VERSION 5.8 ;
BUSBITCHARS "[]" ;
DIVIDERCHAR "/" ;
UNITS
    DATABASE MICRONS 1000 ;
END UNITS

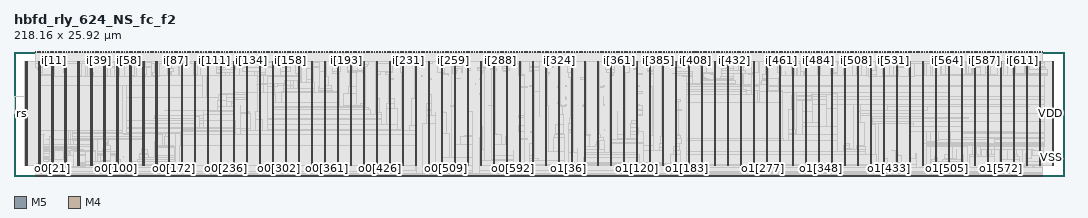
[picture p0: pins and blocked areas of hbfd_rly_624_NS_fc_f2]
MACRO hbfd_rly_624_NS_fc_f2
  FOREIGN hbfd_rly_624_NS_fc_f2 0 0 ;
  CLASS BLOCK ;
  SIZE 218.16 BY 25.92 ;
  PIN clk_in
    DIRECTION INPUT ;
    USE SIGNAL ;
    PORT
      LAYER M5 ;
        RECT  109.056 25.728 109.08 25.92 ;
    END
  END clk_in
  PIN clk_out0
    DIRECTION OUTPUT ;
    USE SIGNAL ;
    PORT
      LAYER M5 ;
        RECT  56.688 0 56.712 0.192 ;
    END
  END clk_out0
  PIN clk_out1
    DIRECTION OUTPUT ;
    USE SIGNAL ;
    PORT
      LAYER M5 ;
        RECT  161.424 0 161.448 0.192 ;
    END
  END clk_out1
  PIN i[0]
    DIRECTION INPUT ;
    USE SIGNAL ;
    PORT
      LAYER M5 ;
        RECT  4.512 25.728 4.536 25.92 ;
    END
  END i[0]
  PIN i[100]
    DIRECTION INPUT ;
    USE SIGNAL ;
    PORT
      LAYER M5 ;
        RECT  38.016 25.728 38.04 25.92 ;
    END
  END i[100]
  PIN i[101]
    DIRECTION INPUT ;
    USE SIGNAL ;
    PORT
      LAYER M5 ;
        RECT  38.352 25.728 38.376 25.92 ;
    END
  END i[101]
  PIN i[102]
    DIRECTION INPUT ;
    USE SIGNAL ;
    PORT
      LAYER M5 ;
        RECT  38.688 25.728 38.712 25.92 ;
    END
  END i[102]
  PIN i[103]
    DIRECTION INPUT ;
    USE SIGNAL ;
    PORT
      LAYER M5 ;
        RECT  39.024 25.728 39.048 25.92 ;
    END
  END i[103]
  PIN i[104]
    DIRECTION INPUT ;
    USE SIGNAL ;
    PORT
      LAYER M5 ;
        RECT  39.36 25.728 39.384 25.92 ;
    END
  END i[104]
  PIN i[105]
    DIRECTION INPUT ;
    USE SIGNAL ;
    PORT
      LAYER M5 ;
        RECT  39.696 25.728 39.72 25.92 ;
    END
  END i[105]
  PIN i[106]
    DIRECTION INPUT ;
    USE SIGNAL ;
    PORT
      LAYER M5 ;
        RECT  40.032 25.728 40.056 25.92 ;
    END
  END i[106]
  PIN i[107]
    DIRECTION INPUT ;
    USE SIGNAL ;
    PORT
      LAYER M5 ;
        RECT  40.368 25.728 40.392 25.92 ;
    END
  END i[107]
  PIN i[108]
    DIRECTION INPUT ;
    USE SIGNAL ;
    PORT
      LAYER M5 ;
        RECT  40.704 25.728 40.728 25.92 ;
    END
  END i[108]
  PIN i[109]
    DIRECTION INPUT ;
    USE SIGNAL ;
    PORT
      LAYER M5 ;
        RECT  41.04 25.728 41.064 25.92 ;
    END
  END i[109]
  PIN i[10]
    DIRECTION INPUT ;
    USE SIGNAL ;
    PORT
      LAYER M5 ;
        RECT  7.872 25.728 7.896 25.92 ;
    END
  END i[10]
  PIN i[110]
    DIRECTION INPUT ;
    USE SIGNAL ;
    PORT
      LAYER M5 ;
        RECT  41.376 25.728 41.4 25.92 ;
    END
  END i[110]
  PIN i[111]
    DIRECTION INPUT ;
    USE SIGNAL ;
    PORT
      LAYER M5 ;
        RECT  41.712 25.728 41.736 25.92 ;
    END
  END i[111]
  PIN i[112]
    DIRECTION INPUT ;
    USE SIGNAL ;
    PORT
      LAYER M5 ;
        RECT  42.048 25.728 42.072 25.92 ;
    END
  END i[112]
  PIN i[113]
    DIRECTION INPUT ;
    USE SIGNAL ;
    PORT
      LAYER M5 ;
        RECT  42.384 25.728 42.408 25.92 ;
    END
  END i[113]
  PIN i[114]
    DIRECTION INPUT ;
    USE SIGNAL ;
    PORT
      LAYER M5 ;
        RECT  42.72 25.728 42.744 25.92 ;
    END
  END i[114]
  PIN i[115]
    DIRECTION INPUT ;
    USE SIGNAL ;
    PORT
      LAYER M5 ;
        RECT  43.056 25.728 43.08 25.92 ;
    END
  END i[115]
  PIN i[116]
    DIRECTION INPUT ;
    USE SIGNAL ;
    PORT
      LAYER M5 ;
        RECT  43.392 25.728 43.416 25.92 ;
    END
  END i[116]
  PIN i[117]
    DIRECTION INPUT ;
    USE SIGNAL ;
    PORT
      LAYER M5 ;
        RECT  43.728 25.728 43.752 25.92 ;
    END
  END i[117]
  PIN i[118]
    DIRECTION INPUT ;
    USE SIGNAL ;
    PORT
      LAYER M5 ;
        RECT  44.064 25.728 44.088 25.92 ;
    END
  END i[118]
  PIN i[119]
    DIRECTION INPUT ;
    USE SIGNAL ;
    PORT
      LAYER M5 ;
        RECT  44.4 25.728 44.424 25.92 ;
    END
  END i[119]
  PIN i[11]
    DIRECTION INPUT ;
    USE SIGNAL ;
    PORT
      LAYER M5 ;
        RECT  8.208 25.728 8.232 25.92 ;
    END
  END i[11]
  PIN i[120]
    DIRECTION INPUT ;
    USE SIGNAL ;
    PORT
      LAYER M5 ;
        RECT  44.736 25.728 44.76 25.92 ;
    END
  END i[120]
  PIN i[121]
    DIRECTION INPUT ;
    USE SIGNAL ;
    PORT
      LAYER M5 ;
        RECT  45.072 25.728 45.096 25.92 ;
    END
  END i[121]
  PIN i[122]
    DIRECTION INPUT ;
    USE SIGNAL ;
    PORT
      LAYER M5 ;
        RECT  45.408 25.728 45.432 25.92 ;
    END
  END i[122]
  PIN i[123]
    DIRECTION INPUT ;
    USE SIGNAL ;
    PORT
      LAYER M5 ;
        RECT  45.744 25.728 45.768 25.92 ;
    END
  END i[123]
  PIN i[124]
    DIRECTION INPUT ;
    USE SIGNAL ;
    PORT
      LAYER M5 ;
        RECT  46.08 25.728 46.104 25.92 ;
    END
  END i[124]
  PIN i[125]
    DIRECTION INPUT ;
    USE SIGNAL ;
    PORT
      LAYER M5 ;
        RECT  46.416 25.728 46.44 25.92 ;
    END
  END i[125]
  PIN i[126]
    DIRECTION INPUT ;
    USE SIGNAL ;
    PORT
      LAYER M5 ;
        RECT  46.752 25.728 46.776 25.92 ;
    END
  END i[126]
  PIN i[127]
    DIRECTION INPUT ;
    USE SIGNAL ;
    PORT
      LAYER M5 ;
        RECT  47.088 25.728 47.112 25.92 ;
    END
  END i[127]
  PIN i[128]
    DIRECTION INPUT ;
    USE SIGNAL ;
    PORT
      LAYER M5 ;
        RECT  47.424 25.728 47.448 25.92 ;
    END
  END i[128]
  PIN i[129]
    DIRECTION INPUT ;
    USE SIGNAL ;
    PORT
      LAYER M5 ;
        RECT  47.76 25.728 47.784 25.92 ;
    END
  END i[129]
  PIN i[12]
    DIRECTION INPUT ;
    USE SIGNAL ;
    PORT
      LAYER M5 ;
        RECT  8.544 25.728 8.568 25.92 ;
    END
  END i[12]
  PIN i[130]
    DIRECTION INPUT ;
    USE SIGNAL ;
    PORT
      LAYER M5 ;
        RECT  48.096 25.728 48.12 25.92 ;
    END
  END i[130]
  PIN i[131]
    DIRECTION INPUT ;
    USE SIGNAL ;
    PORT
      LAYER M5 ;
        RECT  48.432 25.728 48.456 25.92 ;
    END
  END i[131]
  PIN i[132]
    DIRECTION INPUT ;
    USE SIGNAL ;
    PORT
      LAYER M5 ;
        RECT  48.768 25.728 48.792 25.92 ;
    END
  END i[132]
  PIN i[133]
    DIRECTION INPUT ;
    USE SIGNAL ;
    PORT
      LAYER M5 ;
        RECT  49.104 25.728 49.128 25.92 ;
    END
  END i[133]
  PIN i[134]
    DIRECTION INPUT ;
    USE SIGNAL ;
    PORT
      LAYER M5 ;
        RECT  49.392 25.728 49.416 25.92 ;
    END
  END i[134]
  PIN i[135]
    DIRECTION INPUT ;
    USE SIGNAL ;
    PORT
      LAYER M5 ;
        RECT  49.728 25.728 49.752 25.92 ;
    END
  END i[135]
  PIN i[136]
    DIRECTION INPUT ;
    USE SIGNAL ;
    PORT
      LAYER M5 ;
        RECT  50.064 25.728 50.088 25.92 ;
    END
  END i[136]
  PIN i[137]
    DIRECTION INPUT ;
    USE SIGNAL ;
    PORT
      LAYER M5 ;
        RECT  50.4 25.728 50.424 25.92 ;
    END
  END i[137]
  PIN i[138]
    DIRECTION INPUT ;
    USE SIGNAL ;
    PORT
      LAYER M5 ;
        RECT  50.736 25.728 50.76 25.92 ;
    END
  END i[138]
  PIN i[139]
    DIRECTION INPUT ;
    USE SIGNAL ;
    PORT
      LAYER M5 ;
        RECT  51.072 25.728 51.096 25.92 ;
    END
  END i[139]
  PIN i[13]
    DIRECTION INPUT ;
    USE SIGNAL ;
    PORT
      LAYER M5 ;
        RECT  8.88 25.728 8.904 25.92 ;
    END
  END i[13]
  PIN i[140]
    DIRECTION INPUT ;
    USE SIGNAL ;
    PORT
      LAYER M5 ;
        RECT  51.408 25.728 51.432 25.92 ;
    END
  END i[140]
  PIN i[141]
    DIRECTION INPUT ;
    USE SIGNAL ;
    PORT
      LAYER M5 ;
        RECT  51.744 25.728 51.768 25.92 ;
    END
  END i[141]
  PIN i[142]
    DIRECTION INPUT ;
    USE SIGNAL ;
    PORT
      LAYER M5 ;
        RECT  52.08 25.728 52.104 25.92 ;
    END
  END i[142]
  PIN i[143]
    DIRECTION INPUT ;
    USE SIGNAL ;
    PORT
      LAYER M5 ;
        RECT  52.416 25.728 52.44 25.92 ;
    END
  END i[143]
  PIN i[144]
    DIRECTION INPUT ;
    USE SIGNAL ;
    PORT
      LAYER M5 ;
        RECT  52.752 25.728 52.776 25.92 ;
    END
  END i[144]
  PIN i[145]
    DIRECTION INPUT ;
    USE SIGNAL ;
    PORT
      LAYER M5 ;
        RECT  53.088 25.728 53.112 25.92 ;
    END
  END i[145]
  PIN i[146]
    DIRECTION INPUT ;
    USE SIGNAL ;
    PORT
      LAYER M5 ;
        RECT  53.424 25.728 53.448 25.92 ;
    END
  END i[146]
  PIN i[147]
    DIRECTION INPUT ;
    USE SIGNAL ;
    PORT
      LAYER M5 ;
        RECT  53.76 25.728 53.784 25.92 ;
    END
  END i[147]
  PIN i[148]
    DIRECTION INPUT ;
    USE SIGNAL ;
    PORT
      LAYER M5 ;
        RECT  54.096 25.728 54.12 25.92 ;
    END
  END i[148]
  PIN i[149]
    DIRECTION INPUT ;
    USE SIGNAL ;
    PORT
      LAYER M5 ;
        RECT  54.432 25.728 54.456 25.92 ;
    END
  END i[149]
  PIN i[14]
    DIRECTION INPUT ;
    USE SIGNAL ;
    PORT
      LAYER M5 ;
        RECT  9.216 25.728 9.24 25.92 ;
    END
  END i[14]
  PIN i[150]
    DIRECTION INPUT ;
    USE SIGNAL ;
    PORT
      LAYER M5 ;
        RECT  54.768 25.728 54.792 25.92 ;
    END
  END i[150]
  PIN i[151]
    DIRECTION INPUT ;
    USE SIGNAL ;
    PORT
      LAYER M5 ;
        RECT  55.104 25.728 55.128 25.92 ;
    END
  END i[151]
  PIN i[152]
    DIRECTION INPUT ;
    USE SIGNAL ;
    PORT
      LAYER M5 ;
        RECT  55.44 25.728 55.464 25.92 ;
    END
  END i[152]
  PIN i[153]
    DIRECTION INPUT ;
    USE SIGNAL ;
    PORT
      LAYER M5 ;
        RECT  55.776 25.728 55.8 25.92 ;
    END
  END i[153]
  PIN i[154]
    DIRECTION INPUT ;
    USE SIGNAL ;
    PORT
      LAYER M5 ;
        RECT  56.112 25.728 56.136 25.92 ;
    END
  END i[154]
  PIN i[155]
    DIRECTION INPUT ;
    USE SIGNAL ;
    PORT
      LAYER M5 ;
        RECT  56.448 25.728 56.472 25.92 ;
    END
  END i[155]
  PIN i[156]
    DIRECTION INPUT ;
    USE SIGNAL ;
    PORT
      LAYER M5 ;
        RECT  56.784 25.728 56.808 25.92 ;
    END
  END i[156]
  PIN i[157]
    DIRECTION INPUT ;
    USE SIGNAL ;
    PORT
      LAYER M5 ;
        RECT  57.12 25.728 57.144 25.92 ;
    END
  END i[157]
  PIN i[158]
    DIRECTION INPUT ;
    USE SIGNAL ;
    PORT
      LAYER M5 ;
        RECT  57.456 25.728 57.48 25.92 ;
    END
  END i[158]
  PIN i[159]
    DIRECTION INPUT ;
    USE SIGNAL ;
    PORT
      LAYER M5 ;
        RECT  57.792 25.728 57.816 25.92 ;
    END
  END i[159]
  PIN i[15]
    DIRECTION INPUT ;
    USE SIGNAL ;
    PORT
      LAYER M5 ;
        RECT  9.552 25.728 9.576 25.92 ;
    END
  END i[15]
  PIN i[160]
    DIRECTION INPUT ;
    USE SIGNAL ;
    PORT
      LAYER M5 ;
        RECT  58.128 25.728 58.152 25.92 ;
    END
  END i[160]
  PIN i[161]
    DIRECTION INPUT ;
    USE SIGNAL ;
    PORT
      LAYER M5 ;
        RECT  58.464 25.728 58.488 25.92 ;
    END
  END i[161]
  PIN i[162]
    DIRECTION INPUT ;
    USE SIGNAL ;
    PORT
      LAYER M5 ;
        RECT  58.8 25.728 58.824 25.92 ;
    END
  END i[162]
  PIN i[163]
    DIRECTION INPUT ;
    USE SIGNAL ;
    PORT
      LAYER M5 ;
        RECT  59.136 25.728 59.16 25.92 ;
    END
  END i[163]
  PIN i[164]
    DIRECTION INPUT ;
    USE SIGNAL ;
    PORT
      LAYER M5 ;
        RECT  59.472 25.728 59.496 25.92 ;
    END
  END i[164]
  PIN i[165]
    DIRECTION INPUT ;
    USE SIGNAL ;
    PORT
      LAYER M5 ;
        RECT  59.808 25.728 59.832 25.92 ;
    END
  END i[165]
  PIN i[166]
    DIRECTION INPUT ;
    USE SIGNAL ;
    PORT
      LAYER M5 ;
        RECT  60.144 25.728 60.168 25.92 ;
    END
  END i[166]
  PIN i[167]
    DIRECTION INPUT ;
    USE SIGNAL ;
    PORT
      LAYER M5 ;
        RECT  60.48 25.728 60.504 25.92 ;
    END
  END i[167]
  PIN i[168]
    DIRECTION INPUT ;
    USE SIGNAL ;
    PORT
      LAYER M5 ;
        RECT  60.816 25.728 60.84 25.92 ;
    END
  END i[168]
  PIN i[169]
    DIRECTION INPUT ;
    USE SIGNAL ;
    PORT
      LAYER M5 ;
        RECT  61.152 25.728 61.176 25.92 ;
    END
  END i[169]
  PIN i[16]
    DIRECTION INPUT ;
    USE SIGNAL ;
    PORT
      LAYER M5 ;
        RECT  9.888 25.728 9.912 25.92 ;
    END
  END i[16]
  PIN i[170]
    DIRECTION INPUT ;
    USE SIGNAL ;
    PORT
      LAYER M5 ;
        RECT  61.488 25.728 61.512 25.92 ;
    END
  END i[170]
  PIN i[171]
    DIRECTION INPUT ;
    USE SIGNAL ;
    PORT
      LAYER M5 ;
        RECT  61.824 25.728 61.848 25.92 ;
    END
  END i[171]
  PIN i[172]
    DIRECTION INPUT ;
    USE SIGNAL ;
    PORT
      LAYER M5 ;
        RECT  62.16 25.728 62.184 25.92 ;
    END
  END i[172]
  PIN i[173]
    DIRECTION INPUT ;
    USE SIGNAL ;
    PORT
      LAYER M5 ;
        RECT  62.496 25.728 62.52 25.92 ;
    END
  END i[173]
  PIN i[174]
    DIRECTION INPUT ;
    USE SIGNAL ;
    PORT
      LAYER M5 ;
        RECT  62.832 25.728 62.856 25.92 ;
    END
  END i[174]
  PIN i[175]
    DIRECTION INPUT ;
    USE SIGNAL ;
    PORT
      LAYER M5 ;
        RECT  63.168 25.728 63.192 25.92 ;
    END
  END i[175]
  PIN i[176]
    DIRECTION INPUT ;
    USE SIGNAL ;
    PORT
      LAYER M5 ;
        RECT  63.504 25.728 63.528 25.92 ;
    END
  END i[176]
  PIN i[177]
    DIRECTION INPUT ;
    USE SIGNAL ;
    PORT
      LAYER M5 ;
        RECT  63.84 25.728 63.864 25.92 ;
    END
  END i[177]
  PIN i[178]
    DIRECTION INPUT ;
    USE SIGNAL ;
    PORT
      LAYER M5 ;
        RECT  64.176 25.728 64.2 25.92 ;
    END
  END i[178]
  PIN i[179]
    DIRECTION INPUT ;
    USE SIGNAL ;
    PORT
      LAYER M5 ;
        RECT  64.512 25.728 64.536 25.92 ;
    END
  END i[179]
  PIN i[17]
    DIRECTION INPUT ;
    USE SIGNAL ;
    PORT
      LAYER M5 ;
        RECT  10.224 25.728 10.248 25.92 ;
    END
  END i[17]
  PIN i[180]
    DIRECTION INPUT ;
    USE SIGNAL ;
    PORT
      LAYER M5 ;
        RECT  64.848 25.728 64.872 25.92 ;
    END
  END i[180]
  PIN i[181]
    DIRECTION INPUT ;
    USE SIGNAL ;
    PORT
      LAYER M5 ;
        RECT  65.184 25.728 65.208 25.92 ;
    END
  END i[181]
  PIN i[182]
    DIRECTION INPUT ;
    USE SIGNAL ;
    PORT
      LAYER M5 ;
        RECT  65.52 25.728 65.544 25.92 ;
    END
  END i[182]
  PIN i[183]
    DIRECTION INPUT ;
    USE SIGNAL ;
    PORT
      LAYER M5 ;
        RECT  65.856 25.728 65.88 25.92 ;
    END
  END i[183]
  PIN i[184]
    DIRECTION INPUT ;
    USE SIGNAL ;
    PORT
      LAYER M5 ;
        RECT  66.192 25.728 66.216 25.92 ;
    END
  END i[184]
  PIN i[185]
    DIRECTION INPUT ;
    USE SIGNAL ;
    PORT
      LAYER M5 ;
        RECT  66.528 25.728 66.552 25.92 ;
    END
  END i[185]
  PIN i[186]
    DIRECTION INPUT ;
    USE SIGNAL ;
    PORT
      LAYER M5 ;
        RECT  66.864 25.728 66.888 25.92 ;
    END
  END i[186]
  PIN i[187]
    DIRECTION INPUT ;
    USE SIGNAL ;
    PORT
      LAYER M5 ;
        RECT  67.2 25.728 67.224 25.92 ;
    END
  END i[187]
  PIN i[188]
    DIRECTION INPUT ;
    USE SIGNAL ;
    PORT
      LAYER M5 ;
        RECT  67.536 25.728 67.56 25.92 ;
    END
  END i[188]
  PIN i[189]
    DIRECTION INPUT ;
    USE SIGNAL ;
    PORT
      LAYER M5 ;
        RECT  67.824 25.728 67.848 25.92 ;
    END
  END i[189]
  PIN i[18]
    DIRECTION INPUT ;
    USE SIGNAL ;
    PORT
      LAYER M5 ;
        RECT  10.56 25.728 10.584 25.92 ;
    END
  END i[18]
  PIN i[190]
    DIRECTION INPUT ;
    USE SIGNAL ;
    PORT
      LAYER M5 ;
        RECT  68.16 25.728 68.184 25.92 ;
    END
  END i[190]
  PIN i[191]
    DIRECTION INPUT ;
    USE SIGNAL ;
    PORT
      LAYER M5 ;
        RECT  68.496 25.728 68.52 25.92 ;
    END
  END i[191]
  PIN i[192]
    DIRECTION INPUT ;
    USE SIGNAL ;
    PORT
      LAYER M5 ;
        RECT  68.832 25.728 68.856 25.92 ;
    END
  END i[192]
  PIN i[193]
    DIRECTION INPUT ;
    USE SIGNAL ;
    PORT
      LAYER M5 ;
        RECT  69.168 25.728 69.192 25.92 ;
    END
  END i[193]
  PIN i[194]
    DIRECTION INPUT ;
    USE SIGNAL ;
    PORT
      LAYER M5 ;
        RECT  69.504 25.728 69.528 25.92 ;
    END
  END i[194]
  PIN i[195]
    DIRECTION INPUT ;
    USE SIGNAL ;
    PORT
      LAYER M5 ;
        RECT  69.84 25.728 69.864 25.92 ;
    END
  END i[195]
  PIN i[196]
    DIRECTION INPUT ;
    USE SIGNAL ;
    PORT
      LAYER M5 ;
        RECT  70.176 25.728 70.2 25.92 ;
    END
  END i[196]
  PIN i[197]
    DIRECTION INPUT ;
    USE SIGNAL ;
    PORT
      LAYER M5 ;
        RECT  70.512 25.728 70.536 25.92 ;
    END
  END i[197]
  PIN i[198]
    DIRECTION INPUT ;
    USE SIGNAL ;
    PORT
      LAYER M5 ;
        RECT  70.848 25.728 70.872 25.92 ;
    END
  END i[198]
  PIN i[199]
    DIRECTION INPUT ;
    USE SIGNAL ;
    PORT
      LAYER M5 ;
        RECT  71.184 25.728 71.208 25.92 ;
    END
  END i[199]
  PIN i[19]
    DIRECTION INPUT ;
    USE SIGNAL ;
    PORT
      LAYER M5 ;
        RECT  10.896 25.728 10.92 25.92 ;
    END
  END i[19]
  PIN i[1]
    DIRECTION INPUT ;
    USE SIGNAL ;
    PORT
      LAYER M5 ;
        RECT  4.848 25.728 4.872 25.92 ;
    END
  END i[1]
  PIN i[200]
    DIRECTION INPUT ;
    USE SIGNAL ;
    PORT
      LAYER M5 ;
        RECT  71.52 25.728 71.544 25.92 ;
    END
  END i[200]
  PIN i[201]
    DIRECTION INPUT ;
    USE SIGNAL ;
    PORT
      LAYER M5 ;
        RECT  71.856 25.728 71.88 25.92 ;
    END
  END i[201]
  PIN i[202]
    DIRECTION INPUT ;
    USE SIGNAL ;
    PORT
      LAYER M5 ;
        RECT  72.192 25.728 72.216 25.92 ;
    END
  END i[202]
  PIN i[203]
    DIRECTION INPUT ;
    USE SIGNAL ;
    PORT
      LAYER M5 ;
        RECT  72.528 25.728 72.552 25.92 ;
    END
  END i[203]
  PIN i[204]
    DIRECTION INPUT ;
    USE SIGNAL ;
    PORT
      LAYER M5 ;
        RECT  72.864 25.728 72.888 25.92 ;
    END
  END i[204]
  PIN i[205]
    DIRECTION INPUT ;
    USE SIGNAL ;
    PORT
      LAYER M5 ;
        RECT  73.2 25.728 73.224 25.92 ;
    END
  END i[205]
  PIN i[206]
    DIRECTION INPUT ;
    USE SIGNAL ;
    PORT
      LAYER M5 ;
        RECT  73.536 25.728 73.56 25.92 ;
    END
  END i[206]
  PIN i[207]
    DIRECTION INPUT ;
    USE SIGNAL ;
    PORT
      LAYER M5 ;
        RECT  73.872 25.728 73.896 25.92 ;
    END
  END i[207]
  PIN i[208]
    DIRECTION INPUT ;
    USE SIGNAL ;
    PORT
      LAYER M5 ;
        RECT  74.208 25.728 74.232 25.92 ;
    END
  END i[208]
  PIN i[209]
    DIRECTION INPUT ;
    USE SIGNAL ;
    PORT
      LAYER M5 ;
        RECT  74.544 25.728 74.568 25.92 ;
    END
  END i[209]
  PIN i[20]
    DIRECTION INPUT ;
    USE SIGNAL ;
    PORT
      LAYER M5 ;
        RECT  11.232 25.728 11.256 25.92 ;
    END
  END i[20]
  PIN i[210]
    DIRECTION INPUT ;
    USE SIGNAL ;
    PORT
      LAYER M5 ;
        RECT  74.88 25.728 74.904 25.92 ;
    END
  END i[210]
  PIN i[211]
    DIRECTION INPUT ;
    USE SIGNAL ;
    PORT
      LAYER M5 ;
        RECT  75.216 25.728 75.24 25.92 ;
    END
  END i[211]
  PIN i[212]
    DIRECTION INPUT ;
    USE SIGNAL ;
    PORT
      LAYER M5 ;
        RECT  75.552 25.728 75.576 25.92 ;
    END
  END i[212]
  PIN i[213]
    DIRECTION INPUT ;
    USE SIGNAL ;
    PORT
      LAYER M5 ;
        RECT  75.888 25.728 75.912 25.92 ;
    END
  END i[213]
  PIN i[214]
    DIRECTION INPUT ;
    USE SIGNAL ;
    PORT
      LAYER M5 ;
        RECT  76.224 25.728 76.248 25.92 ;
    END
  END i[214]
  PIN i[215]
    DIRECTION INPUT ;
    USE SIGNAL ;
    PORT
      LAYER M5 ;
        RECT  76.56 25.728 76.584 25.92 ;
    END
  END i[215]
  PIN i[216]
    DIRECTION INPUT ;
    USE SIGNAL ;
    PORT
      LAYER M5 ;
        RECT  76.896 25.728 76.92 25.92 ;
    END
  END i[216]
  PIN i[217]
    DIRECTION INPUT ;
    USE SIGNAL ;
    PORT
      LAYER M5 ;
        RECT  77.232 25.728 77.256 25.92 ;
    END
  END i[217]
  PIN i[218]
    DIRECTION INPUT ;
    USE SIGNAL ;
    PORT
      LAYER M5 ;
        RECT  77.568 25.728 77.592 25.92 ;
    END
  END i[218]
  PIN i[219]
    DIRECTION INPUT ;
    USE SIGNAL ;
    PORT
      LAYER M5 ;
        RECT  77.904 25.728 77.928 25.92 ;
    END
  END i[219]
  PIN i[21]
    DIRECTION INPUT ;
    USE SIGNAL ;
    PORT
      LAYER M5 ;
        RECT  11.568 25.728 11.592 25.92 ;
    END
  END i[21]
  PIN i[220]
    DIRECTION INPUT ;
    USE SIGNAL ;
    PORT
      LAYER M5 ;
        RECT  78.24 25.728 78.264 25.92 ;
    END
  END i[220]
  PIN i[221]
    DIRECTION INPUT ;
    USE SIGNAL ;
    PORT
      LAYER M5 ;
        RECT  78.576 25.728 78.6 25.92 ;
    END
  END i[221]
  PIN i[222]
    DIRECTION INPUT ;
    USE SIGNAL ;
    PORT
      LAYER M5 ;
        RECT  78.912 25.728 78.936 25.92 ;
    END
  END i[222]
  PIN i[223]
    DIRECTION INPUT ;
    USE SIGNAL ;
    PORT
      LAYER M5 ;
        RECT  79.248 25.728 79.272 25.92 ;
    END
  END i[223]
  PIN i[224]
    DIRECTION INPUT ;
    USE SIGNAL ;
    PORT
      LAYER M5 ;
        RECT  79.584 25.728 79.608 25.92 ;
    END
  END i[224]
  PIN i[225]
    DIRECTION INPUT ;
    USE SIGNAL ;
    PORT
      LAYER M5 ;
        RECT  79.92 25.728 79.944 25.92 ;
    END
  END i[225]
  PIN i[226]
    DIRECTION INPUT ;
    USE SIGNAL ;
    PORT
      LAYER M5 ;
        RECT  80.256 25.728 80.28 25.92 ;
    END
  END i[226]
  PIN i[227]
    DIRECTION INPUT ;
    USE SIGNAL ;
    PORT
      LAYER M5 ;
        RECT  80.592 25.728 80.616 25.92 ;
    END
  END i[227]
  PIN i[228]
    DIRECTION INPUT ;
    USE SIGNAL ;
    PORT
      LAYER M5 ;
        RECT  80.928 25.728 80.952 25.92 ;
    END
  END i[228]
  PIN i[229]
    DIRECTION INPUT ;
    USE SIGNAL ;
    PORT
      LAYER M5 ;
        RECT  81.264 25.728 81.288 25.92 ;
    END
  END i[229]
  PIN i[22]
    DIRECTION INPUT ;
    USE SIGNAL ;
    PORT
      LAYER M5 ;
        RECT  11.904 25.728 11.928 25.92 ;
    END
  END i[22]
  PIN i[230]
    DIRECTION INPUT ;
    USE SIGNAL ;
    PORT
      LAYER M5 ;
        RECT  81.6 25.728 81.624 25.92 ;
    END
  END i[230]
  PIN i[231]
    DIRECTION INPUT ;
    USE SIGNAL ;
    PORT
      LAYER M5 ;
        RECT  81.936 25.728 81.96 25.92 ;
    END
  END i[231]
  PIN i[232]
    DIRECTION INPUT ;
    USE SIGNAL ;
    PORT
      LAYER M5 ;
        RECT  82.272 25.728 82.296 25.92 ;
    END
  END i[232]
  PIN i[233]
    DIRECTION INPUT ;
    USE SIGNAL ;
    PORT
      LAYER M5 ;
        RECT  82.608 25.728 82.632 25.92 ;
    END
  END i[233]
  PIN i[234]
    DIRECTION INPUT ;
    USE SIGNAL ;
    PORT
      LAYER M5 ;
        RECT  82.944 25.728 82.968 25.92 ;
    END
  END i[234]
  PIN i[235]
    DIRECTION INPUT ;
    USE SIGNAL ;
    PORT
      LAYER M5 ;
        RECT  83.28 25.728 83.304 25.92 ;
    END
  END i[235]
  PIN i[236]
    DIRECTION INPUT ;
    USE SIGNAL ;
    PORT
      LAYER M5 ;
        RECT  83.616 25.728 83.64 25.92 ;
    END
  END i[236]
  PIN i[237]
    DIRECTION INPUT ;
    USE SIGNAL ;
    PORT
      LAYER M5 ;
        RECT  83.952 25.728 83.976 25.92 ;
    END
  END i[237]
  PIN i[238]
    DIRECTION INPUT ;
    USE SIGNAL ;
    PORT
      LAYER M5 ;
        RECT  84.288 25.728 84.312 25.92 ;
    END
  END i[238]
  PIN i[239]
    DIRECTION INPUT ;
    USE SIGNAL ;
    PORT
      LAYER M5 ;
        RECT  84.624 25.728 84.648 25.92 ;
    END
  END i[239]
  PIN i[23]
    DIRECTION INPUT ;
    USE SIGNAL ;
    PORT
      LAYER M5 ;
        RECT  12.192 25.728 12.216 25.92 ;
    END
  END i[23]
  PIN i[240]
    DIRECTION INPUT ;
    USE SIGNAL ;
    PORT
      LAYER M5 ;
        RECT  84.96 25.728 84.984 25.92 ;
    END
  END i[240]
  PIN i[241]
    DIRECTION INPUT ;
    USE SIGNAL ;
    PORT
      LAYER M5 ;
        RECT  85.296 25.728 85.32 25.92 ;
    END
  END i[241]
  PIN i[242]
    DIRECTION INPUT ;
    USE SIGNAL ;
    PORT
      LAYER M5 ;
        RECT  85.632 25.728 85.656 25.92 ;
    END
  END i[242]
  PIN i[243]
    DIRECTION INPUT ;
    USE SIGNAL ;
    PORT
      LAYER M5 ;
        RECT  85.968 25.728 85.992 25.92 ;
    END
  END i[243]
  PIN i[244]
    DIRECTION INPUT ;
    USE SIGNAL ;
    PORT
      LAYER M5 ;
        RECT  86.256 25.728 86.28 25.92 ;
    END
  END i[244]
  PIN i[245]
    DIRECTION INPUT ;
    USE SIGNAL ;
    PORT
      LAYER M5 ;
        RECT  86.592 25.728 86.616 25.92 ;
    END
  END i[245]
  PIN i[246]
    DIRECTION INPUT ;
    USE SIGNAL ;
    PORT
      LAYER M5 ;
        RECT  86.928 25.728 86.952 25.92 ;
    END
  END i[246]
  PIN i[247]
    DIRECTION INPUT ;
    USE SIGNAL ;
    PORT
      LAYER M5 ;
        RECT  87.264 25.728 87.288 25.92 ;
    END
  END i[247]
  PIN i[248]
    DIRECTION INPUT ;
    USE SIGNAL ;
    PORT
      LAYER M5 ;
        RECT  87.6 25.728 87.624 25.92 ;
    END
  END i[248]
  PIN i[249]
    DIRECTION INPUT ;
    USE SIGNAL ;
    PORT
      LAYER M5 ;
        RECT  87.936 25.728 87.96 25.92 ;
    END
  END i[249]
  PIN i[24]
    DIRECTION INPUT ;
    USE SIGNAL ;
    PORT
      LAYER M5 ;
        RECT  12.528 25.728 12.552 25.92 ;
    END
  END i[24]
  PIN i[250]
    DIRECTION INPUT ;
    USE SIGNAL ;
    PORT
      LAYER M5 ;
        RECT  88.272 25.728 88.296 25.92 ;
    END
  END i[250]
  PIN i[251]
    DIRECTION INPUT ;
    USE SIGNAL ;
    PORT
      LAYER M5 ;
        RECT  88.608 25.728 88.632 25.92 ;
    END
  END i[251]
  PIN i[252]
    DIRECTION INPUT ;
    USE SIGNAL ;
    PORT
      LAYER M5 ;
        RECT  88.944 25.728 88.968 25.92 ;
    END
  END i[252]
  PIN i[253]
    DIRECTION INPUT ;
    USE SIGNAL ;
    PORT
      LAYER M5 ;
        RECT  89.28 25.728 89.304 25.92 ;
    END
  END i[253]
  PIN i[254]
    DIRECTION INPUT ;
    USE SIGNAL ;
    PORT
      LAYER M5 ;
        RECT  89.616 25.728 89.64 25.92 ;
    END
  END i[254]
  PIN i[255]
    DIRECTION INPUT ;
    USE SIGNAL ;
    PORT
      LAYER M5 ;
        RECT  89.952 25.728 89.976 25.92 ;
    END
  END i[255]
  PIN i[256]
    DIRECTION INPUT ;
    USE SIGNAL ;
    PORT
      LAYER M5 ;
        RECT  90.288 25.728 90.312 25.92 ;
    END
  END i[256]
  PIN i[257]
    DIRECTION INPUT ;
    USE SIGNAL ;
    PORT
      LAYER M5 ;
        RECT  90.624 25.728 90.648 25.92 ;
    END
  END i[257]
  PIN i[258]
    DIRECTION INPUT ;
    USE SIGNAL ;
    PORT
      LAYER M5 ;
        RECT  90.96 25.728 90.984 25.92 ;
    END
  END i[258]
  PIN i[259]
    DIRECTION INPUT ;
    USE SIGNAL ;
    PORT
      LAYER M5 ;
        RECT  91.296 25.728 91.32 25.92 ;
    END
  END i[259]
  PIN i[25]
    DIRECTION INPUT ;
    USE SIGNAL ;
    PORT
      LAYER M5 ;
        RECT  12.864 25.728 12.888 25.92 ;
    END
  END i[25]
  PIN i[260]
    DIRECTION INPUT ;
    USE SIGNAL ;
    PORT
      LAYER M5 ;
        RECT  91.632 25.728 91.656 25.92 ;
    END
  END i[260]
  PIN i[261]
    DIRECTION INPUT ;
    USE SIGNAL ;
    PORT
      LAYER M5 ;
        RECT  91.968 25.728 91.992 25.92 ;
    END
  END i[261]
  PIN i[262]
    DIRECTION INPUT ;
    USE SIGNAL ;
    PORT
      LAYER M5 ;
        RECT  92.304 25.728 92.328 25.92 ;
    END
  END i[262]
  PIN i[263]
    DIRECTION INPUT ;
    USE SIGNAL ;
    PORT
      LAYER M5 ;
        RECT  92.64 25.728 92.664 25.92 ;
    END
  END i[263]
  PIN i[264]
    DIRECTION INPUT ;
    USE SIGNAL ;
    PORT
      LAYER M5 ;
        RECT  92.976 25.728 93 25.92 ;
    END
  END i[264]
  PIN i[265]
    DIRECTION INPUT ;
    USE SIGNAL ;
    PORT
      LAYER M5 ;
        RECT  93.312 25.728 93.336 25.92 ;
    END
  END i[265]
  PIN i[266]
    DIRECTION INPUT ;
    USE SIGNAL ;
    PORT
      LAYER M5 ;
        RECT  93.648 25.728 93.672 25.92 ;
    END
  END i[266]
  PIN i[267]
    DIRECTION INPUT ;
    USE SIGNAL ;
    PORT
      LAYER M5 ;
        RECT  93.984 25.728 94.008 25.92 ;
    END
  END i[267]
  PIN i[268]
    DIRECTION INPUT ;
    USE SIGNAL ;
    PORT
      LAYER M5 ;
        RECT  94.32 25.728 94.344 25.92 ;
    END
  END i[268]
  PIN i[269]
    DIRECTION INPUT ;
    USE SIGNAL ;
    PORT
      LAYER M5 ;
        RECT  94.656 25.728 94.68 25.92 ;
    END
  END i[269]
  PIN i[26]
    DIRECTION INPUT ;
    USE SIGNAL ;
    PORT
      LAYER M5 ;
        RECT  13.2 25.728 13.224 25.92 ;
    END
  END i[26]
  PIN i[270]
    DIRECTION INPUT ;
    USE SIGNAL ;
    PORT
      LAYER M5 ;
        RECT  94.992 25.728 95.016 25.92 ;
    END
  END i[270]
  PIN i[271]
    DIRECTION INPUT ;
    USE SIGNAL ;
    PORT
      LAYER M5 ;
        RECT  95.328 25.728 95.352 25.92 ;
    END
  END i[271]
  PIN i[272]
    DIRECTION INPUT ;
    USE SIGNAL ;
    PORT
      LAYER M5 ;
        RECT  95.664 25.728 95.688 25.92 ;
    END
  END i[272]
  PIN i[273]
    DIRECTION INPUT ;
    USE SIGNAL ;
    PORT
      LAYER M5 ;
        RECT  96 25.728 96.024 25.92 ;
    END
  END i[273]
  PIN i[274]
    DIRECTION INPUT ;
    USE SIGNAL ;
    PORT
      LAYER M5 ;
        RECT  96.336 25.728 96.36 25.92 ;
    END
  END i[274]
  PIN i[275]
    DIRECTION INPUT ;
    USE SIGNAL ;
    PORT
      LAYER M5 ;
        RECT  96.672 25.728 96.696 25.92 ;
    END
  END i[275]
  PIN i[276]
    DIRECTION INPUT ;
    USE SIGNAL ;
    PORT
      LAYER M5 ;
        RECT  97.008 25.728 97.032 25.92 ;
    END
  END i[276]
  PIN i[277]
    DIRECTION INPUT ;
    USE SIGNAL ;
    PORT
      LAYER M5 ;
        RECT  97.344 25.728 97.368 25.92 ;
    END
  END i[277]
  PIN i[278]
    DIRECTION INPUT ;
    USE SIGNAL ;
    PORT
      LAYER M5 ;
        RECT  97.68 25.728 97.704 25.92 ;
    END
  END i[278]
  PIN i[279]
    DIRECTION INPUT ;
    USE SIGNAL ;
    PORT
      LAYER M5 ;
        RECT  98.016 25.728 98.04 25.92 ;
    END
  END i[279]
  PIN i[27]
    DIRECTION INPUT ;
    USE SIGNAL ;
    PORT
      LAYER M5 ;
        RECT  13.536 25.728 13.56 25.92 ;
    END
  END i[27]
  PIN i[280]
    DIRECTION INPUT ;
    USE SIGNAL ;
    PORT
      LAYER M5 ;
        RECT  98.352 25.728 98.376 25.92 ;
    END
  END i[280]
  PIN i[281]
    DIRECTION INPUT ;
    USE SIGNAL ;
    PORT
      LAYER M5 ;
        RECT  98.688 25.728 98.712 25.92 ;
    END
  END i[281]
  PIN i[282]
    DIRECTION INPUT ;
    USE SIGNAL ;
    PORT
      LAYER M5 ;
        RECT  99.024 25.728 99.048 25.92 ;
    END
  END i[282]
  PIN i[283]
    DIRECTION INPUT ;
    USE SIGNAL ;
    PORT
      LAYER M5 ;
        RECT  99.36 25.728 99.384 25.92 ;
    END
  END i[283]
  PIN i[284]
    DIRECTION INPUT ;
    USE SIGNAL ;
    PORT
      LAYER M5 ;
        RECT  99.696 25.728 99.72 25.92 ;
    END
  END i[284]
  PIN i[285]
    DIRECTION INPUT ;
    USE SIGNAL ;
    PORT
      LAYER M5 ;
        RECT  100.032 25.728 100.056 25.92 ;
    END
  END i[285]
  PIN i[286]
    DIRECTION INPUT ;
    USE SIGNAL ;
    PORT
      LAYER M5 ;
        RECT  100.368 25.728 100.392 25.92 ;
    END
  END i[286]
  PIN i[287]
    DIRECTION INPUT ;
    USE SIGNAL ;
    PORT
      LAYER M5 ;
        RECT  100.704 25.728 100.728 25.92 ;
    END
  END i[287]
  PIN i[288]
    DIRECTION INPUT ;
    USE SIGNAL ;
    PORT
      LAYER M5 ;
        RECT  101.04 25.728 101.064 25.92 ;
    END
  END i[288]
  PIN i[289]
    DIRECTION INPUT ;
    USE SIGNAL ;
    PORT
      LAYER M5 ;
        RECT  101.376 25.728 101.4 25.92 ;
    END
  END i[289]
  PIN i[28]
    DIRECTION INPUT ;
    USE SIGNAL ;
    PORT
      LAYER M5 ;
        RECT  13.872 25.728 13.896 25.92 ;
    END
  END i[28]
  PIN i[290]
    DIRECTION INPUT ;
    USE SIGNAL ;
    PORT
      LAYER M5 ;
        RECT  101.712 25.728 101.736 25.92 ;
    END
  END i[290]
  PIN i[291]
    DIRECTION INPUT ;
    USE SIGNAL ;
    PORT
      LAYER M5 ;
        RECT  102.048 25.728 102.072 25.92 ;
    END
  END i[291]
  PIN i[292]
    DIRECTION INPUT ;
    USE SIGNAL ;
    PORT
      LAYER M5 ;
        RECT  102.384 25.728 102.408 25.92 ;
    END
  END i[292]
  PIN i[293]
    DIRECTION INPUT ;
    USE SIGNAL ;
    PORT
      LAYER M5 ;
        RECT  102.72 25.728 102.744 25.92 ;
    END
  END i[293]
  PIN i[294]
    DIRECTION INPUT ;
    USE SIGNAL ;
    PORT
      LAYER M5 ;
        RECT  103.056 25.728 103.08 25.92 ;
    END
  END i[294]
  PIN i[295]
    DIRECTION INPUT ;
    USE SIGNAL ;
    PORT
      LAYER M5 ;
        RECT  103.392 25.728 103.416 25.92 ;
    END
  END i[295]
  PIN i[296]
    DIRECTION INPUT ;
    USE SIGNAL ;
    PORT
      LAYER M5 ;
        RECT  103.728 25.728 103.752 25.92 ;
    END
  END i[296]
  PIN i[297]
    DIRECTION INPUT ;
    USE SIGNAL ;
    PORT
      LAYER M5 ;
        RECT  104.064 25.728 104.088 25.92 ;
    END
  END i[297]
  PIN i[298]
    DIRECTION INPUT ;
    USE SIGNAL ;
    PORT
      LAYER M5 ;
        RECT  104.4 25.728 104.424 25.92 ;
    END
  END i[298]
  PIN i[299]
    DIRECTION INPUT ;
    USE SIGNAL ;
    PORT
      LAYER M5 ;
        RECT  104.688 25.728 104.712 25.92 ;
    END
  END i[299]
  PIN i[29]
    DIRECTION INPUT ;
    USE SIGNAL ;
    PORT
      LAYER M5 ;
        RECT  14.208 25.728 14.232 25.92 ;
    END
  END i[29]
  PIN i[2]
    DIRECTION INPUT ;
    USE SIGNAL ;
    PORT
      LAYER M5 ;
        RECT  5.184 25.728 5.208 25.92 ;
    END
  END i[2]
  PIN i[300]
    DIRECTION INPUT ;
    USE SIGNAL ;
    PORT
      LAYER M5 ;
        RECT  105.024 25.728 105.048 25.92 ;
    END
  END i[300]
  PIN i[301]
    DIRECTION INPUT ;
    USE SIGNAL ;
    PORT
      LAYER M5 ;
        RECT  105.36 25.728 105.384 25.92 ;
    END
  END i[301]
  PIN i[302]
    DIRECTION INPUT ;
    USE SIGNAL ;
    PORT
      LAYER M5 ;
        RECT  105.696 25.728 105.72 25.92 ;
    END
  END i[302]
  PIN i[303]
    DIRECTION INPUT ;
    USE SIGNAL ;
    PORT
      LAYER M5 ;
        RECT  106.032 25.728 106.056 25.92 ;
    END
  END i[303]
  PIN i[304]
    DIRECTION INPUT ;
    USE SIGNAL ;
    PORT
      LAYER M5 ;
        RECT  106.368 25.728 106.392 25.92 ;
    END
  END i[304]
  PIN i[305]
    DIRECTION INPUT ;
    USE SIGNAL ;
    PORT
      LAYER M5 ;
        RECT  106.704 25.728 106.728 25.92 ;
    END
  END i[305]
  PIN i[306]
    DIRECTION INPUT ;
    USE SIGNAL ;
    PORT
      LAYER M5 ;
        RECT  107.04 25.728 107.064 25.92 ;
    END
  END i[306]
  PIN i[307]
    DIRECTION INPUT ;
    USE SIGNAL ;
    PORT
      LAYER M5 ;
        RECT  107.376 25.728 107.4 25.92 ;
    END
  END i[307]
  PIN i[308]
    DIRECTION INPUT ;
    USE SIGNAL ;
    PORT
      LAYER M5 ;
        RECT  107.712 25.728 107.736 25.92 ;
    END
  END i[308]
  PIN i[309]
    DIRECTION INPUT ;
    USE SIGNAL ;
    PORT
      LAYER M5 ;
        RECT  108.048 25.728 108.072 25.92 ;
    END
  END i[309]
  PIN i[30]
    DIRECTION INPUT ;
    USE SIGNAL ;
    PORT
      LAYER M5 ;
        RECT  14.544 25.728 14.568 25.92 ;
    END
  END i[30]
  PIN i[310]
    DIRECTION INPUT ;
    USE SIGNAL ;
    PORT
      LAYER M5 ;
        RECT  108.384 25.728 108.408 25.92 ;
    END
  END i[310]
  PIN i[311]
    DIRECTION INPUT ;
    USE SIGNAL ;
    PORT
      LAYER M5 ;
        RECT  108.72 25.728 108.744 25.92 ;
    END
  END i[311]
  PIN i[312]
    DIRECTION INPUT ;
    USE SIGNAL ;
    PORT
      LAYER M5 ;
        RECT  109.392 25.728 109.416 25.92 ;
    END
  END i[312]
  PIN i[313]
    DIRECTION INPUT ;
    USE SIGNAL ;
    PORT
      LAYER M5 ;
        RECT  109.728 25.728 109.752 25.92 ;
    END
  END i[313]
  PIN i[314]
    DIRECTION INPUT ;
    USE SIGNAL ;
    PORT
      LAYER M5 ;
        RECT  110.064 25.728 110.088 25.92 ;
    END
  END i[314]
  PIN i[315]
    DIRECTION INPUT ;
    USE SIGNAL ;
    PORT
      LAYER M5 ;
        RECT  110.4 25.728 110.424 25.92 ;
    END
  END i[315]
  PIN i[316]
    DIRECTION INPUT ;
    USE SIGNAL ;
    PORT
      LAYER M5 ;
        RECT  110.736 25.728 110.76 25.92 ;
    END
  END i[316]
  PIN i[317]
    DIRECTION INPUT ;
    USE SIGNAL ;
    PORT
      LAYER M5 ;
        RECT  111.072 25.728 111.096 25.92 ;
    END
  END i[317]
  PIN i[318]
    DIRECTION INPUT ;
    USE SIGNAL ;
    PORT
      LAYER M5 ;
        RECT  111.408 25.728 111.432 25.92 ;
    END
  END i[318]
  PIN i[319]
    DIRECTION INPUT ;
    USE SIGNAL ;
    PORT
      LAYER M5 ;
        RECT  111.744 25.728 111.768 25.92 ;
    END
  END i[319]
  PIN i[31]
    DIRECTION INPUT ;
    USE SIGNAL ;
    PORT
      LAYER M5 ;
        RECT  14.88 25.728 14.904 25.92 ;
    END
  END i[31]
  PIN i[320]
    DIRECTION INPUT ;
    USE SIGNAL ;
    PORT
      LAYER M5 ;
        RECT  112.08 25.728 112.104 25.92 ;
    END
  END i[320]
  PIN i[321]
    DIRECTION INPUT ;
    USE SIGNAL ;
    PORT
      LAYER M5 ;
        RECT  112.416 25.728 112.44 25.92 ;
    END
  END i[321]
  PIN i[322]
    DIRECTION INPUT ;
    USE SIGNAL ;
    PORT
      LAYER M5 ;
        RECT  112.752 25.728 112.776 25.92 ;
    END
  END i[322]
  PIN i[323]
    DIRECTION INPUT ;
    USE SIGNAL ;
    PORT
      LAYER M5 ;
        RECT  113.088 25.728 113.112 25.92 ;
    END
  END i[323]
  PIN i[324]
    DIRECTION INPUT ;
    USE SIGNAL ;
    PORT
      LAYER M5 ;
        RECT  113.424 25.728 113.448 25.92 ;
    END
  END i[324]
  PIN i[325]
    DIRECTION INPUT ;
    USE SIGNAL ;
    PORT
      LAYER M5 ;
        RECT  113.76 25.728 113.784 25.92 ;
    END
  END i[325]
  PIN i[326]
    DIRECTION INPUT ;
    USE SIGNAL ;
    PORT
      LAYER M5 ;
        RECT  114.096 25.728 114.12 25.92 ;
    END
  END i[326]
  PIN i[327]
    DIRECTION INPUT ;
    USE SIGNAL ;
    PORT
      LAYER M5 ;
        RECT  114.432 25.728 114.456 25.92 ;
    END
  END i[327]
  PIN i[328]
    DIRECTION INPUT ;
    USE SIGNAL ;
    PORT
      LAYER M5 ;
        RECT  114.768 25.728 114.792 25.92 ;
    END
  END i[328]
  PIN i[329]
    DIRECTION INPUT ;
    USE SIGNAL ;
    PORT
      LAYER M5 ;
        RECT  115.104 25.728 115.128 25.92 ;
    END
  END i[329]
  PIN i[32]
    DIRECTION INPUT ;
    USE SIGNAL ;
    PORT
      LAYER M5 ;
        RECT  15.216 25.728 15.24 25.92 ;
    END
  END i[32]
  PIN i[330]
    DIRECTION INPUT ;
    USE SIGNAL ;
    PORT
      LAYER M5 ;
        RECT  115.44 25.728 115.464 25.92 ;
    END
  END i[330]
  PIN i[331]
    DIRECTION INPUT ;
    USE SIGNAL ;
    PORT
      LAYER M5 ;
        RECT  115.776 25.728 115.8 25.92 ;
    END
  END i[331]
  PIN i[332]
    DIRECTION INPUT ;
    USE SIGNAL ;
    PORT
      LAYER M5 ;
        RECT  116.112 25.728 116.136 25.92 ;
    END
  END i[332]
  PIN i[333]
    DIRECTION INPUT ;
    USE SIGNAL ;
    PORT
      LAYER M5 ;
        RECT  116.448 25.728 116.472 25.92 ;
    END
  END i[333]
  PIN i[334]
    DIRECTION INPUT ;
    USE SIGNAL ;
    PORT
      LAYER M5 ;
        RECT  116.784 25.728 116.808 25.92 ;
    END
  END i[334]
  PIN i[335]
    DIRECTION INPUT ;
    USE SIGNAL ;
    PORT
      LAYER M5 ;
        RECT  117.12 25.728 117.144 25.92 ;
    END
  END i[335]
  PIN i[336]
    DIRECTION INPUT ;
    USE SIGNAL ;
    PORT
      LAYER M5 ;
        RECT  117.456 25.728 117.48 25.92 ;
    END
  END i[336]
  PIN i[337]
    DIRECTION INPUT ;
    USE SIGNAL ;
    PORT
      LAYER M5 ;
        RECT  117.792 25.728 117.816 25.92 ;
    END
  END i[337]
  PIN i[338]
    DIRECTION INPUT ;
    USE SIGNAL ;
    PORT
      LAYER M5 ;
        RECT  118.128 25.728 118.152 25.92 ;
    END
  END i[338]
  PIN i[339]
    DIRECTION INPUT ;
    USE SIGNAL ;
    PORT
      LAYER M5 ;
        RECT  118.464 25.728 118.488 25.92 ;
    END
  END i[339]
  PIN i[33]
    DIRECTION INPUT ;
    USE SIGNAL ;
    PORT
      LAYER M5 ;
        RECT  15.552 25.728 15.576 25.92 ;
    END
  END i[33]
  PIN i[340]
    DIRECTION INPUT ;
    USE SIGNAL ;
    PORT
      LAYER M5 ;
        RECT  118.8 25.728 118.824 25.92 ;
    END
  END i[340]
  PIN i[341]
    DIRECTION INPUT ;
    USE SIGNAL ;
    PORT
      LAYER M5 ;
        RECT  119.136 25.728 119.16 25.92 ;
    END
  END i[341]
  PIN i[342]
    DIRECTION INPUT ;
    USE SIGNAL ;
    PORT
      LAYER M5 ;
        RECT  119.472 25.728 119.496 25.92 ;
    END
  END i[342]
  PIN i[343]
    DIRECTION INPUT ;
    USE SIGNAL ;
    PORT
      LAYER M5 ;
        RECT  119.808 25.728 119.832 25.92 ;
    END
  END i[343]
  PIN i[344]
    DIRECTION INPUT ;
    USE SIGNAL ;
    PORT
      LAYER M5 ;
        RECT  120.144 25.728 120.168 25.92 ;
    END
  END i[344]
  PIN i[345]
    DIRECTION INPUT ;
    USE SIGNAL ;
    PORT
      LAYER M5 ;
        RECT  120.48 25.728 120.504 25.92 ;
    END
  END i[345]
  PIN i[346]
    DIRECTION INPUT ;
    USE SIGNAL ;
    PORT
      LAYER M5 ;
        RECT  120.816 25.728 120.84 25.92 ;
    END
  END i[346]
  PIN i[347]
    DIRECTION INPUT ;
    USE SIGNAL ;
    PORT
      LAYER M5 ;
        RECT  121.152 25.728 121.176 25.92 ;
    END
  END i[347]
  PIN i[348]
    DIRECTION INPUT ;
    USE SIGNAL ;
    PORT
      LAYER M5 ;
        RECT  121.488 25.728 121.512 25.92 ;
    END
  END i[348]
  PIN i[349]
    DIRECTION INPUT ;
    USE SIGNAL ;
    PORT
      LAYER M5 ;
        RECT  121.824 25.728 121.848 25.92 ;
    END
  END i[349]
  PIN i[34]
    DIRECTION INPUT ;
    USE SIGNAL ;
    PORT
      LAYER M5 ;
        RECT  15.888 25.728 15.912 25.92 ;
    END
  END i[34]
  PIN i[350]
    DIRECTION INPUT ;
    USE SIGNAL ;
    PORT
      LAYER M5 ;
        RECT  122.16 25.728 122.184 25.92 ;
    END
  END i[350]
  PIN i[351]
    DIRECTION INPUT ;
    USE SIGNAL ;
    PORT
      LAYER M5 ;
        RECT  122.496 25.728 122.52 25.92 ;
    END
  END i[351]
  PIN i[352]
    DIRECTION INPUT ;
    USE SIGNAL ;
    PORT
      LAYER M5 ;
        RECT  122.832 25.728 122.856 25.92 ;
    END
  END i[352]
  PIN i[353]
    DIRECTION INPUT ;
    USE SIGNAL ;
    PORT
      LAYER M5 ;
        RECT  123.12 25.728 123.144 25.92 ;
    END
  END i[353]
  PIN i[354]
    DIRECTION INPUT ;
    USE SIGNAL ;
    PORT
      LAYER M5 ;
        RECT  123.456 25.728 123.48 25.92 ;
    END
  END i[354]
  PIN i[355]
    DIRECTION INPUT ;
    USE SIGNAL ;
    PORT
      LAYER M5 ;
        RECT  123.792 25.728 123.816 25.92 ;
    END
  END i[355]
  PIN i[356]
    DIRECTION INPUT ;
    USE SIGNAL ;
    PORT
      LAYER M5 ;
        RECT  124.128 25.728 124.152 25.92 ;
    END
  END i[356]
  PIN i[357]
    DIRECTION INPUT ;
    USE SIGNAL ;
    PORT
      LAYER M5 ;
        RECT  124.464 25.728 124.488 25.92 ;
    END
  END i[357]
  PIN i[358]
    DIRECTION INPUT ;
    USE SIGNAL ;
    PORT
      LAYER M5 ;
        RECT  124.8 25.728 124.824 25.92 ;
    END
  END i[358]
  PIN i[359]
    DIRECTION INPUT ;
    USE SIGNAL ;
    PORT
      LAYER M5 ;
        RECT  125.136 25.728 125.16 25.92 ;
    END
  END i[359]
  PIN i[35]
    DIRECTION INPUT ;
    USE SIGNAL ;
    PORT
      LAYER M5 ;
        RECT  16.224 25.728 16.248 25.92 ;
    END
  END i[35]
  PIN i[360]
    DIRECTION INPUT ;
    USE SIGNAL ;
    PORT
      LAYER M5 ;
        RECT  125.472 25.728 125.496 25.92 ;
    END
  END i[360]
  PIN i[361]
    DIRECTION INPUT ;
    USE SIGNAL ;
    PORT
      LAYER M5 ;
        RECT  125.808 25.728 125.832 25.92 ;
    END
  END i[361]
  PIN i[362]
    DIRECTION INPUT ;
    USE SIGNAL ;
    PORT
      LAYER M5 ;
        RECT  126.144 25.728 126.168 25.92 ;
    END
  END i[362]
  PIN i[363]
    DIRECTION INPUT ;
    USE SIGNAL ;
    PORT
      LAYER M5 ;
        RECT  126.48 25.728 126.504 25.92 ;
    END
  END i[363]
  PIN i[364]
    DIRECTION INPUT ;
    USE SIGNAL ;
    PORT
      LAYER M5 ;
        RECT  126.816 25.728 126.84 25.92 ;
    END
  END i[364]
  PIN i[365]
    DIRECTION INPUT ;
    USE SIGNAL ;
    PORT
      LAYER M5 ;
        RECT  127.152 25.728 127.176 25.92 ;
    END
  END i[365]
  PIN i[366]
    DIRECTION INPUT ;
    USE SIGNAL ;
    PORT
      LAYER M5 ;
        RECT  127.488 25.728 127.512 25.92 ;
    END
  END i[366]
  PIN i[367]
    DIRECTION INPUT ;
    USE SIGNAL ;
    PORT
      LAYER M5 ;
        RECT  127.824 25.728 127.848 25.92 ;
    END
  END i[367]
  PIN i[368]
    DIRECTION INPUT ;
    USE SIGNAL ;
    PORT
      LAYER M5 ;
        RECT  128.16 25.728 128.184 25.92 ;
    END
  END i[368]
  PIN i[369]
    DIRECTION INPUT ;
    USE SIGNAL ;
    PORT
      LAYER M5 ;
        RECT  128.496 25.728 128.52 25.92 ;
    END
  END i[369]
  PIN i[36]
    DIRECTION INPUT ;
    USE SIGNAL ;
    PORT
      LAYER M5 ;
        RECT  16.56 25.728 16.584 25.92 ;
    END
  END i[36]
  PIN i[370]
    DIRECTION INPUT ;
    USE SIGNAL ;
    PORT
      LAYER M5 ;
        RECT  128.832 25.728 128.856 25.92 ;
    END
  END i[370]
  PIN i[371]
    DIRECTION INPUT ;
    USE SIGNAL ;
    PORT
      LAYER M5 ;
        RECT  129.168 25.728 129.192 25.92 ;
    END
  END i[371]
  PIN i[372]
    DIRECTION INPUT ;
    USE SIGNAL ;
    PORT
      LAYER M5 ;
        RECT  129.504 25.728 129.528 25.92 ;
    END
  END i[372]
  PIN i[373]
    DIRECTION INPUT ;
    USE SIGNAL ;
    PORT
      LAYER M5 ;
        RECT  129.84 25.728 129.864 25.92 ;
    END
  END i[373]
  PIN i[374]
    DIRECTION INPUT ;
    USE SIGNAL ;
    PORT
      LAYER M5 ;
        RECT  130.176 25.728 130.2 25.92 ;
    END
  END i[374]
  PIN i[375]
    DIRECTION INPUT ;
    USE SIGNAL ;
    PORT
      LAYER M5 ;
        RECT  130.512 25.728 130.536 25.92 ;
    END
  END i[375]
  PIN i[376]
    DIRECTION INPUT ;
    USE SIGNAL ;
    PORT
      LAYER M5 ;
        RECT  130.848 25.728 130.872 25.92 ;
    END
  END i[376]
  PIN i[377]
    DIRECTION INPUT ;
    USE SIGNAL ;
    PORT
      LAYER M5 ;
        RECT  131.184 25.728 131.208 25.92 ;
    END
  END i[377]
  PIN i[378]
    DIRECTION INPUT ;
    USE SIGNAL ;
    PORT
      LAYER M5 ;
        RECT  131.52 25.728 131.544 25.92 ;
    END
  END i[378]
  PIN i[379]
    DIRECTION INPUT ;
    USE SIGNAL ;
    PORT
      LAYER M5 ;
        RECT  131.856 25.728 131.88 25.92 ;
    END
  END i[379]
  PIN i[37]
    DIRECTION INPUT ;
    USE SIGNAL ;
    PORT
      LAYER M5 ;
        RECT  16.896 25.728 16.92 25.92 ;
    END
  END i[37]
  PIN i[380]
    DIRECTION INPUT ;
    USE SIGNAL ;
    PORT
      LAYER M5 ;
        RECT  132.192 25.728 132.216 25.92 ;
    END
  END i[380]
  PIN i[381]
    DIRECTION INPUT ;
    USE SIGNAL ;
    PORT
      LAYER M5 ;
        RECT  132.528 25.728 132.552 25.92 ;
    END
  END i[381]
  PIN i[382]
    DIRECTION INPUT ;
    USE SIGNAL ;
    PORT
      LAYER M5 ;
        RECT  132.864 25.728 132.888 25.92 ;
    END
  END i[382]
  PIN i[383]
    DIRECTION INPUT ;
    USE SIGNAL ;
    PORT
      LAYER M5 ;
        RECT  133.2 25.728 133.224 25.92 ;
    END
  END i[383]
  PIN i[384]
    DIRECTION INPUT ;
    USE SIGNAL ;
    PORT
      LAYER M5 ;
        RECT  133.536 25.728 133.56 25.92 ;
    END
  END i[384]
  PIN i[385]
    DIRECTION INPUT ;
    USE SIGNAL ;
    PORT
      LAYER M5 ;
        RECT  133.872 25.728 133.896 25.92 ;
    END
  END i[385]
  PIN i[386]
    DIRECTION INPUT ;
    USE SIGNAL ;
    PORT
      LAYER M5 ;
        RECT  134.208 25.728 134.232 25.92 ;
    END
  END i[386]
  PIN i[387]
    DIRECTION INPUT ;
    USE SIGNAL ;
    PORT
      LAYER M5 ;
        RECT  134.544 25.728 134.568 25.92 ;
    END
  END i[387]
  PIN i[388]
    DIRECTION INPUT ;
    USE SIGNAL ;
    PORT
      LAYER M5 ;
        RECT  134.88 25.728 134.904 25.92 ;
    END
  END i[388]
  PIN i[389]
    DIRECTION INPUT ;
    USE SIGNAL ;
    PORT
      LAYER M5 ;
        RECT  135.216 25.728 135.24 25.92 ;
    END
  END i[389]
  PIN i[38]
    DIRECTION INPUT ;
    USE SIGNAL ;
    PORT
      LAYER M5 ;
        RECT  17.232 25.728 17.256 25.92 ;
    END
  END i[38]
  PIN i[390]
    DIRECTION INPUT ;
    USE SIGNAL ;
    PORT
      LAYER M5 ;
        RECT  135.552 25.728 135.576 25.92 ;
    END
  END i[390]
  PIN i[391]
    DIRECTION INPUT ;
    USE SIGNAL ;
    PORT
      LAYER M5 ;
        RECT  135.888 25.728 135.912 25.92 ;
    END
  END i[391]
  PIN i[392]
    DIRECTION INPUT ;
    USE SIGNAL ;
    PORT
      LAYER M5 ;
        RECT  136.224 25.728 136.248 25.92 ;
    END
  END i[392]
  PIN i[393]
    DIRECTION INPUT ;
    USE SIGNAL ;
    PORT
      LAYER M5 ;
        RECT  136.56 25.728 136.584 25.92 ;
    END
  END i[393]
  PIN i[394]
    DIRECTION INPUT ;
    USE SIGNAL ;
    PORT
      LAYER M5 ;
        RECT  136.896 25.728 136.92 25.92 ;
    END
  END i[394]
  PIN i[395]
    DIRECTION INPUT ;
    USE SIGNAL ;
    PORT
      LAYER M5 ;
        RECT  137.232 25.728 137.256 25.92 ;
    END
  END i[395]
  PIN i[396]
    DIRECTION INPUT ;
    USE SIGNAL ;
    PORT
      LAYER M5 ;
        RECT  137.568 25.728 137.592 25.92 ;
    END
  END i[396]
  PIN i[397]
    DIRECTION INPUT ;
    USE SIGNAL ;
    PORT
      LAYER M5 ;
        RECT  137.904 25.728 137.928 25.92 ;
    END
  END i[397]
  PIN i[398]
    DIRECTION INPUT ;
    USE SIGNAL ;
    PORT
      LAYER M5 ;
        RECT  138.24 25.728 138.264 25.92 ;
    END
  END i[398]
  PIN i[399]
    DIRECTION INPUT ;
    USE SIGNAL ;
    PORT
      LAYER M5 ;
        RECT  138.576 25.728 138.6 25.92 ;
    END
  END i[399]
  PIN i[39]
    DIRECTION INPUT ;
    USE SIGNAL ;
    PORT
      LAYER M5 ;
        RECT  17.568 25.728 17.592 25.92 ;
    END
  END i[39]
  PIN i[3]
    DIRECTION INPUT ;
    USE SIGNAL ;
    PORT
      LAYER M5 ;
        RECT  5.52 25.728 5.544 25.92 ;
    END
  END i[3]
  PIN i[400]
    DIRECTION INPUT ;
    USE SIGNAL ;
    PORT
      LAYER M5 ;
        RECT  138.912 25.728 138.936 25.92 ;
    END
  END i[400]
  PIN i[401]
    DIRECTION INPUT ;
    USE SIGNAL ;
    PORT
      LAYER M5 ;
        RECT  139.248 25.728 139.272 25.92 ;
    END
  END i[401]
  PIN i[402]
    DIRECTION INPUT ;
    USE SIGNAL ;
    PORT
      LAYER M5 ;
        RECT  139.584 25.728 139.608 25.92 ;
    END
  END i[402]
  PIN i[403]
    DIRECTION INPUT ;
    USE SIGNAL ;
    PORT
      LAYER M5 ;
        RECT  139.92 25.728 139.944 25.92 ;
    END
  END i[403]
  PIN i[404]
    DIRECTION INPUT ;
    USE SIGNAL ;
    PORT
      LAYER M5 ;
        RECT  140.256 25.728 140.28 25.92 ;
    END
  END i[404]
  PIN i[405]
    DIRECTION INPUT ;
    USE SIGNAL ;
    PORT
      LAYER M5 ;
        RECT  140.592 25.728 140.616 25.92 ;
    END
  END i[405]
  PIN i[406]
    DIRECTION INPUT ;
    USE SIGNAL ;
    PORT
      LAYER M5 ;
        RECT  140.928 25.728 140.952 25.92 ;
    END
  END i[406]
  PIN i[407]
    DIRECTION INPUT ;
    USE SIGNAL ;
    PORT
      LAYER M5 ;
        RECT  141.264 25.728 141.288 25.92 ;
    END
  END i[407]
  PIN i[408]
    DIRECTION INPUT ;
    USE SIGNAL ;
    PORT
      LAYER M5 ;
        RECT  141.552 25.728 141.576 25.92 ;
    END
  END i[408]
  PIN i[409]
    DIRECTION INPUT ;
    USE SIGNAL ;
    PORT
      LAYER M5 ;
        RECT  141.888 25.728 141.912 25.92 ;
    END
  END i[409]
  PIN i[40]
    DIRECTION INPUT ;
    USE SIGNAL ;
    PORT
      LAYER M5 ;
        RECT  17.904 25.728 17.928 25.92 ;
    END
  END i[40]
  PIN i[410]
    DIRECTION INPUT ;
    USE SIGNAL ;
    PORT
      LAYER M5 ;
        RECT  142.224 25.728 142.248 25.92 ;
    END
  END i[410]
  PIN i[411]
    DIRECTION INPUT ;
    USE SIGNAL ;
    PORT
      LAYER M5 ;
        RECT  142.56 25.728 142.584 25.92 ;
    END
  END i[411]
  PIN i[412]
    DIRECTION INPUT ;
    USE SIGNAL ;
    PORT
      LAYER M5 ;
        RECT  142.896 25.728 142.92 25.92 ;
    END
  END i[412]
  PIN i[413]
    DIRECTION INPUT ;
    USE SIGNAL ;
    PORT
      LAYER M5 ;
        RECT  143.232 25.728 143.256 25.92 ;
    END
  END i[413]
  PIN i[414]
    DIRECTION INPUT ;
    USE SIGNAL ;
    PORT
      LAYER M5 ;
        RECT  143.568 25.728 143.592 25.92 ;
    END
  END i[414]
  PIN i[415]
    DIRECTION INPUT ;
    USE SIGNAL ;
    PORT
      LAYER M5 ;
        RECT  143.904 25.728 143.928 25.92 ;
    END
  END i[415]
  PIN i[416]
    DIRECTION INPUT ;
    USE SIGNAL ;
    PORT
      LAYER M5 ;
        RECT  144.24 25.728 144.264 25.92 ;
    END
  END i[416]
  PIN i[417]
    DIRECTION INPUT ;
    USE SIGNAL ;
    PORT
      LAYER M5 ;
        RECT  144.576 25.728 144.6 25.92 ;
    END
  END i[417]
  PIN i[418]
    DIRECTION INPUT ;
    USE SIGNAL ;
    PORT
      LAYER M5 ;
        RECT  144.912 25.728 144.936 25.92 ;
    END
  END i[418]
  PIN i[419]
    DIRECTION INPUT ;
    USE SIGNAL ;
    PORT
      LAYER M5 ;
        RECT  145.248 25.728 145.272 25.92 ;
    END
  END i[419]
  PIN i[41]
    DIRECTION INPUT ;
    USE SIGNAL ;
    PORT
      LAYER M5 ;
        RECT  18.24 25.728 18.264 25.92 ;
    END
  END i[41]
  PIN i[420]
    DIRECTION INPUT ;
    USE SIGNAL ;
    PORT
      LAYER M5 ;
        RECT  145.584 25.728 145.608 25.92 ;
    END
  END i[420]
  PIN i[421]
    DIRECTION INPUT ;
    USE SIGNAL ;
    PORT
      LAYER M5 ;
        RECT  145.92 25.728 145.944 25.92 ;
    END
  END i[421]
  PIN i[422]
    DIRECTION INPUT ;
    USE SIGNAL ;
    PORT
      LAYER M5 ;
        RECT  146.256 25.728 146.28 25.92 ;
    END
  END i[422]
  PIN i[423]
    DIRECTION INPUT ;
    USE SIGNAL ;
    PORT
      LAYER M5 ;
        RECT  146.592 25.728 146.616 25.92 ;
    END
  END i[423]
  PIN i[424]
    DIRECTION INPUT ;
    USE SIGNAL ;
    PORT
      LAYER M5 ;
        RECT  146.928 25.728 146.952 25.92 ;
    END
  END i[424]
  PIN i[425]
    DIRECTION INPUT ;
    USE SIGNAL ;
    PORT
      LAYER M5 ;
        RECT  147.264 25.728 147.288 25.92 ;
    END
  END i[425]
  PIN i[426]
    DIRECTION INPUT ;
    USE SIGNAL ;
    PORT
      LAYER M5 ;
        RECT  147.6 25.728 147.624 25.92 ;
    END
  END i[426]
  PIN i[427]
    DIRECTION INPUT ;
    USE SIGNAL ;
    PORT
      LAYER M5 ;
        RECT  147.936 25.728 147.96 25.92 ;
    END
  END i[427]
  PIN i[428]
    DIRECTION INPUT ;
    USE SIGNAL ;
    PORT
      LAYER M5 ;
        RECT  148.272 25.728 148.296 25.92 ;
    END
  END i[428]
  PIN i[429]
    DIRECTION INPUT ;
    USE SIGNAL ;
    PORT
      LAYER M5 ;
        RECT  148.608 25.728 148.632 25.92 ;
    END
  END i[429]
  PIN i[42]
    DIRECTION INPUT ;
    USE SIGNAL ;
    PORT
      LAYER M5 ;
        RECT  18.576 25.728 18.6 25.92 ;
    END
  END i[42]
  PIN i[430]
    DIRECTION INPUT ;
    USE SIGNAL ;
    PORT
      LAYER M5 ;
        RECT  148.944 25.728 148.968 25.92 ;
    END
  END i[430]
  PIN i[431]
    DIRECTION INPUT ;
    USE SIGNAL ;
    PORT
      LAYER M5 ;
        RECT  149.28 25.728 149.304 25.92 ;
    END
  END i[431]
  PIN i[432]
    DIRECTION INPUT ;
    USE SIGNAL ;
    PORT
      LAYER M5 ;
        RECT  149.616 25.728 149.64 25.92 ;
    END
  END i[432]
  PIN i[433]
    DIRECTION INPUT ;
    USE SIGNAL ;
    PORT
      LAYER M5 ;
        RECT  149.952 25.728 149.976 25.92 ;
    END
  END i[433]
  PIN i[434]
    DIRECTION INPUT ;
    USE SIGNAL ;
    PORT
      LAYER M5 ;
        RECT  150.288 25.728 150.312 25.92 ;
    END
  END i[434]
  PIN i[435]
    DIRECTION INPUT ;
    USE SIGNAL ;
    PORT
      LAYER M5 ;
        RECT  150.624 25.728 150.648 25.92 ;
    END
  END i[435]
  PIN i[436]
    DIRECTION INPUT ;
    USE SIGNAL ;
    PORT
      LAYER M5 ;
        RECT  150.96 25.728 150.984 25.92 ;
    END
  END i[436]
  PIN i[437]
    DIRECTION INPUT ;
    USE SIGNAL ;
    PORT
      LAYER M5 ;
        RECT  151.296 25.728 151.32 25.92 ;
    END
  END i[437]
  PIN i[438]
    DIRECTION INPUT ;
    USE SIGNAL ;
    PORT
      LAYER M5 ;
        RECT  151.632 25.728 151.656 25.92 ;
    END
  END i[438]
  PIN i[439]
    DIRECTION INPUT ;
    USE SIGNAL ;
    PORT
      LAYER M5 ;
        RECT  151.968 25.728 151.992 25.92 ;
    END
  END i[439]
  PIN i[43]
    DIRECTION INPUT ;
    USE SIGNAL ;
    PORT
      LAYER M5 ;
        RECT  18.912 25.728 18.936 25.92 ;
    END
  END i[43]
  PIN i[440]
    DIRECTION INPUT ;
    USE SIGNAL ;
    PORT
      LAYER M5 ;
        RECT  152.304 25.728 152.328 25.92 ;
    END
  END i[440]
  PIN i[441]
    DIRECTION INPUT ;
    USE SIGNAL ;
    PORT
      LAYER M5 ;
        RECT  152.64 25.728 152.664 25.92 ;
    END
  END i[441]
  PIN i[442]
    DIRECTION INPUT ;
    USE SIGNAL ;
    PORT
      LAYER M5 ;
        RECT  152.976 25.728 153 25.92 ;
    END
  END i[442]
  PIN i[443]
    DIRECTION INPUT ;
    USE SIGNAL ;
    PORT
      LAYER M5 ;
        RECT  153.312 25.728 153.336 25.92 ;
    END
  END i[443]
  PIN i[444]
    DIRECTION INPUT ;
    USE SIGNAL ;
    PORT
      LAYER M5 ;
        RECT  153.648 25.728 153.672 25.92 ;
    END
  END i[444]
  PIN i[445]
    DIRECTION INPUT ;
    USE SIGNAL ;
    PORT
      LAYER M5 ;
        RECT  153.984 25.728 154.008 25.92 ;
    END
  END i[445]
  PIN i[446]
    DIRECTION INPUT ;
    USE SIGNAL ;
    PORT
      LAYER M5 ;
        RECT  154.32 25.728 154.344 25.92 ;
    END
  END i[446]
  PIN i[447]
    DIRECTION INPUT ;
    USE SIGNAL ;
    PORT
      LAYER M5 ;
        RECT  154.656 25.728 154.68 25.92 ;
    END
  END i[447]
  PIN i[448]
    DIRECTION INPUT ;
    USE SIGNAL ;
    PORT
      LAYER M5 ;
        RECT  154.992 25.728 155.016 25.92 ;
    END
  END i[448]
  PIN i[449]
    DIRECTION INPUT ;
    USE SIGNAL ;
    PORT
      LAYER M5 ;
        RECT  155.328 25.728 155.352 25.92 ;
    END
  END i[449]
  PIN i[44]
    DIRECTION INPUT ;
    USE SIGNAL ;
    PORT
      LAYER M5 ;
        RECT  19.248 25.728 19.272 25.92 ;
    END
  END i[44]
  PIN i[450]
    DIRECTION INPUT ;
    USE SIGNAL ;
    PORT
      LAYER M5 ;
        RECT  155.664 25.728 155.688 25.92 ;
    END
  END i[450]
  PIN i[451]
    DIRECTION INPUT ;
    USE SIGNAL ;
    PORT
      LAYER M5 ;
        RECT  156 25.728 156.024 25.92 ;
    END
  END i[451]
  PIN i[452]
    DIRECTION INPUT ;
    USE SIGNAL ;
    PORT
      LAYER M5 ;
        RECT  156.336 25.728 156.36 25.92 ;
    END
  END i[452]
  PIN i[453]
    DIRECTION INPUT ;
    USE SIGNAL ;
    PORT
      LAYER M5 ;
        RECT  156.672 25.728 156.696 25.92 ;
    END
  END i[453]
  PIN i[454]
    DIRECTION INPUT ;
    USE SIGNAL ;
    PORT
      LAYER M5 ;
        RECT  157.008 25.728 157.032 25.92 ;
    END
  END i[454]
  PIN i[455]
    DIRECTION INPUT ;
    USE SIGNAL ;
    PORT
      LAYER M5 ;
        RECT  157.344 25.728 157.368 25.92 ;
    END
  END i[455]
  PIN i[456]
    DIRECTION INPUT ;
    USE SIGNAL ;
    PORT
      LAYER M5 ;
        RECT  157.68 25.728 157.704 25.92 ;
    END
  END i[456]
  PIN i[457]
    DIRECTION INPUT ;
    USE SIGNAL ;
    PORT
      LAYER M5 ;
        RECT  158.016 25.728 158.04 25.92 ;
    END
  END i[457]
  PIN i[458]
    DIRECTION INPUT ;
    USE SIGNAL ;
    PORT
      LAYER M5 ;
        RECT  158.352 25.728 158.376 25.92 ;
    END
  END i[458]
  PIN i[459]
    DIRECTION INPUT ;
    USE SIGNAL ;
    PORT
      LAYER M5 ;
        RECT  158.688 25.728 158.712 25.92 ;
    END
  END i[459]
  PIN i[45]
    DIRECTION INPUT ;
    USE SIGNAL ;
    PORT
      LAYER M5 ;
        RECT  19.584 25.728 19.608 25.92 ;
    END
  END i[45]
  PIN i[460]
    DIRECTION INPUT ;
    USE SIGNAL ;
    PORT
      LAYER M5 ;
        RECT  159.024 25.728 159.048 25.92 ;
    END
  END i[460]
  PIN i[461]
    DIRECTION INPUT ;
    USE SIGNAL ;
    PORT
      LAYER M5 ;
        RECT  159.36 25.728 159.384 25.92 ;
    END
  END i[461]
  PIN i[462]
    DIRECTION INPUT ;
    USE SIGNAL ;
    PORT
      LAYER M5 ;
        RECT  159.696 25.728 159.72 25.92 ;
    END
  END i[462]
  PIN i[463]
    DIRECTION INPUT ;
    USE SIGNAL ;
    PORT
      LAYER M5 ;
        RECT  159.984 25.728 160.008 25.92 ;
    END
  END i[463]
  PIN i[464]
    DIRECTION INPUT ;
    USE SIGNAL ;
    PORT
      LAYER M5 ;
        RECT  160.32 25.728 160.344 25.92 ;
    END
  END i[464]
  PIN i[465]
    DIRECTION INPUT ;
    USE SIGNAL ;
    PORT
      LAYER M5 ;
        RECT  160.656 25.728 160.68 25.92 ;
    END
  END i[465]
  PIN i[466]
    DIRECTION INPUT ;
    USE SIGNAL ;
    PORT
      LAYER M5 ;
        RECT  160.992 25.728 161.016 25.92 ;
    END
  END i[466]
  PIN i[467]
    DIRECTION INPUT ;
    USE SIGNAL ;
    PORT
      LAYER M5 ;
        RECT  161.328 25.728 161.352 25.92 ;
    END
  END i[467]
  PIN i[468]
    DIRECTION INPUT ;
    USE SIGNAL ;
    PORT
      LAYER M5 ;
        RECT  161.664 25.728 161.688 25.92 ;
    END
  END i[468]
  PIN i[469]
    DIRECTION INPUT ;
    USE SIGNAL ;
    PORT
      LAYER M5 ;
        RECT  162 25.728 162.024 25.92 ;
    END
  END i[469]
  PIN i[46]
    DIRECTION INPUT ;
    USE SIGNAL ;
    PORT
      LAYER M5 ;
        RECT  19.92 25.728 19.944 25.92 ;
    END
  END i[46]
  PIN i[470]
    DIRECTION INPUT ;
    USE SIGNAL ;
    PORT
      LAYER M5 ;
        RECT  162.336 25.728 162.36 25.92 ;
    END
  END i[470]
  PIN i[471]
    DIRECTION INPUT ;
    USE SIGNAL ;
    PORT
      LAYER M5 ;
        RECT  162.672 25.728 162.696 25.92 ;
    END
  END i[471]
  PIN i[472]
    DIRECTION INPUT ;
    USE SIGNAL ;
    PORT
      LAYER M5 ;
        RECT  163.008 25.728 163.032 25.92 ;
    END
  END i[472]
  PIN i[473]
    DIRECTION INPUT ;
    USE SIGNAL ;
    PORT
      LAYER M5 ;
        RECT  163.344 25.728 163.368 25.92 ;
    END
  END i[473]
  PIN i[474]
    DIRECTION INPUT ;
    USE SIGNAL ;
    PORT
      LAYER M5 ;
        RECT  163.68 25.728 163.704 25.92 ;
    END
  END i[474]
  PIN i[475]
    DIRECTION INPUT ;
    USE SIGNAL ;
    PORT
      LAYER M5 ;
        RECT  164.016 25.728 164.04 25.92 ;
    END
  END i[475]
  PIN i[476]
    DIRECTION INPUT ;
    USE SIGNAL ;
    PORT
      LAYER M5 ;
        RECT  164.352 25.728 164.376 25.92 ;
    END
  END i[476]
  PIN i[477]
    DIRECTION INPUT ;
    USE SIGNAL ;
    PORT
      LAYER M5 ;
        RECT  164.688 25.728 164.712 25.92 ;
    END
  END i[477]
  PIN i[478]
    DIRECTION INPUT ;
    USE SIGNAL ;
    PORT
      LAYER M5 ;
        RECT  165.024 25.728 165.048 25.92 ;
    END
  END i[478]
  PIN i[479]
    DIRECTION INPUT ;
    USE SIGNAL ;
    PORT
      LAYER M5 ;
        RECT  165.36 25.728 165.384 25.92 ;
    END
  END i[479]
  PIN i[47]
    DIRECTION INPUT ;
    USE SIGNAL ;
    PORT
      LAYER M5 ;
        RECT  20.256 25.728 20.28 25.92 ;
    END
  END i[47]
  PIN i[480]
    DIRECTION INPUT ;
    USE SIGNAL ;
    PORT
      LAYER M5 ;
        RECT  165.696 25.728 165.72 25.92 ;
    END
  END i[480]
  PIN i[481]
    DIRECTION INPUT ;
    USE SIGNAL ;
    PORT
      LAYER M5 ;
        RECT  166.032 25.728 166.056 25.92 ;
    END
  END i[481]
  PIN i[482]
    DIRECTION INPUT ;
    USE SIGNAL ;
    PORT
      LAYER M5 ;
        RECT  166.368 25.728 166.392 25.92 ;
    END
  END i[482]
  PIN i[483]
    DIRECTION INPUT ;
    USE SIGNAL ;
    PORT
      LAYER M5 ;
        RECT  166.704 25.728 166.728 25.92 ;
    END
  END i[483]
  PIN i[484]
    DIRECTION INPUT ;
    USE SIGNAL ;
    PORT
      LAYER M5 ;
        RECT  167.04 25.728 167.064 25.92 ;
    END
  END i[484]
  PIN i[485]
    DIRECTION INPUT ;
    USE SIGNAL ;
    PORT
      LAYER M5 ;
        RECT  167.376 25.728 167.4 25.92 ;
    END
  END i[485]
  PIN i[486]
    DIRECTION INPUT ;
    USE SIGNAL ;
    PORT
      LAYER M5 ;
        RECT  167.712 25.728 167.736 25.92 ;
    END
  END i[486]
  PIN i[487]
    DIRECTION INPUT ;
    USE SIGNAL ;
    PORT
      LAYER M5 ;
        RECT  168.048 25.728 168.072 25.92 ;
    END
  END i[487]
  PIN i[488]
    DIRECTION INPUT ;
    USE SIGNAL ;
    PORT
      LAYER M5 ;
        RECT  168.384 25.728 168.408 25.92 ;
    END
  END i[488]
  PIN i[489]
    DIRECTION INPUT ;
    USE SIGNAL ;
    PORT
      LAYER M5 ;
        RECT  168.72 25.728 168.744 25.92 ;
    END
  END i[489]
  PIN i[48]
    DIRECTION INPUT ;
    USE SIGNAL ;
    PORT
      LAYER M5 ;
        RECT  20.592 25.728 20.616 25.92 ;
    END
  END i[48]
  PIN i[490]
    DIRECTION INPUT ;
    USE SIGNAL ;
    PORT
      LAYER M5 ;
        RECT  169.056 25.728 169.08 25.92 ;
    END
  END i[490]
  PIN i[491]
    DIRECTION INPUT ;
    USE SIGNAL ;
    PORT
      LAYER M5 ;
        RECT  169.392 25.728 169.416 25.92 ;
    END
  END i[491]
  PIN i[492]
    DIRECTION INPUT ;
    USE SIGNAL ;
    PORT
      LAYER M5 ;
        RECT  169.728 25.728 169.752 25.92 ;
    END
  END i[492]
  PIN i[493]
    DIRECTION INPUT ;
    USE SIGNAL ;
    PORT
      LAYER M5 ;
        RECT  170.064 25.728 170.088 25.92 ;
    END
  END i[493]
  PIN i[494]
    DIRECTION INPUT ;
    USE SIGNAL ;
    PORT
      LAYER M5 ;
        RECT  170.4 25.728 170.424 25.92 ;
    END
  END i[494]
  PIN i[495]
    DIRECTION INPUT ;
    USE SIGNAL ;
    PORT
      LAYER M5 ;
        RECT  170.736 25.728 170.76 25.92 ;
    END
  END i[495]
  PIN i[496]
    DIRECTION INPUT ;
    USE SIGNAL ;
    PORT
      LAYER M5 ;
        RECT  171.072 25.728 171.096 25.92 ;
    END
  END i[496]
  PIN i[497]
    DIRECTION INPUT ;
    USE SIGNAL ;
    PORT
      LAYER M5 ;
        RECT  171.408 25.728 171.432 25.92 ;
    END
  END i[497]
  PIN i[498]
    DIRECTION INPUT ;
    USE SIGNAL ;
    PORT
      LAYER M5 ;
        RECT  171.744 25.728 171.768 25.92 ;
    END
  END i[498]
  PIN i[499]
    DIRECTION INPUT ;
    USE SIGNAL ;
    PORT
      LAYER M5 ;
        RECT  172.08 25.728 172.104 25.92 ;
    END
  END i[499]
  PIN i[49]
    DIRECTION INPUT ;
    USE SIGNAL ;
    PORT
      LAYER M5 ;
        RECT  20.928 25.728 20.952 25.92 ;
    END
  END i[49]
  PIN i[4]
    DIRECTION INPUT ;
    USE SIGNAL ;
    PORT
      LAYER M5 ;
        RECT  5.856 25.728 5.88 25.92 ;
    END
  END i[4]
  PIN i[500]
    DIRECTION INPUT ;
    USE SIGNAL ;
    PORT
      LAYER M5 ;
        RECT  172.416 25.728 172.44 25.92 ;
    END
  END i[500]
  PIN i[501]
    DIRECTION INPUT ;
    USE SIGNAL ;
    PORT
      LAYER M5 ;
        RECT  172.752 25.728 172.776 25.92 ;
    END
  END i[501]
  PIN i[502]
    DIRECTION INPUT ;
    USE SIGNAL ;
    PORT
      LAYER M5 ;
        RECT  173.088 25.728 173.112 25.92 ;
    END
  END i[502]
  PIN i[503]
    DIRECTION INPUT ;
    USE SIGNAL ;
    PORT
      LAYER M5 ;
        RECT  173.424 25.728 173.448 25.92 ;
    END
  END i[503]
  PIN i[504]
    DIRECTION INPUT ;
    USE SIGNAL ;
    PORT
      LAYER M5 ;
        RECT  173.76 25.728 173.784 25.92 ;
    END
  END i[504]
  PIN i[505]
    DIRECTION INPUT ;
    USE SIGNAL ;
    PORT
      LAYER M5 ;
        RECT  174.096 25.728 174.12 25.92 ;
    END
  END i[505]
  PIN i[506]
    DIRECTION INPUT ;
    USE SIGNAL ;
    PORT
      LAYER M5 ;
        RECT  174.432 25.728 174.456 25.92 ;
    END
  END i[506]
  PIN i[507]
    DIRECTION INPUT ;
    USE SIGNAL ;
    PORT
      LAYER M5 ;
        RECT  174.768 25.728 174.792 25.92 ;
    END
  END i[507]
  PIN i[508]
    DIRECTION INPUT ;
    USE SIGNAL ;
    PORT
      LAYER M5 ;
        RECT  175.104 25.728 175.128 25.92 ;
    END
  END i[508]
  PIN i[509]
    DIRECTION INPUT ;
    USE SIGNAL ;
    PORT
      LAYER M5 ;
        RECT  175.44 25.728 175.464 25.92 ;
    END
  END i[509]
  PIN i[50]
    DIRECTION INPUT ;
    USE SIGNAL ;
    PORT
      LAYER M5 ;
        RECT  21.264 25.728 21.288 25.92 ;
    END
  END i[50]
  PIN i[510]
    DIRECTION INPUT ;
    USE SIGNAL ;
    PORT
      LAYER M5 ;
        RECT  175.776 25.728 175.8 25.92 ;
    END
  END i[510]
  PIN i[511]
    DIRECTION INPUT ;
    USE SIGNAL ;
    PORT
      LAYER M5 ;
        RECT  176.112 25.728 176.136 25.92 ;
    END
  END i[511]
  PIN i[512]
    DIRECTION INPUT ;
    USE SIGNAL ;
    PORT
      LAYER M5 ;
        RECT  176.448 25.728 176.472 25.92 ;
    END
  END i[512]
  PIN i[513]
    DIRECTION INPUT ;
    USE SIGNAL ;
    PORT
      LAYER M5 ;
        RECT  176.784 25.728 176.808 25.92 ;
    END
  END i[513]
  PIN i[514]
    DIRECTION INPUT ;
    USE SIGNAL ;
    PORT
      LAYER M5 ;
        RECT  177.12 25.728 177.144 25.92 ;
    END
  END i[514]
  PIN i[515]
    DIRECTION INPUT ;
    USE SIGNAL ;
    PORT
      LAYER M5 ;
        RECT  177.456 25.728 177.48 25.92 ;
    END
  END i[515]
  PIN i[516]
    DIRECTION INPUT ;
    USE SIGNAL ;
    PORT
      LAYER M5 ;
        RECT  177.792 25.728 177.816 25.92 ;
    END
  END i[516]
  PIN i[517]
    DIRECTION INPUT ;
    USE SIGNAL ;
    PORT
      LAYER M5 ;
        RECT  178.128 25.728 178.152 25.92 ;
    END
  END i[517]
  PIN i[518]
    DIRECTION INPUT ;
    USE SIGNAL ;
    PORT
      LAYER M5 ;
        RECT  178.416 25.728 178.44 25.92 ;
    END
  END i[518]
  PIN i[519]
    DIRECTION INPUT ;
    USE SIGNAL ;
    PORT
      LAYER M5 ;
        RECT  178.752 25.728 178.776 25.92 ;
    END
  END i[519]
  PIN i[51]
    DIRECTION INPUT ;
    USE SIGNAL ;
    PORT
      LAYER M5 ;
        RECT  21.6 25.728 21.624 25.92 ;
    END
  END i[51]
  PIN i[520]
    DIRECTION INPUT ;
    USE SIGNAL ;
    PORT
      LAYER M5 ;
        RECT  179.088 25.728 179.112 25.92 ;
    END
  END i[520]
  PIN i[521]
    DIRECTION INPUT ;
    USE SIGNAL ;
    PORT
      LAYER M5 ;
        RECT  179.424 25.728 179.448 25.92 ;
    END
  END i[521]
  PIN i[522]
    DIRECTION INPUT ;
    USE SIGNAL ;
    PORT
      LAYER M5 ;
        RECT  179.76 25.728 179.784 25.92 ;
    END
  END i[522]
  PIN i[523]
    DIRECTION INPUT ;
    USE SIGNAL ;
    PORT
      LAYER M5 ;
        RECT  180.096 25.728 180.12 25.92 ;
    END
  END i[523]
  PIN i[524]
    DIRECTION INPUT ;
    USE SIGNAL ;
    PORT
      LAYER M5 ;
        RECT  180.432 25.728 180.456 25.92 ;
    END
  END i[524]
  PIN i[525]
    DIRECTION INPUT ;
    USE SIGNAL ;
    PORT
      LAYER M5 ;
        RECT  180.768 25.728 180.792 25.92 ;
    END
  END i[525]
  PIN i[526]
    DIRECTION INPUT ;
    USE SIGNAL ;
    PORT
      LAYER M5 ;
        RECT  181.104 25.728 181.128 25.92 ;
    END
  END i[526]
  PIN i[527]
    DIRECTION INPUT ;
    USE SIGNAL ;
    PORT
      LAYER M5 ;
        RECT  181.44 25.728 181.464 25.92 ;
    END
  END i[527]
  PIN i[528]
    DIRECTION INPUT ;
    USE SIGNAL ;
    PORT
      LAYER M5 ;
        RECT  181.776 25.728 181.8 25.92 ;
    END
  END i[528]
  PIN i[529]
    DIRECTION INPUT ;
    USE SIGNAL ;
    PORT
      LAYER M5 ;
        RECT  182.112 25.728 182.136 25.92 ;
    END
  END i[529]
  PIN i[52]
    DIRECTION INPUT ;
    USE SIGNAL ;
    PORT
      LAYER M5 ;
        RECT  21.936 25.728 21.96 25.92 ;
    END
  END i[52]
  PIN i[530]
    DIRECTION INPUT ;
    USE SIGNAL ;
    PORT
      LAYER M5 ;
        RECT  182.448 25.728 182.472 25.92 ;
    END
  END i[530]
  PIN i[531]
    DIRECTION INPUT ;
    USE SIGNAL ;
    PORT
      LAYER M5 ;
        RECT  182.784 25.728 182.808 25.92 ;
    END
  END i[531]
  PIN i[532]
    DIRECTION INPUT ;
    USE SIGNAL ;
    PORT
      LAYER M5 ;
        RECT  183.12 25.728 183.144 25.92 ;
    END
  END i[532]
  PIN i[533]
    DIRECTION INPUT ;
    USE SIGNAL ;
    PORT
      LAYER M5 ;
        RECT  183.456 25.728 183.48 25.92 ;
    END
  END i[533]
  PIN i[534]
    DIRECTION INPUT ;
    USE SIGNAL ;
    PORT
      LAYER M5 ;
        RECT  183.792 25.728 183.816 25.92 ;
    END
  END i[534]
  PIN i[535]
    DIRECTION INPUT ;
    USE SIGNAL ;
    PORT
      LAYER M5 ;
        RECT  184.128 25.728 184.152 25.92 ;
    END
  END i[535]
  PIN i[536]
    DIRECTION INPUT ;
    USE SIGNAL ;
    PORT
      LAYER M5 ;
        RECT  184.464 25.728 184.488 25.92 ;
    END
  END i[536]
  PIN i[537]
    DIRECTION INPUT ;
    USE SIGNAL ;
    PORT
      LAYER M5 ;
        RECT  184.8 25.728 184.824 25.92 ;
    END
  END i[537]
  PIN i[538]
    DIRECTION INPUT ;
    USE SIGNAL ;
    PORT
      LAYER M5 ;
        RECT  185.136 25.728 185.16 25.92 ;
    END
  END i[538]
  PIN i[539]
    DIRECTION INPUT ;
    USE SIGNAL ;
    PORT
      LAYER M5 ;
        RECT  185.472 25.728 185.496 25.92 ;
    END
  END i[539]
  PIN i[53]
    DIRECTION INPUT ;
    USE SIGNAL ;
    PORT
      LAYER M5 ;
        RECT  22.272 25.728 22.296 25.92 ;
    END
  END i[53]
  PIN i[540]
    DIRECTION INPUT ;
    USE SIGNAL ;
    PORT
      LAYER M5 ;
        RECT  185.808 25.728 185.832 25.92 ;
    END
  END i[540]
  PIN i[541]
    DIRECTION INPUT ;
    USE SIGNAL ;
    PORT
      LAYER M5 ;
        RECT  186.144 25.728 186.168 25.92 ;
    END
  END i[541]
  PIN i[542]
    DIRECTION INPUT ;
    USE SIGNAL ;
    PORT
      LAYER M5 ;
        RECT  186.48 25.728 186.504 25.92 ;
    END
  END i[542]
  PIN i[543]
    DIRECTION INPUT ;
    USE SIGNAL ;
    PORT
      LAYER M5 ;
        RECT  186.816 25.728 186.84 25.92 ;
    END
  END i[543]
  PIN i[544]
    DIRECTION INPUT ;
    USE SIGNAL ;
    PORT
      LAYER M5 ;
        RECT  187.152 25.728 187.176 25.92 ;
    END
  END i[544]
  PIN i[545]
    DIRECTION INPUT ;
    USE SIGNAL ;
    PORT
      LAYER M5 ;
        RECT  187.488 25.728 187.512 25.92 ;
    END
  END i[545]
  PIN i[546]
    DIRECTION INPUT ;
    USE SIGNAL ;
    PORT
      LAYER M5 ;
        RECT  187.824 25.728 187.848 25.92 ;
    END
  END i[546]
  PIN i[547]
    DIRECTION INPUT ;
    USE SIGNAL ;
    PORT
      LAYER M5 ;
        RECT  188.16 25.728 188.184 25.92 ;
    END
  END i[547]
  PIN i[548]
    DIRECTION INPUT ;
    USE SIGNAL ;
    PORT
      LAYER M5 ;
        RECT  188.496 25.728 188.52 25.92 ;
    END
  END i[548]
  PIN i[549]
    DIRECTION INPUT ;
    USE SIGNAL ;
    PORT
      LAYER M5 ;
        RECT  188.832 25.728 188.856 25.92 ;
    END
  END i[549]
  PIN i[54]
    DIRECTION INPUT ;
    USE SIGNAL ;
    PORT
      LAYER M5 ;
        RECT  22.608 25.728 22.632 25.92 ;
    END
  END i[54]
  PIN i[550]
    DIRECTION INPUT ;
    USE SIGNAL ;
    PORT
      LAYER M5 ;
        RECT  189.168 25.728 189.192 25.92 ;
    END
  END i[550]
  PIN i[551]
    DIRECTION INPUT ;
    USE SIGNAL ;
    PORT
      LAYER M5 ;
        RECT  189.504 25.728 189.528 25.92 ;
    END
  END i[551]
  PIN i[552]
    DIRECTION INPUT ;
    USE SIGNAL ;
    PORT
      LAYER M5 ;
        RECT  189.84 25.728 189.864 25.92 ;
    END
  END i[552]
  PIN i[553]
    DIRECTION INPUT ;
    USE SIGNAL ;
    PORT
      LAYER M5 ;
        RECT  190.176 25.728 190.2 25.92 ;
    END
  END i[553]
  PIN i[554]
    DIRECTION INPUT ;
    USE SIGNAL ;
    PORT
      LAYER M5 ;
        RECT  190.512 25.728 190.536 25.92 ;
    END
  END i[554]
  PIN i[555]
    DIRECTION INPUT ;
    USE SIGNAL ;
    PORT
      LAYER M5 ;
        RECT  190.848 25.728 190.872 25.92 ;
    END
  END i[555]
  PIN i[556]
    DIRECTION INPUT ;
    USE SIGNAL ;
    PORT
      LAYER M5 ;
        RECT  191.184 25.728 191.208 25.92 ;
    END
  END i[556]
  PIN i[557]
    DIRECTION INPUT ;
    USE SIGNAL ;
    PORT
      LAYER M5 ;
        RECT  191.52 25.728 191.544 25.92 ;
    END
  END i[557]
  PIN i[558]
    DIRECTION INPUT ;
    USE SIGNAL ;
    PORT
      LAYER M5 ;
        RECT  191.856 25.728 191.88 25.92 ;
    END
  END i[558]
  PIN i[559]
    DIRECTION INPUT ;
    USE SIGNAL ;
    PORT
      LAYER M5 ;
        RECT  192.192 25.728 192.216 25.92 ;
    END
  END i[559]
  PIN i[55]
    DIRECTION INPUT ;
    USE SIGNAL ;
    PORT
      LAYER M5 ;
        RECT  22.944 25.728 22.968 25.92 ;
    END
  END i[55]
  PIN i[560]
    DIRECTION INPUT ;
    USE SIGNAL ;
    PORT
      LAYER M5 ;
        RECT  192.528 25.728 192.552 25.92 ;
    END
  END i[560]
  PIN i[561]
    DIRECTION INPUT ;
    USE SIGNAL ;
    PORT
      LAYER M5 ;
        RECT  192.864 25.728 192.888 25.92 ;
    END
  END i[561]
  PIN i[562]
    DIRECTION INPUT ;
    USE SIGNAL ;
    PORT
      LAYER M5 ;
        RECT  193.2 25.728 193.224 25.92 ;
    END
  END i[562]
  PIN i[563]
    DIRECTION INPUT ;
    USE SIGNAL ;
    PORT
      LAYER M5 ;
        RECT  193.536 25.728 193.56 25.92 ;
    END
  END i[563]
  PIN i[564]
    DIRECTION INPUT ;
    USE SIGNAL ;
    PORT
      LAYER M5 ;
        RECT  193.872 25.728 193.896 25.92 ;
    END
  END i[564]
  PIN i[565]
    DIRECTION INPUT ;
    USE SIGNAL ;
    PORT
      LAYER M5 ;
        RECT  194.208 25.728 194.232 25.92 ;
    END
  END i[565]
  PIN i[566]
    DIRECTION INPUT ;
    USE SIGNAL ;
    PORT
      LAYER M5 ;
        RECT  194.544 25.728 194.568 25.92 ;
    END
  END i[566]
  PIN i[567]
    DIRECTION INPUT ;
    USE SIGNAL ;
    PORT
      LAYER M5 ;
        RECT  194.88 25.728 194.904 25.92 ;
    END
  END i[567]
  PIN i[568]
    DIRECTION INPUT ;
    USE SIGNAL ;
    PORT
      LAYER M5 ;
        RECT  195.216 25.728 195.24 25.92 ;
    END
  END i[568]
  PIN i[569]
    DIRECTION INPUT ;
    USE SIGNAL ;
    PORT
      LAYER M5 ;
        RECT  195.552 25.728 195.576 25.92 ;
    END
  END i[569]
  PIN i[56]
    DIRECTION INPUT ;
    USE SIGNAL ;
    PORT
      LAYER M5 ;
        RECT  23.28 25.728 23.304 25.92 ;
    END
  END i[56]
  PIN i[570]
    DIRECTION INPUT ;
    USE SIGNAL ;
    PORT
      LAYER M5 ;
        RECT  195.888 25.728 195.912 25.92 ;
    END
  END i[570]
  PIN i[571]
    DIRECTION INPUT ;
    USE SIGNAL ;
    PORT
      LAYER M5 ;
        RECT  196.224 25.728 196.248 25.92 ;
    END
  END i[571]
  PIN i[572]
    DIRECTION INPUT ;
    USE SIGNAL ;
    PORT
      LAYER M5 ;
        RECT  196.56 25.728 196.584 25.92 ;
    END
  END i[572]
  PIN i[573]
    DIRECTION INPUT ;
    USE SIGNAL ;
    PORT
      LAYER M5 ;
        RECT  196.848 25.728 196.872 25.92 ;
    END
  END i[573]
  PIN i[574]
    DIRECTION INPUT ;
    USE SIGNAL ;
    PORT
      LAYER M5 ;
        RECT  197.184 25.728 197.208 25.92 ;
    END
  END i[574]
  PIN i[575]
    DIRECTION INPUT ;
    USE SIGNAL ;
    PORT
      LAYER M5 ;
        RECT  197.52 25.728 197.544 25.92 ;
    END
  END i[575]
  PIN i[576]
    DIRECTION INPUT ;
    USE SIGNAL ;
    PORT
      LAYER M5 ;
        RECT  197.856 25.728 197.88 25.92 ;
    END
  END i[576]
  PIN i[577]
    DIRECTION INPUT ;
    USE SIGNAL ;
    PORT
      LAYER M5 ;
        RECT  198.192 25.728 198.216 25.92 ;
    END
  END i[577]
  PIN i[578]
    DIRECTION INPUT ;
    USE SIGNAL ;
    PORT
      LAYER M5 ;
        RECT  198.528 25.728 198.552 25.92 ;
    END
  END i[578]
  PIN i[579]
    DIRECTION INPUT ;
    USE SIGNAL ;
    PORT
      LAYER M5 ;
        RECT  198.864 25.728 198.888 25.92 ;
    END
  END i[579]
  PIN i[57]
    DIRECTION INPUT ;
    USE SIGNAL ;
    PORT
      LAYER M5 ;
        RECT  23.616 25.728 23.64 25.92 ;
    END
  END i[57]
  PIN i[580]
    DIRECTION INPUT ;
    USE SIGNAL ;
    PORT
      LAYER M5 ;
        RECT  199.2 25.728 199.224 25.92 ;
    END
  END i[580]
  PIN i[581]
    DIRECTION INPUT ;
    USE SIGNAL ;
    PORT
      LAYER M5 ;
        RECT  199.536 25.728 199.56 25.92 ;
    END
  END i[581]
  PIN i[582]
    DIRECTION INPUT ;
    USE SIGNAL ;
    PORT
      LAYER M5 ;
        RECT  199.872 25.728 199.896 25.92 ;
    END
  END i[582]
  PIN i[583]
    DIRECTION INPUT ;
    USE SIGNAL ;
    PORT
      LAYER M5 ;
        RECT  200.208 25.728 200.232 25.92 ;
    END
  END i[583]
  PIN i[584]
    DIRECTION INPUT ;
    USE SIGNAL ;
    PORT
      LAYER M5 ;
        RECT  200.544 25.728 200.568 25.92 ;
    END
  END i[584]
  PIN i[585]
    DIRECTION INPUT ;
    USE SIGNAL ;
    PORT
      LAYER M5 ;
        RECT  200.88 25.728 200.904 25.92 ;
    END
  END i[585]
  PIN i[586]
    DIRECTION INPUT ;
    USE SIGNAL ;
    PORT
      LAYER M5 ;
        RECT  201.216 25.728 201.24 25.92 ;
    END
  END i[586]
  PIN i[587]
    DIRECTION INPUT ;
    USE SIGNAL ;
    PORT
      LAYER M5 ;
        RECT  201.552 25.728 201.576 25.92 ;
    END
  END i[587]
  PIN i[588]
    DIRECTION INPUT ;
    USE SIGNAL ;
    PORT
      LAYER M5 ;
        RECT  201.888 25.728 201.912 25.92 ;
    END
  END i[588]
  PIN i[589]
    DIRECTION INPUT ;
    USE SIGNAL ;
    PORT
      LAYER M5 ;
        RECT  202.224 25.728 202.248 25.92 ;
    END
  END i[589]
  PIN i[58]
    DIRECTION INPUT ;
    USE SIGNAL ;
    PORT
      LAYER M5 ;
        RECT  23.952 25.728 23.976 25.92 ;
    END
  END i[58]
  PIN i[590]
    DIRECTION INPUT ;
    USE SIGNAL ;
    PORT
      LAYER M5 ;
        RECT  202.56 25.728 202.584 25.92 ;
    END
  END i[590]
  PIN i[591]
    DIRECTION INPUT ;
    USE SIGNAL ;
    PORT
      LAYER M5 ;
        RECT  202.896 25.728 202.92 25.92 ;
    END
  END i[591]
  PIN i[592]
    DIRECTION INPUT ;
    USE SIGNAL ;
    PORT
      LAYER M5 ;
        RECT  203.232 25.728 203.256 25.92 ;
    END
  END i[592]
  PIN i[593]
    DIRECTION INPUT ;
    USE SIGNAL ;
    PORT
      LAYER M5 ;
        RECT  203.568 25.728 203.592 25.92 ;
    END
  END i[593]
  PIN i[594]
    DIRECTION INPUT ;
    USE SIGNAL ;
    PORT
      LAYER M5 ;
        RECT  203.904 25.728 203.928 25.92 ;
    END
  END i[594]
  PIN i[595]
    DIRECTION INPUT ;
    USE SIGNAL ;
    PORT
      LAYER M5 ;
        RECT  204.24 25.728 204.264 25.92 ;
    END
  END i[595]
  PIN i[596]
    DIRECTION INPUT ;
    USE SIGNAL ;
    PORT
      LAYER M5 ;
        RECT  204.576 25.728 204.6 25.92 ;
    END
  END i[596]
  PIN i[597]
    DIRECTION INPUT ;
    USE SIGNAL ;
    PORT
      LAYER M5 ;
        RECT  204.912 25.728 204.936 25.92 ;
    END
  END i[597]
  PIN i[598]
    DIRECTION INPUT ;
    USE SIGNAL ;
    PORT
      LAYER M5 ;
        RECT  205.248 25.728 205.272 25.92 ;
    END
  END i[598]
  PIN i[599]
    DIRECTION INPUT ;
    USE SIGNAL ;
    PORT
      LAYER M5 ;
        RECT  205.584 25.728 205.608 25.92 ;
    END
  END i[599]
  PIN i[59]
    DIRECTION INPUT ;
    USE SIGNAL ;
    PORT
      LAYER M5 ;
        RECT  24.288 25.728 24.312 25.92 ;
    END
  END i[59]
  PIN i[5]
    DIRECTION INPUT ;
    USE SIGNAL ;
    PORT
      LAYER M5 ;
        RECT  6.192 25.728 6.216 25.92 ;
    END
  END i[5]
  PIN i[600]
    DIRECTION INPUT ;
    USE SIGNAL ;
    PORT
      LAYER M5 ;
        RECT  205.92 25.728 205.944 25.92 ;
    END
  END i[600]
  PIN i[601]
    DIRECTION INPUT ;
    USE SIGNAL ;
    PORT
      LAYER M5 ;
        RECT  206.256 25.728 206.28 25.92 ;
    END
  END i[601]
  PIN i[602]
    DIRECTION INPUT ;
    USE SIGNAL ;
    PORT
      LAYER M5 ;
        RECT  206.592 25.728 206.616 25.92 ;
    END
  END i[602]
  PIN i[603]
    DIRECTION INPUT ;
    USE SIGNAL ;
    PORT
      LAYER M5 ;
        RECT  206.928 25.728 206.952 25.92 ;
    END
  END i[603]
  PIN i[604]
    DIRECTION INPUT ;
    USE SIGNAL ;
    PORT
      LAYER M5 ;
        RECT  207.264 25.728 207.288 25.92 ;
    END
  END i[604]
  PIN i[605]
    DIRECTION INPUT ;
    USE SIGNAL ;
    PORT
      LAYER M5 ;
        RECT  207.6 25.728 207.624 25.92 ;
    END
  END i[605]
  PIN i[606]
    DIRECTION INPUT ;
    USE SIGNAL ;
    PORT
      LAYER M5 ;
        RECT  207.936 25.728 207.96 25.92 ;
    END
  END i[606]
  PIN i[607]
    DIRECTION INPUT ;
    USE SIGNAL ;
    PORT
      LAYER M5 ;
        RECT  208.272 25.728 208.296 25.92 ;
    END
  END i[607]
  PIN i[608]
    DIRECTION INPUT ;
    USE SIGNAL ;
    PORT
      LAYER M5 ;
        RECT  208.608 25.728 208.632 25.92 ;
    END
  END i[608]
  PIN i[609]
    DIRECTION INPUT ;
    USE SIGNAL ;
    PORT
      LAYER M5 ;
        RECT  208.944 25.728 208.968 25.92 ;
    END
  END i[609]
  PIN i[60]
    DIRECTION INPUT ;
    USE SIGNAL ;
    PORT
      LAYER M5 ;
        RECT  24.624 25.728 24.648 25.92 ;
    END
  END i[60]
  PIN i[610]
    DIRECTION INPUT ;
    USE SIGNAL ;
    PORT
      LAYER M5 ;
        RECT  209.28 25.728 209.304 25.92 ;
    END
  END i[610]
  PIN i[611]
    DIRECTION INPUT ;
    USE SIGNAL ;
    PORT
      LAYER M5 ;
        RECT  209.616 25.728 209.64 25.92 ;
    END
  END i[611]
  PIN i[612]
    DIRECTION INPUT ;
    USE SIGNAL ;
    PORT
      LAYER M5 ;
        RECT  209.952 25.728 209.976 25.92 ;
    END
  END i[612]
  PIN i[613]
    DIRECTION INPUT ;
    USE SIGNAL ;
    PORT
      LAYER M5 ;
        RECT  210.288 25.728 210.312 25.92 ;
    END
  END i[613]
  PIN i[614]
    DIRECTION INPUT ;
    USE SIGNAL ;
    PORT
      LAYER M5 ;
        RECT  210.624 25.728 210.648 25.92 ;
    END
  END i[614]
  PIN i[615]
    DIRECTION INPUT ;
    USE SIGNAL ;
    PORT
      LAYER M5 ;
        RECT  210.96 25.728 210.984 25.92 ;
    END
  END i[615]
  PIN i[616]
    DIRECTION INPUT ;
    USE SIGNAL ;
    PORT
      LAYER M5 ;
        RECT  211.296 25.728 211.32 25.92 ;
    END
  END i[616]
  PIN i[617]
    DIRECTION INPUT ;
    USE SIGNAL ;
    PORT
      LAYER M5 ;
        RECT  211.632 25.728 211.656 25.92 ;
    END
  END i[617]
  PIN i[618]
    DIRECTION INPUT ;
    USE SIGNAL ;
    PORT
      LAYER M5 ;
        RECT  211.968 25.728 211.992 25.92 ;
    END
  END i[618]
  PIN i[619]
    DIRECTION INPUT ;
    USE SIGNAL ;
    PORT
      LAYER M5 ;
        RECT  212.304 25.728 212.328 25.92 ;
    END
  END i[619]
  PIN i[61]
    DIRECTION INPUT ;
    USE SIGNAL ;
    PORT
      LAYER M5 ;
        RECT  24.96 25.728 24.984 25.92 ;
    END
  END i[61]
  PIN i[620]
    DIRECTION INPUT ;
    USE SIGNAL ;
    PORT
      LAYER M5 ;
        RECT  212.64 25.728 212.664 25.92 ;
    END
  END i[620]
  PIN i[621]
    DIRECTION INPUT ;
    USE SIGNAL ;
    PORT
      LAYER M5 ;
        RECT  212.976 25.728 213 25.92 ;
    END
  END i[621]
  PIN i[622]
    DIRECTION INPUT ;
    USE SIGNAL ;
    PORT
      LAYER M5 ;
        RECT  213.312 25.728 213.336 25.92 ;
    END
  END i[622]
  PIN i[623]
    DIRECTION INPUT ;
    USE SIGNAL ;
    PORT
      LAYER M5 ;
        RECT  213.648 25.728 213.672 25.92 ;
    END
  END i[623]
  PIN i[62]
    DIRECTION INPUT ;
    USE SIGNAL ;
    PORT
      LAYER M5 ;
        RECT  25.296 25.728 25.32 25.92 ;
    END
  END i[62]
  PIN i[63]
    DIRECTION INPUT ;
    USE SIGNAL ;
    PORT
      LAYER M5 ;
        RECT  25.632 25.728 25.656 25.92 ;
    END
  END i[63]
  PIN i[64]
    DIRECTION INPUT ;
    USE SIGNAL ;
    PORT
      LAYER M5 ;
        RECT  25.968 25.728 25.992 25.92 ;
    END
  END i[64]
  PIN i[65]
    DIRECTION INPUT ;
    USE SIGNAL ;
    PORT
      LAYER M5 ;
        RECT  26.304 25.728 26.328 25.92 ;
    END
  END i[65]
  PIN i[66]
    DIRECTION INPUT ;
    USE SIGNAL ;
    PORT
      LAYER M5 ;
        RECT  26.64 25.728 26.664 25.92 ;
    END
  END i[66]
  PIN i[67]
    DIRECTION INPUT ;
    USE SIGNAL ;
    PORT
      LAYER M5 ;
        RECT  26.976 25.728 27 25.92 ;
    END
  END i[67]
  PIN i[68]
    DIRECTION INPUT ;
    USE SIGNAL ;
    PORT
      LAYER M5 ;
        RECT  27.312 25.728 27.336 25.92 ;
    END
  END i[68]
  PIN i[69]
    DIRECTION INPUT ;
    USE SIGNAL ;
    PORT
      LAYER M5 ;
        RECT  27.648 25.728 27.672 25.92 ;
    END
  END i[69]
  PIN i[6]
    DIRECTION INPUT ;
    USE SIGNAL ;
    PORT
      LAYER M5 ;
        RECT  6.528 25.728 6.552 25.92 ;
    END
  END i[6]
  PIN i[70]
    DIRECTION INPUT ;
    USE SIGNAL ;
    PORT
      LAYER M5 ;
        RECT  27.984 25.728 28.008 25.92 ;
    END
  END i[70]
  PIN i[71]
    DIRECTION INPUT ;
    USE SIGNAL ;
    PORT
      LAYER M5 ;
        RECT  28.32 25.728 28.344 25.92 ;
    END
  END i[71]
  PIN i[72]
    DIRECTION INPUT ;
    USE SIGNAL ;
    PORT
      LAYER M5 ;
        RECT  28.656 25.728 28.68 25.92 ;
    END
  END i[72]
  PIN i[73]
    DIRECTION INPUT ;
    USE SIGNAL ;
    PORT
      LAYER M5 ;
        RECT  28.992 25.728 29.016 25.92 ;
    END
  END i[73]
  PIN i[74]
    DIRECTION INPUT ;
    USE SIGNAL ;
    PORT
      LAYER M5 ;
        RECT  29.328 25.728 29.352 25.92 ;
    END
  END i[74]
  PIN i[75]
    DIRECTION INPUT ;
    USE SIGNAL ;
    PORT
      LAYER M5 ;
        RECT  29.664 25.728 29.688 25.92 ;
    END
  END i[75]
  PIN i[76]
    DIRECTION INPUT ;
    USE SIGNAL ;
    PORT
      LAYER M5 ;
        RECT  30 25.728 30.024 25.92 ;
    END
  END i[76]
  PIN i[77]
    DIRECTION INPUT ;
    USE SIGNAL ;
    PORT
      LAYER M5 ;
        RECT  30.336 25.728 30.36 25.92 ;
    END
  END i[77]
  PIN i[78]
    DIRECTION INPUT ;
    USE SIGNAL ;
    PORT
      LAYER M5 ;
        RECT  30.624 25.728 30.648 25.92 ;
    END
  END i[78]
  PIN i[79]
    DIRECTION INPUT ;
    USE SIGNAL ;
    PORT
      LAYER M5 ;
        RECT  30.96 25.728 30.984 25.92 ;
    END
  END i[79]
  PIN i[7]
    DIRECTION INPUT ;
    USE SIGNAL ;
    PORT
      LAYER M5 ;
        RECT  6.864 25.728 6.888 25.92 ;
    END
  END i[7]
  PIN i[80]
    DIRECTION INPUT ;
    USE SIGNAL ;
    PORT
      LAYER M5 ;
        RECT  31.296 25.728 31.32 25.92 ;
    END
  END i[80]
  PIN i[81]
    DIRECTION INPUT ;
    USE SIGNAL ;
    PORT
      LAYER M5 ;
        RECT  31.632 25.728 31.656 25.92 ;
    END
  END i[81]
  PIN i[82]
    DIRECTION INPUT ;
    USE SIGNAL ;
    PORT
      LAYER M5 ;
        RECT  31.968 25.728 31.992 25.92 ;
    END
  END i[82]
  PIN i[83]
    DIRECTION INPUT ;
    USE SIGNAL ;
    PORT
      LAYER M5 ;
        RECT  32.304 25.728 32.328 25.92 ;
    END
  END i[83]
  PIN i[84]
    DIRECTION INPUT ;
    USE SIGNAL ;
    PORT
      LAYER M5 ;
        RECT  32.64 25.728 32.664 25.92 ;
    END
  END i[84]
  PIN i[85]
    DIRECTION INPUT ;
    USE SIGNAL ;
    PORT
      LAYER M5 ;
        RECT  32.976 25.728 33 25.92 ;
    END
  END i[85]
  PIN i[86]
    DIRECTION INPUT ;
    USE SIGNAL ;
    PORT
      LAYER M5 ;
        RECT  33.312 25.728 33.336 25.92 ;
    END
  END i[86]
  PIN i[87]
    DIRECTION INPUT ;
    USE SIGNAL ;
    PORT
      LAYER M5 ;
        RECT  33.648 25.728 33.672 25.92 ;
    END
  END i[87]
  PIN i[88]
    DIRECTION INPUT ;
    USE SIGNAL ;
    PORT
      LAYER M5 ;
        RECT  33.984 25.728 34.008 25.92 ;
    END
  END i[88]
  PIN i[89]
    DIRECTION INPUT ;
    USE SIGNAL ;
    PORT
      LAYER M5 ;
        RECT  34.32 25.728 34.344 25.92 ;
    END
  END i[89]
  PIN i[8]
    DIRECTION INPUT ;
    USE SIGNAL ;
    PORT
      LAYER M5 ;
        RECT  7.2 25.728 7.224 25.92 ;
    END
  END i[8]
  PIN i[90]
    DIRECTION INPUT ;
    USE SIGNAL ;
    PORT
      LAYER M5 ;
        RECT  34.656 25.728 34.68 25.92 ;
    END
  END i[90]
  PIN i[91]
    DIRECTION INPUT ;
    USE SIGNAL ;
    PORT
      LAYER M5 ;
        RECT  34.992 25.728 35.016 25.92 ;
    END
  END i[91]
  PIN i[92]
    DIRECTION INPUT ;
    USE SIGNAL ;
    PORT
      LAYER M5 ;
        RECT  35.328 25.728 35.352 25.92 ;
    END
  END i[92]
  PIN i[93]
    DIRECTION INPUT ;
    USE SIGNAL ;
    PORT
      LAYER M5 ;
        RECT  35.664 25.728 35.688 25.92 ;
    END
  END i[93]
  PIN i[94]
    DIRECTION INPUT ;
    USE SIGNAL ;
    PORT
      LAYER M5 ;
        RECT  36 25.728 36.024 25.92 ;
    END
  END i[94]
  PIN i[95]
    DIRECTION INPUT ;
    USE SIGNAL ;
    PORT
      LAYER M5 ;
        RECT  36.336 25.728 36.36 25.92 ;
    END
  END i[95]
  PIN i[96]
    DIRECTION INPUT ;
    USE SIGNAL ;
    PORT
      LAYER M5 ;
        RECT  36.672 25.728 36.696 25.92 ;
    END
  END i[96]
  PIN i[97]
    DIRECTION INPUT ;
    USE SIGNAL ;
    PORT
      LAYER M5 ;
        RECT  37.008 25.728 37.032 25.92 ;
    END
  END i[97]
  PIN i[98]
    DIRECTION INPUT ;
    USE SIGNAL ;
    PORT
      LAYER M5 ;
        RECT  37.344 25.728 37.368 25.92 ;
    END
  END i[98]
  PIN i[99]
    DIRECTION INPUT ;
    USE SIGNAL ;
    PORT
      LAYER M5 ;
        RECT  37.68 25.728 37.704 25.92 ;
    END
  END i[99]
  PIN i[9]
    DIRECTION INPUT ;
    USE SIGNAL ;
    PORT
      LAYER M5 ;
        RECT  7.536 25.728 7.56 25.92 ;
    END
  END i[9]
  PIN o0[0]
    DIRECTION OUTPUT ;
    USE SIGNAL ;
    PORT
      LAYER M5 ;
        RECT  4.512 0 4.536 0.192 ;
    END
  END o0[0]
  PIN o0[100]
    DIRECTION OUTPUT ;
    USE SIGNAL ;
    PORT
      LAYER M5 ;
        RECT  21.216 0 21.24 0.192 ;
    END
  END o0[100]
  PIN o0[101]
    DIRECTION OUTPUT ;
    USE SIGNAL ;
    PORT
      LAYER M5 ;
        RECT  21.408 0 21.432 0.192 ;
    END
  END o0[101]
  PIN o0[102]
    DIRECTION OUTPUT ;
    USE SIGNAL ;
    PORT
      LAYER M5 ;
        RECT  21.552 0 21.576 0.192 ;
    END
  END o0[102]
  PIN o0[103]
    DIRECTION OUTPUT ;
    USE SIGNAL ;
    PORT
      LAYER M5 ;
        RECT  21.744 0 21.768 0.192 ;
    END
  END o0[103]
  PIN o0[104]
    DIRECTION OUTPUT ;
    USE SIGNAL ;
    PORT
      LAYER M5 ;
        RECT  21.888 0 21.912 0.192 ;
    END
  END o0[104]
  PIN o0[105]
    DIRECTION OUTPUT ;
    USE SIGNAL ;
    PORT
      LAYER M5 ;
        RECT  22.08 0 22.104 0.192 ;
    END
  END o0[105]
  PIN o0[106]
    DIRECTION OUTPUT ;
    USE SIGNAL ;
    PORT
      LAYER M5 ;
        RECT  22.224 0 22.248 0.192 ;
    END
  END o0[106]
  PIN o0[107]
    DIRECTION OUTPUT ;
    USE SIGNAL ;
    PORT
      LAYER M5 ;
        RECT  22.416 0 22.44 0.192 ;
    END
  END o0[107]
  PIN o0[108]
    DIRECTION OUTPUT ;
    USE SIGNAL ;
    PORT
      LAYER M5 ;
        RECT  22.56 0 22.584 0.192 ;
    END
  END o0[108]
  PIN o0[109]
    DIRECTION OUTPUT ;
    USE SIGNAL ;
    PORT
      LAYER M5 ;
        RECT  22.752 0 22.776 0.192 ;
    END
  END o0[109]
  PIN o0[10]
    DIRECTION OUTPUT ;
    USE SIGNAL ;
    PORT
      LAYER M5 ;
        RECT  6.192 0 6.216 0.192 ;
    END
  END o0[10]
  PIN o0[110]
    DIRECTION OUTPUT ;
    USE SIGNAL ;
    PORT
      LAYER M5 ;
        RECT  22.896 0 22.92 0.192 ;
    END
  END o0[110]
  PIN o0[111]
    DIRECTION OUTPUT ;
    USE SIGNAL ;
    PORT
      LAYER M5 ;
        RECT  23.088 0 23.112 0.192 ;
    END
  END o0[111]
  PIN o0[112]
    DIRECTION OUTPUT ;
    USE SIGNAL ;
    PORT
      LAYER M5 ;
        RECT  23.232 0 23.256 0.192 ;
    END
  END o0[112]
  PIN o0[113]
    DIRECTION OUTPUT ;
    USE SIGNAL ;
    PORT
      LAYER M5 ;
        RECT  23.424 0 23.448 0.192 ;
    END
  END o0[113]
  PIN o0[114]
    DIRECTION OUTPUT ;
    USE SIGNAL ;
    PORT
      LAYER M5 ;
        RECT  23.568 0 23.592 0.192 ;
    END
  END o0[114]
  PIN o0[115]
    DIRECTION OUTPUT ;
    USE SIGNAL ;
    PORT
      LAYER M5 ;
        RECT  23.76 0 23.784 0.192 ;
    END
  END o0[115]
  PIN o0[116]
    DIRECTION OUTPUT ;
    USE SIGNAL ;
    PORT
      LAYER M5 ;
        RECT  23.904 0 23.928 0.192 ;
    END
  END o0[116]
  PIN o0[117]
    DIRECTION OUTPUT ;
    USE SIGNAL ;
    PORT
      LAYER M5 ;
        RECT  24.096 0 24.12 0.192 ;
    END
  END o0[117]
  PIN o0[118]
    DIRECTION OUTPUT ;
    USE SIGNAL ;
    PORT
      LAYER M5 ;
        RECT  24.24 0 24.264 0.192 ;
    END
  END o0[118]
  PIN o0[119]
    DIRECTION OUTPUT ;
    USE SIGNAL ;
    PORT
      LAYER M5 ;
        RECT  24.432 0 24.456 0.192 ;
    END
  END o0[119]
  PIN o0[11]
    DIRECTION OUTPUT ;
    USE SIGNAL ;
    PORT
      LAYER M5 ;
        RECT  6.336 0 6.36 0.192 ;
    END
  END o0[11]
  PIN o0[120]
    DIRECTION OUTPUT ;
    USE SIGNAL ;
    PORT
      LAYER M5 ;
        RECT  24.576 0 24.6 0.192 ;
    END
  END o0[120]
  PIN o0[121]
    DIRECTION OUTPUT ;
    USE SIGNAL ;
    PORT
      LAYER M5 ;
        RECT  24.768 0 24.792 0.192 ;
    END
  END o0[121]
  PIN o0[122]
    DIRECTION OUTPUT ;
    USE SIGNAL ;
    PORT
      LAYER M5 ;
        RECT  24.912 0 24.936 0.192 ;
    END
  END o0[122]
  PIN o0[123]
    DIRECTION OUTPUT ;
    USE SIGNAL ;
    PORT
      LAYER M5 ;
        RECT  25.056 0 25.08 0.192 ;
    END
  END o0[123]
  PIN o0[124]
    DIRECTION OUTPUT ;
    USE SIGNAL ;
    PORT
      LAYER M5 ;
        RECT  25.248 0 25.272 0.192 ;
    END
  END o0[124]
  PIN o0[125]
    DIRECTION OUTPUT ;
    USE SIGNAL ;
    PORT
      LAYER M5 ;
        RECT  25.392 0 25.416 0.192 ;
    END
  END o0[125]
  PIN o0[126]
    DIRECTION OUTPUT ;
    USE SIGNAL ;
    PORT
      LAYER M5 ;
        RECT  25.584 0 25.608 0.192 ;
    END
  END o0[126]
  PIN o0[127]
    DIRECTION OUTPUT ;
    USE SIGNAL ;
    PORT
      LAYER M5 ;
        RECT  25.728 0 25.752 0.192 ;
    END
  END o0[127]
  PIN o0[128]
    DIRECTION OUTPUT ;
    USE SIGNAL ;
    PORT
      LAYER M5 ;
        RECT  25.92 0 25.944 0.192 ;
    END
  END o0[128]
  PIN o0[129]
    DIRECTION OUTPUT ;
    USE SIGNAL ;
    PORT
      LAYER M5 ;
        RECT  26.064 0 26.088 0.192 ;
    END
  END o0[129]
  PIN o0[12]
    DIRECTION OUTPUT ;
    USE SIGNAL ;
    PORT
      LAYER M5 ;
        RECT  6.528 0 6.552 0.192 ;
    END
  END o0[12]
  PIN o0[130]
    DIRECTION OUTPUT ;
    USE SIGNAL ;
    PORT
      LAYER M5 ;
        RECT  26.256 0 26.28 0.192 ;
    END
  END o0[130]
  PIN o0[131]
    DIRECTION OUTPUT ;
    USE SIGNAL ;
    PORT
      LAYER M5 ;
        RECT  26.4 0 26.424 0.192 ;
    END
  END o0[131]
  PIN o0[132]
    DIRECTION OUTPUT ;
    USE SIGNAL ;
    PORT
      LAYER M5 ;
        RECT  26.592 0 26.616 0.192 ;
    END
  END o0[132]
  PIN o0[133]
    DIRECTION OUTPUT ;
    USE SIGNAL ;
    PORT
      LAYER M5 ;
        RECT  26.736 0 26.76 0.192 ;
    END
  END o0[133]
  PIN o0[134]
    DIRECTION OUTPUT ;
    USE SIGNAL ;
    PORT
      LAYER M5 ;
        RECT  26.928 0 26.952 0.192 ;
    END
  END o0[134]
  PIN o0[135]
    DIRECTION OUTPUT ;
    USE SIGNAL ;
    PORT
      LAYER M5 ;
        RECT  27.072 0 27.096 0.192 ;
    END
  END o0[135]
  PIN o0[136]
    DIRECTION OUTPUT ;
    USE SIGNAL ;
    PORT
      LAYER M5 ;
        RECT  27.264 0 27.288 0.192 ;
    END
  END o0[136]
  PIN o0[137]
    DIRECTION OUTPUT ;
    USE SIGNAL ;
    PORT
      LAYER M5 ;
        RECT  27.408 0 27.432 0.192 ;
    END
  END o0[137]
  PIN o0[138]
    DIRECTION OUTPUT ;
    USE SIGNAL ;
    PORT
      LAYER M5 ;
        RECT  27.6 0 27.624 0.192 ;
    END
  END o0[138]
  PIN o0[139]
    DIRECTION OUTPUT ;
    USE SIGNAL ;
    PORT
      LAYER M5 ;
        RECT  27.744 0 27.768 0.192 ;
    END
  END o0[139]
  PIN o0[13]
    DIRECTION OUTPUT ;
    USE SIGNAL ;
    PORT
      LAYER M5 ;
        RECT  6.672 0 6.696 0.192 ;
    END
  END o0[13]
  PIN o0[140]
    DIRECTION OUTPUT ;
    USE SIGNAL ;
    PORT
      LAYER M5 ;
        RECT  27.936 0 27.96 0.192 ;
    END
  END o0[140]
  PIN o0[141]
    DIRECTION OUTPUT ;
    USE SIGNAL ;
    PORT
      LAYER M5 ;
        RECT  28.08 0 28.104 0.192 ;
    END
  END o0[141]
  PIN o0[142]
    DIRECTION OUTPUT ;
    USE SIGNAL ;
    PORT
      LAYER M5 ;
        RECT  28.272 0 28.296 0.192 ;
    END
  END o0[142]
  PIN o0[143]
    DIRECTION OUTPUT ;
    USE SIGNAL ;
    PORT
      LAYER M5 ;
        RECT  28.416 0 28.44 0.192 ;
    END
  END o0[143]
  PIN o0[144]
    DIRECTION OUTPUT ;
    USE SIGNAL ;
    PORT
      LAYER M5 ;
        RECT  28.608 0 28.632 0.192 ;
    END
  END o0[144]
  PIN o0[145]
    DIRECTION OUTPUT ;
    USE SIGNAL ;
    PORT
      LAYER M5 ;
        RECT  28.752 0 28.776 0.192 ;
    END
  END o0[145]
  PIN o0[146]
    DIRECTION OUTPUT ;
    USE SIGNAL ;
    PORT
      LAYER M5 ;
        RECT  28.944 0 28.968 0.192 ;
    END
  END o0[146]
  PIN o0[147]
    DIRECTION OUTPUT ;
    USE SIGNAL ;
    PORT
      LAYER M5 ;
        RECT  29.088 0 29.112 0.192 ;
    END
  END o0[147]
  PIN o0[148]
    DIRECTION OUTPUT ;
    USE SIGNAL ;
    PORT
      LAYER M5 ;
        RECT  29.28 0 29.304 0.192 ;
    END
  END o0[148]
  PIN o0[149]
    DIRECTION OUTPUT ;
    USE SIGNAL ;
    PORT
      LAYER M5 ;
        RECT  29.424 0 29.448 0.192 ;
    END
  END o0[149]
  PIN o0[14]
    DIRECTION OUTPUT ;
    USE SIGNAL ;
    PORT
      LAYER M5 ;
        RECT  6.864 0 6.888 0.192 ;
    END
  END o0[14]
  PIN o0[150]
    DIRECTION OUTPUT ;
    USE SIGNAL ;
    PORT
      LAYER M5 ;
        RECT  29.616 0 29.64 0.192 ;
    END
  END o0[150]
  PIN o0[151]
    DIRECTION OUTPUT ;
    USE SIGNAL ;
    PORT
      LAYER M5 ;
        RECT  29.76 0 29.784 0.192 ;
    END
  END o0[151]
  PIN o0[152]
    DIRECTION OUTPUT ;
    USE SIGNAL ;
    PORT
      LAYER M5 ;
        RECT  29.952 0 29.976 0.192 ;
    END
  END o0[152]
  PIN o0[153]
    DIRECTION OUTPUT ;
    USE SIGNAL ;
    PORT
      LAYER M5 ;
        RECT  30.096 0 30.12 0.192 ;
    END
  END o0[153]
  PIN o0[154]
    DIRECTION OUTPUT ;
    USE SIGNAL ;
    PORT
      LAYER M5 ;
        RECT  30.24 0 30.264 0.192 ;
    END
  END o0[154]
  PIN o0[155]
    DIRECTION OUTPUT ;
    USE SIGNAL ;
    PORT
      LAYER M5 ;
        RECT  30.432 0 30.456 0.192 ;
    END
  END o0[155]
  PIN o0[156]
    DIRECTION OUTPUT ;
    USE SIGNAL ;
    PORT
      LAYER M5 ;
        RECT  30.576 0 30.6 0.192 ;
    END
  END o0[156]
  PIN o0[157]
    DIRECTION OUTPUT ;
    USE SIGNAL ;
    PORT
      LAYER M5 ;
        RECT  30.768 0 30.792 0.192 ;
    END
  END o0[157]
  PIN o0[158]
    DIRECTION OUTPUT ;
    USE SIGNAL ;
    PORT
      LAYER M5 ;
        RECT  30.912 0 30.936 0.192 ;
    END
  END o0[158]
  PIN o0[159]
    DIRECTION OUTPUT ;
    USE SIGNAL ;
    PORT
      LAYER M5 ;
        RECT  31.104 0 31.128 0.192 ;
    END
  END o0[159]
  PIN o0[15]
    DIRECTION OUTPUT ;
    USE SIGNAL ;
    PORT
      LAYER M5 ;
        RECT  7.008 0 7.032 0.192 ;
    END
  END o0[15]
  PIN o0[160]
    DIRECTION OUTPUT ;
    USE SIGNAL ;
    PORT
      LAYER M5 ;
        RECT  31.248 0 31.272 0.192 ;
    END
  END o0[160]
  PIN o0[161]
    DIRECTION OUTPUT ;
    USE SIGNAL ;
    PORT
      LAYER M5 ;
        RECT  31.44 0 31.464 0.192 ;
    END
  END o0[161]
  PIN o0[162]
    DIRECTION OUTPUT ;
    USE SIGNAL ;
    PORT
      LAYER M5 ;
        RECT  31.584 0 31.608 0.192 ;
    END
  END o0[162]
  PIN o0[163]
    DIRECTION OUTPUT ;
    USE SIGNAL ;
    PORT
      LAYER M5 ;
        RECT  31.776 0 31.8 0.192 ;
    END
  END o0[163]
  PIN o0[164]
    DIRECTION OUTPUT ;
    USE SIGNAL ;
    PORT
      LAYER M5 ;
        RECT  31.92 0 31.944 0.192 ;
    END
  END o0[164]
  PIN o0[165]
    DIRECTION OUTPUT ;
    USE SIGNAL ;
    PORT
      LAYER M5 ;
        RECT  32.112 0 32.136 0.192 ;
    END
  END o0[165]
  PIN o0[166]
    DIRECTION OUTPUT ;
    USE SIGNAL ;
    PORT
      LAYER M5 ;
        RECT  32.256 0 32.28 0.192 ;
    END
  END o0[166]
  PIN o0[167]
    DIRECTION OUTPUT ;
    USE SIGNAL ;
    PORT
      LAYER M5 ;
        RECT  32.448 0 32.472 0.192 ;
    END
  END o0[167]
  PIN o0[168]
    DIRECTION OUTPUT ;
    USE SIGNAL ;
    PORT
      LAYER M5 ;
        RECT  32.592 0 32.616 0.192 ;
    END
  END o0[168]
  PIN o0[169]
    DIRECTION OUTPUT ;
    USE SIGNAL ;
    PORT
      LAYER M5 ;
        RECT  32.784 0 32.808 0.192 ;
    END
  END o0[169]
  PIN o0[16]
    DIRECTION OUTPUT ;
    USE SIGNAL ;
    PORT
      LAYER M5 ;
        RECT  7.2 0 7.224 0.192 ;
    END
  END o0[16]
  PIN o0[170]
    DIRECTION OUTPUT ;
    USE SIGNAL ;
    PORT
      LAYER M5 ;
        RECT  32.928 0 32.952 0.192 ;
    END
  END o0[170]
  PIN o0[171]
    DIRECTION OUTPUT ;
    USE SIGNAL ;
    PORT
      LAYER M5 ;
        RECT  33.12 0 33.144 0.192 ;
    END
  END o0[171]
  PIN o0[172]
    DIRECTION OUTPUT ;
    USE SIGNAL ;
    PORT
      LAYER M5 ;
        RECT  33.264 0 33.288 0.192 ;
    END
  END o0[172]
  PIN o0[173]
    DIRECTION OUTPUT ;
    USE SIGNAL ;
    PORT
      LAYER M5 ;
        RECT  33.456 0 33.48 0.192 ;
    END
  END o0[173]
  PIN o0[174]
    DIRECTION OUTPUT ;
    USE SIGNAL ;
    PORT
      LAYER M5 ;
        RECT  33.6 0 33.624 0.192 ;
    END
  END o0[174]
  PIN o0[175]
    DIRECTION OUTPUT ;
    USE SIGNAL ;
    PORT
      LAYER M5 ;
        RECT  33.792 0 33.816 0.192 ;
    END
  END o0[175]
  PIN o0[176]
    DIRECTION OUTPUT ;
    USE SIGNAL ;
    PORT
      LAYER M5 ;
        RECT  33.936 0 33.96 0.192 ;
    END
  END o0[176]
  PIN o0[177]
    DIRECTION OUTPUT ;
    USE SIGNAL ;
    PORT
      LAYER M5 ;
        RECT  34.128 0 34.152 0.192 ;
    END
  END o0[177]
  PIN o0[178]
    DIRECTION OUTPUT ;
    USE SIGNAL ;
    PORT
      LAYER M5 ;
        RECT  34.272 0 34.296 0.192 ;
    END
  END o0[178]
  PIN o0[179]
    DIRECTION OUTPUT ;
    USE SIGNAL ;
    PORT
      LAYER M5 ;
        RECT  34.464 0 34.488 0.192 ;
    END
  END o0[179]
  PIN o0[17]
    DIRECTION OUTPUT ;
    USE SIGNAL ;
    PORT
      LAYER M5 ;
        RECT  7.344 0 7.368 0.192 ;
    END
  END o0[17]
  PIN o0[180]
    DIRECTION OUTPUT ;
    USE SIGNAL ;
    PORT
      LAYER M5 ;
        RECT  34.608 0 34.632 0.192 ;
    END
  END o0[180]
  PIN o0[181]
    DIRECTION OUTPUT ;
    USE SIGNAL ;
    PORT
      LAYER M5 ;
        RECT  34.8 0 34.824 0.192 ;
    END
  END o0[181]
  PIN o0[182]
    DIRECTION OUTPUT ;
    USE SIGNAL ;
    PORT
      LAYER M5 ;
        RECT  34.944 0 34.968 0.192 ;
    END
  END o0[182]
  PIN o0[183]
    DIRECTION OUTPUT ;
    USE SIGNAL ;
    PORT
      LAYER M5 ;
        RECT  35.136 0 35.16 0.192 ;
    END
  END o0[183]
  PIN o0[184]
    DIRECTION OUTPUT ;
    USE SIGNAL ;
    PORT
      LAYER M5 ;
        RECT  35.28 0 35.304 0.192 ;
    END
  END o0[184]
  PIN o0[185]
    DIRECTION OUTPUT ;
    USE SIGNAL ;
    PORT
      LAYER M5 ;
        RECT  35.472 0 35.496 0.192 ;
    END
  END o0[185]
  PIN o0[186]
    DIRECTION OUTPUT ;
    USE SIGNAL ;
    PORT
      LAYER M5 ;
        RECT  35.616 0 35.64 0.192 ;
    END
  END o0[186]
  PIN o0[187]
    DIRECTION OUTPUT ;
    USE SIGNAL ;
    PORT
      LAYER M5 ;
        RECT  35.76 0 35.784 0.192 ;
    END
  END o0[187]
  PIN o0[188]
    DIRECTION OUTPUT ;
    USE SIGNAL ;
    PORT
      LAYER M5 ;
        RECT  35.952 0 35.976 0.192 ;
    END
  END o0[188]
  PIN o0[189]
    DIRECTION OUTPUT ;
    USE SIGNAL ;
    PORT
      LAYER M5 ;
        RECT  36.096 0 36.12 0.192 ;
    END
  END o0[189]
  PIN o0[18]
    DIRECTION OUTPUT ;
    USE SIGNAL ;
    PORT
      LAYER M5 ;
        RECT  7.536 0 7.56 0.192 ;
    END
  END o0[18]
  PIN o0[190]
    DIRECTION OUTPUT ;
    USE SIGNAL ;
    PORT
      LAYER M5 ;
        RECT  36.288 0 36.312 0.192 ;
    END
  END o0[190]
  PIN o0[191]
    DIRECTION OUTPUT ;
    USE SIGNAL ;
    PORT
      LAYER M5 ;
        RECT  36.432 0 36.456 0.192 ;
    END
  END o0[191]
  PIN o0[192]
    DIRECTION OUTPUT ;
    USE SIGNAL ;
    PORT
      LAYER M5 ;
        RECT  36.624 0 36.648 0.192 ;
    END
  END o0[192]
  PIN o0[193]
    DIRECTION OUTPUT ;
    USE SIGNAL ;
    PORT
      LAYER M5 ;
        RECT  36.768 0 36.792 0.192 ;
    END
  END o0[193]
  PIN o0[194]
    DIRECTION OUTPUT ;
    USE SIGNAL ;
    PORT
      LAYER M5 ;
        RECT  36.96 0 36.984 0.192 ;
    END
  END o0[194]
  PIN o0[195]
    DIRECTION OUTPUT ;
    USE SIGNAL ;
    PORT
      LAYER M5 ;
        RECT  37.104 0 37.128 0.192 ;
    END
  END o0[195]
  PIN o0[196]
    DIRECTION OUTPUT ;
    USE SIGNAL ;
    PORT
      LAYER M5 ;
        RECT  37.296 0 37.32 0.192 ;
    END
  END o0[196]
  PIN o0[197]
    DIRECTION OUTPUT ;
    USE SIGNAL ;
    PORT
      LAYER M5 ;
        RECT  37.44 0 37.464 0.192 ;
    END
  END o0[197]
  PIN o0[198]
    DIRECTION OUTPUT ;
    USE SIGNAL ;
    PORT
      LAYER M5 ;
        RECT  37.632 0 37.656 0.192 ;
    END
  END o0[198]
  PIN o0[199]
    DIRECTION OUTPUT ;
    USE SIGNAL ;
    PORT
      LAYER M5 ;
        RECT  37.776 0 37.8 0.192 ;
    END
  END o0[199]
  PIN o0[19]
    DIRECTION OUTPUT ;
    USE SIGNAL ;
    PORT
      LAYER M5 ;
        RECT  7.68 0 7.704 0.192 ;
    END
  END o0[19]
  PIN o0[1]
    DIRECTION OUTPUT ;
    USE SIGNAL ;
    PORT
      LAYER M5 ;
        RECT  4.656 0 4.68 0.192 ;
    END
  END o0[1]
  PIN o0[200]
    DIRECTION OUTPUT ;
    USE SIGNAL ;
    PORT
      LAYER M5 ;
        RECT  37.968 0 37.992 0.192 ;
    END
  END o0[200]
  PIN o0[201]
    DIRECTION OUTPUT ;
    USE SIGNAL ;
    PORT
      LAYER M5 ;
        RECT  38.112 0 38.136 0.192 ;
    END
  END o0[201]
  PIN o0[202]
    DIRECTION OUTPUT ;
    USE SIGNAL ;
    PORT
      LAYER M5 ;
        RECT  38.304 0 38.328 0.192 ;
    END
  END o0[202]
  PIN o0[203]
    DIRECTION OUTPUT ;
    USE SIGNAL ;
    PORT
      LAYER M5 ;
        RECT  38.448 0 38.472 0.192 ;
    END
  END o0[203]
  PIN o0[204]
    DIRECTION OUTPUT ;
    USE SIGNAL ;
    PORT
      LAYER M5 ;
        RECT  38.64 0 38.664 0.192 ;
    END
  END o0[204]
  PIN o0[205]
    DIRECTION OUTPUT ;
    USE SIGNAL ;
    PORT
      LAYER M5 ;
        RECT  38.784 0 38.808 0.192 ;
    END
  END o0[205]
  PIN o0[206]
    DIRECTION OUTPUT ;
    USE SIGNAL ;
    PORT
      LAYER M5 ;
        RECT  38.976 0 39 0.192 ;
    END
  END o0[206]
  PIN o0[207]
    DIRECTION OUTPUT ;
    USE SIGNAL ;
    PORT
      LAYER M5 ;
        RECT  39.12 0 39.144 0.192 ;
    END
  END o0[207]
  PIN o0[208]
    DIRECTION OUTPUT ;
    USE SIGNAL ;
    PORT
      LAYER M5 ;
        RECT  39.312 0 39.336 0.192 ;
    END
  END o0[208]
  PIN o0[209]
    DIRECTION OUTPUT ;
    USE SIGNAL ;
    PORT
      LAYER M5 ;
        RECT  39.456 0 39.48 0.192 ;
    END
  END o0[209]
  PIN o0[20]
    DIRECTION OUTPUT ;
    USE SIGNAL ;
    PORT
      LAYER M5 ;
        RECT  7.872 0 7.896 0.192 ;
    END
  END o0[20]
  PIN o0[210]
    DIRECTION OUTPUT ;
    USE SIGNAL ;
    PORT
      LAYER M5 ;
        RECT  39.648 0 39.672 0.192 ;
    END
  END o0[210]
  PIN o0[211]
    DIRECTION OUTPUT ;
    USE SIGNAL ;
    PORT
      LAYER M5 ;
        RECT  39.792 0 39.816 0.192 ;
    END
  END o0[211]
  PIN o0[212]
    DIRECTION OUTPUT ;
    USE SIGNAL ;
    PORT
      LAYER M5 ;
        RECT  39.984 0 40.008 0.192 ;
    END
  END o0[212]
  PIN o0[213]
    DIRECTION OUTPUT ;
    USE SIGNAL ;
    PORT
      LAYER M5 ;
        RECT  40.128 0 40.152 0.192 ;
    END
  END o0[213]
  PIN o0[214]
    DIRECTION OUTPUT ;
    USE SIGNAL ;
    PORT
      LAYER M5 ;
        RECT  40.32 0 40.344 0.192 ;
    END
  END o0[214]
  PIN o0[215]
    DIRECTION OUTPUT ;
    USE SIGNAL ;
    PORT
      LAYER M5 ;
        RECT  40.464 0 40.488 0.192 ;
    END
  END o0[215]
  PIN o0[216]
    DIRECTION OUTPUT ;
    USE SIGNAL ;
    PORT
      LAYER M5 ;
        RECT  40.656 0 40.68 0.192 ;
    END
  END o0[216]
  PIN o0[217]
    DIRECTION OUTPUT ;
    USE SIGNAL ;
    PORT
      LAYER M5 ;
        RECT  40.8 0 40.824 0.192 ;
    END
  END o0[217]
  PIN o0[218]
    DIRECTION OUTPUT ;
    USE SIGNAL ;
    PORT
      LAYER M5 ;
        RECT  40.944 0 40.968 0.192 ;
    END
  END o0[218]
  PIN o0[219]
    DIRECTION OUTPUT ;
    USE SIGNAL ;
    PORT
      LAYER M5 ;
        RECT  41.136 0 41.16 0.192 ;
    END
  END o0[219]
  PIN o0[21]
    DIRECTION OUTPUT ;
    USE SIGNAL ;
    PORT
      LAYER M5 ;
        RECT  8.016 0 8.04 0.192 ;
    END
  END o0[21]
  PIN o0[220]
    DIRECTION OUTPUT ;
    USE SIGNAL ;
    PORT
      LAYER M5 ;
        RECT  41.28 0 41.304 0.192 ;
    END
  END o0[220]
  PIN o0[221]
    DIRECTION OUTPUT ;
    USE SIGNAL ;
    PORT
      LAYER M5 ;
        RECT  41.472 0 41.496 0.192 ;
    END
  END o0[221]
  PIN o0[222]
    DIRECTION OUTPUT ;
    USE SIGNAL ;
    PORT
      LAYER M5 ;
        RECT  41.616 0 41.64 0.192 ;
    END
  END o0[222]
  PIN o0[223]
    DIRECTION OUTPUT ;
    USE SIGNAL ;
    PORT
      LAYER M5 ;
        RECT  41.808 0 41.832 0.192 ;
    END
  END o0[223]
  PIN o0[224]
    DIRECTION OUTPUT ;
    USE SIGNAL ;
    PORT
      LAYER M5 ;
        RECT  41.952 0 41.976 0.192 ;
    END
  END o0[224]
  PIN o0[225]
    DIRECTION OUTPUT ;
    USE SIGNAL ;
    PORT
      LAYER M5 ;
        RECT  42.144 0 42.168 0.192 ;
    END
  END o0[225]
  PIN o0[226]
    DIRECTION OUTPUT ;
    USE SIGNAL ;
    PORT
      LAYER M5 ;
        RECT  42.288 0 42.312 0.192 ;
    END
  END o0[226]
  PIN o0[227]
    DIRECTION OUTPUT ;
    USE SIGNAL ;
    PORT
      LAYER M5 ;
        RECT  42.48 0 42.504 0.192 ;
    END
  END o0[227]
  PIN o0[228]
    DIRECTION OUTPUT ;
    USE SIGNAL ;
    PORT
      LAYER M5 ;
        RECT  42.624 0 42.648 0.192 ;
    END
  END o0[228]
  PIN o0[229]
    DIRECTION OUTPUT ;
    USE SIGNAL ;
    PORT
      LAYER M5 ;
        RECT  42.816 0 42.84 0.192 ;
    END
  END o0[229]
  PIN o0[22]
    DIRECTION OUTPUT ;
    USE SIGNAL ;
    PORT
      LAYER M5 ;
        RECT  8.208 0 8.232 0.192 ;
    END
  END o0[22]
  PIN o0[230]
    DIRECTION OUTPUT ;
    USE SIGNAL ;
    PORT
      LAYER M5 ;
        RECT  42.96 0 42.984 0.192 ;
    END
  END o0[230]
  PIN o0[231]
    DIRECTION OUTPUT ;
    USE SIGNAL ;
    PORT
      LAYER M5 ;
        RECT  43.152 0 43.176 0.192 ;
    END
  END o0[231]
  PIN o0[232]
    DIRECTION OUTPUT ;
    USE SIGNAL ;
    PORT
      LAYER M5 ;
        RECT  43.296 0 43.32 0.192 ;
    END
  END o0[232]
  PIN o0[233]
    DIRECTION OUTPUT ;
    USE SIGNAL ;
    PORT
      LAYER M5 ;
        RECT  43.488 0 43.512 0.192 ;
    END
  END o0[233]
  PIN o0[234]
    DIRECTION OUTPUT ;
    USE SIGNAL ;
    PORT
      LAYER M5 ;
        RECT  43.632 0 43.656 0.192 ;
    END
  END o0[234]
  PIN o0[235]
    DIRECTION OUTPUT ;
    USE SIGNAL ;
    PORT
      LAYER M5 ;
        RECT  43.824 0 43.848 0.192 ;
    END
  END o0[235]
  PIN o0[236]
    DIRECTION OUTPUT ;
    USE SIGNAL ;
    PORT
      LAYER M5 ;
        RECT  43.968 0 43.992 0.192 ;
    END
  END o0[236]
  PIN o0[237]
    DIRECTION OUTPUT ;
    USE SIGNAL ;
    PORT
      LAYER M5 ;
        RECT  44.16 0 44.184 0.192 ;
    END
  END o0[237]
  PIN o0[238]
    DIRECTION OUTPUT ;
    USE SIGNAL ;
    PORT
      LAYER M5 ;
        RECT  44.304 0 44.328 0.192 ;
    END
  END o0[238]
  PIN o0[239]
    DIRECTION OUTPUT ;
    USE SIGNAL ;
    PORT
      LAYER M5 ;
        RECT  44.496 0 44.52 0.192 ;
    END
  END o0[239]
  PIN o0[23]
    DIRECTION OUTPUT ;
    USE SIGNAL ;
    PORT
      LAYER M5 ;
        RECT  8.352 0 8.376 0.192 ;
    END
  END o0[23]
  PIN o0[240]
    DIRECTION OUTPUT ;
    USE SIGNAL ;
    PORT
      LAYER M5 ;
        RECT  44.64 0 44.664 0.192 ;
    END
  END o0[240]
  PIN o0[241]
    DIRECTION OUTPUT ;
    USE SIGNAL ;
    PORT
      LAYER M5 ;
        RECT  44.832 0 44.856 0.192 ;
    END
  END o0[241]
  PIN o0[242]
    DIRECTION OUTPUT ;
    USE SIGNAL ;
    PORT
      LAYER M5 ;
        RECT  44.976 0 45 0.192 ;
    END
  END o0[242]
  PIN o0[243]
    DIRECTION OUTPUT ;
    USE SIGNAL ;
    PORT
      LAYER M5 ;
        RECT  45.168 0 45.192 0.192 ;
    END
  END o0[243]
  PIN o0[244]
    DIRECTION OUTPUT ;
    USE SIGNAL ;
    PORT
      LAYER M5 ;
        RECT  45.312 0 45.336 0.192 ;
    END
  END o0[244]
  PIN o0[245]
    DIRECTION OUTPUT ;
    USE SIGNAL ;
    PORT
      LAYER M5 ;
        RECT  45.504 0 45.528 0.192 ;
    END
  END o0[245]
  PIN o0[246]
    DIRECTION OUTPUT ;
    USE SIGNAL ;
    PORT
      LAYER M5 ;
        RECT  45.648 0 45.672 0.192 ;
    END
  END o0[246]
  PIN o0[247]
    DIRECTION OUTPUT ;
    USE SIGNAL ;
    PORT
      LAYER M5 ;
        RECT  45.84 0 45.864 0.192 ;
    END
  END o0[247]
  PIN o0[248]
    DIRECTION OUTPUT ;
    USE SIGNAL ;
    PORT
      LAYER M5 ;
        RECT  45.984 0 46.008 0.192 ;
    END
  END o0[248]
  PIN o0[249]
    DIRECTION OUTPUT ;
    USE SIGNAL ;
    PORT
      LAYER M5 ;
        RECT  46.128 0 46.152 0.192 ;
    END
  END o0[249]
  PIN o0[24]
    DIRECTION OUTPUT ;
    USE SIGNAL ;
    PORT
      LAYER M5 ;
        RECT  8.544 0 8.568 0.192 ;
    END
  END o0[24]
  PIN o0[250]
    DIRECTION OUTPUT ;
    USE SIGNAL ;
    PORT
      LAYER M5 ;
        RECT  46.32 0 46.344 0.192 ;
    END
  END o0[250]
  PIN o0[251]
    DIRECTION OUTPUT ;
    USE SIGNAL ;
    PORT
      LAYER M5 ;
        RECT  46.464 0 46.488 0.192 ;
    END
  END o0[251]
  PIN o0[252]
    DIRECTION OUTPUT ;
    USE SIGNAL ;
    PORT
      LAYER M5 ;
        RECT  46.656 0 46.68 0.192 ;
    END
  END o0[252]
  PIN o0[253]
    DIRECTION OUTPUT ;
    USE SIGNAL ;
    PORT
      LAYER M5 ;
        RECT  46.8 0 46.824 0.192 ;
    END
  END o0[253]
  PIN o0[254]
    DIRECTION OUTPUT ;
    USE SIGNAL ;
    PORT
      LAYER M5 ;
        RECT  46.992 0 47.016 0.192 ;
    END
  END o0[254]
  PIN o0[255]
    DIRECTION OUTPUT ;
    USE SIGNAL ;
    PORT
      LAYER M5 ;
        RECT  47.136 0 47.16 0.192 ;
    END
  END o0[255]
  PIN o0[256]
    DIRECTION OUTPUT ;
    USE SIGNAL ;
    PORT
      LAYER M5 ;
        RECT  47.328 0 47.352 0.192 ;
    END
  END o0[256]
  PIN o0[257]
    DIRECTION OUTPUT ;
    USE SIGNAL ;
    PORT
      LAYER M5 ;
        RECT  47.472 0 47.496 0.192 ;
    END
  END o0[257]
  PIN o0[258]
    DIRECTION OUTPUT ;
    USE SIGNAL ;
    PORT
      LAYER M5 ;
        RECT  47.664 0 47.688 0.192 ;
    END
  END o0[258]
  PIN o0[259]
    DIRECTION OUTPUT ;
    USE SIGNAL ;
    PORT
      LAYER M5 ;
        RECT  47.808 0 47.832 0.192 ;
    END
  END o0[259]
  PIN o0[25]
    DIRECTION OUTPUT ;
    USE SIGNAL ;
    PORT
      LAYER M5 ;
        RECT  8.688 0 8.712 0.192 ;
    END
  END o0[25]
  PIN o0[260]
    DIRECTION OUTPUT ;
    USE SIGNAL ;
    PORT
      LAYER M5 ;
        RECT  48 0 48.024 0.192 ;
    END
  END o0[260]
  PIN o0[261]
    DIRECTION OUTPUT ;
    USE SIGNAL ;
    PORT
      LAYER M5 ;
        RECT  48.144 0 48.168 0.192 ;
    END
  END o0[261]
  PIN o0[262]
    DIRECTION OUTPUT ;
    USE SIGNAL ;
    PORT
      LAYER M5 ;
        RECT  48.336 0 48.36 0.192 ;
    END
  END o0[262]
  PIN o0[263]
    DIRECTION OUTPUT ;
    USE SIGNAL ;
    PORT
      LAYER M5 ;
        RECT  48.48 0 48.504 0.192 ;
    END
  END o0[263]
  PIN o0[264]
    DIRECTION OUTPUT ;
    USE SIGNAL ;
    PORT
      LAYER M5 ;
        RECT  48.672 0 48.696 0.192 ;
    END
  END o0[264]
  PIN o0[265]
    DIRECTION OUTPUT ;
    USE SIGNAL ;
    PORT
      LAYER M5 ;
        RECT  48.816 0 48.84 0.192 ;
    END
  END o0[265]
  PIN o0[266]
    DIRECTION OUTPUT ;
    USE SIGNAL ;
    PORT
      LAYER M5 ;
        RECT  49.008 0 49.032 0.192 ;
    END
  END o0[266]
  PIN o0[267]
    DIRECTION OUTPUT ;
    USE SIGNAL ;
    PORT
      LAYER M5 ;
        RECT  49.152 0 49.176 0.192 ;
    END
  END o0[267]
  PIN o0[268]
    DIRECTION OUTPUT ;
    USE SIGNAL ;
    PORT
      LAYER M5 ;
        RECT  49.344 0 49.368 0.192 ;
    END
  END o0[268]
  PIN o0[269]
    DIRECTION OUTPUT ;
    USE SIGNAL ;
    PORT
      LAYER M5 ;
        RECT  49.488 0 49.512 0.192 ;
    END
  END o0[269]
  PIN o0[26]
    DIRECTION OUTPUT ;
    USE SIGNAL ;
    PORT
      LAYER M5 ;
        RECT  8.88 0 8.904 0.192 ;
    END
  END o0[26]
  PIN o0[270]
    DIRECTION OUTPUT ;
    USE SIGNAL ;
    PORT
      LAYER M5 ;
        RECT  49.68 0 49.704 0.192 ;
    END
  END o0[270]
  PIN o0[271]
    DIRECTION OUTPUT ;
    USE SIGNAL ;
    PORT
      LAYER M5 ;
        RECT  49.824 0 49.848 0.192 ;
    END
  END o0[271]
  PIN o0[272]
    DIRECTION OUTPUT ;
    USE SIGNAL ;
    PORT
      LAYER M5 ;
        RECT  50.016 0 50.04 0.192 ;
    END
  END o0[272]
  PIN o0[273]
    DIRECTION OUTPUT ;
    USE SIGNAL ;
    PORT
      LAYER M5 ;
        RECT  50.16 0 50.184 0.192 ;
    END
  END o0[273]
  PIN o0[274]
    DIRECTION OUTPUT ;
    USE SIGNAL ;
    PORT
      LAYER M5 ;
        RECT  50.352 0 50.376 0.192 ;
    END
  END o0[274]
  PIN o0[275]
    DIRECTION OUTPUT ;
    USE SIGNAL ;
    PORT
      LAYER M5 ;
        RECT  50.496 0 50.52 0.192 ;
    END
  END o0[275]
  PIN o0[276]
    DIRECTION OUTPUT ;
    USE SIGNAL ;
    PORT
      LAYER M5 ;
        RECT  50.688 0 50.712 0.192 ;
    END
  END o0[276]
  PIN o0[277]
    DIRECTION OUTPUT ;
    USE SIGNAL ;
    PORT
      LAYER M5 ;
        RECT  50.832 0 50.856 0.192 ;
    END
  END o0[277]
  PIN o0[278]
    DIRECTION OUTPUT ;
    USE SIGNAL ;
    PORT
      LAYER M5 ;
        RECT  51.024 0 51.048 0.192 ;
    END
  END o0[278]
  PIN o0[279]
    DIRECTION OUTPUT ;
    USE SIGNAL ;
    PORT
      LAYER M5 ;
        RECT  51.168 0 51.192 0.192 ;
    END
  END o0[279]
  PIN o0[27]
    DIRECTION OUTPUT ;
    USE SIGNAL ;
    PORT
      LAYER M5 ;
        RECT  9.024 0 9.048 0.192 ;
    END
  END o0[27]
  PIN o0[280]
    DIRECTION OUTPUT ;
    USE SIGNAL ;
    PORT
      LAYER M5 ;
        RECT  51.36 0 51.384 0.192 ;
    END
  END o0[280]
  PIN o0[281]
    DIRECTION OUTPUT ;
    USE SIGNAL ;
    PORT
      LAYER M5 ;
        RECT  51.504 0 51.528 0.192 ;
    END
  END o0[281]
  PIN o0[282]
    DIRECTION OUTPUT ;
    USE SIGNAL ;
    PORT
      LAYER M5 ;
        RECT  51.648 0 51.672 0.192 ;
    END
  END o0[282]
  PIN o0[283]
    DIRECTION OUTPUT ;
    USE SIGNAL ;
    PORT
      LAYER M5 ;
        RECT  51.84 0 51.864 0.192 ;
    END
  END o0[283]
  PIN o0[284]
    DIRECTION OUTPUT ;
    USE SIGNAL ;
    PORT
      LAYER M5 ;
        RECT  51.984 0 52.008 0.192 ;
    END
  END o0[284]
  PIN o0[285]
    DIRECTION OUTPUT ;
    USE SIGNAL ;
    PORT
      LAYER M5 ;
        RECT  52.176 0 52.2 0.192 ;
    END
  END o0[285]
  PIN o0[286]
    DIRECTION OUTPUT ;
    USE SIGNAL ;
    PORT
      LAYER M5 ;
        RECT  52.32 0 52.344 0.192 ;
    END
  END o0[286]
  PIN o0[287]
    DIRECTION OUTPUT ;
    USE SIGNAL ;
    PORT
      LAYER M5 ;
        RECT  52.512 0 52.536 0.192 ;
    END
  END o0[287]
  PIN o0[288]
    DIRECTION OUTPUT ;
    USE SIGNAL ;
    PORT
      LAYER M5 ;
        RECT  52.656 0 52.68 0.192 ;
    END
  END o0[288]
  PIN o0[289]
    DIRECTION OUTPUT ;
    USE SIGNAL ;
    PORT
      LAYER M5 ;
        RECT  52.848 0 52.872 0.192 ;
    END
  END o0[289]
  PIN o0[28]
    DIRECTION OUTPUT ;
    USE SIGNAL ;
    PORT
      LAYER M5 ;
        RECT  9.168 0 9.192 0.192 ;
    END
  END o0[28]
  PIN o0[290]
    DIRECTION OUTPUT ;
    USE SIGNAL ;
    PORT
      LAYER M5 ;
        RECT  52.992 0 53.016 0.192 ;
    END
  END o0[290]
  PIN o0[291]
    DIRECTION OUTPUT ;
    USE SIGNAL ;
    PORT
      LAYER M5 ;
        RECT  53.184 0 53.208 0.192 ;
    END
  END o0[291]
  PIN o0[292]
    DIRECTION OUTPUT ;
    USE SIGNAL ;
    PORT
      LAYER M5 ;
        RECT  53.328 0 53.352 0.192 ;
    END
  END o0[292]
  PIN o0[293]
    DIRECTION OUTPUT ;
    USE SIGNAL ;
    PORT
      LAYER M5 ;
        RECT  53.52 0 53.544 0.192 ;
    END
  END o0[293]
  PIN o0[294]
    DIRECTION OUTPUT ;
    USE SIGNAL ;
    PORT
      LAYER M5 ;
        RECT  53.664 0 53.688 0.192 ;
    END
  END o0[294]
  PIN o0[295]
    DIRECTION OUTPUT ;
    USE SIGNAL ;
    PORT
      LAYER M5 ;
        RECT  53.856 0 53.88 0.192 ;
    END
  END o0[295]
  PIN o0[296]
    DIRECTION OUTPUT ;
    USE SIGNAL ;
    PORT
      LAYER M5 ;
        RECT  54 0 54.024 0.192 ;
    END
  END o0[296]
  PIN o0[297]
    DIRECTION OUTPUT ;
    USE SIGNAL ;
    PORT
      LAYER M5 ;
        RECT  54.192 0 54.216 0.192 ;
    END
  END o0[297]
  PIN o0[298]
    DIRECTION OUTPUT ;
    USE SIGNAL ;
    PORT
      LAYER M5 ;
        RECT  54.336 0 54.36 0.192 ;
    END
  END o0[298]
  PIN o0[299]
    DIRECTION OUTPUT ;
    USE SIGNAL ;
    PORT
      LAYER M5 ;
        RECT  54.528 0 54.552 0.192 ;
    END
  END o0[299]
  PIN o0[29]
    DIRECTION OUTPUT ;
    USE SIGNAL ;
    PORT
      LAYER M5 ;
        RECT  9.36 0 9.384 0.192 ;
    END
  END o0[29]
  PIN o0[2]
    DIRECTION OUTPUT ;
    USE SIGNAL ;
    PORT
      LAYER M5 ;
        RECT  4.848 0 4.872 0.192 ;
    END
  END o0[2]
  PIN o0[300]
    DIRECTION OUTPUT ;
    USE SIGNAL ;
    PORT
      LAYER M5 ;
        RECT  54.672 0 54.696 0.192 ;
    END
  END o0[300]
  PIN o0[301]
    DIRECTION OUTPUT ;
    USE SIGNAL ;
    PORT
      LAYER M5 ;
        RECT  54.864 0 54.888 0.192 ;
    END
  END o0[301]
  PIN o0[302]
    DIRECTION OUTPUT ;
    USE SIGNAL ;
    PORT
      LAYER M5 ;
        RECT  55.008 0 55.032 0.192 ;
    END
  END o0[302]
  PIN o0[303]
    DIRECTION OUTPUT ;
    USE SIGNAL ;
    PORT
      LAYER M5 ;
        RECT  55.2 0 55.224 0.192 ;
    END
  END o0[303]
  PIN o0[304]
    DIRECTION OUTPUT ;
    USE SIGNAL ;
    PORT
      LAYER M5 ;
        RECT  55.344 0 55.368 0.192 ;
    END
  END o0[304]
  PIN o0[305]
    DIRECTION OUTPUT ;
    USE SIGNAL ;
    PORT
      LAYER M5 ;
        RECT  55.536 0 55.56 0.192 ;
    END
  END o0[305]
  PIN o0[306]
    DIRECTION OUTPUT ;
    USE SIGNAL ;
    PORT
      LAYER M5 ;
        RECT  55.68 0 55.704 0.192 ;
    END
  END o0[306]
  PIN o0[307]
    DIRECTION OUTPUT ;
    USE SIGNAL ;
    PORT
      LAYER M5 ;
        RECT  55.872 0 55.896 0.192 ;
    END
  END o0[307]
  PIN o0[308]
    DIRECTION OUTPUT ;
    USE SIGNAL ;
    PORT
      LAYER M5 ;
        RECT  56.016 0 56.04 0.192 ;
    END
  END o0[308]
  PIN o0[309]
    DIRECTION OUTPUT ;
    USE SIGNAL ;
    PORT
      LAYER M5 ;
        RECT  56.208 0 56.232 0.192 ;
    END
  END o0[309]
  PIN o0[30]
    DIRECTION OUTPUT ;
    USE SIGNAL ;
    PORT
      LAYER M5 ;
        RECT  9.504 0 9.528 0.192 ;
    END
  END o0[30]
  PIN o0[310]
    DIRECTION OUTPUT ;
    USE SIGNAL ;
    PORT
      LAYER M5 ;
        RECT  56.352 0 56.376 0.192 ;
    END
  END o0[310]
  PIN o0[311]
    DIRECTION OUTPUT ;
    USE SIGNAL ;
    PORT
      LAYER M5 ;
        RECT  56.544 0 56.568 0.192 ;
    END
  END o0[311]
  PIN o0[312]
    DIRECTION OUTPUT ;
    USE SIGNAL ;
    PORT
      LAYER M5 ;
        RECT  56.832 0 56.856 0.192 ;
    END
  END o0[312]
  PIN o0[313]
    DIRECTION OUTPUT ;
    USE SIGNAL ;
    PORT
      LAYER M5 ;
        RECT  57.024 0 57.048 0.192 ;
    END
  END o0[313]
  PIN o0[314]
    DIRECTION OUTPUT ;
    USE SIGNAL ;
    PORT
      LAYER M5 ;
        RECT  57.168 0 57.192 0.192 ;
    END
  END o0[314]
  PIN o0[315]
    DIRECTION OUTPUT ;
    USE SIGNAL ;
    PORT
      LAYER M5 ;
        RECT  57.36 0 57.384 0.192 ;
    END
  END o0[315]
  PIN o0[316]
    DIRECTION OUTPUT ;
    USE SIGNAL ;
    PORT
      LAYER M5 ;
        RECT  57.504 0 57.528 0.192 ;
    END
  END o0[316]
  PIN o0[317]
    DIRECTION OUTPUT ;
    USE SIGNAL ;
    PORT
      LAYER M5 ;
        RECT  57.696 0 57.72 0.192 ;
    END
  END o0[317]
  PIN o0[318]
    DIRECTION OUTPUT ;
    USE SIGNAL ;
    PORT
      LAYER M5 ;
        RECT  57.84 0 57.864 0.192 ;
    END
  END o0[318]
  PIN o0[319]
    DIRECTION OUTPUT ;
    USE SIGNAL ;
    PORT
      LAYER M5 ;
        RECT  58.032 0 58.056 0.192 ;
    END
  END o0[319]
  PIN o0[31]
    DIRECTION OUTPUT ;
    USE SIGNAL ;
    PORT
      LAYER M5 ;
        RECT  9.696 0 9.72 0.192 ;
    END
  END o0[31]
  PIN o0[320]
    DIRECTION OUTPUT ;
    USE SIGNAL ;
    PORT
      LAYER M5 ;
        RECT  58.176 0 58.2 0.192 ;
    END
  END o0[320]
  PIN o0[321]
    DIRECTION OUTPUT ;
    USE SIGNAL ;
    PORT
      LAYER M5 ;
        RECT  58.368 0 58.392 0.192 ;
    END
  END o0[321]
  PIN o0[322]
    DIRECTION OUTPUT ;
    USE SIGNAL ;
    PORT
      LAYER M5 ;
        RECT  58.512 0 58.536 0.192 ;
    END
  END o0[322]
  PIN o0[323]
    DIRECTION OUTPUT ;
    USE SIGNAL ;
    PORT
      LAYER M5 ;
        RECT  58.704 0 58.728 0.192 ;
    END
  END o0[323]
  PIN o0[324]
    DIRECTION OUTPUT ;
    USE SIGNAL ;
    PORT
      LAYER M5 ;
        RECT  58.848 0 58.872 0.192 ;
    END
  END o0[324]
  PIN o0[325]
    DIRECTION OUTPUT ;
    USE SIGNAL ;
    PORT
      LAYER M5 ;
        RECT  59.04 0 59.064 0.192 ;
    END
  END o0[325]
  PIN o0[326]
    DIRECTION OUTPUT ;
    USE SIGNAL ;
    PORT
      LAYER M5 ;
        RECT  59.184 0 59.208 0.192 ;
    END
  END o0[326]
  PIN o0[327]
    DIRECTION OUTPUT ;
    USE SIGNAL ;
    PORT
      LAYER M5 ;
        RECT  59.376 0 59.4 0.192 ;
    END
  END o0[327]
  PIN o0[328]
    DIRECTION OUTPUT ;
    USE SIGNAL ;
    PORT
      LAYER M5 ;
        RECT  59.52 0 59.544 0.192 ;
    END
  END o0[328]
  PIN o0[329]
    DIRECTION OUTPUT ;
    USE SIGNAL ;
    PORT
      LAYER M5 ;
        RECT  59.712 0 59.736 0.192 ;
    END
  END o0[329]
  PIN o0[32]
    DIRECTION OUTPUT ;
    USE SIGNAL ;
    PORT
      LAYER M5 ;
        RECT  9.84 0 9.864 0.192 ;
    END
  END o0[32]
  PIN o0[330]
    DIRECTION OUTPUT ;
    USE SIGNAL ;
    PORT
      LAYER M5 ;
        RECT  59.856 0 59.88 0.192 ;
    END
  END o0[330]
  PIN o0[331]
    DIRECTION OUTPUT ;
    USE SIGNAL ;
    PORT
      LAYER M5 ;
        RECT  60.048 0 60.072 0.192 ;
    END
  END o0[331]
  PIN o0[332]
    DIRECTION OUTPUT ;
    USE SIGNAL ;
    PORT
      LAYER M5 ;
        RECT  60.192 0 60.216 0.192 ;
    END
  END o0[332]
  PIN o0[333]
    DIRECTION OUTPUT ;
    USE SIGNAL ;
    PORT
      LAYER M5 ;
        RECT  60.384 0 60.408 0.192 ;
    END
  END o0[333]
  PIN o0[334]
    DIRECTION OUTPUT ;
    USE SIGNAL ;
    PORT
      LAYER M5 ;
        RECT  60.528 0 60.552 0.192 ;
    END
  END o0[334]
  PIN o0[335]
    DIRECTION OUTPUT ;
    USE SIGNAL ;
    PORT
      LAYER M5 ;
        RECT  60.72 0 60.744 0.192 ;
    END
  END o0[335]
  PIN o0[336]
    DIRECTION OUTPUT ;
    USE SIGNAL ;
    PORT
      LAYER M5 ;
        RECT  60.864 0 60.888 0.192 ;
    END
  END o0[336]
  PIN o0[337]
    DIRECTION OUTPUT ;
    USE SIGNAL ;
    PORT
      LAYER M5 ;
        RECT  61.056 0 61.08 0.192 ;
    END
  END o0[337]
  PIN o0[338]
    DIRECTION OUTPUT ;
    USE SIGNAL ;
    PORT
      LAYER M5 ;
        RECT  61.2 0 61.224 0.192 ;
    END
  END o0[338]
  PIN o0[339]
    DIRECTION OUTPUT ;
    USE SIGNAL ;
    PORT
      LAYER M5 ;
        RECT  61.392 0 61.416 0.192 ;
    END
  END o0[339]
  PIN o0[33]
    DIRECTION OUTPUT ;
    USE SIGNAL ;
    PORT
      LAYER M5 ;
        RECT  10.032 0 10.056 0.192 ;
    END
  END o0[33]
  PIN o0[340]
    DIRECTION OUTPUT ;
    USE SIGNAL ;
    PORT
      LAYER M5 ;
        RECT  61.536 0 61.56 0.192 ;
    END
  END o0[340]
  PIN o0[341]
    DIRECTION OUTPUT ;
    USE SIGNAL ;
    PORT
      LAYER M5 ;
        RECT  61.728 0 61.752 0.192 ;
    END
  END o0[341]
  PIN o0[342]
    DIRECTION OUTPUT ;
    USE SIGNAL ;
    PORT
      LAYER M5 ;
        RECT  61.872 0 61.896 0.192 ;
    END
  END o0[342]
  PIN o0[343]
    DIRECTION OUTPUT ;
    USE SIGNAL ;
    PORT
      LAYER M5 ;
        RECT  62.016 0 62.04 0.192 ;
    END
  END o0[343]
  PIN o0[344]
    DIRECTION OUTPUT ;
    USE SIGNAL ;
    PORT
      LAYER M5 ;
        RECT  62.208 0 62.232 0.192 ;
    END
  END o0[344]
  PIN o0[345]
    DIRECTION OUTPUT ;
    USE SIGNAL ;
    PORT
      LAYER M5 ;
        RECT  62.352 0 62.376 0.192 ;
    END
  END o0[345]
  PIN o0[346]
    DIRECTION OUTPUT ;
    USE SIGNAL ;
    PORT
      LAYER M5 ;
        RECT  62.544 0 62.568 0.192 ;
    END
  END o0[346]
  PIN o0[347]
    DIRECTION OUTPUT ;
    USE SIGNAL ;
    PORT
      LAYER M5 ;
        RECT  62.688 0 62.712 0.192 ;
    END
  END o0[347]
  PIN o0[348]
    DIRECTION OUTPUT ;
    USE SIGNAL ;
    PORT
      LAYER M5 ;
        RECT  62.88 0 62.904 0.192 ;
    END
  END o0[348]
  PIN o0[349]
    DIRECTION OUTPUT ;
    USE SIGNAL ;
    PORT
      LAYER M5 ;
        RECT  63.024 0 63.048 0.192 ;
    END
  END o0[349]
  PIN o0[34]
    DIRECTION OUTPUT ;
    USE SIGNAL ;
    PORT
      LAYER M5 ;
        RECT  10.176 0 10.2 0.192 ;
    END
  END o0[34]
  PIN o0[350]
    DIRECTION OUTPUT ;
    USE SIGNAL ;
    PORT
      LAYER M5 ;
        RECT  63.216 0 63.24 0.192 ;
    END
  END o0[350]
  PIN o0[351]
    DIRECTION OUTPUT ;
    USE SIGNAL ;
    PORT
      LAYER M5 ;
        RECT  63.36 0 63.384 0.192 ;
    END
  END o0[351]
  PIN o0[352]
    DIRECTION OUTPUT ;
    USE SIGNAL ;
    PORT
      LAYER M5 ;
        RECT  63.552 0 63.576 0.192 ;
    END
  END o0[352]
  PIN o0[353]
    DIRECTION OUTPUT ;
    USE SIGNAL ;
    PORT
      LAYER M5 ;
        RECT  63.696 0 63.72 0.192 ;
    END
  END o0[353]
  PIN o0[354]
    DIRECTION OUTPUT ;
    USE SIGNAL ;
    PORT
      LAYER M5 ;
        RECT  63.888 0 63.912 0.192 ;
    END
  END o0[354]
  PIN o0[355]
    DIRECTION OUTPUT ;
    USE SIGNAL ;
    PORT
      LAYER M5 ;
        RECT  64.032 0 64.056 0.192 ;
    END
  END o0[355]
  PIN o0[356]
    DIRECTION OUTPUT ;
    USE SIGNAL ;
    PORT
      LAYER M5 ;
        RECT  64.224 0 64.248 0.192 ;
    END
  END o0[356]
  PIN o0[357]
    DIRECTION OUTPUT ;
    USE SIGNAL ;
    PORT
      LAYER M5 ;
        RECT  64.368 0 64.392 0.192 ;
    END
  END o0[357]
  PIN o0[358]
    DIRECTION OUTPUT ;
    USE SIGNAL ;
    PORT
      LAYER M5 ;
        RECT  64.56 0 64.584 0.192 ;
    END
  END o0[358]
  PIN o0[359]
    DIRECTION OUTPUT ;
    USE SIGNAL ;
    PORT
      LAYER M5 ;
        RECT  64.704 0 64.728 0.192 ;
    END
  END o0[359]
  PIN o0[35]
    DIRECTION OUTPUT ;
    USE SIGNAL ;
    PORT
      LAYER M5 ;
        RECT  10.368 0 10.392 0.192 ;
    END
  END o0[35]
  PIN o0[360]
    DIRECTION OUTPUT ;
    USE SIGNAL ;
    PORT
      LAYER M5 ;
        RECT  64.896 0 64.92 0.192 ;
    END
  END o0[360]
  PIN o0[361]
    DIRECTION OUTPUT ;
    USE SIGNAL ;
    PORT
      LAYER M5 ;
        RECT  65.04 0 65.064 0.192 ;
    END
  END o0[361]
  PIN o0[362]
    DIRECTION OUTPUT ;
    USE SIGNAL ;
    PORT
      LAYER M5 ;
        RECT  65.232 0 65.256 0.192 ;
    END
  END o0[362]
  PIN o0[363]
    DIRECTION OUTPUT ;
    USE SIGNAL ;
    PORT
      LAYER M5 ;
        RECT  65.376 0 65.4 0.192 ;
    END
  END o0[363]
  PIN o0[364]
    DIRECTION OUTPUT ;
    USE SIGNAL ;
    PORT
      LAYER M5 ;
        RECT  65.568 0 65.592 0.192 ;
    END
  END o0[364]
  PIN o0[365]
    DIRECTION OUTPUT ;
    USE SIGNAL ;
    PORT
      LAYER M5 ;
        RECT  65.712 0 65.736 0.192 ;
    END
  END o0[365]
  PIN o0[366]
    DIRECTION OUTPUT ;
    USE SIGNAL ;
    PORT
      LAYER M5 ;
        RECT  65.904 0 65.928 0.192 ;
    END
  END o0[366]
  PIN o0[367]
    DIRECTION OUTPUT ;
    USE SIGNAL ;
    PORT
      LAYER M5 ;
        RECT  66.048 0 66.072 0.192 ;
    END
  END o0[367]
  PIN o0[368]
    DIRECTION OUTPUT ;
    USE SIGNAL ;
    PORT
      LAYER M5 ;
        RECT  66.24 0 66.264 0.192 ;
    END
  END o0[368]
  PIN o0[369]
    DIRECTION OUTPUT ;
    USE SIGNAL ;
    PORT
      LAYER M5 ;
        RECT  66.384 0 66.408 0.192 ;
    END
  END o0[369]
  PIN o0[36]
    DIRECTION OUTPUT ;
    USE SIGNAL ;
    PORT
      LAYER M5 ;
        RECT  10.512 0 10.536 0.192 ;
    END
  END o0[36]
  PIN o0[370]
    DIRECTION OUTPUT ;
    USE SIGNAL ;
    PORT
      LAYER M5 ;
        RECT  66.576 0 66.6 0.192 ;
    END
  END o0[370]
  PIN o0[371]
    DIRECTION OUTPUT ;
    USE SIGNAL ;
    PORT
      LAYER M5 ;
        RECT  66.72 0 66.744 0.192 ;
    END
  END o0[371]
  PIN o0[372]
    DIRECTION OUTPUT ;
    USE SIGNAL ;
    PORT
      LAYER M5 ;
        RECT  66.912 0 66.936 0.192 ;
    END
  END o0[372]
  PIN o0[373]
    DIRECTION OUTPUT ;
    USE SIGNAL ;
    PORT
      LAYER M5 ;
        RECT  67.056 0 67.08 0.192 ;
    END
  END o0[373]
  PIN o0[374]
    DIRECTION OUTPUT ;
    USE SIGNAL ;
    PORT
      LAYER M5 ;
        RECT  67.248 0 67.272 0.192 ;
    END
  END o0[374]
  PIN o0[375]
    DIRECTION OUTPUT ;
    USE SIGNAL ;
    PORT
      LAYER M5 ;
        RECT  67.392 0 67.416 0.192 ;
    END
  END o0[375]
  PIN o0[376]
    DIRECTION OUTPUT ;
    USE SIGNAL ;
    PORT
      LAYER M5 ;
        RECT  67.536 0 67.56 0.192 ;
    END
  END o0[376]
  PIN o0[377]
    DIRECTION OUTPUT ;
    USE SIGNAL ;
    PORT
      LAYER M5 ;
        RECT  67.728 0 67.752 0.192 ;
    END
  END o0[377]
  PIN o0[378]
    DIRECTION OUTPUT ;
    USE SIGNAL ;
    PORT
      LAYER M5 ;
        RECT  67.872 0 67.896 0.192 ;
    END
  END o0[378]
  PIN o0[379]
    DIRECTION OUTPUT ;
    USE SIGNAL ;
    PORT
      LAYER M5 ;
        RECT  68.064 0 68.088 0.192 ;
    END
  END o0[379]
  PIN o0[37]
    DIRECTION OUTPUT ;
    USE SIGNAL ;
    PORT
      LAYER M5 ;
        RECT  10.704 0 10.728 0.192 ;
    END
  END o0[37]
  PIN o0[380]
    DIRECTION OUTPUT ;
    USE SIGNAL ;
    PORT
      LAYER M5 ;
        RECT  68.208 0 68.232 0.192 ;
    END
  END o0[380]
  PIN o0[381]
    DIRECTION OUTPUT ;
    USE SIGNAL ;
    PORT
      LAYER M5 ;
        RECT  68.4 0 68.424 0.192 ;
    END
  END o0[381]
  PIN o0[382]
    DIRECTION OUTPUT ;
    USE SIGNAL ;
    PORT
      LAYER M5 ;
        RECT  68.544 0 68.568 0.192 ;
    END
  END o0[382]
  PIN o0[383]
    DIRECTION OUTPUT ;
    USE SIGNAL ;
    PORT
      LAYER M5 ;
        RECT  68.736 0 68.76 0.192 ;
    END
  END o0[383]
  PIN o0[384]
    DIRECTION OUTPUT ;
    USE SIGNAL ;
    PORT
      LAYER M5 ;
        RECT  68.88 0 68.904 0.192 ;
    END
  END o0[384]
  PIN o0[385]
    DIRECTION OUTPUT ;
    USE SIGNAL ;
    PORT
      LAYER M5 ;
        RECT  69.072 0 69.096 0.192 ;
    END
  END o0[385]
  PIN o0[386]
    DIRECTION OUTPUT ;
    USE SIGNAL ;
    PORT
      LAYER M5 ;
        RECT  69.216 0 69.24 0.192 ;
    END
  END o0[386]
  PIN o0[387]
    DIRECTION OUTPUT ;
    USE SIGNAL ;
    PORT
      LAYER M5 ;
        RECT  69.408 0 69.432 0.192 ;
    END
  END o0[387]
  PIN o0[388]
    DIRECTION OUTPUT ;
    USE SIGNAL ;
    PORT
      LAYER M5 ;
        RECT  69.552 0 69.576 0.192 ;
    END
  END o0[388]
  PIN o0[389]
    DIRECTION OUTPUT ;
    USE SIGNAL ;
    PORT
      LAYER M5 ;
        RECT  69.744 0 69.768 0.192 ;
    END
  END o0[389]
  PIN o0[38]
    DIRECTION OUTPUT ;
    USE SIGNAL ;
    PORT
      LAYER M5 ;
        RECT  10.848 0 10.872 0.192 ;
    END
  END o0[38]
  PIN o0[390]
    DIRECTION OUTPUT ;
    USE SIGNAL ;
    PORT
      LAYER M5 ;
        RECT  69.888 0 69.912 0.192 ;
    END
  END o0[390]
  PIN o0[391]
    DIRECTION OUTPUT ;
    USE SIGNAL ;
    PORT
      LAYER M5 ;
        RECT  70.08 0 70.104 0.192 ;
    END
  END o0[391]
  PIN o0[392]
    DIRECTION OUTPUT ;
    USE SIGNAL ;
    PORT
      LAYER M5 ;
        RECT  70.224 0 70.248 0.192 ;
    END
  END o0[392]
  PIN o0[393]
    DIRECTION OUTPUT ;
    USE SIGNAL ;
    PORT
      LAYER M5 ;
        RECT  70.416 0 70.44 0.192 ;
    END
  END o0[393]
  PIN o0[394]
    DIRECTION OUTPUT ;
    USE SIGNAL ;
    PORT
      LAYER M5 ;
        RECT  70.56 0 70.584 0.192 ;
    END
  END o0[394]
  PIN o0[395]
    DIRECTION OUTPUT ;
    USE SIGNAL ;
    PORT
      LAYER M5 ;
        RECT  70.752 0 70.776 0.192 ;
    END
  END o0[395]
  PIN o0[396]
    DIRECTION OUTPUT ;
    USE SIGNAL ;
    PORT
      LAYER M5 ;
        RECT  70.896 0 70.92 0.192 ;
    END
  END o0[396]
  PIN o0[397]
    DIRECTION OUTPUT ;
    USE SIGNAL ;
    PORT
      LAYER M5 ;
        RECT  71.088 0 71.112 0.192 ;
    END
  END o0[397]
  PIN o0[398]
    DIRECTION OUTPUT ;
    USE SIGNAL ;
    PORT
      LAYER M5 ;
        RECT  71.232 0 71.256 0.192 ;
    END
  END o0[398]
  PIN o0[399]
    DIRECTION OUTPUT ;
    USE SIGNAL ;
    PORT
      LAYER M5 ;
        RECT  71.424 0 71.448 0.192 ;
    END
  END o0[399]
  PIN o0[39]
    DIRECTION OUTPUT ;
    USE SIGNAL ;
    PORT
      LAYER M5 ;
        RECT  11.04 0 11.064 0.192 ;
    END
  END o0[39]
  PIN o0[3]
    DIRECTION OUTPUT ;
    USE SIGNAL ;
    PORT
      LAYER M5 ;
        RECT  4.992 0 5.016 0.192 ;
    END
  END o0[3]
  PIN o0[400]
    DIRECTION OUTPUT ;
    USE SIGNAL ;
    PORT
      LAYER M5 ;
        RECT  71.568 0 71.592 0.192 ;
    END
  END o0[400]
  PIN o0[401]
    DIRECTION OUTPUT ;
    USE SIGNAL ;
    PORT
      LAYER M5 ;
        RECT  71.76 0 71.784 0.192 ;
    END
  END o0[401]
  PIN o0[402]
    DIRECTION OUTPUT ;
    USE SIGNAL ;
    PORT
      LAYER M5 ;
        RECT  71.904 0 71.928 0.192 ;
    END
  END o0[402]
  PIN o0[403]
    DIRECTION OUTPUT ;
    USE SIGNAL ;
    PORT
      LAYER M5 ;
        RECT  72.096 0 72.12 0.192 ;
    END
  END o0[403]
  PIN o0[404]
    DIRECTION OUTPUT ;
    USE SIGNAL ;
    PORT
      LAYER M5 ;
        RECT  72.24 0 72.264 0.192 ;
    END
  END o0[404]
  PIN o0[405]
    DIRECTION OUTPUT ;
    USE SIGNAL ;
    PORT
      LAYER M5 ;
        RECT  72.432 0 72.456 0.192 ;
    END
  END o0[405]
  PIN o0[406]
    DIRECTION OUTPUT ;
    USE SIGNAL ;
    PORT
      LAYER M5 ;
        RECT  72.576 0 72.6 0.192 ;
    END
  END o0[406]
  PIN o0[407]
    DIRECTION OUTPUT ;
    USE SIGNAL ;
    PORT
      LAYER M5 ;
        RECT  72.72 0 72.744 0.192 ;
    END
  END o0[407]
  PIN o0[408]
    DIRECTION OUTPUT ;
    USE SIGNAL ;
    PORT
      LAYER M5 ;
        RECT  72.912 0 72.936 0.192 ;
    END
  END o0[408]
  PIN o0[409]
    DIRECTION OUTPUT ;
    USE SIGNAL ;
    PORT
      LAYER M5 ;
        RECT  73.056 0 73.08 0.192 ;
    END
  END o0[409]
  PIN o0[40]
    DIRECTION OUTPUT ;
    USE SIGNAL ;
    PORT
      LAYER M5 ;
        RECT  11.184 0 11.208 0.192 ;
    END
  END o0[40]
  PIN o0[410]
    DIRECTION OUTPUT ;
    USE SIGNAL ;
    PORT
      LAYER M5 ;
        RECT  73.248 0 73.272 0.192 ;
    END
  END o0[410]
  PIN o0[411]
    DIRECTION OUTPUT ;
    USE SIGNAL ;
    PORT
      LAYER M5 ;
        RECT  73.392 0 73.416 0.192 ;
    END
  END o0[411]
  PIN o0[412]
    DIRECTION OUTPUT ;
    USE SIGNAL ;
    PORT
      LAYER M5 ;
        RECT  73.584 0 73.608 0.192 ;
    END
  END o0[412]
  PIN o0[413]
    DIRECTION OUTPUT ;
    USE SIGNAL ;
    PORT
      LAYER M5 ;
        RECT  73.728 0 73.752 0.192 ;
    END
  END o0[413]
  PIN o0[414]
    DIRECTION OUTPUT ;
    USE SIGNAL ;
    PORT
      LAYER M5 ;
        RECT  73.92 0 73.944 0.192 ;
    END
  END o0[414]
  PIN o0[415]
    DIRECTION OUTPUT ;
    USE SIGNAL ;
    PORT
      LAYER M5 ;
        RECT  74.064 0 74.088 0.192 ;
    END
  END o0[415]
  PIN o0[416]
    DIRECTION OUTPUT ;
    USE SIGNAL ;
    PORT
      LAYER M5 ;
        RECT  74.256 0 74.28 0.192 ;
    END
  END o0[416]
  PIN o0[417]
    DIRECTION OUTPUT ;
    USE SIGNAL ;
    PORT
      LAYER M5 ;
        RECT  74.4 0 74.424 0.192 ;
    END
  END o0[417]
  PIN o0[418]
    DIRECTION OUTPUT ;
    USE SIGNAL ;
    PORT
      LAYER M5 ;
        RECT  74.592 0 74.616 0.192 ;
    END
  END o0[418]
  PIN o0[419]
    DIRECTION OUTPUT ;
    USE SIGNAL ;
    PORT
      LAYER M5 ;
        RECT  74.736 0 74.76 0.192 ;
    END
  END o0[419]
  PIN o0[41]
    DIRECTION OUTPUT ;
    USE SIGNAL ;
    PORT
      LAYER M5 ;
        RECT  11.376 0 11.4 0.192 ;
    END
  END o0[41]
  PIN o0[420]
    DIRECTION OUTPUT ;
    USE SIGNAL ;
    PORT
      LAYER M5 ;
        RECT  74.928 0 74.952 0.192 ;
    END
  END o0[420]
  PIN o0[421]
    DIRECTION OUTPUT ;
    USE SIGNAL ;
    PORT
      LAYER M5 ;
        RECT  75.072 0 75.096 0.192 ;
    END
  END o0[421]
  PIN o0[422]
    DIRECTION OUTPUT ;
    USE SIGNAL ;
    PORT
      LAYER M5 ;
        RECT  75.264 0 75.288 0.192 ;
    END
  END o0[422]
  PIN o0[423]
    DIRECTION OUTPUT ;
    USE SIGNAL ;
    PORT
      LAYER M5 ;
        RECT  75.408 0 75.432 0.192 ;
    END
  END o0[423]
  PIN o0[424]
    DIRECTION OUTPUT ;
    USE SIGNAL ;
    PORT
      LAYER M5 ;
        RECT  75.6 0 75.624 0.192 ;
    END
  END o0[424]
  PIN o0[425]
    DIRECTION OUTPUT ;
    USE SIGNAL ;
    PORT
      LAYER M5 ;
        RECT  75.744 0 75.768 0.192 ;
    END
  END o0[425]
  PIN o0[426]
    DIRECTION OUTPUT ;
    USE SIGNAL ;
    PORT
      LAYER M5 ;
        RECT  75.936 0 75.96 0.192 ;
    END
  END o0[426]
  PIN o0[427]
    DIRECTION OUTPUT ;
    USE SIGNAL ;
    PORT
      LAYER M5 ;
        RECT  76.08 0 76.104 0.192 ;
    END
  END o0[427]
  PIN o0[428]
    DIRECTION OUTPUT ;
    USE SIGNAL ;
    PORT
      LAYER M5 ;
        RECT  76.272 0 76.296 0.192 ;
    END
  END o0[428]
  PIN o0[429]
    DIRECTION OUTPUT ;
    USE SIGNAL ;
    PORT
      LAYER M5 ;
        RECT  76.416 0 76.44 0.192 ;
    END
  END o0[429]
  PIN o0[42]
    DIRECTION OUTPUT ;
    USE SIGNAL ;
    PORT
      LAYER M5 ;
        RECT  11.52 0 11.544 0.192 ;
    END
  END o0[42]
  PIN o0[430]
    DIRECTION OUTPUT ;
    USE SIGNAL ;
    PORT
      LAYER M5 ;
        RECT  76.608 0 76.632 0.192 ;
    END
  END o0[430]
  PIN o0[431]
    DIRECTION OUTPUT ;
    USE SIGNAL ;
    PORT
      LAYER M5 ;
        RECT  76.752 0 76.776 0.192 ;
    END
  END o0[431]
  PIN o0[432]
    DIRECTION OUTPUT ;
    USE SIGNAL ;
    PORT
      LAYER M5 ;
        RECT  76.944 0 76.968 0.192 ;
    END
  END o0[432]
  PIN o0[433]
    DIRECTION OUTPUT ;
    USE SIGNAL ;
    PORT
      LAYER M5 ;
        RECT  77.088 0 77.112 0.192 ;
    END
  END o0[433]
  PIN o0[434]
    DIRECTION OUTPUT ;
    USE SIGNAL ;
    PORT
      LAYER M5 ;
        RECT  77.28 0 77.304 0.192 ;
    END
  END o0[434]
  PIN o0[435]
    DIRECTION OUTPUT ;
    USE SIGNAL ;
    PORT
      LAYER M5 ;
        RECT  77.424 0 77.448 0.192 ;
    END
  END o0[435]
  PIN o0[436]
    DIRECTION OUTPUT ;
    USE SIGNAL ;
    PORT
      LAYER M5 ;
        RECT  77.616 0 77.64 0.192 ;
    END
  END o0[436]
  PIN o0[437]
    DIRECTION OUTPUT ;
    USE SIGNAL ;
    PORT
      LAYER M5 ;
        RECT  77.76 0 77.784 0.192 ;
    END
  END o0[437]
  PIN o0[438]
    DIRECTION OUTPUT ;
    USE SIGNAL ;
    PORT
      LAYER M5 ;
        RECT  77.904 0 77.928 0.192 ;
    END
  END o0[438]
  PIN o0[439]
    DIRECTION OUTPUT ;
    USE SIGNAL ;
    PORT
      LAYER M5 ;
        RECT  78.096 0 78.12 0.192 ;
    END
  END o0[439]
  PIN o0[43]
    DIRECTION OUTPUT ;
    USE SIGNAL ;
    PORT
      LAYER M5 ;
        RECT  11.712 0 11.736 0.192 ;
    END
  END o0[43]
  PIN o0[440]
    DIRECTION OUTPUT ;
    USE SIGNAL ;
    PORT
      LAYER M5 ;
        RECT  78.24 0 78.264 0.192 ;
    END
  END o0[440]
  PIN o0[441]
    DIRECTION OUTPUT ;
    USE SIGNAL ;
    PORT
      LAYER M5 ;
        RECT  78.432 0 78.456 0.192 ;
    END
  END o0[441]
  PIN o0[442]
    DIRECTION OUTPUT ;
    USE SIGNAL ;
    PORT
      LAYER M5 ;
        RECT  78.576 0 78.6 0.192 ;
    END
  END o0[442]
  PIN o0[443]
    DIRECTION OUTPUT ;
    USE SIGNAL ;
    PORT
      LAYER M5 ;
        RECT  78.768 0 78.792 0.192 ;
    END
  END o0[443]
  PIN o0[444]
    DIRECTION OUTPUT ;
    USE SIGNAL ;
    PORT
      LAYER M5 ;
        RECT  78.912 0 78.936 0.192 ;
    END
  END o0[444]
  PIN o0[445]
    DIRECTION OUTPUT ;
    USE SIGNAL ;
    PORT
      LAYER M5 ;
        RECT  79.104 0 79.128 0.192 ;
    END
  END o0[445]
  PIN o0[446]
    DIRECTION OUTPUT ;
    USE SIGNAL ;
    PORT
      LAYER M5 ;
        RECT  79.248 0 79.272 0.192 ;
    END
  END o0[446]
  PIN o0[447]
    DIRECTION OUTPUT ;
    USE SIGNAL ;
    PORT
      LAYER M5 ;
        RECT  79.44 0 79.464 0.192 ;
    END
  END o0[447]
  PIN o0[448]
    DIRECTION OUTPUT ;
    USE SIGNAL ;
    PORT
      LAYER M5 ;
        RECT  79.584 0 79.608 0.192 ;
    END
  END o0[448]
  PIN o0[449]
    DIRECTION OUTPUT ;
    USE SIGNAL ;
    PORT
      LAYER M5 ;
        RECT  79.776 0 79.8 0.192 ;
    END
  END o0[449]
  PIN o0[44]
    DIRECTION OUTPUT ;
    USE SIGNAL ;
    PORT
      LAYER M5 ;
        RECT  11.856 0 11.88 0.192 ;
    END
  END o0[44]
  PIN o0[450]
    DIRECTION OUTPUT ;
    USE SIGNAL ;
    PORT
      LAYER M5 ;
        RECT  79.92 0 79.944 0.192 ;
    END
  END o0[450]
  PIN o0[451]
    DIRECTION OUTPUT ;
    USE SIGNAL ;
    PORT
      LAYER M5 ;
        RECT  80.112 0 80.136 0.192 ;
    END
  END o0[451]
  PIN o0[452]
    DIRECTION OUTPUT ;
    USE SIGNAL ;
    PORT
      LAYER M5 ;
        RECT  80.256 0 80.28 0.192 ;
    END
  END o0[452]
  PIN o0[453]
    DIRECTION OUTPUT ;
    USE SIGNAL ;
    PORT
      LAYER M5 ;
        RECT  80.448 0 80.472 0.192 ;
    END
  END o0[453]
  PIN o0[454]
    DIRECTION OUTPUT ;
    USE SIGNAL ;
    PORT
      LAYER M5 ;
        RECT  80.592 0 80.616 0.192 ;
    END
  END o0[454]
  PIN o0[455]
    DIRECTION OUTPUT ;
    USE SIGNAL ;
    PORT
      LAYER M5 ;
        RECT  80.784 0 80.808 0.192 ;
    END
  END o0[455]
  PIN o0[456]
    DIRECTION OUTPUT ;
    USE SIGNAL ;
    PORT
      LAYER M5 ;
        RECT  80.928 0 80.952 0.192 ;
    END
  END o0[456]
  PIN o0[457]
    DIRECTION OUTPUT ;
    USE SIGNAL ;
    PORT
      LAYER M5 ;
        RECT  81.12 0 81.144 0.192 ;
    END
  END o0[457]
  PIN o0[458]
    DIRECTION OUTPUT ;
    USE SIGNAL ;
    PORT
      LAYER M5 ;
        RECT  81.264 0 81.288 0.192 ;
    END
  END o0[458]
  PIN o0[459]
    DIRECTION OUTPUT ;
    USE SIGNAL ;
    PORT
      LAYER M5 ;
        RECT  81.456 0 81.48 0.192 ;
    END
  END o0[459]
  PIN o0[45]
    DIRECTION OUTPUT ;
    USE SIGNAL ;
    PORT
      LAYER M5 ;
        RECT  12.048 0 12.072 0.192 ;
    END
  END o0[45]
  PIN o0[460]
    DIRECTION OUTPUT ;
    USE SIGNAL ;
    PORT
      LAYER M5 ;
        RECT  81.6 0 81.624 0.192 ;
    END
  END o0[460]
  PIN o0[461]
    DIRECTION OUTPUT ;
    USE SIGNAL ;
    PORT
      LAYER M5 ;
        RECT  81.792 0 81.816 0.192 ;
    END
  END o0[461]
  PIN o0[462]
    DIRECTION OUTPUT ;
    USE SIGNAL ;
    PORT
      LAYER M5 ;
        RECT  81.936 0 81.96 0.192 ;
    END
  END o0[462]
  PIN o0[463]
    DIRECTION OUTPUT ;
    USE SIGNAL ;
    PORT
      LAYER M5 ;
        RECT  82.128 0 82.152 0.192 ;
    END
  END o0[463]
  PIN o0[464]
    DIRECTION OUTPUT ;
    USE SIGNAL ;
    PORT
      LAYER M5 ;
        RECT  82.272 0 82.296 0.192 ;
    END
  END o0[464]
  PIN o0[465]
    DIRECTION OUTPUT ;
    USE SIGNAL ;
    PORT
      LAYER M5 ;
        RECT  82.464 0 82.488 0.192 ;
    END
  END o0[465]
  PIN o0[466]
    DIRECTION OUTPUT ;
    USE SIGNAL ;
    PORT
      LAYER M5 ;
        RECT  82.608 0 82.632 0.192 ;
    END
  END o0[466]
  PIN o0[467]
    DIRECTION OUTPUT ;
    USE SIGNAL ;
    PORT
      LAYER M5 ;
        RECT  82.8 0 82.824 0.192 ;
    END
  END o0[467]
  PIN o0[468]
    DIRECTION OUTPUT ;
    USE SIGNAL ;
    PORT
      LAYER M5 ;
        RECT  82.944 0 82.968 0.192 ;
    END
  END o0[468]
  PIN o0[469]
    DIRECTION OUTPUT ;
    USE SIGNAL ;
    PORT
      LAYER M5 ;
        RECT  83.136 0 83.16 0.192 ;
    END
  END o0[469]
  PIN o0[46]
    DIRECTION OUTPUT ;
    USE SIGNAL ;
    PORT
      LAYER M5 ;
        RECT  12.192 0 12.216 0.192 ;
    END
  END o0[46]
  PIN o0[470]
    DIRECTION OUTPUT ;
    USE SIGNAL ;
    PORT
      LAYER M5 ;
        RECT  83.28 0 83.304 0.192 ;
    END
  END o0[470]
  PIN o0[471]
    DIRECTION OUTPUT ;
    USE SIGNAL ;
    PORT
      LAYER M5 ;
        RECT  83.424 0 83.448 0.192 ;
    END
  END o0[471]
  PIN o0[472]
    DIRECTION OUTPUT ;
    USE SIGNAL ;
    PORT
      LAYER M5 ;
        RECT  83.616 0 83.64 0.192 ;
    END
  END o0[472]
  PIN o0[473]
    DIRECTION OUTPUT ;
    USE SIGNAL ;
    PORT
      LAYER M5 ;
        RECT  83.76 0 83.784 0.192 ;
    END
  END o0[473]
  PIN o0[474]
    DIRECTION OUTPUT ;
    USE SIGNAL ;
    PORT
      LAYER M5 ;
        RECT  83.952 0 83.976 0.192 ;
    END
  END o0[474]
  PIN o0[475]
    DIRECTION OUTPUT ;
    USE SIGNAL ;
    PORT
      LAYER M5 ;
        RECT  84.096 0 84.12 0.192 ;
    END
  END o0[475]
  PIN o0[476]
    DIRECTION OUTPUT ;
    USE SIGNAL ;
    PORT
      LAYER M5 ;
        RECT  84.288 0 84.312 0.192 ;
    END
  END o0[476]
  PIN o0[477]
    DIRECTION OUTPUT ;
    USE SIGNAL ;
    PORT
      LAYER M5 ;
        RECT  84.432 0 84.456 0.192 ;
    END
  END o0[477]
  PIN o0[478]
    DIRECTION OUTPUT ;
    USE SIGNAL ;
    PORT
      LAYER M5 ;
        RECT  84.624 0 84.648 0.192 ;
    END
  END o0[478]
  PIN o0[479]
    DIRECTION OUTPUT ;
    USE SIGNAL ;
    PORT
      LAYER M5 ;
        RECT  84.768 0 84.792 0.192 ;
    END
  END o0[479]
  PIN o0[47]
    DIRECTION OUTPUT ;
    USE SIGNAL ;
    PORT
      LAYER M5 ;
        RECT  12.384 0 12.408 0.192 ;
    END
  END o0[47]
  PIN o0[480]
    DIRECTION OUTPUT ;
    USE SIGNAL ;
    PORT
      LAYER M5 ;
        RECT  84.96 0 84.984 0.192 ;
    END
  END o0[480]
  PIN o0[481]
    DIRECTION OUTPUT ;
    USE SIGNAL ;
    PORT
      LAYER M5 ;
        RECT  85.104 0 85.128 0.192 ;
    END
  END o0[481]
  PIN o0[482]
    DIRECTION OUTPUT ;
    USE SIGNAL ;
    PORT
      LAYER M5 ;
        RECT  85.296 0 85.32 0.192 ;
    END
  END o0[482]
  PIN o0[483]
    DIRECTION OUTPUT ;
    USE SIGNAL ;
    PORT
      LAYER M5 ;
        RECT  85.44 0 85.464 0.192 ;
    END
  END o0[483]
  PIN o0[484]
    DIRECTION OUTPUT ;
    USE SIGNAL ;
    PORT
      LAYER M5 ;
        RECT  85.632 0 85.656 0.192 ;
    END
  END o0[484]
  PIN o0[485]
    DIRECTION OUTPUT ;
    USE SIGNAL ;
    PORT
      LAYER M5 ;
        RECT  85.776 0 85.8 0.192 ;
    END
  END o0[485]
  PIN o0[486]
    DIRECTION OUTPUT ;
    USE SIGNAL ;
    PORT
      LAYER M5 ;
        RECT  85.968 0 85.992 0.192 ;
    END
  END o0[486]
  PIN o0[487]
    DIRECTION OUTPUT ;
    USE SIGNAL ;
    PORT
      LAYER M5 ;
        RECT  86.112 0 86.136 0.192 ;
    END
  END o0[487]
  PIN o0[488]
    DIRECTION OUTPUT ;
    USE SIGNAL ;
    PORT
      LAYER M5 ;
        RECT  86.304 0 86.328 0.192 ;
    END
  END o0[488]
  PIN o0[489]
    DIRECTION OUTPUT ;
    USE SIGNAL ;
    PORT
      LAYER M5 ;
        RECT  86.448 0 86.472 0.192 ;
    END
  END o0[489]
  PIN o0[48]
    DIRECTION OUTPUT ;
    USE SIGNAL ;
    PORT
      LAYER M5 ;
        RECT  12.528 0 12.552 0.192 ;
    END
  END o0[48]
  PIN o0[490]
    DIRECTION OUTPUT ;
    USE SIGNAL ;
    PORT
      LAYER M5 ;
        RECT  86.64 0 86.664 0.192 ;
    END
  END o0[490]
  PIN o0[491]
    DIRECTION OUTPUT ;
    USE SIGNAL ;
    PORT
      LAYER M5 ;
        RECT  86.784 0 86.808 0.192 ;
    END
  END o0[491]
  PIN o0[492]
    DIRECTION OUTPUT ;
    USE SIGNAL ;
    PORT
      LAYER M5 ;
        RECT  86.976 0 87 0.192 ;
    END
  END o0[492]
  PIN o0[493]
    DIRECTION OUTPUT ;
    USE SIGNAL ;
    PORT
      LAYER M5 ;
        RECT  87.12 0 87.144 0.192 ;
    END
  END o0[493]
  PIN o0[494]
    DIRECTION OUTPUT ;
    USE SIGNAL ;
    PORT
      LAYER M5 ;
        RECT  87.312 0 87.336 0.192 ;
    END
  END o0[494]
  PIN o0[495]
    DIRECTION OUTPUT ;
    USE SIGNAL ;
    PORT
      LAYER M5 ;
        RECT  87.456 0 87.48 0.192 ;
    END
  END o0[495]
  PIN o0[496]
    DIRECTION OUTPUT ;
    USE SIGNAL ;
    PORT
      LAYER M5 ;
        RECT  87.648 0 87.672 0.192 ;
    END
  END o0[496]
  PIN o0[497]
    DIRECTION OUTPUT ;
    USE SIGNAL ;
    PORT
      LAYER M5 ;
        RECT  87.792 0 87.816 0.192 ;
    END
  END o0[497]
  PIN o0[498]
    DIRECTION OUTPUT ;
    USE SIGNAL ;
    PORT
      LAYER M5 ;
        RECT  87.984 0 88.008 0.192 ;
    END
  END o0[498]
  PIN o0[499]
    DIRECTION OUTPUT ;
    USE SIGNAL ;
    PORT
      LAYER M5 ;
        RECT  88.128 0 88.152 0.192 ;
    END
  END o0[499]
  PIN o0[49]
    DIRECTION OUTPUT ;
    USE SIGNAL ;
    PORT
      LAYER M5 ;
        RECT  12.72 0 12.744 0.192 ;
    END
  END o0[49]
  PIN o0[4]
    DIRECTION OUTPUT ;
    USE SIGNAL ;
    PORT
      LAYER M5 ;
        RECT  5.184 0 5.208 0.192 ;
    END
  END o0[4]
  PIN o0[500]
    DIRECTION OUTPUT ;
    USE SIGNAL ;
    PORT
      LAYER M5 ;
        RECT  88.32 0 88.344 0.192 ;
    END
  END o0[500]
  PIN o0[501]
    DIRECTION OUTPUT ;
    USE SIGNAL ;
    PORT
      LAYER M5 ;
        RECT  88.464 0 88.488 0.192 ;
    END
  END o0[501]
  PIN o0[502]
    DIRECTION OUTPUT ;
    USE SIGNAL ;
    PORT
      LAYER M5 ;
        RECT  88.608 0 88.632 0.192 ;
    END
  END o0[502]
  PIN o0[503]
    DIRECTION OUTPUT ;
    USE SIGNAL ;
    PORT
      LAYER M5 ;
        RECT  88.8 0 88.824 0.192 ;
    END
  END o0[503]
  PIN o0[504]
    DIRECTION OUTPUT ;
    USE SIGNAL ;
    PORT
      LAYER M5 ;
        RECT  88.944 0 88.968 0.192 ;
    END
  END o0[504]
  PIN o0[505]
    DIRECTION OUTPUT ;
    USE SIGNAL ;
    PORT
      LAYER M5 ;
        RECT  89.136 0 89.16 0.192 ;
    END
  END o0[505]
  PIN o0[506]
    DIRECTION OUTPUT ;
    USE SIGNAL ;
    PORT
      LAYER M5 ;
        RECT  89.28 0 89.304 0.192 ;
    END
  END o0[506]
  PIN o0[507]
    DIRECTION OUTPUT ;
    USE SIGNAL ;
    PORT
      LAYER M5 ;
        RECT  89.472 0 89.496 0.192 ;
    END
  END o0[507]
  PIN o0[508]
    DIRECTION OUTPUT ;
    USE SIGNAL ;
    PORT
      LAYER M5 ;
        RECT  89.616 0 89.64 0.192 ;
    END
  END o0[508]
  PIN o0[509]
    DIRECTION OUTPUT ;
    USE SIGNAL ;
    PORT
      LAYER M5 ;
        RECT  89.808 0 89.832 0.192 ;
    END
  END o0[509]
  PIN o0[50]
    DIRECTION OUTPUT ;
    USE SIGNAL ;
    PORT
      LAYER M5 ;
        RECT  12.864 0 12.888 0.192 ;
    END
  END o0[50]
  PIN o0[510]
    DIRECTION OUTPUT ;
    USE SIGNAL ;
    PORT
      LAYER M5 ;
        RECT  89.952 0 89.976 0.192 ;
    END
  END o0[510]
  PIN o0[511]
    DIRECTION OUTPUT ;
    USE SIGNAL ;
    PORT
      LAYER M5 ;
        RECT  90.144 0 90.168 0.192 ;
    END
  END o0[511]
  PIN o0[512]
    DIRECTION OUTPUT ;
    USE SIGNAL ;
    PORT
      LAYER M5 ;
        RECT  90.288 0 90.312 0.192 ;
    END
  END o0[512]
  PIN o0[513]
    DIRECTION OUTPUT ;
    USE SIGNAL ;
    PORT
      LAYER M5 ;
        RECT  90.48 0 90.504 0.192 ;
    END
  END o0[513]
  PIN o0[514]
    DIRECTION OUTPUT ;
    USE SIGNAL ;
    PORT
      LAYER M5 ;
        RECT  90.624 0 90.648 0.192 ;
    END
  END o0[514]
  PIN o0[515]
    DIRECTION OUTPUT ;
    USE SIGNAL ;
    PORT
      LAYER M5 ;
        RECT  90.816 0 90.84 0.192 ;
    END
  END o0[515]
  PIN o0[516]
    DIRECTION OUTPUT ;
    USE SIGNAL ;
    PORT
      LAYER M5 ;
        RECT  90.96 0 90.984 0.192 ;
    END
  END o0[516]
  PIN o0[517]
    DIRECTION OUTPUT ;
    USE SIGNAL ;
    PORT
      LAYER M5 ;
        RECT  91.152 0 91.176 0.192 ;
    END
  END o0[517]
  PIN o0[518]
    DIRECTION OUTPUT ;
    USE SIGNAL ;
    PORT
      LAYER M5 ;
        RECT  91.296 0 91.32 0.192 ;
    END
  END o0[518]
  PIN o0[519]
    DIRECTION OUTPUT ;
    USE SIGNAL ;
    PORT
      LAYER M5 ;
        RECT  91.488 0 91.512 0.192 ;
    END
  END o0[519]
  PIN o0[51]
    DIRECTION OUTPUT ;
    USE SIGNAL ;
    PORT
      LAYER M5 ;
        RECT  13.056 0 13.08 0.192 ;
    END
  END o0[51]
  PIN o0[520]
    DIRECTION OUTPUT ;
    USE SIGNAL ;
    PORT
      LAYER M5 ;
        RECT  91.632 0 91.656 0.192 ;
    END
  END o0[520]
  PIN o0[521]
    DIRECTION OUTPUT ;
    USE SIGNAL ;
    PORT
      LAYER M5 ;
        RECT  91.824 0 91.848 0.192 ;
    END
  END o0[521]
  PIN o0[522]
    DIRECTION OUTPUT ;
    USE SIGNAL ;
    PORT
      LAYER M5 ;
        RECT  91.968 0 91.992 0.192 ;
    END
  END o0[522]
  PIN o0[523]
    DIRECTION OUTPUT ;
    USE SIGNAL ;
    PORT
      LAYER M5 ;
        RECT  92.16 0 92.184 0.192 ;
    END
  END o0[523]
  PIN o0[524]
    DIRECTION OUTPUT ;
    USE SIGNAL ;
    PORT
      LAYER M5 ;
        RECT  92.304 0 92.328 0.192 ;
    END
  END o0[524]
  PIN o0[525]
    DIRECTION OUTPUT ;
    USE SIGNAL ;
    PORT
      LAYER M5 ;
        RECT  92.496 0 92.52 0.192 ;
    END
  END o0[525]
  PIN o0[526]
    DIRECTION OUTPUT ;
    USE SIGNAL ;
    PORT
      LAYER M5 ;
        RECT  92.64 0 92.664 0.192 ;
    END
  END o0[526]
  PIN o0[527]
    DIRECTION OUTPUT ;
    USE SIGNAL ;
    PORT
      LAYER M5 ;
        RECT  92.832 0 92.856 0.192 ;
    END
  END o0[527]
  PIN o0[528]
    DIRECTION OUTPUT ;
    USE SIGNAL ;
    PORT
      LAYER M5 ;
        RECT  92.976 0 93 0.192 ;
    END
  END o0[528]
  PIN o0[529]
    DIRECTION OUTPUT ;
    USE SIGNAL ;
    PORT
      LAYER M5 ;
        RECT  93.168 0 93.192 0.192 ;
    END
  END o0[529]
  PIN o0[52]
    DIRECTION OUTPUT ;
    USE SIGNAL ;
    PORT
      LAYER M5 ;
        RECT  13.2 0 13.224 0.192 ;
    END
  END o0[52]
  PIN o0[530]
    DIRECTION OUTPUT ;
    USE SIGNAL ;
    PORT
      LAYER M5 ;
        RECT  93.312 0 93.336 0.192 ;
    END
  END o0[530]
  PIN o0[531]
    DIRECTION OUTPUT ;
    USE SIGNAL ;
    PORT
      LAYER M5 ;
        RECT  93.504 0 93.528 0.192 ;
    END
  END o0[531]
  PIN o0[532]
    DIRECTION OUTPUT ;
    USE SIGNAL ;
    PORT
      LAYER M5 ;
        RECT  93.648 0 93.672 0.192 ;
    END
  END o0[532]
  PIN o0[533]
    DIRECTION OUTPUT ;
    USE SIGNAL ;
    PORT
      LAYER M5 ;
        RECT  93.84 0 93.864 0.192 ;
    END
  END o0[533]
  PIN o0[534]
    DIRECTION OUTPUT ;
    USE SIGNAL ;
    PORT
      LAYER M5 ;
        RECT  93.984 0 94.008 0.192 ;
    END
  END o0[534]
  PIN o0[535]
    DIRECTION OUTPUT ;
    USE SIGNAL ;
    PORT
      LAYER M5 ;
        RECT  94.128 0 94.152 0.192 ;
    END
  END o0[535]
  PIN o0[536]
    DIRECTION OUTPUT ;
    USE SIGNAL ;
    PORT
      LAYER M5 ;
        RECT  94.32 0 94.344 0.192 ;
    END
  END o0[536]
  PIN o0[537]
    DIRECTION OUTPUT ;
    USE SIGNAL ;
    PORT
      LAYER M5 ;
        RECT  94.464 0 94.488 0.192 ;
    END
  END o0[537]
  PIN o0[538]
    DIRECTION OUTPUT ;
    USE SIGNAL ;
    PORT
      LAYER M5 ;
        RECT  94.656 0 94.68 0.192 ;
    END
  END o0[538]
  PIN o0[539]
    DIRECTION OUTPUT ;
    USE SIGNAL ;
    PORT
      LAYER M5 ;
        RECT  94.8 0 94.824 0.192 ;
    END
  END o0[539]
  PIN o0[53]
    DIRECTION OUTPUT ;
    USE SIGNAL ;
    PORT
      LAYER M5 ;
        RECT  13.392 0 13.416 0.192 ;
    END
  END o0[53]
  PIN o0[540]
    DIRECTION OUTPUT ;
    USE SIGNAL ;
    PORT
      LAYER M5 ;
        RECT  94.992 0 95.016 0.192 ;
    END
  END o0[540]
  PIN o0[541]
    DIRECTION OUTPUT ;
    USE SIGNAL ;
    PORT
      LAYER M5 ;
        RECT  95.136 0 95.16 0.192 ;
    END
  END o0[541]
  PIN o0[542]
    DIRECTION OUTPUT ;
    USE SIGNAL ;
    PORT
      LAYER M5 ;
        RECT  95.328 0 95.352 0.192 ;
    END
  END o0[542]
  PIN o0[543]
    DIRECTION OUTPUT ;
    USE SIGNAL ;
    PORT
      LAYER M5 ;
        RECT  95.472 0 95.496 0.192 ;
    END
  END o0[543]
  PIN o0[544]
    DIRECTION OUTPUT ;
    USE SIGNAL ;
    PORT
      LAYER M5 ;
        RECT  95.664 0 95.688 0.192 ;
    END
  END o0[544]
  PIN o0[545]
    DIRECTION OUTPUT ;
    USE SIGNAL ;
    PORT
      LAYER M5 ;
        RECT  95.808 0 95.832 0.192 ;
    END
  END o0[545]
  PIN o0[546]
    DIRECTION OUTPUT ;
    USE SIGNAL ;
    PORT
      LAYER M5 ;
        RECT  96 0 96.024 0.192 ;
    END
  END o0[546]
  PIN o0[547]
    DIRECTION OUTPUT ;
    USE SIGNAL ;
    PORT
      LAYER M5 ;
        RECT  96.144 0 96.168 0.192 ;
    END
  END o0[547]
  PIN o0[548]
    DIRECTION OUTPUT ;
    USE SIGNAL ;
    PORT
      LAYER M5 ;
        RECT  96.336 0 96.36 0.192 ;
    END
  END o0[548]
  PIN o0[549]
    DIRECTION OUTPUT ;
    USE SIGNAL ;
    PORT
      LAYER M5 ;
        RECT  96.48 0 96.504 0.192 ;
    END
  END o0[549]
  PIN o0[54]
    DIRECTION OUTPUT ;
    USE SIGNAL ;
    PORT
      LAYER M5 ;
        RECT  13.536 0 13.56 0.192 ;
    END
  END o0[54]
  PIN o0[550]
    DIRECTION OUTPUT ;
    USE SIGNAL ;
    PORT
      LAYER M5 ;
        RECT  96.672 0 96.696 0.192 ;
    END
  END o0[550]
  PIN o0[551]
    DIRECTION OUTPUT ;
    USE SIGNAL ;
    PORT
      LAYER M5 ;
        RECT  96.816 0 96.84 0.192 ;
    END
  END o0[551]
  PIN o0[552]
    DIRECTION OUTPUT ;
    USE SIGNAL ;
    PORT
      LAYER M5 ;
        RECT  97.008 0 97.032 0.192 ;
    END
  END o0[552]
  PIN o0[553]
    DIRECTION OUTPUT ;
    USE SIGNAL ;
    PORT
      LAYER M5 ;
        RECT  97.152 0 97.176 0.192 ;
    END
  END o0[553]
  PIN o0[554]
    DIRECTION OUTPUT ;
    USE SIGNAL ;
    PORT
      LAYER M5 ;
        RECT  97.344 0 97.368 0.192 ;
    END
  END o0[554]
  PIN o0[555]
    DIRECTION OUTPUT ;
    USE SIGNAL ;
    PORT
      LAYER M5 ;
        RECT  97.488 0 97.512 0.192 ;
    END
  END o0[555]
  PIN o0[556]
    DIRECTION OUTPUT ;
    USE SIGNAL ;
    PORT
      LAYER M5 ;
        RECT  97.68 0 97.704 0.192 ;
    END
  END o0[556]
  PIN o0[557]
    DIRECTION OUTPUT ;
    USE SIGNAL ;
    PORT
      LAYER M5 ;
        RECT  97.824 0 97.848 0.192 ;
    END
  END o0[557]
  PIN o0[558]
    DIRECTION OUTPUT ;
    USE SIGNAL ;
    PORT
      LAYER M5 ;
        RECT  98.016 0 98.04 0.192 ;
    END
  END o0[558]
  PIN o0[559]
    DIRECTION OUTPUT ;
    USE SIGNAL ;
    PORT
      LAYER M5 ;
        RECT  98.16 0 98.184 0.192 ;
    END
  END o0[559]
  PIN o0[55]
    DIRECTION OUTPUT ;
    USE SIGNAL ;
    PORT
      LAYER M5 ;
        RECT  13.728 0 13.752 0.192 ;
    END
  END o0[55]
  PIN o0[560]
    DIRECTION OUTPUT ;
    USE SIGNAL ;
    PORT
      LAYER M5 ;
        RECT  98.352 0 98.376 0.192 ;
    END
  END o0[560]
  PIN o0[561]
    DIRECTION OUTPUT ;
    USE SIGNAL ;
    PORT
      LAYER M5 ;
        RECT  98.496 0 98.52 0.192 ;
    END
  END o0[561]
  PIN o0[562]
    DIRECTION OUTPUT ;
    USE SIGNAL ;
    PORT
      LAYER M5 ;
        RECT  98.688 0 98.712 0.192 ;
    END
  END o0[562]
  PIN o0[563]
    DIRECTION OUTPUT ;
    USE SIGNAL ;
    PORT
      LAYER M5 ;
        RECT  98.832 0 98.856 0.192 ;
    END
  END o0[563]
  PIN o0[564]
    DIRECTION OUTPUT ;
    USE SIGNAL ;
    PORT
      LAYER M5 ;
        RECT  99.024 0 99.048 0.192 ;
    END
  END o0[564]
  PIN o0[565]
    DIRECTION OUTPUT ;
    USE SIGNAL ;
    PORT
      LAYER M5 ;
        RECT  99.168 0 99.192 0.192 ;
    END
  END o0[565]
  PIN o0[566]
    DIRECTION OUTPUT ;
    USE SIGNAL ;
    PORT
      LAYER M5 ;
        RECT  99.312 0 99.336 0.192 ;
    END
  END o0[566]
  PIN o0[567]
    DIRECTION OUTPUT ;
    USE SIGNAL ;
    PORT
      LAYER M5 ;
        RECT  99.504 0 99.528 0.192 ;
    END
  END o0[567]
  PIN o0[568]
    DIRECTION OUTPUT ;
    USE SIGNAL ;
    PORT
      LAYER M5 ;
        RECT  99.648 0 99.672 0.192 ;
    END
  END o0[568]
  PIN o0[569]
    DIRECTION OUTPUT ;
    USE SIGNAL ;
    PORT
      LAYER M5 ;
        RECT  99.84 0 99.864 0.192 ;
    END
  END o0[569]
  PIN o0[56]
    DIRECTION OUTPUT ;
    USE SIGNAL ;
    PORT
      LAYER M5 ;
        RECT  13.872 0 13.896 0.192 ;
    END
  END o0[56]
  PIN o0[570]
    DIRECTION OUTPUT ;
    USE SIGNAL ;
    PORT
      LAYER M5 ;
        RECT  99.984 0 100.008 0.192 ;
    END
  END o0[570]
  PIN o0[571]
    DIRECTION OUTPUT ;
    USE SIGNAL ;
    PORT
      LAYER M5 ;
        RECT  100.176 0 100.2 0.192 ;
    END
  END o0[571]
  PIN o0[572]
    DIRECTION OUTPUT ;
    USE SIGNAL ;
    PORT
      LAYER M5 ;
        RECT  100.32 0 100.344 0.192 ;
    END
  END o0[572]
  PIN o0[573]
    DIRECTION OUTPUT ;
    USE SIGNAL ;
    PORT
      LAYER M5 ;
        RECT  100.512 0 100.536 0.192 ;
    END
  END o0[573]
  PIN o0[574]
    DIRECTION OUTPUT ;
    USE SIGNAL ;
    PORT
      LAYER M5 ;
        RECT  100.656 0 100.68 0.192 ;
    END
  END o0[574]
  PIN o0[575]
    DIRECTION OUTPUT ;
    USE SIGNAL ;
    PORT
      LAYER M5 ;
        RECT  100.848 0 100.872 0.192 ;
    END
  END o0[575]
  PIN o0[576]
    DIRECTION OUTPUT ;
    USE SIGNAL ;
    PORT
      LAYER M5 ;
        RECT  100.992 0 101.016 0.192 ;
    END
  END o0[576]
  PIN o0[577]
    DIRECTION OUTPUT ;
    USE SIGNAL ;
    PORT
      LAYER M5 ;
        RECT  101.184 0 101.208 0.192 ;
    END
  END o0[577]
  PIN o0[578]
    DIRECTION OUTPUT ;
    USE SIGNAL ;
    PORT
      LAYER M5 ;
        RECT  101.328 0 101.352 0.192 ;
    END
  END o0[578]
  PIN o0[579]
    DIRECTION OUTPUT ;
    USE SIGNAL ;
    PORT
      LAYER M5 ;
        RECT  101.52 0 101.544 0.192 ;
    END
  END o0[579]
  PIN o0[57]
    DIRECTION OUTPUT ;
    USE SIGNAL ;
    PORT
      LAYER M5 ;
        RECT  14.064 0 14.088 0.192 ;
    END
  END o0[57]
  PIN o0[580]
    DIRECTION OUTPUT ;
    USE SIGNAL ;
    PORT
      LAYER M5 ;
        RECT  101.664 0 101.688 0.192 ;
    END
  END o0[580]
  PIN o0[581]
    DIRECTION OUTPUT ;
    USE SIGNAL ;
    PORT
      LAYER M5 ;
        RECT  101.856 0 101.88 0.192 ;
    END
  END o0[581]
  PIN o0[582]
    DIRECTION OUTPUT ;
    USE SIGNAL ;
    PORT
      LAYER M5 ;
        RECT  102 0 102.024 0.192 ;
    END
  END o0[582]
  PIN o0[583]
    DIRECTION OUTPUT ;
    USE SIGNAL ;
    PORT
      LAYER M5 ;
        RECT  102.192 0 102.216 0.192 ;
    END
  END o0[583]
  PIN o0[584]
    DIRECTION OUTPUT ;
    USE SIGNAL ;
    PORT
      LAYER M5 ;
        RECT  102.336 0 102.36 0.192 ;
    END
  END o0[584]
  PIN o0[585]
    DIRECTION OUTPUT ;
    USE SIGNAL ;
    PORT
      LAYER M5 ;
        RECT  102.528 0 102.552 0.192 ;
    END
  END o0[585]
  PIN o0[586]
    DIRECTION OUTPUT ;
    USE SIGNAL ;
    PORT
      LAYER M5 ;
        RECT  102.672 0 102.696 0.192 ;
    END
  END o0[586]
  PIN o0[587]
    DIRECTION OUTPUT ;
    USE SIGNAL ;
    PORT
      LAYER M5 ;
        RECT  102.864 0 102.888 0.192 ;
    END
  END o0[587]
  PIN o0[588]
    DIRECTION OUTPUT ;
    USE SIGNAL ;
    PORT
      LAYER M5 ;
        RECT  103.008 0 103.032 0.192 ;
    END
  END o0[588]
  PIN o0[589]
    DIRECTION OUTPUT ;
    USE SIGNAL ;
    PORT
      LAYER M5 ;
        RECT  103.2 0 103.224 0.192 ;
    END
  END o0[589]
  PIN o0[58]
    DIRECTION OUTPUT ;
    USE SIGNAL ;
    PORT
      LAYER M5 ;
        RECT  14.208 0 14.232 0.192 ;
    END
  END o0[58]
  PIN o0[590]
    DIRECTION OUTPUT ;
    USE SIGNAL ;
    PORT
      LAYER M5 ;
        RECT  103.344 0 103.368 0.192 ;
    END
  END o0[590]
  PIN o0[591]
    DIRECTION OUTPUT ;
    USE SIGNAL ;
    PORT
      LAYER M5 ;
        RECT  103.536 0 103.56 0.192 ;
    END
  END o0[591]
  PIN o0[592]
    DIRECTION OUTPUT ;
    USE SIGNAL ;
    PORT
      LAYER M5 ;
        RECT  103.68 0 103.704 0.192 ;
    END
  END o0[592]
  PIN o0[593]
    DIRECTION OUTPUT ;
    USE SIGNAL ;
    PORT
      LAYER M5 ;
        RECT  103.872 0 103.896 0.192 ;
    END
  END o0[593]
  PIN o0[594]
    DIRECTION OUTPUT ;
    USE SIGNAL ;
    PORT
      LAYER M5 ;
        RECT  104.016 0 104.04 0.192 ;
    END
  END o0[594]
  PIN o0[595]
    DIRECTION OUTPUT ;
    USE SIGNAL ;
    PORT
      LAYER M5 ;
        RECT  104.208 0 104.232 0.192 ;
    END
  END o0[595]
  PIN o0[596]
    DIRECTION OUTPUT ;
    USE SIGNAL ;
    PORT
      LAYER M5 ;
        RECT  104.352 0 104.376 0.192 ;
    END
  END o0[596]
  PIN o0[597]
    DIRECTION OUTPUT ;
    USE SIGNAL ;
    PORT
      LAYER M5 ;
        RECT  104.496 0 104.52 0.192 ;
    END
  END o0[597]
  PIN o0[598]
    DIRECTION OUTPUT ;
    USE SIGNAL ;
    PORT
      LAYER M5 ;
        RECT  104.688 0 104.712 0.192 ;
    END
  END o0[598]
  PIN o0[599]
    DIRECTION OUTPUT ;
    USE SIGNAL ;
    PORT
      LAYER M5 ;
        RECT  104.832 0 104.856 0.192 ;
    END
  END o0[599]
  PIN o0[59]
    DIRECTION OUTPUT ;
    USE SIGNAL ;
    PORT
      LAYER M5 ;
        RECT  14.352 0 14.376 0.192 ;
    END
  END o0[59]
  PIN o0[5]
    DIRECTION OUTPUT ;
    USE SIGNAL ;
    PORT
      LAYER M5 ;
        RECT  5.328 0 5.352 0.192 ;
    END
  END o0[5]
  PIN o0[600]
    DIRECTION OUTPUT ;
    USE SIGNAL ;
    PORT
      LAYER M5 ;
        RECT  105.024 0 105.048 0.192 ;
    END
  END o0[600]
  PIN o0[601]
    DIRECTION OUTPUT ;
    USE SIGNAL ;
    PORT
      LAYER M5 ;
        RECT  105.168 0 105.192 0.192 ;
    END
  END o0[601]
  PIN o0[602]
    DIRECTION OUTPUT ;
    USE SIGNAL ;
    PORT
      LAYER M5 ;
        RECT  105.36 0 105.384 0.192 ;
    END
  END o0[602]
  PIN o0[603]
    DIRECTION OUTPUT ;
    USE SIGNAL ;
    PORT
      LAYER M5 ;
        RECT  105.504 0 105.528 0.192 ;
    END
  END o0[603]
  PIN o0[604]
    DIRECTION OUTPUT ;
    USE SIGNAL ;
    PORT
      LAYER M5 ;
        RECT  105.696 0 105.72 0.192 ;
    END
  END o0[604]
  PIN o0[605]
    DIRECTION OUTPUT ;
    USE SIGNAL ;
    PORT
      LAYER M5 ;
        RECT  105.84 0 105.864 0.192 ;
    END
  END o0[605]
  PIN o0[606]
    DIRECTION OUTPUT ;
    USE SIGNAL ;
    PORT
      LAYER M5 ;
        RECT  106.032 0 106.056 0.192 ;
    END
  END o0[606]
  PIN o0[607]
    DIRECTION OUTPUT ;
    USE SIGNAL ;
    PORT
      LAYER M5 ;
        RECT  106.176 0 106.2 0.192 ;
    END
  END o0[607]
  PIN o0[608]
    DIRECTION OUTPUT ;
    USE SIGNAL ;
    PORT
      LAYER M5 ;
        RECT  106.368 0 106.392 0.192 ;
    END
  END o0[608]
  PIN o0[609]
    DIRECTION OUTPUT ;
    USE SIGNAL ;
    PORT
      LAYER M5 ;
        RECT  106.512 0 106.536 0.192 ;
    END
  END o0[609]
  PIN o0[60]
    DIRECTION OUTPUT ;
    USE SIGNAL ;
    PORT
      LAYER M5 ;
        RECT  14.544 0 14.568 0.192 ;
    END
  END o0[60]
  PIN o0[610]
    DIRECTION OUTPUT ;
    USE SIGNAL ;
    PORT
      LAYER M5 ;
        RECT  106.704 0 106.728 0.192 ;
    END
  END o0[610]
  PIN o0[611]
    DIRECTION OUTPUT ;
    USE SIGNAL ;
    PORT
      LAYER M5 ;
        RECT  106.848 0 106.872 0.192 ;
    END
  END o0[611]
  PIN o0[612]
    DIRECTION OUTPUT ;
    USE SIGNAL ;
    PORT
      LAYER M5 ;
        RECT  107.04 0 107.064 0.192 ;
    END
  END o0[612]
  PIN o0[613]
    DIRECTION OUTPUT ;
    USE SIGNAL ;
    PORT
      LAYER M5 ;
        RECT  107.184 0 107.208 0.192 ;
    END
  END o0[613]
  PIN o0[614]
    DIRECTION OUTPUT ;
    USE SIGNAL ;
    PORT
      LAYER M5 ;
        RECT  107.376 0 107.4 0.192 ;
    END
  END o0[614]
  PIN o0[615]
    DIRECTION OUTPUT ;
    USE SIGNAL ;
    PORT
      LAYER M5 ;
        RECT  107.52 0 107.544 0.192 ;
    END
  END o0[615]
  PIN o0[616]
    DIRECTION OUTPUT ;
    USE SIGNAL ;
    PORT
      LAYER M5 ;
        RECT  107.712 0 107.736 0.192 ;
    END
  END o0[616]
  PIN o0[617]
    DIRECTION OUTPUT ;
    USE SIGNAL ;
    PORT
      LAYER M5 ;
        RECT  107.856 0 107.88 0.192 ;
    END
  END o0[617]
  PIN o0[618]
    DIRECTION OUTPUT ;
    USE SIGNAL ;
    PORT
      LAYER M5 ;
        RECT  108.048 0 108.072 0.192 ;
    END
  END o0[618]
  PIN o0[619]
    DIRECTION OUTPUT ;
    USE SIGNAL ;
    PORT
      LAYER M5 ;
        RECT  108.192 0 108.216 0.192 ;
    END
  END o0[619]
  PIN o0[61]
    DIRECTION OUTPUT ;
    USE SIGNAL ;
    PORT
      LAYER M5 ;
        RECT  14.688 0 14.712 0.192 ;
    END
  END o0[61]
  PIN o0[620]
    DIRECTION OUTPUT ;
    USE SIGNAL ;
    PORT
      LAYER M5 ;
        RECT  108.384 0 108.408 0.192 ;
    END
  END o0[620]
  PIN o0[621]
    DIRECTION OUTPUT ;
    USE SIGNAL ;
    PORT
      LAYER M5 ;
        RECT  108.528 0 108.552 0.192 ;
    END
  END o0[621]
  PIN o0[622]
    DIRECTION OUTPUT ;
    USE SIGNAL ;
    PORT
      LAYER M5 ;
        RECT  108.72 0 108.744 0.192 ;
    END
  END o0[622]
  PIN o0[623]
    DIRECTION OUTPUT ;
    USE SIGNAL ;
    PORT
      LAYER M5 ;
        RECT  108.864 0 108.888 0.192 ;
    END
  END o0[623]
  PIN o0[62]
    DIRECTION OUTPUT ;
    USE SIGNAL ;
    PORT
      LAYER M5 ;
        RECT  14.88 0 14.904 0.192 ;
    END
  END o0[62]
  PIN o0[63]
    DIRECTION OUTPUT ;
    USE SIGNAL ;
    PORT
      LAYER M5 ;
        RECT  15.024 0 15.048 0.192 ;
    END
  END o0[63]
  PIN o0[64]
    DIRECTION OUTPUT ;
    USE SIGNAL ;
    PORT
      LAYER M5 ;
        RECT  15.216 0 15.24 0.192 ;
    END
  END o0[64]
  PIN o0[65]
    DIRECTION OUTPUT ;
    USE SIGNAL ;
    PORT
      LAYER M5 ;
        RECT  15.36 0 15.384 0.192 ;
    END
  END o0[65]
  PIN o0[66]
    DIRECTION OUTPUT ;
    USE SIGNAL ;
    PORT
      LAYER M5 ;
        RECT  15.552 0 15.576 0.192 ;
    END
  END o0[66]
  PIN o0[67]
    DIRECTION OUTPUT ;
    USE SIGNAL ;
    PORT
      LAYER M5 ;
        RECT  15.696 0 15.72 0.192 ;
    END
  END o0[67]
  PIN o0[68]
    DIRECTION OUTPUT ;
    USE SIGNAL ;
    PORT
      LAYER M5 ;
        RECT  15.888 0 15.912 0.192 ;
    END
  END o0[68]
  PIN o0[69]
    DIRECTION OUTPUT ;
    USE SIGNAL ;
    PORT
      LAYER M5 ;
        RECT  16.032 0 16.056 0.192 ;
    END
  END o0[69]
  PIN o0[6]
    DIRECTION OUTPUT ;
    USE SIGNAL ;
    PORT
      LAYER M5 ;
        RECT  5.52 0 5.544 0.192 ;
    END
  END o0[6]
  PIN o0[70]
    DIRECTION OUTPUT ;
    USE SIGNAL ;
    PORT
      LAYER M5 ;
        RECT  16.224 0 16.248 0.192 ;
    END
  END o0[70]
  PIN o0[71]
    DIRECTION OUTPUT ;
    USE SIGNAL ;
    PORT
      LAYER M5 ;
        RECT  16.368 0 16.392 0.192 ;
    END
  END o0[71]
  PIN o0[72]
    DIRECTION OUTPUT ;
    USE SIGNAL ;
    PORT
      LAYER M5 ;
        RECT  16.56 0 16.584 0.192 ;
    END
  END o0[72]
  PIN o0[73]
    DIRECTION OUTPUT ;
    USE SIGNAL ;
    PORT
      LAYER M5 ;
        RECT  16.704 0 16.728 0.192 ;
    END
  END o0[73]
  PIN o0[74]
    DIRECTION OUTPUT ;
    USE SIGNAL ;
    PORT
      LAYER M5 ;
        RECT  16.896 0 16.92 0.192 ;
    END
  END o0[74]
  PIN o0[75]
    DIRECTION OUTPUT ;
    USE SIGNAL ;
    PORT
      LAYER M5 ;
        RECT  17.04 0 17.064 0.192 ;
    END
  END o0[75]
  PIN o0[76]
    DIRECTION OUTPUT ;
    USE SIGNAL ;
    PORT
      LAYER M5 ;
        RECT  17.232 0 17.256 0.192 ;
    END
  END o0[76]
  PIN o0[77]
    DIRECTION OUTPUT ;
    USE SIGNAL ;
    PORT
      LAYER M5 ;
        RECT  17.376 0 17.4 0.192 ;
    END
  END o0[77]
  PIN o0[78]
    DIRECTION OUTPUT ;
    USE SIGNAL ;
    PORT
      LAYER M5 ;
        RECT  17.568 0 17.592 0.192 ;
    END
  END o0[78]
  PIN o0[79]
    DIRECTION OUTPUT ;
    USE SIGNAL ;
    PORT
      LAYER M5 ;
        RECT  17.712 0 17.736 0.192 ;
    END
  END o0[79]
  PIN o0[7]
    DIRECTION OUTPUT ;
    USE SIGNAL ;
    PORT
      LAYER M5 ;
        RECT  5.664 0 5.688 0.192 ;
    END
  END o0[7]
  PIN o0[80]
    DIRECTION OUTPUT ;
    USE SIGNAL ;
    PORT
      LAYER M5 ;
        RECT  17.904 0 17.928 0.192 ;
    END
  END o0[80]
  PIN o0[81]
    DIRECTION OUTPUT ;
    USE SIGNAL ;
    PORT
      LAYER M5 ;
        RECT  18.048 0 18.072 0.192 ;
    END
  END o0[81]
  PIN o0[82]
    DIRECTION OUTPUT ;
    USE SIGNAL ;
    PORT
      LAYER M5 ;
        RECT  18.24 0 18.264 0.192 ;
    END
  END o0[82]
  PIN o0[83]
    DIRECTION OUTPUT ;
    USE SIGNAL ;
    PORT
      LAYER M5 ;
        RECT  18.384 0 18.408 0.192 ;
    END
  END o0[83]
  PIN o0[84]
    DIRECTION OUTPUT ;
    USE SIGNAL ;
    PORT
      LAYER M5 ;
        RECT  18.576 0 18.6 0.192 ;
    END
  END o0[84]
  PIN o0[85]
    DIRECTION OUTPUT ;
    USE SIGNAL ;
    PORT
      LAYER M5 ;
        RECT  18.72 0 18.744 0.192 ;
    END
  END o0[85]
  PIN o0[86]
    DIRECTION OUTPUT ;
    USE SIGNAL ;
    PORT
      LAYER M5 ;
        RECT  18.912 0 18.936 0.192 ;
    END
  END o0[86]
  PIN o0[87]
    DIRECTION OUTPUT ;
    USE SIGNAL ;
    PORT
      LAYER M5 ;
        RECT  19.056 0 19.08 0.192 ;
    END
  END o0[87]
  PIN o0[88]
    DIRECTION OUTPUT ;
    USE SIGNAL ;
    PORT
      LAYER M5 ;
        RECT  19.248 0 19.272 0.192 ;
    END
  END o0[88]
  PIN o0[89]
    DIRECTION OUTPUT ;
    USE SIGNAL ;
    PORT
      LAYER M5 ;
        RECT  19.392 0 19.416 0.192 ;
    END
  END o0[89]
  PIN o0[8]
    DIRECTION OUTPUT ;
    USE SIGNAL ;
    PORT
      LAYER M5 ;
        RECT  5.856 0 5.88 0.192 ;
    END
  END o0[8]
  PIN o0[90]
    DIRECTION OUTPUT ;
    USE SIGNAL ;
    PORT
      LAYER M5 ;
        RECT  19.536 0 19.56 0.192 ;
    END
  END o0[90]
  PIN o0[91]
    DIRECTION OUTPUT ;
    USE SIGNAL ;
    PORT
      LAYER M5 ;
        RECT  19.728 0 19.752 0.192 ;
    END
  END o0[91]
  PIN o0[92]
    DIRECTION OUTPUT ;
    USE SIGNAL ;
    PORT
      LAYER M5 ;
        RECT  19.872 0 19.896 0.192 ;
    END
  END o0[92]
  PIN o0[93]
    DIRECTION OUTPUT ;
    USE SIGNAL ;
    PORT
      LAYER M5 ;
        RECT  20.064 0 20.088 0.192 ;
    END
  END o0[93]
  PIN o0[94]
    DIRECTION OUTPUT ;
    USE SIGNAL ;
    PORT
      LAYER M5 ;
        RECT  20.208 0 20.232 0.192 ;
    END
  END o0[94]
  PIN o0[95]
    DIRECTION OUTPUT ;
    USE SIGNAL ;
    PORT
      LAYER M5 ;
        RECT  20.4 0 20.424 0.192 ;
    END
  END o0[95]
  PIN o0[96]
    DIRECTION OUTPUT ;
    USE SIGNAL ;
    PORT
      LAYER M5 ;
        RECT  20.544 0 20.568 0.192 ;
    END
  END o0[96]
  PIN o0[97]
    DIRECTION OUTPUT ;
    USE SIGNAL ;
    PORT
      LAYER M5 ;
        RECT  20.736 0 20.76 0.192 ;
    END
  END o0[97]
  PIN o0[98]
    DIRECTION OUTPUT ;
    USE SIGNAL ;
    PORT
      LAYER M5 ;
        RECT  20.88 0 20.904 0.192 ;
    END
  END o0[98]
  PIN o0[99]
    DIRECTION OUTPUT ;
    USE SIGNAL ;
    PORT
      LAYER M5 ;
        RECT  21.072 0 21.096 0.192 ;
    END
  END o0[99]
  PIN o0[9]
    DIRECTION OUTPUT ;
    USE SIGNAL ;
    PORT
      LAYER M5 ;
        RECT  6 0 6.024 0.192 ;
    END
  END o0[9]
  PIN o1[0]
    DIRECTION OUTPUT ;
    USE SIGNAL ;
    PORT
      LAYER M5 ;
        RECT  109.248 0 109.272 0.192 ;
    END
  END o1[0]
  PIN o1[100]
    DIRECTION OUTPUT ;
    USE SIGNAL ;
    PORT
      LAYER M5 ;
        RECT  126 0 126.024 0.192 ;
    END
  END o1[100]
  PIN o1[101]
    DIRECTION OUTPUT ;
    USE SIGNAL ;
    PORT
      LAYER M5 ;
        RECT  126.144 0 126.168 0.192 ;
    END
  END o1[101]
  PIN o1[102]
    DIRECTION OUTPUT ;
    USE SIGNAL ;
    PORT
      LAYER M5 ;
        RECT  126.336 0 126.36 0.192 ;
    END
  END o1[102]
  PIN o1[103]
    DIRECTION OUTPUT ;
    USE SIGNAL ;
    PORT
      LAYER M5 ;
        RECT  126.48 0 126.504 0.192 ;
    END
  END o1[103]
  PIN o1[104]
    DIRECTION OUTPUT ;
    USE SIGNAL ;
    PORT
      LAYER M5 ;
        RECT  126.672 0 126.696 0.192 ;
    END
  END o1[104]
  PIN o1[105]
    DIRECTION OUTPUT ;
    USE SIGNAL ;
    PORT
      LAYER M5 ;
        RECT  126.816 0 126.84 0.192 ;
    END
  END o1[105]
  PIN o1[106]
    DIRECTION OUTPUT ;
    USE SIGNAL ;
    PORT
      LAYER M5 ;
        RECT  127.008 0 127.032 0.192 ;
    END
  END o1[106]
  PIN o1[107]
    DIRECTION OUTPUT ;
    USE SIGNAL ;
    PORT
      LAYER M5 ;
        RECT  127.152 0 127.176 0.192 ;
    END
  END o1[107]
  PIN o1[108]
    DIRECTION OUTPUT ;
    USE SIGNAL ;
    PORT
      LAYER M5 ;
        RECT  127.344 0 127.368 0.192 ;
    END
  END o1[108]
  PIN o1[109]
    DIRECTION OUTPUT ;
    USE SIGNAL ;
    PORT
      LAYER M5 ;
        RECT  127.488 0 127.512 0.192 ;
    END
  END o1[109]
  PIN o1[10]
    DIRECTION OUTPUT ;
    USE SIGNAL ;
    PORT
      LAYER M5 ;
        RECT  110.928 0 110.952 0.192 ;
    END
  END o1[10]
  PIN o1[110]
    DIRECTION OUTPUT ;
    USE SIGNAL ;
    PORT
      LAYER M5 ;
        RECT  127.68 0 127.704 0.192 ;
    END
  END o1[110]
  PIN o1[111]
    DIRECTION OUTPUT ;
    USE SIGNAL ;
    PORT
      LAYER M5 ;
        RECT  127.824 0 127.848 0.192 ;
    END
  END o1[111]
  PIN o1[112]
    DIRECTION OUTPUT ;
    USE SIGNAL ;
    PORT
      LAYER M5 ;
        RECT  128.016 0 128.04 0.192 ;
    END
  END o1[112]
  PIN o1[113]
    DIRECTION OUTPUT ;
    USE SIGNAL ;
    PORT
      LAYER M5 ;
        RECT  128.16 0 128.184 0.192 ;
    END
  END o1[113]
  PIN o1[114]
    DIRECTION OUTPUT ;
    USE SIGNAL ;
    PORT
      LAYER M5 ;
        RECT  128.352 0 128.376 0.192 ;
    END
  END o1[114]
  PIN o1[115]
    DIRECTION OUTPUT ;
    USE SIGNAL ;
    PORT
      LAYER M5 ;
        RECT  128.496 0 128.52 0.192 ;
    END
  END o1[115]
  PIN o1[116]
    DIRECTION OUTPUT ;
    USE SIGNAL ;
    PORT
      LAYER M5 ;
        RECT  128.688 0 128.712 0.192 ;
    END
  END o1[116]
  PIN o1[117]
    DIRECTION OUTPUT ;
    USE SIGNAL ;
    PORT
      LAYER M5 ;
        RECT  128.832 0 128.856 0.192 ;
    END
  END o1[117]
  PIN o1[118]
    DIRECTION OUTPUT ;
    USE SIGNAL ;
    PORT
      LAYER M5 ;
        RECT  129.024 0 129.048 0.192 ;
    END
  END o1[118]
  PIN o1[119]
    DIRECTION OUTPUT ;
    USE SIGNAL ;
    PORT
      LAYER M5 ;
        RECT  129.168 0 129.192 0.192 ;
    END
  END o1[119]
  PIN o1[11]
    DIRECTION OUTPUT ;
    USE SIGNAL ;
    PORT
      LAYER M5 ;
        RECT  111.12 0 111.144 0.192 ;
    END
  END o1[11]
  PIN o1[120]
    DIRECTION OUTPUT ;
    USE SIGNAL ;
    PORT
      LAYER M5 ;
        RECT  129.36 0 129.384 0.192 ;
    END
  END o1[120]
  PIN o1[121]
    DIRECTION OUTPUT ;
    USE SIGNAL ;
    PORT
      LAYER M5 ;
        RECT  129.504 0 129.528 0.192 ;
    END
  END o1[121]
  PIN o1[122]
    DIRECTION OUTPUT ;
    USE SIGNAL ;
    PORT
      LAYER M5 ;
        RECT  129.648 0 129.672 0.192 ;
    END
  END o1[122]
  PIN o1[123]
    DIRECTION OUTPUT ;
    USE SIGNAL ;
    PORT
      LAYER M5 ;
        RECT  129.84 0 129.864 0.192 ;
    END
  END o1[123]
  PIN o1[124]
    DIRECTION OUTPUT ;
    USE SIGNAL ;
    PORT
      LAYER M5 ;
        RECT  129.984 0 130.008 0.192 ;
    END
  END o1[124]
  PIN o1[125]
    DIRECTION OUTPUT ;
    USE SIGNAL ;
    PORT
      LAYER M5 ;
        RECT  130.176 0 130.2 0.192 ;
    END
  END o1[125]
  PIN o1[126]
    DIRECTION OUTPUT ;
    USE SIGNAL ;
    PORT
      LAYER M5 ;
        RECT  130.32 0 130.344 0.192 ;
    END
  END o1[126]
  PIN o1[127]
    DIRECTION OUTPUT ;
    USE SIGNAL ;
    PORT
      LAYER M5 ;
        RECT  130.512 0 130.536 0.192 ;
    END
  END o1[127]
  PIN o1[128]
    DIRECTION OUTPUT ;
    USE SIGNAL ;
    PORT
      LAYER M5 ;
        RECT  130.656 0 130.68 0.192 ;
    END
  END o1[128]
  PIN o1[129]
    DIRECTION OUTPUT ;
    USE SIGNAL ;
    PORT
      LAYER M5 ;
        RECT  130.848 0 130.872 0.192 ;
    END
  END o1[129]
  PIN o1[12]
    DIRECTION OUTPUT ;
    USE SIGNAL ;
    PORT
      LAYER M5 ;
        RECT  111.264 0 111.288 0.192 ;
    END
  END o1[12]
  PIN o1[130]
    DIRECTION OUTPUT ;
    USE SIGNAL ;
    PORT
      LAYER M5 ;
        RECT  130.992 0 131.016 0.192 ;
    END
  END o1[130]
  PIN o1[131]
    DIRECTION OUTPUT ;
    USE SIGNAL ;
    PORT
      LAYER M5 ;
        RECT  131.184 0 131.208 0.192 ;
    END
  END o1[131]
  PIN o1[132]
    DIRECTION OUTPUT ;
    USE SIGNAL ;
    PORT
      LAYER M5 ;
        RECT  131.328 0 131.352 0.192 ;
    END
  END o1[132]
  PIN o1[133]
    DIRECTION OUTPUT ;
    USE SIGNAL ;
    PORT
      LAYER M5 ;
        RECT  131.52 0 131.544 0.192 ;
    END
  END o1[133]
  PIN o1[134]
    DIRECTION OUTPUT ;
    USE SIGNAL ;
    PORT
      LAYER M5 ;
        RECT  131.664 0 131.688 0.192 ;
    END
  END o1[134]
  PIN o1[135]
    DIRECTION OUTPUT ;
    USE SIGNAL ;
    PORT
      LAYER M5 ;
        RECT  131.856 0 131.88 0.192 ;
    END
  END o1[135]
  PIN o1[136]
    DIRECTION OUTPUT ;
    USE SIGNAL ;
    PORT
      LAYER M5 ;
        RECT  132 0 132.024 0.192 ;
    END
  END o1[136]
  PIN o1[137]
    DIRECTION OUTPUT ;
    USE SIGNAL ;
    PORT
      LAYER M5 ;
        RECT  132.192 0 132.216 0.192 ;
    END
  END o1[137]
  PIN o1[138]
    DIRECTION OUTPUT ;
    USE SIGNAL ;
    PORT
      LAYER M5 ;
        RECT  132.336 0 132.36 0.192 ;
    END
  END o1[138]
  PIN o1[139]
    DIRECTION OUTPUT ;
    USE SIGNAL ;
    PORT
      LAYER M5 ;
        RECT  132.528 0 132.552 0.192 ;
    END
  END o1[139]
  PIN o1[13]
    DIRECTION OUTPUT ;
    USE SIGNAL ;
    PORT
      LAYER M5 ;
        RECT  111.456 0 111.48 0.192 ;
    END
  END o1[13]
  PIN o1[140]
    DIRECTION OUTPUT ;
    USE SIGNAL ;
    PORT
      LAYER M5 ;
        RECT  132.672 0 132.696 0.192 ;
    END
  END o1[140]
  PIN o1[141]
    DIRECTION OUTPUT ;
    USE SIGNAL ;
    PORT
      LAYER M5 ;
        RECT  132.864 0 132.888 0.192 ;
    END
  END o1[141]
  PIN o1[142]
    DIRECTION OUTPUT ;
    USE SIGNAL ;
    PORT
      LAYER M5 ;
        RECT  133.008 0 133.032 0.192 ;
    END
  END o1[142]
  PIN o1[143]
    DIRECTION OUTPUT ;
    USE SIGNAL ;
    PORT
      LAYER M5 ;
        RECT  133.2 0 133.224 0.192 ;
    END
  END o1[143]
  PIN o1[144]
    DIRECTION OUTPUT ;
    USE SIGNAL ;
    PORT
      LAYER M5 ;
        RECT  133.344 0 133.368 0.192 ;
    END
  END o1[144]
  PIN o1[145]
    DIRECTION OUTPUT ;
    USE SIGNAL ;
    PORT
      LAYER M5 ;
        RECT  133.536 0 133.56 0.192 ;
    END
  END o1[145]
  PIN o1[146]
    DIRECTION OUTPUT ;
    USE SIGNAL ;
    PORT
      LAYER M5 ;
        RECT  133.68 0 133.704 0.192 ;
    END
  END o1[146]
  PIN o1[147]
    DIRECTION OUTPUT ;
    USE SIGNAL ;
    PORT
      LAYER M5 ;
        RECT  133.872 0 133.896 0.192 ;
    END
  END o1[147]
  PIN o1[148]
    DIRECTION OUTPUT ;
    USE SIGNAL ;
    PORT
      LAYER M5 ;
        RECT  134.016 0 134.04 0.192 ;
    END
  END o1[148]
  PIN o1[149]
    DIRECTION OUTPUT ;
    USE SIGNAL ;
    PORT
      LAYER M5 ;
        RECT  134.208 0 134.232 0.192 ;
    END
  END o1[149]
  PIN o1[14]
    DIRECTION OUTPUT ;
    USE SIGNAL ;
    PORT
      LAYER M5 ;
        RECT  111.6 0 111.624 0.192 ;
    END
  END o1[14]
  PIN o1[150]
    DIRECTION OUTPUT ;
    USE SIGNAL ;
    PORT
      LAYER M5 ;
        RECT  134.352 0 134.376 0.192 ;
    END
  END o1[150]
  PIN o1[151]
    DIRECTION OUTPUT ;
    USE SIGNAL ;
    PORT
      LAYER M5 ;
        RECT  134.544 0 134.568 0.192 ;
    END
  END o1[151]
  PIN o1[152]
    DIRECTION OUTPUT ;
    USE SIGNAL ;
    PORT
      LAYER M5 ;
        RECT  134.688 0 134.712 0.192 ;
    END
  END o1[152]
  PIN o1[153]
    DIRECTION OUTPUT ;
    USE SIGNAL ;
    PORT
      LAYER M5 ;
        RECT  134.88 0 134.904 0.192 ;
    END
  END o1[153]
  PIN o1[154]
    DIRECTION OUTPUT ;
    USE SIGNAL ;
    PORT
      LAYER M5 ;
        RECT  135.024 0 135.048 0.192 ;
    END
  END o1[154]
  PIN o1[155]
    DIRECTION OUTPUT ;
    USE SIGNAL ;
    PORT
      LAYER M5 ;
        RECT  135.168 0 135.192 0.192 ;
    END
  END o1[155]
  PIN o1[156]
    DIRECTION OUTPUT ;
    USE SIGNAL ;
    PORT
      LAYER M5 ;
        RECT  135.36 0 135.384 0.192 ;
    END
  END o1[156]
  PIN o1[157]
    DIRECTION OUTPUT ;
    USE SIGNAL ;
    PORT
      LAYER M5 ;
        RECT  135.504 0 135.528 0.192 ;
    END
  END o1[157]
  PIN o1[158]
    DIRECTION OUTPUT ;
    USE SIGNAL ;
    PORT
      LAYER M5 ;
        RECT  135.696 0 135.72 0.192 ;
    END
  END o1[158]
  PIN o1[159]
    DIRECTION OUTPUT ;
    USE SIGNAL ;
    PORT
      LAYER M5 ;
        RECT  135.84 0 135.864 0.192 ;
    END
  END o1[159]
  PIN o1[15]
    DIRECTION OUTPUT ;
    USE SIGNAL ;
    PORT
      LAYER M5 ;
        RECT  111.792 0 111.816 0.192 ;
    END
  END o1[15]
  PIN o1[160]
    DIRECTION OUTPUT ;
    USE SIGNAL ;
    PORT
      LAYER M5 ;
        RECT  136.032 0 136.056 0.192 ;
    END
  END o1[160]
  PIN o1[161]
    DIRECTION OUTPUT ;
    USE SIGNAL ;
    PORT
      LAYER M5 ;
        RECT  136.176 0 136.2 0.192 ;
    END
  END o1[161]
  PIN o1[162]
    DIRECTION OUTPUT ;
    USE SIGNAL ;
    PORT
      LAYER M5 ;
        RECT  136.368 0 136.392 0.192 ;
    END
  END o1[162]
  PIN o1[163]
    DIRECTION OUTPUT ;
    USE SIGNAL ;
    PORT
      LAYER M5 ;
        RECT  136.512 0 136.536 0.192 ;
    END
  END o1[163]
  PIN o1[164]
    DIRECTION OUTPUT ;
    USE SIGNAL ;
    PORT
      LAYER M5 ;
        RECT  136.704 0 136.728 0.192 ;
    END
  END o1[164]
  PIN o1[165]
    DIRECTION OUTPUT ;
    USE SIGNAL ;
    PORT
      LAYER M5 ;
        RECT  136.848 0 136.872 0.192 ;
    END
  END o1[165]
  PIN o1[166]
    DIRECTION OUTPUT ;
    USE SIGNAL ;
    PORT
      LAYER M5 ;
        RECT  137.04 0 137.064 0.192 ;
    END
  END o1[166]
  PIN o1[167]
    DIRECTION OUTPUT ;
    USE SIGNAL ;
    PORT
      LAYER M5 ;
        RECT  137.184 0 137.208 0.192 ;
    END
  END o1[167]
  PIN o1[168]
    DIRECTION OUTPUT ;
    USE SIGNAL ;
    PORT
      LAYER M5 ;
        RECT  137.376 0 137.4 0.192 ;
    END
  END o1[168]
  PIN o1[169]
    DIRECTION OUTPUT ;
    USE SIGNAL ;
    PORT
      LAYER M5 ;
        RECT  137.52 0 137.544 0.192 ;
    END
  END o1[169]
  PIN o1[16]
    DIRECTION OUTPUT ;
    USE SIGNAL ;
    PORT
      LAYER M5 ;
        RECT  111.936 0 111.96 0.192 ;
    END
  END o1[16]
  PIN o1[170]
    DIRECTION OUTPUT ;
    USE SIGNAL ;
    PORT
      LAYER M5 ;
        RECT  137.712 0 137.736 0.192 ;
    END
  END o1[170]
  PIN o1[171]
    DIRECTION OUTPUT ;
    USE SIGNAL ;
    PORT
      LAYER M5 ;
        RECT  137.856 0 137.88 0.192 ;
    END
  END o1[171]
  PIN o1[172]
    DIRECTION OUTPUT ;
    USE SIGNAL ;
    PORT
      LAYER M5 ;
        RECT  138.048 0 138.072 0.192 ;
    END
  END o1[172]
  PIN o1[173]
    DIRECTION OUTPUT ;
    USE SIGNAL ;
    PORT
      LAYER M5 ;
        RECT  138.192 0 138.216 0.192 ;
    END
  END o1[173]
  PIN o1[174]
    DIRECTION OUTPUT ;
    USE SIGNAL ;
    PORT
      LAYER M5 ;
        RECT  138.384 0 138.408 0.192 ;
    END
  END o1[174]
  PIN o1[175]
    DIRECTION OUTPUT ;
    USE SIGNAL ;
    PORT
      LAYER M5 ;
        RECT  138.528 0 138.552 0.192 ;
    END
  END o1[175]
  PIN o1[176]
    DIRECTION OUTPUT ;
    USE SIGNAL ;
    PORT
      LAYER M5 ;
        RECT  138.72 0 138.744 0.192 ;
    END
  END o1[176]
  PIN o1[177]
    DIRECTION OUTPUT ;
    USE SIGNAL ;
    PORT
      LAYER M5 ;
        RECT  138.864 0 138.888 0.192 ;
    END
  END o1[177]
  PIN o1[178]
    DIRECTION OUTPUT ;
    USE SIGNAL ;
    PORT
      LAYER M5 ;
        RECT  139.056 0 139.08 0.192 ;
    END
  END o1[178]
  PIN o1[179]
    DIRECTION OUTPUT ;
    USE SIGNAL ;
    PORT
      LAYER M5 ;
        RECT  139.2 0 139.224 0.192 ;
    END
  END o1[179]
  PIN o1[17]
    DIRECTION OUTPUT ;
    USE SIGNAL ;
    PORT
      LAYER M5 ;
        RECT  112.128 0 112.152 0.192 ;
    END
  END o1[17]
  PIN o1[180]
    DIRECTION OUTPUT ;
    USE SIGNAL ;
    PORT
      LAYER M5 ;
        RECT  139.392 0 139.416 0.192 ;
    END
  END o1[180]
  PIN o1[181]
    DIRECTION OUTPUT ;
    USE SIGNAL ;
    PORT
      LAYER M5 ;
        RECT  139.536 0 139.56 0.192 ;
    END
  END o1[181]
  PIN o1[182]
    DIRECTION OUTPUT ;
    USE SIGNAL ;
    PORT
      LAYER M5 ;
        RECT  139.728 0 139.752 0.192 ;
    END
  END o1[182]
  PIN o1[183]
    DIRECTION OUTPUT ;
    USE SIGNAL ;
    PORT
      LAYER M5 ;
        RECT  139.872 0 139.896 0.192 ;
    END
  END o1[183]
  PIN o1[184]
    DIRECTION OUTPUT ;
    USE SIGNAL ;
    PORT
      LAYER M5 ;
        RECT  140.064 0 140.088 0.192 ;
    END
  END o1[184]
  PIN o1[185]
    DIRECTION OUTPUT ;
    USE SIGNAL ;
    PORT
      LAYER M5 ;
        RECT  140.208 0 140.232 0.192 ;
    END
  END o1[185]
  PIN o1[186]
    DIRECTION OUTPUT ;
    USE SIGNAL ;
    PORT
      LAYER M5 ;
        RECT  140.352 0 140.376 0.192 ;
    END
  END o1[186]
  PIN o1[187]
    DIRECTION OUTPUT ;
    USE SIGNAL ;
    PORT
      LAYER M5 ;
        RECT  140.544 0 140.568 0.192 ;
    END
  END o1[187]
  PIN o1[188]
    DIRECTION OUTPUT ;
    USE SIGNAL ;
    PORT
      LAYER M5 ;
        RECT  140.688 0 140.712 0.192 ;
    END
  END o1[188]
  PIN o1[189]
    DIRECTION OUTPUT ;
    USE SIGNAL ;
    PORT
      LAYER M5 ;
        RECT  140.88 0 140.904 0.192 ;
    END
  END o1[189]
  PIN o1[18]
    DIRECTION OUTPUT ;
    USE SIGNAL ;
    PORT
      LAYER M5 ;
        RECT  112.272 0 112.296 0.192 ;
    END
  END o1[18]
  PIN o1[190]
    DIRECTION OUTPUT ;
    USE SIGNAL ;
    PORT
      LAYER M5 ;
        RECT  141.024 0 141.048 0.192 ;
    END
  END o1[190]
  PIN o1[191]
    DIRECTION OUTPUT ;
    USE SIGNAL ;
    PORT
      LAYER M5 ;
        RECT  141.216 0 141.24 0.192 ;
    END
  END o1[191]
  PIN o1[192]
    DIRECTION OUTPUT ;
    USE SIGNAL ;
    PORT
      LAYER M5 ;
        RECT  141.36 0 141.384 0.192 ;
    END
  END o1[192]
  PIN o1[193]
    DIRECTION OUTPUT ;
    USE SIGNAL ;
    PORT
      LAYER M5 ;
        RECT  141.552 0 141.576 0.192 ;
    END
  END o1[193]
  PIN o1[194]
    DIRECTION OUTPUT ;
    USE SIGNAL ;
    PORT
      LAYER M5 ;
        RECT  141.696 0 141.72 0.192 ;
    END
  END o1[194]
  PIN o1[195]
    DIRECTION OUTPUT ;
    USE SIGNAL ;
    PORT
      LAYER M5 ;
        RECT  141.888 0 141.912 0.192 ;
    END
  END o1[195]
  PIN o1[196]
    DIRECTION OUTPUT ;
    USE SIGNAL ;
    PORT
      LAYER M5 ;
        RECT  142.032 0 142.056 0.192 ;
    END
  END o1[196]
  PIN o1[197]
    DIRECTION OUTPUT ;
    USE SIGNAL ;
    PORT
      LAYER M5 ;
        RECT  142.224 0 142.248 0.192 ;
    END
  END o1[197]
  PIN o1[198]
    DIRECTION OUTPUT ;
    USE SIGNAL ;
    PORT
      LAYER M5 ;
        RECT  142.368 0 142.392 0.192 ;
    END
  END o1[198]
  PIN o1[199]
    DIRECTION OUTPUT ;
    USE SIGNAL ;
    PORT
      LAYER M5 ;
        RECT  142.56 0 142.584 0.192 ;
    END
  END o1[199]
  PIN o1[19]
    DIRECTION OUTPUT ;
    USE SIGNAL ;
    PORT
      LAYER M5 ;
        RECT  112.464 0 112.488 0.192 ;
    END
  END o1[19]
  PIN o1[1]
    DIRECTION OUTPUT ;
    USE SIGNAL ;
    PORT
      LAYER M5 ;
        RECT  109.44 0 109.464 0.192 ;
    END
  END o1[1]
  PIN o1[200]
    DIRECTION OUTPUT ;
    USE SIGNAL ;
    PORT
      LAYER M5 ;
        RECT  142.704 0 142.728 0.192 ;
    END
  END o1[200]
  PIN o1[201]
    DIRECTION OUTPUT ;
    USE SIGNAL ;
    PORT
      LAYER M5 ;
        RECT  142.896 0 142.92 0.192 ;
    END
  END o1[201]
  PIN o1[202]
    DIRECTION OUTPUT ;
    USE SIGNAL ;
    PORT
      LAYER M5 ;
        RECT  143.04 0 143.064 0.192 ;
    END
  END o1[202]
  PIN o1[203]
    DIRECTION OUTPUT ;
    USE SIGNAL ;
    PORT
      LAYER M5 ;
        RECT  143.232 0 143.256 0.192 ;
    END
  END o1[203]
  PIN o1[204]
    DIRECTION OUTPUT ;
    USE SIGNAL ;
    PORT
      LAYER M5 ;
        RECT  143.376 0 143.4 0.192 ;
    END
  END o1[204]
  PIN o1[205]
    DIRECTION OUTPUT ;
    USE SIGNAL ;
    PORT
      LAYER M5 ;
        RECT  143.568 0 143.592 0.192 ;
    END
  END o1[205]
  PIN o1[206]
    DIRECTION OUTPUT ;
    USE SIGNAL ;
    PORT
      LAYER M5 ;
        RECT  143.712 0 143.736 0.192 ;
    END
  END o1[206]
  PIN o1[207]
    DIRECTION OUTPUT ;
    USE SIGNAL ;
    PORT
      LAYER M5 ;
        RECT  143.904 0 143.928 0.192 ;
    END
  END o1[207]
  PIN o1[208]
    DIRECTION OUTPUT ;
    USE SIGNAL ;
    PORT
      LAYER M5 ;
        RECT  144.048 0 144.072 0.192 ;
    END
  END o1[208]
  PIN o1[209]
    DIRECTION OUTPUT ;
    USE SIGNAL ;
    PORT
      LAYER M5 ;
        RECT  144.24 0 144.264 0.192 ;
    END
  END o1[209]
  PIN o1[20]
    DIRECTION OUTPUT ;
    USE SIGNAL ;
    PORT
      LAYER M5 ;
        RECT  112.608 0 112.632 0.192 ;
    END
  END o1[20]
  PIN o1[210]
    DIRECTION OUTPUT ;
    USE SIGNAL ;
    PORT
      LAYER M5 ;
        RECT  144.384 0 144.408 0.192 ;
    END
  END o1[210]
  PIN o1[211]
    DIRECTION OUTPUT ;
    USE SIGNAL ;
    PORT
      LAYER M5 ;
        RECT  144.576 0 144.6 0.192 ;
    END
  END o1[211]
  PIN o1[212]
    DIRECTION OUTPUT ;
    USE SIGNAL ;
    PORT
      LAYER M5 ;
        RECT  144.72 0 144.744 0.192 ;
    END
  END o1[212]
  PIN o1[213]
    DIRECTION OUTPUT ;
    USE SIGNAL ;
    PORT
      LAYER M5 ;
        RECT  144.912 0 144.936 0.192 ;
    END
  END o1[213]
  PIN o1[214]
    DIRECTION OUTPUT ;
    USE SIGNAL ;
    PORT
      LAYER M5 ;
        RECT  145.056 0 145.08 0.192 ;
    END
  END o1[214]
  PIN o1[215]
    DIRECTION OUTPUT ;
    USE SIGNAL ;
    PORT
      LAYER M5 ;
        RECT  145.248 0 145.272 0.192 ;
    END
  END o1[215]
  PIN o1[216]
    DIRECTION OUTPUT ;
    USE SIGNAL ;
    PORT
      LAYER M5 ;
        RECT  145.392 0 145.416 0.192 ;
    END
  END o1[216]
  PIN o1[217]
    DIRECTION OUTPUT ;
    USE SIGNAL ;
    PORT
      LAYER M5 ;
        RECT  145.536 0 145.56 0.192 ;
    END
  END o1[217]
  PIN o1[218]
    DIRECTION OUTPUT ;
    USE SIGNAL ;
    PORT
      LAYER M5 ;
        RECT  145.728 0 145.752 0.192 ;
    END
  END o1[218]
  PIN o1[219]
    DIRECTION OUTPUT ;
    USE SIGNAL ;
    PORT
      LAYER M5 ;
        RECT  145.872 0 145.896 0.192 ;
    END
  END o1[219]
  PIN o1[21]
    DIRECTION OUTPUT ;
    USE SIGNAL ;
    PORT
      LAYER M5 ;
        RECT  112.8 0 112.824 0.192 ;
    END
  END o1[21]
  PIN o1[220]
    DIRECTION OUTPUT ;
    USE SIGNAL ;
    PORT
      LAYER M5 ;
        RECT  146.064 0 146.088 0.192 ;
    END
  END o1[220]
  PIN o1[221]
    DIRECTION OUTPUT ;
    USE SIGNAL ;
    PORT
      LAYER M5 ;
        RECT  146.208 0 146.232 0.192 ;
    END
  END o1[221]
  PIN o1[222]
    DIRECTION OUTPUT ;
    USE SIGNAL ;
    PORT
      LAYER M5 ;
        RECT  146.4 0 146.424 0.192 ;
    END
  END o1[222]
  PIN o1[223]
    DIRECTION OUTPUT ;
    USE SIGNAL ;
    PORT
      LAYER M5 ;
        RECT  146.544 0 146.568 0.192 ;
    END
  END o1[223]
  PIN o1[224]
    DIRECTION OUTPUT ;
    USE SIGNAL ;
    PORT
      LAYER M5 ;
        RECT  146.736 0 146.76 0.192 ;
    END
  END o1[224]
  PIN o1[225]
    DIRECTION OUTPUT ;
    USE SIGNAL ;
    PORT
      LAYER M5 ;
        RECT  146.88 0 146.904 0.192 ;
    END
  END o1[225]
  PIN o1[226]
    DIRECTION OUTPUT ;
    USE SIGNAL ;
    PORT
      LAYER M5 ;
        RECT  147.072 0 147.096 0.192 ;
    END
  END o1[226]
  PIN o1[227]
    DIRECTION OUTPUT ;
    USE SIGNAL ;
    PORT
      LAYER M5 ;
        RECT  147.216 0 147.24 0.192 ;
    END
  END o1[227]
  PIN o1[228]
    DIRECTION OUTPUT ;
    USE SIGNAL ;
    PORT
      LAYER M5 ;
        RECT  147.408 0 147.432 0.192 ;
    END
  END o1[228]
  PIN o1[229]
    DIRECTION OUTPUT ;
    USE SIGNAL ;
    PORT
      LAYER M5 ;
        RECT  147.552 0 147.576 0.192 ;
    END
  END o1[229]
  PIN o1[22]
    DIRECTION OUTPUT ;
    USE SIGNAL ;
    PORT
      LAYER M5 ;
        RECT  112.944 0 112.968 0.192 ;
    END
  END o1[22]
  PIN o1[230]
    DIRECTION OUTPUT ;
    USE SIGNAL ;
    PORT
      LAYER M5 ;
        RECT  147.744 0 147.768 0.192 ;
    END
  END o1[230]
  PIN o1[231]
    DIRECTION OUTPUT ;
    USE SIGNAL ;
    PORT
      LAYER M5 ;
        RECT  147.888 0 147.912 0.192 ;
    END
  END o1[231]
  PIN o1[232]
    DIRECTION OUTPUT ;
    USE SIGNAL ;
    PORT
      LAYER M5 ;
        RECT  148.08 0 148.104 0.192 ;
    END
  END o1[232]
  PIN o1[233]
    DIRECTION OUTPUT ;
    USE SIGNAL ;
    PORT
      LAYER M5 ;
        RECT  148.224 0 148.248 0.192 ;
    END
  END o1[233]
  PIN o1[234]
    DIRECTION OUTPUT ;
    USE SIGNAL ;
    PORT
      LAYER M5 ;
        RECT  148.416 0 148.44 0.192 ;
    END
  END o1[234]
  PIN o1[235]
    DIRECTION OUTPUT ;
    USE SIGNAL ;
    PORT
      LAYER M5 ;
        RECT  148.56 0 148.584 0.192 ;
    END
  END o1[235]
  PIN o1[236]
    DIRECTION OUTPUT ;
    USE SIGNAL ;
    PORT
      LAYER M5 ;
        RECT  148.752 0 148.776 0.192 ;
    END
  END o1[236]
  PIN o1[237]
    DIRECTION OUTPUT ;
    USE SIGNAL ;
    PORT
      LAYER M5 ;
        RECT  148.896 0 148.92 0.192 ;
    END
  END o1[237]
  PIN o1[238]
    DIRECTION OUTPUT ;
    USE SIGNAL ;
    PORT
      LAYER M5 ;
        RECT  149.088 0 149.112 0.192 ;
    END
  END o1[238]
  PIN o1[239]
    DIRECTION OUTPUT ;
    USE SIGNAL ;
    PORT
      LAYER M5 ;
        RECT  149.232 0 149.256 0.192 ;
    END
  END o1[239]
  PIN o1[23]
    DIRECTION OUTPUT ;
    USE SIGNAL ;
    PORT
      LAYER M5 ;
        RECT  113.136 0 113.16 0.192 ;
    END
  END o1[23]
  PIN o1[240]
    DIRECTION OUTPUT ;
    USE SIGNAL ;
    PORT
      LAYER M5 ;
        RECT  149.424 0 149.448 0.192 ;
    END
  END o1[240]
  PIN o1[241]
    DIRECTION OUTPUT ;
    USE SIGNAL ;
    PORT
      LAYER M5 ;
        RECT  149.568 0 149.592 0.192 ;
    END
  END o1[241]
  PIN o1[242]
    DIRECTION OUTPUT ;
    USE SIGNAL ;
    PORT
      LAYER M5 ;
        RECT  149.76 0 149.784 0.192 ;
    END
  END o1[242]
  PIN o1[243]
    DIRECTION OUTPUT ;
    USE SIGNAL ;
    PORT
      LAYER M5 ;
        RECT  149.904 0 149.928 0.192 ;
    END
  END o1[243]
  PIN o1[244]
    DIRECTION OUTPUT ;
    USE SIGNAL ;
    PORT
      LAYER M5 ;
        RECT  150.096 0 150.12 0.192 ;
    END
  END o1[244]
  PIN o1[245]
    DIRECTION OUTPUT ;
    USE SIGNAL ;
    PORT
      LAYER M5 ;
        RECT  150.24 0 150.264 0.192 ;
    END
  END o1[245]
  PIN o1[246]
    DIRECTION OUTPUT ;
    USE SIGNAL ;
    PORT
      LAYER M5 ;
        RECT  150.432 0 150.456 0.192 ;
    END
  END o1[246]
  PIN o1[247]
    DIRECTION OUTPUT ;
    USE SIGNAL ;
    PORT
      LAYER M5 ;
        RECT  150.576 0 150.6 0.192 ;
    END
  END o1[247]
  PIN o1[248]
    DIRECTION OUTPUT ;
    USE SIGNAL ;
    PORT
      LAYER M5 ;
        RECT  150.768 0 150.792 0.192 ;
    END
  END o1[248]
  PIN o1[249]
    DIRECTION OUTPUT ;
    USE SIGNAL ;
    PORT
      LAYER M5 ;
        RECT  150.912 0 150.936 0.192 ;
    END
  END o1[249]
  PIN o1[24]
    DIRECTION OUTPUT ;
    USE SIGNAL ;
    PORT
      LAYER M5 ;
        RECT  113.28 0 113.304 0.192 ;
    END
  END o1[24]
  PIN o1[250]
    DIRECTION OUTPUT ;
    USE SIGNAL ;
    PORT
      LAYER M5 ;
        RECT  151.056 0 151.08 0.192 ;
    END
  END o1[250]
  PIN o1[251]
    DIRECTION OUTPUT ;
    USE SIGNAL ;
    PORT
      LAYER M5 ;
        RECT  151.248 0 151.272 0.192 ;
    END
  END o1[251]
  PIN o1[252]
    DIRECTION OUTPUT ;
    USE SIGNAL ;
    PORT
      LAYER M5 ;
        RECT  151.392 0 151.416 0.192 ;
    END
  END o1[252]
  PIN o1[253]
    DIRECTION OUTPUT ;
    USE SIGNAL ;
    PORT
      LAYER M5 ;
        RECT  151.584 0 151.608 0.192 ;
    END
  END o1[253]
  PIN o1[254]
    DIRECTION OUTPUT ;
    USE SIGNAL ;
    PORT
      LAYER M5 ;
        RECT  151.728 0 151.752 0.192 ;
    END
  END o1[254]
  PIN o1[255]
    DIRECTION OUTPUT ;
    USE SIGNAL ;
    PORT
      LAYER M5 ;
        RECT  151.92 0 151.944 0.192 ;
    END
  END o1[255]
  PIN o1[256]
    DIRECTION OUTPUT ;
    USE SIGNAL ;
    PORT
      LAYER M5 ;
        RECT  152.064 0 152.088 0.192 ;
    END
  END o1[256]
  PIN o1[257]
    DIRECTION OUTPUT ;
    USE SIGNAL ;
    PORT
      LAYER M5 ;
        RECT  152.256 0 152.28 0.192 ;
    END
  END o1[257]
  PIN o1[258]
    DIRECTION OUTPUT ;
    USE SIGNAL ;
    PORT
      LAYER M5 ;
        RECT  152.4 0 152.424 0.192 ;
    END
  END o1[258]
  PIN o1[259]
    DIRECTION OUTPUT ;
    USE SIGNAL ;
    PORT
      LAYER M5 ;
        RECT  152.592 0 152.616 0.192 ;
    END
  END o1[259]
  PIN o1[25]
    DIRECTION OUTPUT ;
    USE SIGNAL ;
    PORT
      LAYER M5 ;
        RECT  113.472 0 113.496 0.192 ;
    END
  END o1[25]
  PIN o1[260]
    DIRECTION OUTPUT ;
    USE SIGNAL ;
    PORT
      LAYER M5 ;
        RECT  152.736 0 152.76 0.192 ;
    END
  END o1[260]
  PIN o1[261]
    DIRECTION OUTPUT ;
    USE SIGNAL ;
    PORT
      LAYER M5 ;
        RECT  152.928 0 152.952 0.192 ;
    END
  END o1[261]
  PIN o1[262]
    DIRECTION OUTPUT ;
    USE SIGNAL ;
    PORT
      LAYER M5 ;
        RECT  153.072 0 153.096 0.192 ;
    END
  END o1[262]
  PIN o1[263]
    DIRECTION OUTPUT ;
    USE SIGNAL ;
    PORT
      LAYER M5 ;
        RECT  153.264 0 153.288 0.192 ;
    END
  END o1[263]
  PIN o1[264]
    DIRECTION OUTPUT ;
    USE SIGNAL ;
    PORT
      LAYER M5 ;
        RECT  153.408 0 153.432 0.192 ;
    END
  END o1[264]
  PIN o1[265]
    DIRECTION OUTPUT ;
    USE SIGNAL ;
    PORT
      LAYER M5 ;
        RECT  153.6 0 153.624 0.192 ;
    END
  END o1[265]
  PIN o1[266]
    DIRECTION OUTPUT ;
    USE SIGNAL ;
    PORT
      LAYER M5 ;
        RECT  153.744 0 153.768 0.192 ;
    END
  END o1[266]
  PIN o1[267]
    DIRECTION OUTPUT ;
    USE SIGNAL ;
    PORT
      LAYER M5 ;
        RECT  153.936 0 153.96 0.192 ;
    END
  END o1[267]
  PIN o1[268]
    DIRECTION OUTPUT ;
    USE SIGNAL ;
    PORT
      LAYER M5 ;
        RECT  154.08 0 154.104 0.192 ;
    END
  END o1[268]
  PIN o1[269]
    DIRECTION OUTPUT ;
    USE SIGNAL ;
    PORT
      LAYER M5 ;
        RECT  154.272 0 154.296 0.192 ;
    END
  END o1[269]
  PIN o1[26]
    DIRECTION OUTPUT ;
    USE SIGNAL ;
    PORT
      LAYER M5 ;
        RECT  113.616 0 113.64 0.192 ;
    END
  END o1[26]
  PIN o1[270]
    DIRECTION OUTPUT ;
    USE SIGNAL ;
    PORT
      LAYER M5 ;
        RECT  154.416 0 154.44 0.192 ;
    END
  END o1[270]
  PIN o1[271]
    DIRECTION OUTPUT ;
    USE SIGNAL ;
    PORT
      LAYER M5 ;
        RECT  154.608 0 154.632 0.192 ;
    END
  END o1[271]
  PIN o1[272]
    DIRECTION OUTPUT ;
    USE SIGNAL ;
    PORT
      LAYER M5 ;
        RECT  154.752 0 154.776 0.192 ;
    END
  END o1[272]
  PIN o1[273]
    DIRECTION OUTPUT ;
    USE SIGNAL ;
    PORT
      LAYER M5 ;
        RECT  154.944 0 154.968 0.192 ;
    END
  END o1[273]
  PIN o1[274]
    DIRECTION OUTPUT ;
    USE SIGNAL ;
    PORT
      LAYER M5 ;
        RECT  155.088 0 155.112 0.192 ;
    END
  END o1[274]
  PIN o1[275]
    DIRECTION OUTPUT ;
    USE SIGNAL ;
    PORT
      LAYER M5 ;
        RECT  155.28 0 155.304 0.192 ;
    END
  END o1[275]
  PIN o1[276]
    DIRECTION OUTPUT ;
    USE SIGNAL ;
    PORT
      LAYER M5 ;
        RECT  155.424 0 155.448 0.192 ;
    END
  END o1[276]
  PIN o1[277]
    DIRECTION OUTPUT ;
    USE SIGNAL ;
    PORT
      LAYER M5 ;
        RECT  155.616 0 155.64 0.192 ;
    END
  END o1[277]
  PIN o1[278]
    DIRECTION OUTPUT ;
    USE SIGNAL ;
    PORT
      LAYER M5 ;
        RECT  155.76 0 155.784 0.192 ;
    END
  END o1[278]
  PIN o1[279]
    DIRECTION OUTPUT ;
    USE SIGNAL ;
    PORT
      LAYER M5 ;
        RECT  155.952 0 155.976 0.192 ;
    END
  END o1[279]
  PIN o1[27]
    DIRECTION OUTPUT ;
    USE SIGNAL ;
    PORT
      LAYER M5 ;
        RECT  113.76 0 113.784 0.192 ;
    END
  END o1[27]
  PIN o1[280]
    DIRECTION OUTPUT ;
    USE SIGNAL ;
    PORT
      LAYER M5 ;
        RECT  156.096 0 156.12 0.192 ;
    END
  END o1[280]
  PIN o1[281]
    DIRECTION OUTPUT ;
    USE SIGNAL ;
    PORT
      LAYER M5 ;
        RECT  156.24 0 156.264 0.192 ;
    END
  END o1[281]
  PIN o1[282]
    DIRECTION OUTPUT ;
    USE SIGNAL ;
    PORT
      LAYER M5 ;
        RECT  156.432 0 156.456 0.192 ;
    END
  END o1[282]
  PIN o1[283]
    DIRECTION OUTPUT ;
    USE SIGNAL ;
    PORT
      LAYER M5 ;
        RECT  156.576 0 156.6 0.192 ;
    END
  END o1[283]
  PIN o1[284]
    DIRECTION OUTPUT ;
    USE SIGNAL ;
    PORT
      LAYER M5 ;
        RECT  156.768 0 156.792 0.192 ;
    END
  END o1[284]
  PIN o1[285]
    DIRECTION OUTPUT ;
    USE SIGNAL ;
    PORT
      LAYER M5 ;
        RECT  156.912 0 156.936 0.192 ;
    END
  END o1[285]
  PIN o1[286]
    DIRECTION OUTPUT ;
    USE SIGNAL ;
    PORT
      LAYER M5 ;
        RECT  157.104 0 157.128 0.192 ;
    END
  END o1[286]
  PIN o1[287]
    DIRECTION OUTPUT ;
    USE SIGNAL ;
    PORT
      LAYER M5 ;
        RECT  157.248 0 157.272 0.192 ;
    END
  END o1[287]
  PIN o1[288]
    DIRECTION OUTPUT ;
    USE SIGNAL ;
    PORT
      LAYER M5 ;
        RECT  157.44 0 157.464 0.192 ;
    END
  END o1[288]
  PIN o1[289]
    DIRECTION OUTPUT ;
    USE SIGNAL ;
    PORT
      LAYER M5 ;
        RECT  157.584 0 157.608 0.192 ;
    END
  END o1[289]
  PIN o1[28]
    DIRECTION OUTPUT ;
    USE SIGNAL ;
    PORT
      LAYER M5 ;
        RECT  113.952 0 113.976 0.192 ;
    END
  END o1[28]
  PIN o1[290]
    DIRECTION OUTPUT ;
    USE SIGNAL ;
    PORT
      LAYER M5 ;
        RECT  157.776 0 157.8 0.192 ;
    END
  END o1[290]
  PIN o1[291]
    DIRECTION OUTPUT ;
    USE SIGNAL ;
    PORT
      LAYER M5 ;
        RECT  157.92 0 157.944 0.192 ;
    END
  END o1[291]
  PIN o1[292]
    DIRECTION OUTPUT ;
    USE SIGNAL ;
    PORT
      LAYER M5 ;
        RECT  158.112 0 158.136 0.192 ;
    END
  END o1[292]
  PIN o1[293]
    DIRECTION OUTPUT ;
    USE SIGNAL ;
    PORT
      LAYER M5 ;
        RECT  158.256 0 158.28 0.192 ;
    END
  END o1[293]
  PIN o1[294]
    DIRECTION OUTPUT ;
    USE SIGNAL ;
    PORT
      LAYER M5 ;
        RECT  158.448 0 158.472 0.192 ;
    END
  END o1[294]
  PIN o1[295]
    DIRECTION OUTPUT ;
    USE SIGNAL ;
    PORT
      LAYER M5 ;
        RECT  158.592 0 158.616 0.192 ;
    END
  END o1[295]
  PIN o1[296]
    DIRECTION OUTPUT ;
    USE SIGNAL ;
    PORT
      LAYER M5 ;
        RECT  158.784 0 158.808 0.192 ;
    END
  END o1[296]
  PIN o1[297]
    DIRECTION OUTPUT ;
    USE SIGNAL ;
    PORT
      LAYER M5 ;
        RECT  158.928 0 158.952 0.192 ;
    END
  END o1[297]
  PIN o1[298]
    DIRECTION OUTPUT ;
    USE SIGNAL ;
    PORT
      LAYER M5 ;
        RECT  159.12 0 159.144 0.192 ;
    END
  END o1[298]
  PIN o1[299]
    DIRECTION OUTPUT ;
    USE SIGNAL ;
    PORT
      LAYER M5 ;
        RECT  159.264 0 159.288 0.192 ;
    END
  END o1[299]
  PIN o1[29]
    DIRECTION OUTPUT ;
    USE SIGNAL ;
    PORT
      LAYER M5 ;
        RECT  114.096 0 114.12 0.192 ;
    END
  END o1[29]
  PIN o1[2]
    DIRECTION OUTPUT ;
    USE SIGNAL ;
    PORT
      LAYER M5 ;
        RECT  109.584 0 109.608 0.192 ;
    END
  END o1[2]
  PIN o1[300]
    DIRECTION OUTPUT ;
    USE SIGNAL ;
    PORT
      LAYER M5 ;
        RECT  159.456 0 159.48 0.192 ;
    END
  END o1[300]
  PIN o1[301]
    DIRECTION OUTPUT ;
    USE SIGNAL ;
    PORT
      LAYER M5 ;
        RECT  159.6 0 159.624 0.192 ;
    END
  END o1[301]
  PIN o1[302]
    DIRECTION OUTPUT ;
    USE SIGNAL ;
    PORT
      LAYER M5 ;
        RECT  159.792 0 159.816 0.192 ;
    END
  END o1[302]
  PIN o1[303]
    DIRECTION OUTPUT ;
    USE SIGNAL ;
    PORT
      LAYER M5 ;
        RECT  159.936 0 159.96 0.192 ;
    END
  END o1[303]
  PIN o1[304]
    DIRECTION OUTPUT ;
    USE SIGNAL ;
    PORT
      LAYER M5 ;
        RECT  160.128 0 160.152 0.192 ;
    END
  END o1[304]
  PIN o1[305]
    DIRECTION OUTPUT ;
    USE SIGNAL ;
    PORT
      LAYER M5 ;
        RECT  160.272 0 160.296 0.192 ;
    END
  END o1[305]
  PIN o1[306]
    DIRECTION OUTPUT ;
    USE SIGNAL ;
    PORT
      LAYER M5 ;
        RECT  160.464 0 160.488 0.192 ;
    END
  END o1[306]
  PIN o1[307]
    DIRECTION OUTPUT ;
    USE SIGNAL ;
    PORT
      LAYER M5 ;
        RECT  160.608 0 160.632 0.192 ;
    END
  END o1[307]
  PIN o1[308]
    DIRECTION OUTPUT ;
    USE SIGNAL ;
    PORT
      LAYER M5 ;
        RECT  160.8 0 160.824 0.192 ;
    END
  END o1[308]
  PIN o1[309]
    DIRECTION OUTPUT ;
    USE SIGNAL ;
    PORT
      LAYER M5 ;
        RECT  160.944 0 160.968 0.192 ;
    END
  END o1[309]
  PIN o1[30]
    DIRECTION OUTPUT ;
    USE SIGNAL ;
    PORT
      LAYER M5 ;
        RECT  114.288 0 114.312 0.192 ;
    END
  END o1[30]
  PIN o1[310]
    DIRECTION OUTPUT ;
    USE SIGNAL ;
    PORT
      LAYER M5 ;
        RECT  161.136 0 161.16 0.192 ;
    END
  END o1[310]
  PIN o1[311]
    DIRECTION OUTPUT ;
    USE SIGNAL ;
    PORT
      LAYER M5 ;
        RECT  161.28 0 161.304 0.192 ;
    END
  END o1[311]
  PIN o1[312]
    DIRECTION OUTPUT ;
    USE SIGNAL ;
    PORT
      LAYER M5 ;
        RECT  161.616 0 161.64 0.192 ;
    END
  END o1[312]
  PIN o1[313]
    DIRECTION OUTPUT ;
    USE SIGNAL ;
    PORT
      LAYER M5 ;
        RECT  161.76 0 161.784 0.192 ;
    END
  END o1[313]
  PIN o1[314]
    DIRECTION OUTPUT ;
    USE SIGNAL ;
    PORT
      LAYER M5 ;
        RECT  161.952 0 161.976 0.192 ;
    END
  END o1[314]
  PIN o1[315]
    DIRECTION OUTPUT ;
    USE SIGNAL ;
    PORT
      LAYER M5 ;
        RECT  162.096 0 162.12 0.192 ;
    END
  END o1[315]
  PIN o1[316]
    DIRECTION OUTPUT ;
    USE SIGNAL ;
    PORT
      LAYER M5 ;
        RECT  162.288 0 162.312 0.192 ;
    END
  END o1[316]
  PIN o1[317]
    DIRECTION OUTPUT ;
    USE SIGNAL ;
    PORT
      LAYER M5 ;
        RECT  162.432 0 162.456 0.192 ;
    END
  END o1[317]
  PIN o1[318]
    DIRECTION OUTPUT ;
    USE SIGNAL ;
    PORT
      LAYER M5 ;
        RECT  162.624 0 162.648 0.192 ;
    END
  END o1[318]
  PIN o1[319]
    DIRECTION OUTPUT ;
    USE SIGNAL ;
    PORT
      LAYER M5 ;
        RECT  162.768 0 162.792 0.192 ;
    END
  END o1[319]
  PIN o1[31]
    DIRECTION OUTPUT ;
    USE SIGNAL ;
    PORT
      LAYER M5 ;
        RECT  114.432 0 114.456 0.192 ;
    END
  END o1[31]
  PIN o1[320]
    DIRECTION OUTPUT ;
    USE SIGNAL ;
    PORT
      LAYER M5 ;
        RECT  162.96 0 162.984 0.192 ;
    END
  END o1[320]
  PIN o1[321]
    DIRECTION OUTPUT ;
    USE SIGNAL ;
    PORT
      LAYER M5 ;
        RECT  163.104 0 163.128 0.192 ;
    END
  END o1[321]
  PIN o1[322]
    DIRECTION OUTPUT ;
    USE SIGNAL ;
    PORT
      LAYER M5 ;
        RECT  163.296 0 163.32 0.192 ;
    END
  END o1[322]
  PIN o1[323]
    DIRECTION OUTPUT ;
    USE SIGNAL ;
    PORT
      LAYER M5 ;
        RECT  163.44 0 163.464 0.192 ;
    END
  END o1[323]
  PIN o1[324]
    DIRECTION OUTPUT ;
    USE SIGNAL ;
    PORT
      LAYER M5 ;
        RECT  163.632 0 163.656 0.192 ;
    END
  END o1[324]
  PIN o1[325]
    DIRECTION OUTPUT ;
    USE SIGNAL ;
    PORT
      LAYER M5 ;
        RECT  163.776 0 163.8 0.192 ;
    END
  END o1[325]
  PIN o1[326]
    DIRECTION OUTPUT ;
    USE SIGNAL ;
    PORT
      LAYER M5 ;
        RECT  163.968 0 163.992 0.192 ;
    END
  END o1[326]
  PIN o1[327]
    DIRECTION OUTPUT ;
    USE SIGNAL ;
    PORT
      LAYER M5 ;
        RECT  164.112 0 164.136 0.192 ;
    END
  END o1[327]
  PIN o1[328]
    DIRECTION OUTPUT ;
    USE SIGNAL ;
    PORT
      LAYER M5 ;
        RECT  164.304 0 164.328 0.192 ;
    END
  END o1[328]
  PIN o1[329]
    DIRECTION OUTPUT ;
    USE SIGNAL ;
    PORT
      LAYER M5 ;
        RECT  164.448 0 164.472 0.192 ;
    END
  END o1[329]
  PIN o1[32]
    DIRECTION OUTPUT ;
    USE SIGNAL ;
    PORT
      LAYER M5 ;
        RECT  114.624 0 114.648 0.192 ;
    END
  END o1[32]
  PIN o1[330]
    DIRECTION OUTPUT ;
    USE SIGNAL ;
    PORT
      LAYER M5 ;
        RECT  164.64 0 164.664 0.192 ;
    END
  END o1[330]
  PIN o1[331]
    DIRECTION OUTPUT ;
    USE SIGNAL ;
    PORT
      LAYER M5 ;
        RECT  164.784 0 164.808 0.192 ;
    END
  END o1[331]
  PIN o1[332]
    DIRECTION OUTPUT ;
    USE SIGNAL ;
    PORT
      LAYER M5 ;
        RECT  164.976 0 165 0.192 ;
    END
  END o1[332]
  PIN o1[333]
    DIRECTION OUTPUT ;
    USE SIGNAL ;
    PORT
      LAYER M5 ;
        RECT  165.12 0 165.144 0.192 ;
    END
  END o1[333]
  PIN o1[334]
    DIRECTION OUTPUT ;
    USE SIGNAL ;
    PORT
      LAYER M5 ;
        RECT  165.312 0 165.336 0.192 ;
    END
  END o1[334]
  PIN o1[335]
    DIRECTION OUTPUT ;
    USE SIGNAL ;
    PORT
      LAYER M5 ;
        RECT  165.456 0 165.48 0.192 ;
    END
  END o1[335]
  PIN o1[336]
    DIRECTION OUTPUT ;
    USE SIGNAL ;
    PORT
      LAYER M5 ;
        RECT  165.648 0 165.672 0.192 ;
    END
  END o1[336]
  PIN o1[337]
    DIRECTION OUTPUT ;
    USE SIGNAL ;
    PORT
      LAYER M5 ;
        RECT  165.792 0 165.816 0.192 ;
    END
  END o1[337]
  PIN o1[338]
    DIRECTION OUTPUT ;
    USE SIGNAL ;
    PORT
      LAYER M5 ;
        RECT  165.984 0 166.008 0.192 ;
    END
  END o1[338]
  PIN o1[339]
    DIRECTION OUTPUT ;
    USE SIGNAL ;
    PORT
      LAYER M5 ;
        RECT  166.128 0 166.152 0.192 ;
    END
  END o1[339]
  PIN o1[33]
    DIRECTION OUTPUT ;
    USE SIGNAL ;
    PORT
      LAYER M5 ;
        RECT  114.768 0 114.792 0.192 ;
    END
  END o1[33]
  PIN o1[340]
    DIRECTION OUTPUT ;
    USE SIGNAL ;
    PORT
      LAYER M5 ;
        RECT  166.32 0 166.344 0.192 ;
    END
  END o1[340]
  PIN o1[341]
    DIRECTION OUTPUT ;
    USE SIGNAL ;
    PORT
      LAYER M5 ;
        RECT  166.464 0 166.488 0.192 ;
    END
  END o1[341]
  PIN o1[342]
    DIRECTION OUTPUT ;
    USE SIGNAL ;
    PORT
      LAYER M5 ;
        RECT  166.656 0 166.68 0.192 ;
    END
  END o1[342]
  PIN o1[343]
    DIRECTION OUTPUT ;
    USE SIGNAL ;
    PORT
      LAYER M5 ;
        RECT  166.8 0 166.824 0.192 ;
    END
  END o1[343]
  PIN o1[344]
    DIRECTION OUTPUT ;
    USE SIGNAL ;
    PORT
      LAYER M5 ;
        RECT  166.944 0 166.968 0.192 ;
    END
  END o1[344]
  PIN o1[345]
    DIRECTION OUTPUT ;
    USE SIGNAL ;
    PORT
      LAYER M5 ;
        RECT  167.136 0 167.16 0.192 ;
    END
  END o1[345]
  PIN o1[346]
    DIRECTION OUTPUT ;
    USE SIGNAL ;
    PORT
      LAYER M5 ;
        RECT  167.28 0 167.304 0.192 ;
    END
  END o1[346]
  PIN o1[347]
    DIRECTION OUTPUT ;
    USE SIGNAL ;
    PORT
      LAYER M5 ;
        RECT  167.472 0 167.496 0.192 ;
    END
  END o1[347]
  PIN o1[348]
    DIRECTION OUTPUT ;
    USE SIGNAL ;
    PORT
      LAYER M5 ;
        RECT  167.616 0 167.64 0.192 ;
    END
  END o1[348]
  PIN o1[349]
    DIRECTION OUTPUT ;
    USE SIGNAL ;
    PORT
      LAYER M5 ;
        RECT  167.808 0 167.832 0.192 ;
    END
  END o1[349]
  PIN o1[34]
    DIRECTION OUTPUT ;
    USE SIGNAL ;
    PORT
      LAYER M5 ;
        RECT  114.96 0 114.984 0.192 ;
    END
  END o1[34]
  PIN o1[350]
    DIRECTION OUTPUT ;
    USE SIGNAL ;
    PORT
      LAYER M5 ;
        RECT  167.952 0 167.976 0.192 ;
    END
  END o1[350]
  PIN o1[351]
    DIRECTION OUTPUT ;
    USE SIGNAL ;
    PORT
      LAYER M5 ;
        RECT  168.144 0 168.168 0.192 ;
    END
  END o1[351]
  PIN o1[352]
    DIRECTION OUTPUT ;
    USE SIGNAL ;
    PORT
      LAYER M5 ;
        RECT  168.288 0 168.312 0.192 ;
    END
  END o1[352]
  PIN o1[353]
    DIRECTION OUTPUT ;
    USE SIGNAL ;
    PORT
      LAYER M5 ;
        RECT  168.48 0 168.504 0.192 ;
    END
  END o1[353]
  PIN o1[354]
    DIRECTION OUTPUT ;
    USE SIGNAL ;
    PORT
      LAYER M5 ;
        RECT  168.624 0 168.648 0.192 ;
    END
  END o1[354]
  PIN o1[355]
    DIRECTION OUTPUT ;
    USE SIGNAL ;
    PORT
      LAYER M5 ;
        RECT  168.816 0 168.84 0.192 ;
    END
  END o1[355]
  PIN o1[356]
    DIRECTION OUTPUT ;
    USE SIGNAL ;
    PORT
      LAYER M5 ;
        RECT  168.96 0 168.984 0.192 ;
    END
  END o1[356]
  PIN o1[357]
    DIRECTION OUTPUT ;
    USE SIGNAL ;
    PORT
      LAYER M5 ;
        RECT  169.152 0 169.176 0.192 ;
    END
  END o1[357]
  PIN o1[358]
    DIRECTION OUTPUT ;
    USE SIGNAL ;
    PORT
      LAYER M5 ;
        RECT  169.296 0 169.32 0.192 ;
    END
  END o1[358]
  PIN o1[359]
    DIRECTION OUTPUT ;
    USE SIGNAL ;
    PORT
      LAYER M5 ;
        RECT  169.488 0 169.512 0.192 ;
    END
  END o1[359]
  PIN o1[35]
    DIRECTION OUTPUT ;
    USE SIGNAL ;
    PORT
      LAYER M5 ;
        RECT  115.104 0 115.128 0.192 ;
    END
  END o1[35]
  PIN o1[360]
    DIRECTION OUTPUT ;
    USE SIGNAL ;
    PORT
      LAYER M5 ;
        RECT  169.632 0 169.656 0.192 ;
    END
  END o1[360]
  PIN o1[361]
    DIRECTION OUTPUT ;
    USE SIGNAL ;
    PORT
      LAYER M5 ;
        RECT  169.824 0 169.848 0.192 ;
    END
  END o1[361]
  PIN o1[362]
    DIRECTION OUTPUT ;
    USE SIGNAL ;
    PORT
      LAYER M5 ;
        RECT  169.968 0 169.992 0.192 ;
    END
  END o1[362]
  PIN o1[363]
    DIRECTION OUTPUT ;
    USE SIGNAL ;
    PORT
      LAYER M5 ;
        RECT  170.16 0 170.184 0.192 ;
    END
  END o1[363]
  PIN o1[364]
    DIRECTION OUTPUT ;
    USE SIGNAL ;
    PORT
      LAYER M5 ;
        RECT  170.304 0 170.328 0.192 ;
    END
  END o1[364]
  PIN o1[365]
    DIRECTION OUTPUT ;
    USE SIGNAL ;
    PORT
      LAYER M5 ;
        RECT  170.496 0 170.52 0.192 ;
    END
  END o1[365]
  PIN o1[366]
    DIRECTION OUTPUT ;
    USE SIGNAL ;
    PORT
      LAYER M5 ;
        RECT  170.64 0 170.664 0.192 ;
    END
  END o1[366]
  PIN o1[367]
    DIRECTION OUTPUT ;
    USE SIGNAL ;
    PORT
      LAYER M5 ;
        RECT  170.832 0 170.856 0.192 ;
    END
  END o1[367]
  PIN o1[368]
    DIRECTION OUTPUT ;
    USE SIGNAL ;
    PORT
      LAYER M5 ;
        RECT  170.976 0 171 0.192 ;
    END
  END o1[368]
  PIN o1[369]
    DIRECTION OUTPUT ;
    USE SIGNAL ;
    PORT
      LAYER M5 ;
        RECT  171.168 0 171.192 0.192 ;
    END
  END o1[369]
  PIN o1[36]
    DIRECTION OUTPUT ;
    USE SIGNAL ;
    PORT
      LAYER M5 ;
        RECT  115.296 0 115.32 0.192 ;
    END
  END o1[36]
  PIN o1[370]
    DIRECTION OUTPUT ;
    USE SIGNAL ;
    PORT
      LAYER M5 ;
        RECT  171.312 0 171.336 0.192 ;
    END
  END o1[370]
  PIN o1[371]
    DIRECTION OUTPUT ;
    USE SIGNAL ;
    PORT
      LAYER M5 ;
        RECT  171.504 0 171.528 0.192 ;
    END
  END o1[371]
  PIN o1[372]
    DIRECTION OUTPUT ;
    USE SIGNAL ;
    PORT
      LAYER M5 ;
        RECT  171.648 0 171.672 0.192 ;
    END
  END o1[372]
  PIN o1[373]
    DIRECTION OUTPUT ;
    USE SIGNAL ;
    PORT
      LAYER M5 ;
        RECT  171.84 0 171.864 0.192 ;
    END
  END o1[373]
  PIN o1[374]
    DIRECTION OUTPUT ;
    USE SIGNAL ;
    PORT
      LAYER M5 ;
        RECT  171.984 0 172.008 0.192 ;
    END
  END o1[374]
  PIN o1[375]
    DIRECTION OUTPUT ;
    USE SIGNAL ;
    PORT
      LAYER M5 ;
        RECT  172.128 0 172.152 0.192 ;
    END
  END o1[375]
  PIN o1[376]
    DIRECTION OUTPUT ;
    USE SIGNAL ;
    PORT
      LAYER M5 ;
        RECT  172.32 0 172.344 0.192 ;
    END
  END o1[376]
  PIN o1[377]
    DIRECTION OUTPUT ;
    USE SIGNAL ;
    PORT
      LAYER M5 ;
        RECT  172.464 0 172.488 0.192 ;
    END
  END o1[377]
  PIN o1[378]
    DIRECTION OUTPUT ;
    USE SIGNAL ;
    PORT
      LAYER M5 ;
        RECT  172.656 0 172.68 0.192 ;
    END
  END o1[378]
  PIN o1[379]
    DIRECTION OUTPUT ;
    USE SIGNAL ;
    PORT
      LAYER M5 ;
        RECT  172.8 0 172.824 0.192 ;
    END
  END o1[379]
  PIN o1[37]
    DIRECTION OUTPUT ;
    USE SIGNAL ;
    PORT
      LAYER M5 ;
        RECT  115.44 0 115.464 0.192 ;
    END
  END o1[37]
  PIN o1[380]
    DIRECTION OUTPUT ;
    USE SIGNAL ;
    PORT
      LAYER M5 ;
        RECT  172.992 0 173.016 0.192 ;
    END
  END o1[380]
  PIN o1[381]
    DIRECTION OUTPUT ;
    USE SIGNAL ;
    PORT
      LAYER M5 ;
        RECT  173.136 0 173.16 0.192 ;
    END
  END o1[381]
  PIN o1[382]
    DIRECTION OUTPUT ;
    USE SIGNAL ;
    PORT
      LAYER M5 ;
        RECT  173.328 0 173.352 0.192 ;
    END
  END o1[382]
  PIN o1[383]
    DIRECTION OUTPUT ;
    USE SIGNAL ;
    PORT
      LAYER M5 ;
        RECT  173.472 0 173.496 0.192 ;
    END
  END o1[383]
  PIN o1[384]
    DIRECTION OUTPUT ;
    USE SIGNAL ;
    PORT
      LAYER M5 ;
        RECT  173.664 0 173.688 0.192 ;
    END
  END o1[384]
  PIN o1[385]
    DIRECTION OUTPUT ;
    USE SIGNAL ;
    PORT
      LAYER M5 ;
        RECT  173.808 0 173.832 0.192 ;
    END
  END o1[385]
  PIN o1[386]
    DIRECTION OUTPUT ;
    USE SIGNAL ;
    PORT
      LAYER M5 ;
        RECT  174 0 174.024 0.192 ;
    END
  END o1[386]
  PIN o1[387]
    DIRECTION OUTPUT ;
    USE SIGNAL ;
    PORT
      LAYER M5 ;
        RECT  174.144 0 174.168 0.192 ;
    END
  END o1[387]
  PIN o1[388]
    DIRECTION OUTPUT ;
    USE SIGNAL ;
    PORT
      LAYER M5 ;
        RECT  174.336 0 174.36 0.192 ;
    END
  END o1[388]
  PIN o1[389]
    DIRECTION OUTPUT ;
    USE SIGNAL ;
    PORT
      LAYER M5 ;
        RECT  174.48 0 174.504 0.192 ;
    END
  END o1[389]
  PIN o1[38]
    DIRECTION OUTPUT ;
    USE SIGNAL ;
    PORT
      LAYER M5 ;
        RECT  115.632 0 115.656 0.192 ;
    END
  END o1[38]
  PIN o1[390]
    DIRECTION OUTPUT ;
    USE SIGNAL ;
    PORT
      LAYER M5 ;
        RECT  174.672 0 174.696 0.192 ;
    END
  END o1[390]
  PIN o1[391]
    DIRECTION OUTPUT ;
    USE SIGNAL ;
    PORT
      LAYER M5 ;
        RECT  174.816 0 174.84 0.192 ;
    END
  END o1[391]
  PIN o1[392]
    DIRECTION OUTPUT ;
    USE SIGNAL ;
    PORT
      LAYER M5 ;
        RECT  175.008 0 175.032 0.192 ;
    END
  END o1[392]
  PIN o1[393]
    DIRECTION OUTPUT ;
    USE SIGNAL ;
    PORT
      LAYER M5 ;
        RECT  175.152 0 175.176 0.192 ;
    END
  END o1[393]
  PIN o1[394]
    DIRECTION OUTPUT ;
    USE SIGNAL ;
    PORT
      LAYER M5 ;
        RECT  175.344 0 175.368 0.192 ;
    END
  END o1[394]
  PIN o1[395]
    DIRECTION OUTPUT ;
    USE SIGNAL ;
    PORT
      LAYER M5 ;
        RECT  175.488 0 175.512 0.192 ;
    END
  END o1[395]
  PIN o1[396]
    DIRECTION OUTPUT ;
    USE SIGNAL ;
    PORT
      LAYER M5 ;
        RECT  175.68 0 175.704 0.192 ;
    END
  END o1[396]
  PIN o1[397]
    DIRECTION OUTPUT ;
    USE SIGNAL ;
    PORT
      LAYER M5 ;
        RECT  175.824 0 175.848 0.192 ;
    END
  END o1[397]
  PIN o1[398]
    DIRECTION OUTPUT ;
    USE SIGNAL ;
    PORT
      LAYER M5 ;
        RECT  176.016 0 176.04 0.192 ;
    END
  END o1[398]
  PIN o1[399]
    DIRECTION OUTPUT ;
    USE SIGNAL ;
    PORT
      LAYER M5 ;
        RECT  176.16 0 176.184 0.192 ;
    END
  END o1[399]
  PIN o1[39]
    DIRECTION OUTPUT ;
    USE SIGNAL ;
    PORT
      LAYER M5 ;
        RECT  115.776 0 115.8 0.192 ;
    END
  END o1[39]
  PIN o1[3]
    DIRECTION OUTPUT ;
    USE SIGNAL ;
    PORT
      LAYER M5 ;
        RECT  109.776 0 109.8 0.192 ;
    END
  END o1[3]
  PIN o1[400]
    DIRECTION OUTPUT ;
    USE SIGNAL ;
    PORT
      LAYER M5 ;
        RECT  176.352 0 176.376 0.192 ;
    END
  END o1[400]
  PIN o1[401]
    DIRECTION OUTPUT ;
    USE SIGNAL ;
    PORT
      LAYER M5 ;
        RECT  176.496 0 176.52 0.192 ;
    END
  END o1[401]
  PIN o1[402]
    DIRECTION OUTPUT ;
    USE SIGNAL ;
    PORT
      LAYER M5 ;
        RECT  176.688 0 176.712 0.192 ;
    END
  END o1[402]
  PIN o1[403]
    DIRECTION OUTPUT ;
    USE SIGNAL ;
    PORT
      LAYER M5 ;
        RECT  176.832 0 176.856 0.192 ;
    END
  END o1[403]
  PIN o1[404]
    DIRECTION OUTPUT ;
    USE SIGNAL ;
    PORT
      LAYER M5 ;
        RECT  177.024 0 177.048 0.192 ;
    END
  END o1[404]
  PIN o1[405]
    DIRECTION OUTPUT ;
    USE SIGNAL ;
    PORT
      LAYER M5 ;
        RECT  177.168 0 177.192 0.192 ;
    END
  END o1[405]
  PIN o1[406]
    DIRECTION OUTPUT ;
    USE SIGNAL ;
    PORT
      LAYER M5 ;
        RECT  177.36 0 177.384 0.192 ;
    END
  END o1[406]
  PIN o1[407]
    DIRECTION OUTPUT ;
    USE SIGNAL ;
    PORT
      LAYER M5 ;
        RECT  177.504 0 177.528 0.192 ;
    END
  END o1[407]
  PIN o1[408]
    DIRECTION OUTPUT ;
    USE SIGNAL ;
    PORT
      LAYER M5 ;
        RECT  177.648 0 177.672 0.192 ;
    END
  END o1[408]
  PIN o1[409]
    DIRECTION OUTPUT ;
    USE SIGNAL ;
    PORT
      LAYER M5 ;
        RECT  177.84 0 177.864 0.192 ;
    END
  END o1[409]
  PIN o1[40]
    DIRECTION OUTPUT ;
    USE SIGNAL ;
    PORT
      LAYER M5 ;
        RECT  115.968 0 115.992 0.192 ;
    END
  END o1[40]
  PIN o1[410]
    DIRECTION OUTPUT ;
    USE SIGNAL ;
    PORT
      LAYER M5 ;
        RECT  177.984 0 178.008 0.192 ;
    END
  END o1[410]
  PIN o1[411]
    DIRECTION OUTPUT ;
    USE SIGNAL ;
    PORT
      LAYER M5 ;
        RECT  178.176 0 178.2 0.192 ;
    END
  END o1[411]
  PIN o1[412]
    DIRECTION OUTPUT ;
    USE SIGNAL ;
    PORT
      LAYER M5 ;
        RECT  178.32 0 178.344 0.192 ;
    END
  END o1[412]
  PIN o1[413]
    DIRECTION OUTPUT ;
    USE SIGNAL ;
    PORT
      LAYER M5 ;
        RECT  178.512 0 178.536 0.192 ;
    END
  END o1[413]
  PIN o1[414]
    DIRECTION OUTPUT ;
    USE SIGNAL ;
    PORT
      LAYER M5 ;
        RECT  178.656 0 178.68 0.192 ;
    END
  END o1[414]
  PIN o1[415]
    DIRECTION OUTPUT ;
    USE SIGNAL ;
    PORT
      LAYER M5 ;
        RECT  178.848 0 178.872 0.192 ;
    END
  END o1[415]
  PIN o1[416]
    DIRECTION OUTPUT ;
    USE SIGNAL ;
    PORT
      LAYER M5 ;
        RECT  178.992 0 179.016 0.192 ;
    END
  END o1[416]
  PIN o1[417]
    DIRECTION OUTPUT ;
    USE SIGNAL ;
    PORT
      LAYER M5 ;
        RECT  179.184 0 179.208 0.192 ;
    END
  END o1[417]
  PIN o1[418]
    DIRECTION OUTPUT ;
    USE SIGNAL ;
    PORT
      LAYER M5 ;
        RECT  179.328 0 179.352 0.192 ;
    END
  END o1[418]
  PIN o1[419]
    DIRECTION OUTPUT ;
    USE SIGNAL ;
    PORT
      LAYER M5 ;
        RECT  179.52 0 179.544 0.192 ;
    END
  END o1[419]
  PIN o1[41]
    DIRECTION OUTPUT ;
    USE SIGNAL ;
    PORT
      LAYER M5 ;
        RECT  116.112 0 116.136 0.192 ;
    END
  END o1[41]
  PIN o1[420]
    DIRECTION OUTPUT ;
    USE SIGNAL ;
    PORT
      LAYER M5 ;
        RECT  179.664 0 179.688 0.192 ;
    END
  END o1[420]
  PIN o1[421]
    DIRECTION OUTPUT ;
    USE SIGNAL ;
    PORT
      LAYER M5 ;
        RECT  179.856 0 179.88 0.192 ;
    END
  END o1[421]
  PIN o1[422]
    DIRECTION OUTPUT ;
    USE SIGNAL ;
    PORT
      LAYER M5 ;
        RECT  180 0 180.024 0.192 ;
    END
  END o1[422]
  PIN o1[423]
    DIRECTION OUTPUT ;
    USE SIGNAL ;
    PORT
      LAYER M5 ;
        RECT  180.192 0 180.216 0.192 ;
    END
  END o1[423]
  PIN o1[424]
    DIRECTION OUTPUT ;
    USE SIGNAL ;
    PORT
      LAYER M5 ;
        RECT  180.336 0 180.36 0.192 ;
    END
  END o1[424]
  PIN o1[425]
    DIRECTION OUTPUT ;
    USE SIGNAL ;
    PORT
      LAYER M5 ;
        RECT  180.528 0 180.552 0.192 ;
    END
  END o1[425]
  PIN o1[426]
    DIRECTION OUTPUT ;
    USE SIGNAL ;
    PORT
      LAYER M5 ;
        RECT  180.672 0 180.696 0.192 ;
    END
  END o1[426]
  PIN o1[427]
    DIRECTION OUTPUT ;
    USE SIGNAL ;
    PORT
      LAYER M5 ;
        RECT  180.864 0 180.888 0.192 ;
    END
  END o1[427]
  PIN o1[428]
    DIRECTION OUTPUT ;
    USE SIGNAL ;
    PORT
      LAYER M5 ;
        RECT  181.008 0 181.032 0.192 ;
    END
  END o1[428]
  PIN o1[429]
    DIRECTION OUTPUT ;
    USE SIGNAL ;
    PORT
      LAYER M5 ;
        RECT  181.2 0 181.224 0.192 ;
    END
  END o1[429]
  PIN o1[42]
    DIRECTION OUTPUT ;
    USE SIGNAL ;
    PORT
      LAYER M5 ;
        RECT  116.304 0 116.328 0.192 ;
    END
  END o1[42]
  PIN o1[430]
    DIRECTION OUTPUT ;
    USE SIGNAL ;
    PORT
      LAYER M5 ;
        RECT  181.344 0 181.368 0.192 ;
    END
  END o1[430]
  PIN o1[431]
    DIRECTION OUTPUT ;
    USE SIGNAL ;
    PORT
      LAYER M5 ;
        RECT  181.536 0 181.56 0.192 ;
    END
  END o1[431]
  PIN o1[432]
    DIRECTION OUTPUT ;
    USE SIGNAL ;
    PORT
      LAYER M5 ;
        RECT  181.68 0 181.704 0.192 ;
    END
  END o1[432]
  PIN o1[433]
    DIRECTION OUTPUT ;
    USE SIGNAL ;
    PORT
      LAYER M5 ;
        RECT  181.872 0 181.896 0.192 ;
    END
  END o1[433]
  PIN o1[434]
    DIRECTION OUTPUT ;
    USE SIGNAL ;
    PORT
      LAYER M5 ;
        RECT  182.016 0 182.04 0.192 ;
    END
  END o1[434]
  PIN o1[435]
    DIRECTION OUTPUT ;
    USE SIGNAL ;
    PORT
      LAYER M5 ;
        RECT  182.208 0 182.232 0.192 ;
    END
  END o1[435]
  PIN o1[436]
    DIRECTION OUTPUT ;
    USE SIGNAL ;
    PORT
      LAYER M5 ;
        RECT  182.352 0 182.376 0.192 ;
    END
  END o1[436]
  PIN o1[437]
    DIRECTION OUTPUT ;
    USE SIGNAL ;
    PORT
      LAYER M5 ;
        RECT  182.544 0 182.568 0.192 ;
    END
  END o1[437]
  PIN o1[438]
    DIRECTION OUTPUT ;
    USE SIGNAL ;
    PORT
      LAYER M5 ;
        RECT  182.688 0 182.712 0.192 ;
    END
  END o1[438]
  PIN o1[439]
    DIRECTION OUTPUT ;
    USE SIGNAL ;
    PORT
      LAYER M5 ;
        RECT  182.832 0 182.856 0.192 ;
    END
  END o1[439]
  PIN o1[43]
    DIRECTION OUTPUT ;
    USE SIGNAL ;
    PORT
      LAYER M5 ;
        RECT  116.448 0 116.472 0.192 ;
    END
  END o1[43]
  PIN o1[440]
    DIRECTION OUTPUT ;
    USE SIGNAL ;
    PORT
      LAYER M5 ;
        RECT  183.024 0 183.048 0.192 ;
    END
  END o1[440]
  PIN o1[441]
    DIRECTION OUTPUT ;
    USE SIGNAL ;
    PORT
      LAYER M5 ;
        RECT  183.168 0 183.192 0.192 ;
    END
  END o1[441]
  PIN o1[442]
    DIRECTION OUTPUT ;
    USE SIGNAL ;
    PORT
      LAYER M5 ;
        RECT  183.36 0 183.384 0.192 ;
    END
  END o1[442]
  PIN o1[443]
    DIRECTION OUTPUT ;
    USE SIGNAL ;
    PORT
      LAYER M5 ;
        RECT  183.504 0 183.528 0.192 ;
    END
  END o1[443]
  PIN o1[444]
    DIRECTION OUTPUT ;
    USE SIGNAL ;
    PORT
      LAYER M5 ;
        RECT  183.696 0 183.72 0.192 ;
    END
  END o1[444]
  PIN o1[445]
    DIRECTION OUTPUT ;
    USE SIGNAL ;
    PORT
      LAYER M5 ;
        RECT  183.84 0 183.864 0.192 ;
    END
  END o1[445]
  PIN o1[446]
    DIRECTION OUTPUT ;
    USE SIGNAL ;
    PORT
      LAYER M5 ;
        RECT  184.032 0 184.056 0.192 ;
    END
  END o1[446]
  PIN o1[447]
    DIRECTION OUTPUT ;
    USE SIGNAL ;
    PORT
      LAYER M5 ;
        RECT  184.176 0 184.2 0.192 ;
    END
  END o1[447]
  PIN o1[448]
    DIRECTION OUTPUT ;
    USE SIGNAL ;
    PORT
      LAYER M5 ;
        RECT  184.368 0 184.392 0.192 ;
    END
  END o1[448]
  PIN o1[449]
    DIRECTION OUTPUT ;
    USE SIGNAL ;
    PORT
      LAYER M5 ;
        RECT  184.512 0 184.536 0.192 ;
    END
  END o1[449]
  PIN o1[44]
    DIRECTION OUTPUT ;
    USE SIGNAL ;
    PORT
      LAYER M5 ;
        RECT  116.64 0 116.664 0.192 ;
    END
  END o1[44]
  PIN o1[450]
    DIRECTION OUTPUT ;
    USE SIGNAL ;
    PORT
      LAYER M5 ;
        RECT  184.704 0 184.728 0.192 ;
    END
  END o1[450]
  PIN o1[451]
    DIRECTION OUTPUT ;
    USE SIGNAL ;
    PORT
      LAYER M5 ;
        RECT  184.848 0 184.872 0.192 ;
    END
  END o1[451]
  PIN o1[452]
    DIRECTION OUTPUT ;
    USE SIGNAL ;
    PORT
      LAYER M5 ;
        RECT  185.04 0 185.064 0.192 ;
    END
  END o1[452]
  PIN o1[453]
    DIRECTION OUTPUT ;
    USE SIGNAL ;
    PORT
      LAYER M5 ;
        RECT  185.184 0 185.208 0.192 ;
    END
  END o1[453]
  PIN o1[454]
    DIRECTION OUTPUT ;
    USE SIGNAL ;
    PORT
      LAYER M5 ;
        RECT  185.376 0 185.4 0.192 ;
    END
  END o1[454]
  PIN o1[455]
    DIRECTION OUTPUT ;
    USE SIGNAL ;
    PORT
      LAYER M5 ;
        RECT  185.52 0 185.544 0.192 ;
    END
  END o1[455]
  PIN o1[456]
    DIRECTION OUTPUT ;
    USE SIGNAL ;
    PORT
      LAYER M5 ;
        RECT  185.712 0 185.736 0.192 ;
    END
  END o1[456]
  PIN o1[457]
    DIRECTION OUTPUT ;
    USE SIGNAL ;
    PORT
      LAYER M5 ;
        RECT  185.856 0 185.88 0.192 ;
    END
  END o1[457]
  PIN o1[458]
    DIRECTION OUTPUT ;
    USE SIGNAL ;
    PORT
      LAYER M5 ;
        RECT  186.048 0 186.072 0.192 ;
    END
  END o1[458]
  PIN o1[459]
    DIRECTION OUTPUT ;
    USE SIGNAL ;
    PORT
      LAYER M5 ;
        RECT  186.192 0 186.216 0.192 ;
    END
  END o1[459]
  PIN o1[45]
    DIRECTION OUTPUT ;
    USE SIGNAL ;
    PORT
      LAYER M5 ;
        RECT  116.784 0 116.808 0.192 ;
    END
  END o1[45]
  PIN o1[460]
    DIRECTION OUTPUT ;
    USE SIGNAL ;
    PORT
      LAYER M5 ;
        RECT  186.384 0 186.408 0.192 ;
    END
  END o1[460]
  PIN o1[461]
    DIRECTION OUTPUT ;
    USE SIGNAL ;
    PORT
      LAYER M5 ;
        RECT  186.528 0 186.552 0.192 ;
    END
  END o1[461]
  PIN o1[462]
    DIRECTION OUTPUT ;
    USE SIGNAL ;
    PORT
      LAYER M5 ;
        RECT  186.72 0 186.744 0.192 ;
    END
  END o1[462]
  PIN o1[463]
    DIRECTION OUTPUT ;
    USE SIGNAL ;
    PORT
      LAYER M5 ;
        RECT  186.864 0 186.888 0.192 ;
    END
  END o1[463]
  PIN o1[464]
    DIRECTION OUTPUT ;
    USE SIGNAL ;
    PORT
      LAYER M5 ;
        RECT  187.056 0 187.08 0.192 ;
    END
  END o1[464]
  PIN o1[465]
    DIRECTION OUTPUT ;
    USE SIGNAL ;
    PORT
      LAYER M5 ;
        RECT  187.2 0 187.224 0.192 ;
    END
  END o1[465]
  PIN o1[466]
    DIRECTION OUTPUT ;
    USE SIGNAL ;
    PORT
      LAYER M5 ;
        RECT  187.392 0 187.416 0.192 ;
    END
  END o1[466]
  PIN o1[467]
    DIRECTION OUTPUT ;
    USE SIGNAL ;
    PORT
      LAYER M5 ;
        RECT  187.536 0 187.56 0.192 ;
    END
  END o1[467]
  PIN o1[468]
    DIRECTION OUTPUT ;
    USE SIGNAL ;
    PORT
      LAYER M5 ;
        RECT  187.728 0 187.752 0.192 ;
    END
  END o1[468]
  PIN o1[469]
    DIRECTION OUTPUT ;
    USE SIGNAL ;
    PORT
      LAYER M5 ;
        RECT  187.872 0 187.896 0.192 ;
    END
  END o1[469]
  PIN o1[46]
    DIRECTION OUTPUT ;
    USE SIGNAL ;
    PORT
      LAYER M5 ;
        RECT  116.976 0 117 0.192 ;
    END
  END o1[46]
  PIN o1[470]
    DIRECTION OUTPUT ;
    USE SIGNAL ;
    PORT
      LAYER M5 ;
        RECT  188.016 0 188.04 0.192 ;
    END
  END o1[470]
  PIN o1[471]
    DIRECTION OUTPUT ;
    USE SIGNAL ;
    PORT
      LAYER M5 ;
        RECT  188.208 0 188.232 0.192 ;
    END
  END o1[471]
  PIN o1[472]
    DIRECTION OUTPUT ;
    USE SIGNAL ;
    PORT
      LAYER M5 ;
        RECT  188.352 0 188.376 0.192 ;
    END
  END o1[472]
  PIN o1[473]
    DIRECTION OUTPUT ;
    USE SIGNAL ;
    PORT
      LAYER M5 ;
        RECT  188.544 0 188.568 0.192 ;
    END
  END o1[473]
  PIN o1[474]
    DIRECTION OUTPUT ;
    USE SIGNAL ;
    PORT
      LAYER M5 ;
        RECT  188.688 0 188.712 0.192 ;
    END
  END o1[474]
  PIN o1[475]
    DIRECTION OUTPUT ;
    USE SIGNAL ;
    PORT
      LAYER M5 ;
        RECT  188.88 0 188.904 0.192 ;
    END
  END o1[475]
  PIN o1[476]
    DIRECTION OUTPUT ;
    USE SIGNAL ;
    PORT
      LAYER M5 ;
        RECT  189.024 0 189.048 0.192 ;
    END
  END o1[476]
  PIN o1[477]
    DIRECTION OUTPUT ;
    USE SIGNAL ;
    PORT
      LAYER M5 ;
        RECT  189.216 0 189.24 0.192 ;
    END
  END o1[477]
  PIN o1[478]
    DIRECTION OUTPUT ;
    USE SIGNAL ;
    PORT
      LAYER M5 ;
        RECT  189.36 0 189.384 0.192 ;
    END
  END o1[478]
  PIN o1[479]
    DIRECTION OUTPUT ;
    USE SIGNAL ;
    PORT
      LAYER M5 ;
        RECT  189.552 0 189.576 0.192 ;
    END
  END o1[479]
  PIN o1[47]
    DIRECTION OUTPUT ;
    USE SIGNAL ;
    PORT
      LAYER M5 ;
        RECT  117.12 0 117.144 0.192 ;
    END
  END o1[47]
  PIN o1[480]
    DIRECTION OUTPUT ;
    USE SIGNAL ;
    PORT
      LAYER M5 ;
        RECT  189.696 0 189.72 0.192 ;
    END
  END o1[480]
  PIN o1[481]
    DIRECTION OUTPUT ;
    USE SIGNAL ;
    PORT
      LAYER M5 ;
        RECT  189.888 0 189.912 0.192 ;
    END
  END o1[481]
  PIN o1[482]
    DIRECTION OUTPUT ;
    USE SIGNAL ;
    PORT
      LAYER M5 ;
        RECT  190.032 0 190.056 0.192 ;
    END
  END o1[482]
  PIN o1[483]
    DIRECTION OUTPUT ;
    USE SIGNAL ;
    PORT
      LAYER M5 ;
        RECT  190.224 0 190.248 0.192 ;
    END
  END o1[483]
  PIN o1[484]
    DIRECTION OUTPUT ;
    USE SIGNAL ;
    PORT
      LAYER M5 ;
        RECT  190.368 0 190.392 0.192 ;
    END
  END o1[484]
  PIN o1[485]
    DIRECTION OUTPUT ;
    USE SIGNAL ;
    PORT
      LAYER M5 ;
        RECT  190.56 0 190.584 0.192 ;
    END
  END o1[485]
  PIN o1[486]
    DIRECTION OUTPUT ;
    USE SIGNAL ;
    PORT
      LAYER M5 ;
        RECT  190.704 0 190.728 0.192 ;
    END
  END o1[486]
  PIN o1[487]
    DIRECTION OUTPUT ;
    USE SIGNAL ;
    PORT
      LAYER M5 ;
        RECT  190.896 0 190.92 0.192 ;
    END
  END o1[487]
  PIN o1[488]
    DIRECTION OUTPUT ;
    USE SIGNAL ;
    PORT
      LAYER M5 ;
        RECT  191.04 0 191.064 0.192 ;
    END
  END o1[488]
  PIN o1[489]
    DIRECTION OUTPUT ;
    USE SIGNAL ;
    PORT
      LAYER M5 ;
        RECT  191.232 0 191.256 0.192 ;
    END
  END o1[489]
  PIN o1[48]
    DIRECTION OUTPUT ;
    USE SIGNAL ;
    PORT
      LAYER M5 ;
        RECT  117.312 0 117.336 0.192 ;
    END
  END o1[48]
  PIN o1[490]
    DIRECTION OUTPUT ;
    USE SIGNAL ;
    PORT
      LAYER M5 ;
        RECT  191.376 0 191.4 0.192 ;
    END
  END o1[490]
  PIN o1[491]
    DIRECTION OUTPUT ;
    USE SIGNAL ;
    PORT
      LAYER M5 ;
        RECT  191.568 0 191.592 0.192 ;
    END
  END o1[491]
  PIN o1[492]
    DIRECTION OUTPUT ;
    USE SIGNAL ;
    PORT
      LAYER M5 ;
        RECT  191.712 0 191.736 0.192 ;
    END
  END o1[492]
  PIN o1[493]
    DIRECTION OUTPUT ;
    USE SIGNAL ;
    PORT
      LAYER M5 ;
        RECT  191.904 0 191.928 0.192 ;
    END
  END o1[493]
  PIN o1[494]
    DIRECTION OUTPUT ;
    USE SIGNAL ;
    PORT
      LAYER M5 ;
        RECT  192.048 0 192.072 0.192 ;
    END
  END o1[494]
  PIN o1[495]
    DIRECTION OUTPUT ;
    USE SIGNAL ;
    PORT
      LAYER M5 ;
        RECT  192.24 0 192.264 0.192 ;
    END
  END o1[495]
  PIN o1[496]
    DIRECTION OUTPUT ;
    USE SIGNAL ;
    PORT
      LAYER M5 ;
        RECT  192.384 0 192.408 0.192 ;
    END
  END o1[496]
  PIN o1[497]
    DIRECTION OUTPUT ;
    USE SIGNAL ;
    PORT
      LAYER M5 ;
        RECT  192.576 0 192.6 0.192 ;
    END
  END o1[497]
  PIN o1[498]
    DIRECTION OUTPUT ;
    USE SIGNAL ;
    PORT
      LAYER M5 ;
        RECT  192.72 0 192.744 0.192 ;
    END
  END o1[498]
  PIN o1[499]
    DIRECTION OUTPUT ;
    USE SIGNAL ;
    PORT
      LAYER M5 ;
        RECT  192.912 0 192.936 0.192 ;
    END
  END o1[499]
  PIN o1[49]
    DIRECTION OUTPUT ;
    USE SIGNAL ;
    PORT
      LAYER M5 ;
        RECT  117.456 0 117.48 0.192 ;
    END
  END o1[49]
  PIN o1[4]
    DIRECTION OUTPUT ;
    USE SIGNAL ;
    PORT
      LAYER M5 ;
        RECT  109.92 0 109.944 0.192 ;
    END
  END o1[4]
  PIN o1[500]
    DIRECTION OUTPUT ;
    USE SIGNAL ;
    PORT
      LAYER M5 ;
        RECT  193.056 0 193.08 0.192 ;
    END
  END o1[500]
  PIN o1[501]
    DIRECTION OUTPUT ;
    USE SIGNAL ;
    PORT
      LAYER M5 ;
        RECT  193.248 0 193.272 0.192 ;
    END
  END o1[501]
  PIN o1[502]
    DIRECTION OUTPUT ;
    USE SIGNAL ;
    PORT
      LAYER M5 ;
        RECT  193.392 0 193.416 0.192 ;
    END
  END o1[502]
  PIN o1[503]
    DIRECTION OUTPUT ;
    USE SIGNAL ;
    PORT
      LAYER M5 ;
        RECT  193.536 0 193.56 0.192 ;
    END
  END o1[503]
  PIN o1[504]
    DIRECTION OUTPUT ;
    USE SIGNAL ;
    PORT
      LAYER M5 ;
        RECT  193.728 0 193.752 0.192 ;
    END
  END o1[504]
  PIN o1[505]
    DIRECTION OUTPUT ;
    USE SIGNAL ;
    PORT
      LAYER M5 ;
        RECT  193.872 0 193.896 0.192 ;
    END
  END o1[505]
  PIN o1[506]
    DIRECTION OUTPUT ;
    USE SIGNAL ;
    PORT
      LAYER M5 ;
        RECT  194.064 0 194.088 0.192 ;
    END
  END o1[506]
  PIN o1[507]
    DIRECTION OUTPUT ;
    USE SIGNAL ;
    PORT
      LAYER M5 ;
        RECT  194.208 0 194.232 0.192 ;
    END
  END o1[507]
  PIN o1[508]
    DIRECTION OUTPUT ;
    USE SIGNAL ;
    PORT
      LAYER M5 ;
        RECT  194.4 0 194.424 0.192 ;
    END
  END o1[508]
  PIN o1[509]
    DIRECTION OUTPUT ;
    USE SIGNAL ;
    PORT
      LAYER M5 ;
        RECT  194.544 0 194.568 0.192 ;
    END
  END o1[509]
  PIN o1[50]
    DIRECTION OUTPUT ;
    USE SIGNAL ;
    PORT
      LAYER M5 ;
        RECT  117.648 0 117.672 0.192 ;
    END
  END o1[50]
  PIN o1[510]
    DIRECTION OUTPUT ;
    USE SIGNAL ;
    PORT
      LAYER M5 ;
        RECT  194.736 0 194.76 0.192 ;
    END
  END o1[510]
  PIN o1[511]
    DIRECTION OUTPUT ;
    USE SIGNAL ;
    PORT
      LAYER M5 ;
        RECT  194.88 0 194.904 0.192 ;
    END
  END o1[511]
  PIN o1[512]
    DIRECTION OUTPUT ;
    USE SIGNAL ;
    PORT
      LAYER M5 ;
        RECT  195.072 0 195.096 0.192 ;
    END
  END o1[512]
  PIN o1[513]
    DIRECTION OUTPUT ;
    USE SIGNAL ;
    PORT
      LAYER M5 ;
        RECT  195.216 0 195.24 0.192 ;
    END
  END o1[513]
  PIN o1[514]
    DIRECTION OUTPUT ;
    USE SIGNAL ;
    PORT
      LAYER M5 ;
        RECT  195.408 0 195.432 0.192 ;
    END
  END o1[514]
  PIN o1[515]
    DIRECTION OUTPUT ;
    USE SIGNAL ;
    PORT
      LAYER M5 ;
        RECT  195.552 0 195.576 0.192 ;
    END
  END o1[515]
  PIN o1[516]
    DIRECTION OUTPUT ;
    USE SIGNAL ;
    PORT
      LAYER M5 ;
        RECT  195.744 0 195.768 0.192 ;
    END
  END o1[516]
  PIN o1[517]
    DIRECTION OUTPUT ;
    USE SIGNAL ;
    PORT
      LAYER M5 ;
        RECT  195.888 0 195.912 0.192 ;
    END
  END o1[517]
  PIN o1[518]
    DIRECTION OUTPUT ;
    USE SIGNAL ;
    PORT
      LAYER M5 ;
        RECT  196.08 0 196.104 0.192 ;
    END
  END o1[518]
  PIN o1[519]
    DIRECTION OUTPUT ;
    USE SIGNAL ;
    PORT
      LAYER M5 ;
        RECT  196.224 0 196.248 0.192 ;
    END
  END o1[519]
  PIN o1[51]
    DIRECTION OUTPUT ;
    USE SIGNAL ;
    PORT
      LAYER M5 ;
        RECT  117.792 0 117.816 0.192 ;
    END
  END o1[51]
  PIN o1[520]
    DIRECTION OUTPUT ;
    USE SIGNAL ;
    PORT
      LAYER M5 ;
        RECT  196.416 0 196.44 0.192 ;
    END
  END o1[520]
  PIN o1[521]
    DIRECTION OUTPUT ;
    USE SIGNAL ;
    PORT
      LAYER M5 ;
        RECT  196.56 0 196.584 0.192 ;
    END
  END o1[521]
  PIN o1[522]
    DIRECTION OUTPUT ;
    USE SIGNAL ;
    PORT
      LAYER M5 ;
        RECT  196.752 0 196.776 0.192 ;
    END
  END o1[522]
  PIN o1[523]
    DIRECTION OUTPUT ;
    USE SIGNAL ;
    PORT
      LAYER M5 ;
        RECT  196.896 0 196.92 0.192 ;
    END
  END o1[523]
  PIN o1[524]
    DIRECTION OUTPUT ;
    USE SIGNAL ;
    PORT
      LAYER M5 ;
        RECT  197.088 0 197.112 0.192 ;
    END
  END o1[524]
  PIN o1[525]
    DIRECTION OUTPUT ;
    USE SIGNAL ;
    PORT
      LAYER M5 ;
        RECT  197.232 0 197.256 0.192 ;
    END
  END o1[525]
  PIN o1[526]
    DIRECTION OUTPUT ;
    USE SIGNAL ;
    PORT
      LAYER M5 ;
        RECT  197.424 0 197.448 0.192 ;
    END
  END o1[526]
  PIN o1[527]
    DIRECTION OUTPUT ;
    USE SIGNAL ;
    PORT
      LAYER M5 ;
        RECT  197.568 0 197.592 0.192 ;
    END
  END o1[527]
  PIN o1[528]
    DIRECTION OUTPUT ;
    USE SIGNAL ;
    PORT
      LAYER M5 ;
        RECT  197.76 0 197.784 0.192 ;
    END
  END o1[528]
  PIN o1[529]
    DIRECTION OUTPUT ;
    USE SIGNAL ;
    PORT
      LAYER M5 ;
        RECT  197.904 0 197.928 0.192 ;
    END
  END o1[529]
  PIN o1[52]
    DIRECTION OUTPUT ;
    USE SIGNAL ;
    PORT
      LAYER M5 ;
        RECT  117.984 0 118.008 0.192 ;
    END
  END o1[52]
  PIN o1[530]
    DIRECTION OUTPUT ;
    USE SIGNAL ;
    PORT
      LAYER M5 ;
        RECT  198.096 0 198.12 0.192 ;
    END
  END o1[530]
  PIN o1[531]
    DIRECTION OUTPUT ;
    USE SIGNAL ;
    PORT
      LAYER M5 ;
        RECT  198.24 0 198.264 0.192 ;
    END
  END o1[531]
  PIN o1[532]
    DIRECTION OUTPUT ;
    USE SIGNAL ;
    PORT
      LAYER M5 ;
        RECT  198.432 0 198.456 0.192 ;
    END
  END o1[532]
  PIN o1[533]
    DIRECTION OUTPUT ;
    USE SIGNAL ;
    PORT
      LAYER M5 ;
        RECT  198.576 0 198.6 0.192 ;
    END
  END o1[533]
  PIN o1[534]
    DIRECTION OUTPUT ;
    USE SIGNAL ;
    PORT
      LAYER M5 ;
        RECT  198.72 0 198.744 0.192 ;
    END
  END o1[534]
  PIN o1[535]
    DIRECTION OUTPUT ;
    USE SIGNAL ;
    PORT
      LAYER M5 ;
        RECT  198.912 0 198.936 0.192 ;
    END
  END o1[535]
  PIN o1[536]
    DIRECTION OUTPUT ;
    USE SIGNAL ;
    PORT
      LAYER M5 ;
        RECT  199.056 0 199.08 0.192 ;
    END
  END o1[536]
  PIN o1[537]
    DIRECTION OUTPUT ;
    USE SIGNAL ;
    PORT
      LAYER M5 ;
        RECT  199.248 0 199.272 0.192 ;
    END
  END o1[537]
  PIN o1[538]
    DIRECTION OUTPUT ;
    USE SIGNAL ;
    PORT
      LAYER M5 ;
        RECT  199.392 0 199.416 0.192 ;
    END
  END o1[538]
  PIN o1[539]
    DIRECTION OUTPUT ;
    USE SIGNAL ;
    PORT
      LAYER M5 ;
        RECT  199.584 0 199.608 0.192 ;
    END
  END o1[539]
  PIN o1[53]
    DIRECTION OUTPUT ;
    USE SIGNAL ;
    PORT
      LAYER M5 ;
        RECT  118.128 0 118.152 0.192 ;
    END
  END o1[53]
  PIN o1[540]
    DIRECTION OUTPUT ;
    USE SIGNAL ;
    PORT
      LAYER M5 ;
        RECT  199.728 0 199.752 0.192 ;
    END
  END o1[540]
  PIN o1[541]
    DIRECTION OUTPUT ;
    USE SIGNAL ;
    PORT
      LAYER M5 ;
        RECT  199.92 0 199.944 0.192 ;
    END
  END o1[541]
  PIN o1[542]
    DIRECTION OUTPUT ;
    USE SIGNAL ;
    PORT
      LAYER M5 ;
        RECT  200.064 0 200.088 0.192 ;
    END
  END o1[542]
  PIN o1[543]
    DIRECTION OUTPUT ;
    USE SIGNAL ;
    PORT
      LAYER M5 ;
        RECT  200.256 0 200.28 0.192 ;
    END
  END o1[543]
  PIN o1[544]
    DIRECTION OUTPUT ;
    USE SIGNAL ;
    PORT
      LAYER M5 ;
        RECT  200.4 0 200.424 0.192 ;
    END
  END o1[544]
  PIN o1[545]
    DIRECTION OUTPUT ;
    USE SIGNAL ;
    PORT
      LAYER M5 ;
        RECT  200.592 0 200.616 0.192 ;
    END
  END o1[545]
  PIN o1[546]
    DIRECTION OUTPUT ;
    USE SIGNAL ;
    PORT
      LAYER M5 ;
        RECT  200.736 0 200.76 0.192 ;
    END
  END o1[546]
  PIN o1[547]
    DIRECTION OUTPUT ;
    USE SIGNAL ;
    PORT
      LAYER M5 ;
        RECT  200.928 0 200.952 0.192 ;
    END
  END o1[547]
  PIN o1[548]
    DIRECTION OUTPUT ;
    USE SIGNAL ;
    PORT
      LAYER M5 ;
        RECT  201.072 0 201.096 0.192 ;
    END
  END o1[548]
  PIN o1[549]
    DIRECTION OUTPUT ;
    USE SIGNAL ;
    PORT
      LAYER M5 ;
        RECT  201.264 0 201.288 0.192 ;
    END
  END o1[549]
  PIN o1[54]
    DIRECTION OUTPUT ;
    USE SIGNAL ;
    PORT
      LAYER M5 ;
        RECT  118.32 0 118.344 0.192 ;
    END
  END o1[54]
  PIN o1[550]
    DIRECTION OUTPUT ;
    USE SIGNAL ;
    PORT
      LAYER M5 ;
        RECT  201.408 0 201.432 0.192 ;
    END
  END o1[550]
  PIN o1[551]
    DIRECTION OUTPUT ;
    USE SIGNAL ;
    PORT
      LAYER M5 ;
        RECT  201.6 0 201.624 0.192 ;
    END
  END o1[551]
  PIN o1[552]
    DIRECTION OUTPUT ;
    USE SIGNAL ;
    PORT
      LAYER M5 ;
        RECT  201.744 0 201.768 0.192 ;
    END
  END o1[552]
  PIN o1[553]
    DIRECTION OUTPUT ;
    USE SIGNAL ;
    PORT
      LAYER M5 ;
        RECT  201.936 0 201.96 0.192 ;
    END
  END o1[553]
  PIN o1[554]
    DIRECTION OUTPUT ;
    USE SIGNAL ;
    PORT
      LAYER M5 ;
        RECT  202.08 0 202.104 0.192 ;
    END
  END o1[554]
  PIN o1[555]
    DIRECTION OUTPUT ;
    USE SIGNAL ;
    PORT
      LAYER M5 ;
        RECT  202.272 0 202.296 0.192 ;
    END
  END o1[555]
  PIN o1[556]
    DIRECTION OUTPUT ;
    USE SIGNAL ;
    PORT
      LAYER M5 ;
        RECT  202.416 0 202.44 0.192 ;
    END
  END o1[556]
  PIN o1[557]
    DIRECTION OUTPUT ;
    USE SIGNAL ;
    PORT
      LAYER M5 ;
        RECT  202.608 0 202.632 0.192 ;
    END
  END o1[557]
  PIN o1[558]
    DIRECTION OUTPUT ;
    USE SIGNAL ;
    PORT
      LAYER M5 ;
        RECT  202.752 0 202.776 0.192 ;
    END
  END o1[558]
  PIN o1[559]
    DIRECTION OUTPUT ;
    USE SIGNAL ;
    PORT
      LAYER M5 ;
        RECT  202.944 0 202.968 0.192 ;
    END
  END o1[559]
  PIN o1[55]
    DIRECTION OUTPUT ;
    USE SIGNAL ;
    PORT
      LAYER M5 ;
        RECT  118.464 0 118.488 0.192 ;
    END
  END o1[55]
  PIN o1[560]
    DIRECTION OUTPUT ;
    USE SIGNAL ;
    PORT
      LAYER M5 ;
        RECT  203.088 0 203.112 0.192 ;
    END
  END o1[560]
  PIN o1[561]
    DIRECTION OUTPUT ;
    USE SIGNAL ;
    PORT
      LAYER M5 ;
        RECT  203.28 0 203.304 0.192 ;
    END
  END o1[561]
  PIN o1[562]
    DIRECTION OUTPUT ;
    USE SIGNAL ;
    PORT
      LAYER M5 ;
        RECT  203.424 0 203.448 0.192 ;
    END
  END o1[562]
  PIN o1[563]
    DIRECTION OUTPUT ;
    USE SIGNAL ;
    PORT
      LAYER M5 ;
        RECT  203.616 0 203.64 0.192 ;
    END
  END o1[563]
  PIN o1[564]
    DIRECTION OUTPUT ;
    USE SIGNAL ;
    PORT
      LAYER M5 ;
        RECT  203.76 0 203.784 0.192 ;
    END
  END o1[564]
  PIN o1[565]
    DIRECTION OUTPUT ;
    USE SIGNAL ;
    PORT
      LAYER M5 ;
        RECT  203.904 0 203.928 0.192 ;
    END
  END o1[565]
  PIN o1[566]
    DIRECTION OUTPUT ;
    USE SIGNAL ;
    PORT
      LAYER M5 ;
        RECT  204.096 0 204.12 0.192 ;
    END
  END o1[566]
  PIN o1[567]
    DIRECTION OUTPUT ;
    USE SIGNAL ;
    PORT
      LAYER M5 ;
        RECT  204.24 0 204.264 0.192 ;
    END
  END o1[567]
  PIN o1[568]
    DIRECTION OUTPUT ;
    USE SIGNAL ;
    PORT
      LAYER M5 ;
        RECT  204.432 0 204.456 0.192 ;
    END
  END o1[568]
  PIN o1[569]
    DIRECTION OUTPUT ;
    USE SIGNAL ;
    PORT
      LAYER M5 ;
        RECT  204.576 0 204.6 0.192 ;
    END
  END o1[569]
  PIN o1[56]
    DIRECTION OUTPUT ;
    USE SIGNAL ;
    PORT
      LAYER M5 ;
        RECT  118.656 0 118.68 0.192 ;
    END
  END o1[56]
  PIN o1[570]
    DIRECTION OUTPUT ;
    USE SIGNAL ;
    PORT
      LAYER M5 ;
        RECT  204.768 0 204.792 0.192 ;
    END
  END o1[570]
  PIN o1[571]
    DIRECTION OUTPUT ;
    USE SIGNAL ;
    PORT
      LAYER M5 ;
        RECT  204.912 0 204.936 0.192 ;
    END
  END o1[571]
  PIN o1[572]
    DIRECTION OUTPUT ;
    USE SIGNAL ;
    PORT
      LAYER M5 ;
        RECT  205.104 0 205.128 0.192 ;
    END
  END o1[572]
  PIN o1[573]
    DIRECTION OUTPUT ;
    USE SIGNAL ;
    PORT
      LAYER M5 ;
        RECT  205.248 0 205.272 0.192 ;
    END
  END o1[573]
  PIN o1[574]
    DIRECTION OUTPUT ;
    USE SIGNAL ;
    PORT
      LAYER M5 ;
        RECT  205.44 0 205.464 0.192 ;
    END
  END o1[574]
  PIN o1[575]
    DIRECTION OUTPUT ;
    USE SIGNAL ;
    PORT
      LAYER M5 ;
        RECT  205.584 0 205.608 0.192 ;
    END
  END o1[575]
  PIN o1[576]
    DIRECTION OUTPUT ;
    USE SIGNAL ;
    PORT
      LAYER M5 ;
        RECT  205.776 0 205.8 0.192 ;
    END
  END o1[576]
  PIN o1[577]
    DIRECTION OUTPUT ;
    USE SIGNAL ;
    PORT
      LAYER M5 ;
        RECT  205.92 0 205.944 0.192 ;
    END
  END o1[577]
  PIN o1[578]
    DIRECTION OUTPUT ;
    USE SIGNAL ;
    PORT
      LAYER M5 ;
        RECT  206.112 0 206.136 0.192 ;
    END
  END o1[578]
  PIN o1[579]
    DIRECTION OUTPUT ;
    USE SIGNAL ;
    PORT
      LAYER M5 ;
        RECT  206.256 0 206.28 0.192 ;
    END
  END o1[579]
  PIN o1[57]
    DIRECTION OUTPUT ;
    USE SIGNAL ;
    PORT
      LAYER M5 ;
        RECT  118.8 0 118.824 0.192 ;
    END
  END o1[57]
  PIN o1[580]
    DIRECTION OUTPUT ;
    USE SIGNAL ;
    PORT
      LAYER M5 ;
        RECT  206.448 0 206.472 0.192 ;
    END
  END o1[580]
  PIN o1[581]
    DIRECTION OUTPUT ;
    USE SIGNAL ;
    PORT
      LAYER M5 ;
        RECT  206.592 0 206.616 0.192 ;
    END
  END o1[581]
  PIN o1[582]
    DIRECTION OUTPUT ;
    USE SIGNAL ;
    PORT
      LAYER M5 ;
        RECT  206.784 0 206.808 0.192 ;
    END
  END o1[582]
  PIN o1[583]
    DIRECTION OUTPUT ;
    USE SIGNAL ;
    PORT
      LAYER M5 ;
        RECT  206.928 0 206.952 0.192 ;
    END
  END o1[583]
  PIN o1[584]
    DIRECTION OUTPUT ;
    USE SIGNAL ;
    PORT
      LAYER M5 ;
        RECT  207.12 0 207.144 0.192 ;
    END
  END o1[584]
  PIN o1[585]
    DIRECTION OUTPUT ;
    USE SIGNAL ;
    PORT
      LAYER M5 ;
        RECT  207.264 0 207.288 0.192 ;
    END
  END o1[585]
  PIN o1[586]
    DIRECTION OUTPUT ;
    USE SIGNAL ;
    PORT
      LAYER M5 ;
        RECT  207.456 0 207.48 0.192 ;
    END
  END o1[586]
  PIN o1[587]
    DIRECTION OUTPUT ;
    USE SIGNAL ;
    PORT
      LAYER M5 ;
        RECT  207.6 0 207.624 0.192 ;
    END
  END o1[587]
  PIN o1[588]
    DIRECTION OUTPUT ;
    USE SIGNAL ;
    PORT
      LAYER M5 ;
        RECT  207.792 0 207.816 0.192 ;
    END
  END o1[588]
  PIN o1[589]
    DIRECTION OUTPUT ;
    USE SIGNAL ;
    PORT
      LAYER M5 ;
        RECT  207.936 0 207.96 0.192 ;
    END
  END o1[589]
  PIN o1[58]
    DIRECTION OUTPUT ;
    USE SIGNAL ;
    PORT
      LAYER M5 ;
        RECT  118.992 0 119.016 0.192 ;
    END
  END o1[58]
  PIN o1[590]
    DIRECTION OUTPUT ;
    USE SIGNAL ;
    PORT
      LAYER M5 ;
        RECT  208.128 0 208.152 0.192 ;
    END
  END o1[590]
  PIN o1[591]
    DIRECTION OUTPUT ;
    USE SIGNAL ;
    PORT
      LAYER M5 ;
        RECT  208.272 0 208.296 0.192 ;
    END
  END o1[591]
  PIN o1[592]
    DIRECTION OUTPUT ;
    USE SIGNAL ;
    PORT
      LAYER M5 ;
        RECT  208.464 0 208.488 0.192 ;
    END
  END o1[592]
  PIN o1[593]
    DIRECTION OUTPUT ;
    USE SIGNAL ;
    PORT
      LAYER M5 ;
        RECT  208.608 0 208.632 0.192 ;
    END
  END o1[593]
  PIN o1[594]
    DIRECTION OUTPUT ;
    USE SIGNAL ;
    PORT
      LAYER M5 ;
        RECT  208.8 0 208.824 0.192 ;
    END
  END o1[594]
  PIN o1[595]
    DIRECTION OUTPUT ;
    USE SIGNAL ;
    PORT
      LAYER M5 ;
        RECT  208.944 0 208.968 0.192 ;
    END
  END o1[595]
  PIN o1[596]
    DIRECTION OUTPUT ;
    USE SIGNAL ;
    PORT
      LAYER M5 ;
        RECT  209.136 0 209.16 0.192 ;
    END
  END o1[596]
  PIN o1[597]
    DIRECTION OUTPUT ;
    USE SIGNAL ;
    PORT
      LAYER M5 ;
        RECT  209.28 0 209.304 0.192 ;
    END
  END o1[597]
  PIN o1[598]
    DIRECTION OUTPUT ;
    USE SIGNAL ;
    PORT
      LAYER M5 ;
        RECT  209.424 0 209.448 0.192 ;
    END
  END o1[598]
  PIN o1[599]
    DIRECTION OUTPUT ;
    USE SIGNAL ;
    PORT
      LAYER M5 ;
        RECT  209.616 0 209.64 0.192 ;
    END
  END o1[599]
  PIN o1[59]
    DIRECTION OUTPUT ;
    USE SIGNAL ;
    PORT
      LAYER M5 ;
        RECT  119.136 0 119.16 0.192 ;
    END
  END o1[59]
  PIN o1[5]
    DIRECTION OUTPUT ;
    USE SIGNAL ;
    PORT
      LAYER M5 ;
        RECT  110.112 0 110.136 0.192 ;
    END
  END o1[5]
  PIN o1[600]
    DIRECTION OUTPUT ;
    USE SIGNAL ;
    PORT
      LAYER M5 ;
        RECT  209.76 0 209.784 0.192 ;
    END
  END o1[600]
  PIN o1[601]
    DIRECTION OUTPUT ;
    USE SIGNAL ;
    PORT
      LAYER M5 ;
        RECT  209.952 0 209.976 0.192 ;
    END
  END o1[601]
  PIN o1[602]
    DIRECTION OUTPUT ;
    USE SIGNAL ;
    PORT
      LAYER M5 ;
        RECT  210.096 0 210.12 0.192 ;
    END
  END o1[602]
  PIN o1[603]
    DIRECTION OUTPUT ;
    USE SIGNAL ;
    PORT
      LAYER M5 ;
        RECT  210.288 0 210.312 0.192 ;
    END
  END o1[603]
  PIN o1[604]
    DIRECTION OUTPUT ;
    USE SIGNAL ;
    PORT
      LAYER M5 ;
        RECT  210.432 0 210.456 0.192 ;
    END
  END o1[604]
  PIN o1[605]
    DIRECTION OUTPUT ;
    USE SIGNAL ;
    PORT
      LAYER M5 ;
        RECT  210.624 0 210.648 0.192 ;
    END
  END o1[605]
  PIN o1[606]
    DIRECTION OUTPUT ;
    USE SIGNAL ;
    PORT
      LAYER M5 ;
        RECT  210.768 0 210.792 0.192 ;
    END
  END o1[606]
  PIN o1[607]
    DIRECTION OUTPUT ;
    USE SIGNAL ;
    PORT
      LAYER M5 ;
        RECT  210.96 0 210.984 0.192 ;
    END
  END o1[607]
  PIN o1[608]
    DIRECTION OUTPUT ;
    USE SIGNAL ;
    PORT
      LAYER M5 ;
        RECT  211.104 0 211.128 0.192 ;
    END
  END o1[608]
  PIN o1[609]
    DIRECTION OUTPUT ;
    USE SIGNAL ;
    PORT
      LAYER M5 ;
        RECT  211.296 0 211.32 0.192 ;
    END
  END o1[609]
  PIN o1[60]
    DIRECTION OUTPUT ;
    USE SIGNAL ;
    PORT
      LAYER M5 ;
        RECT  119.28 0 119.304 0.192 ;
    END
  END o1[60]
  PIN o1[610]
    DIRECTION OUTPUT ;
    USE SIGNAL ;
    PORT
      LAYER M5 ;
        RECT  211.44 0 211.464 0.192 ;
    END
  END o1[610]
  PIN o1[611]
    DIRECTION OUTPUT ;
    USE SIGNAL ;
    PORT
      LAYER M5 ;
        RECT  211.632 0 211.656 0.192 ;
    END
  END o1[611]
  PIN o1[612]
    DIRECTION OUTPUT ;
    USE SIGNAL ;
    PORT
      LAYER M5 ;
        RECT  211.776 0 211.8 0.192 ;
    END
  END o1[612]
  PIN o1[613]
    DIRECTION OUTPUT ;
    USE SIGNAL ;
    PORT
      LAYER M5 ;
        RECT  211.968 0 211.992 0.192 ;
    END
  END o1[613]
  PIN o1[614]
    DIRECTION OUTPUT ;
    USE SIGNAL ;
    PORT
      LAYER M5 ;
        RECT  212.112 0 212.136 0.192 ;
    END
  END o1[614]
  PIN o1[615]
    DIRECTION OUTPUT ;
    USE SIGNAL ;
    PORT
      LAYER M5 ;
        RECT  212.304 0 212.328 0.192 ;
    END
  END o1[615]
  PIN o1[616]
    DIRECTION OUTPUT ;
    USE SIGNAL ;
    PORT
      LAYER M5 ;
        RECT  212.448 0 212.472 0.192 ;
    END
  END o1[616]
  PIN o1[617]
    DIRECTION OUTPUT ;
    USE SIGNAL ;
    PORT
      LAYER M5 ;
        RECT  212.64 0 212.664 0.192 ;
    END
  END o1[617]
  PIN o1[618]
    DIRECTION OUTPUT ;
    USE SIGNAL ;
    PORT
      LAYER M5 ;
        RECT  212.784 0 212.808 0.192 ;
    END
  END o1[618]
  PIN o1[619]
    DIRECTION OUTPUT ;
    USE SIGNAL ;
    PORT
      LAYER M5 ;
        RECT  212.976 0 213 0.192 ;
    END
  END o1[619]
  PIN o1[61]
    DIRECTION OUTPUT ;
    USE SIGNAL ;
    PORT
      LAYER M5 ;
        RECT  119.472 0 119.496 0.192 ;
    END
  END o1[61]
  PIN o1[620]
    DIRECTION OUTPUT ;
    USE SIGNAL ;
    PORT
      LAYER M5 ;
        RECT  213.12 0 213.144 0.192 ;
    END
  END o1[620]
  PIN o1[621]
    DIRECTION OUTPUT ;
    USE SIGNAL ;
    PORT
      LAYER M5 ;
        RECT  213.312 0 213.336 0.192 ;
    END
  END o1[621]
  PIN o1[622]
    DIRECTION OUTPUT ;
    USE SIGNAL ;
    PORT
      LAYER M5 ;
        RECT  213.456 0 213.48 0.192 ;
    END
  END o1[622]
  PIN o1[623]
    DIRECTION OUTPUT ;
    USE SIGNAL ;
    PORT
      LAYER M5 ;
        RECT  213.648 0 213.672 0.192 ;
    END
  END o1[623]
  PIN o1[62]
    DIRECTION OUTPUT ;
    USE SIGNAL ;
    PORT
      LAYER M5 ;
        RECT  119.616 0 119.64 0.192 ;
    END
  END o1[62]
  PIN o1[63]
    DIRECTION OUTPUT ;
    USE SIGNAL ;
    PORT
      LAYER M5 ;
        RECT  119.808 0 119.832 0.192 ;
    END
  END o1[63]
  PIN o1[64]
    DIRECTION OUTPUT ;
    USE SIGNAL ;
    PORT
      LAYER M5 ;
        RECT  119.952 0 119.976 0.192 ;
    END
  END o1[64]
  PIN o1[65]
    DIRECTION OUTPUT ;
    USE SIGNAL ;
    PORT
      LAYER M5 ;
        RECT  120.144 0 120.168 0.192 ;
    END
  END o1[65]
  PIN o1[66]
    DIRECTION OUTPUT ;
    USE SIGNAL ;
    PORT
      LAYER M5 ;
        RECT  120.288 0 120.312 0.192 ;
    END
  END o1[66]
  PIN o1[67]
    DIRECTION OUTPUT ;
    USE SIGNAL ;
    PORT
      LAYER M5 ;
        RECT  120.48 0 120.504 0.192 ;
    END
  END o1[67]
  PIN o1[68]
    DIRECTION OUTPUT ;
    USE SIGNAL ;
    PORT
      LAYER M5 ;
        RECT  120.624 0 120.648 0.192 ;
    END
  END o1[68]
  PIN o1[69]
    DIRECTION OUTPUT ;
    USE SIGNAL ;
    PORT
      LAYER M5 ;
        RECT  120.816 0 120.84 0.192 ;
    END
  END o1[69]
  PIN o1[6]
    DIRECTION OUTPUT ;
    USE SIGNAL ;
    PORT
      LAYER M5 ;
        RECT  110.256 0 110.28 0.192 ;
    END
  END o1[6]
  PIN o1[70]
    DIRECTION OUTPUT ;
    USE SIGNAL ;
    PORT
      LAYER M5 ;
        RECT  120.96 0 120.984 0.192 ;
    END
  END o1[70]
  PIN o1[71]
    DIRECTION OUTPUT ;
    USE SIGNAL ;
    PORT
      LAYER M5 ;
        RECT  121.152 0 121.176 0.192 ;
    END
  END o1[71]
  PIN o1[72]
    DIRECTION OUTPUT ;
    USE SIGNAL ;
    PORT
      LAYER M5 ;
        RECT  121.296 0 121.32 0.192 ;
    END
  END o1[72]
  PIN o1[73]
    DIRECTION OUTPUT ;
    USE SIGNAL ;
    PORT
      LAYER M5 ;
        RECT  121.488 0 121.512 0.192 ;
    END
  END o1[73]
  PIN o1[74]
    DIRECTION OUTPUT ;
    USE SIGNAL ;
    PORT
      LAYER M5 ;
        RECT  121.632 0 121.656 0.192 ;
    END
  END o1[74]
  PIN o1[75]
    DIRECTION OUTPUT ;
    USE SIGNAL ;
    PORT
      LAYER M5 ;
        RECT  121.824 0 121.848 0.192 ;
    END
  END o1[75]
  PIN o1[76]
    DIRECTION OUTPUT ;
    USE SIGNAL ;
    PORT
      LAYER M5 ;
        RECT  121.968 0 121.992 0.192 ;
    END
  END o1[76]
  PIN o1[77]
    DIRECTION OUTPUT ;
    USE SIGNAL ;
    PORT
      LAYER M5 ;
        RECT  122.16 0 122.184 0.192 ;
    END
  END o1[77]
  PIN o1[78]
    DIRECTION OUTPUT ;
    USE SIGNAL ;
    PORT
      LAYER M5 ;
        RECT  122.304 0 122.328 0.192 ;
    END
  END o1[78]
  PIN o1[79]
    DIRECTION OUTPUT ;
    USE SIGNAL ;
    PORT
      LAYER M5 ;
        RECT  122.496 0 122.52 0.192 ;
    END
  END o1[79]
  PIN o1[7]
    DIRECTION OUTPUT ;
    USE SIGNAL ;
    PORT
      LAYER M5 ;
        RECT  110.448 0 110.472 0.192 ;
    END
  END o1[7]
  PIN o1[80]
    DIRECTION OUTPUT ;
    USE SIGNAL ;
    PORT
      LAYER M5 ;
        RECT  122.64 0 122.664 0.192 ;
    END
  END o1[80]
  PIN o1[81]
    DIRECTION OUTPUT ;
    USE SIGNAL ;
    PORT
      LAYER M5 ;
        RECT  122.832 0 122.856 0.192 ;
    END
  END o1[81]
  PIN o1[82]
    DIRECTION OUTPUT ;
    USE SIGNAL ;
    PORT
      LAYER M5 ;
        RECT  122.976 0 123 0.192 ;
    END
  END o1[82]
  PIN o1[83]
    DIRECTION OUTPUT ;
    USE SIGNAL ;
    PORT
      LAYER M5 ;
        RECT  123.168 0 123.192 0.192 ;
    END
  END o1[83]
  PIN o1[84]
    DIRECTION OUTPUT ;
    USE SIGNAL ;
    PORT
      LAYER M5 ;
        RECT  123.312 0 123.336 0.192 ;
    END
  END o1[84]
  PIN o1[85]
    DIRECTION OUTPUT ;
    USE SIGNAL ;
    PORT
      LAYER M5 ;
        RECT  123.504 0 123.528 0.192 ;
    END
  END o1[85]
  PIN o1[86]
    DIRECTION OUTPUT ;
    USE SIGNAL ;
    PORT
      LAYER M5 ;
        RECT  123.648 0 123.672 0.192 ;
    END
  END o1[86]
  PIN o1[87]
    DIRECTION OUTPUT ;
    USE SIGNAL ;
    PORT
      LAYER M5 ;
        RECT  123.84 0 123.864 0.192 ;
    END
  END o1[87]
  PIN o1[88]
    DIRECTION OUTPUT ;
    USE SIGNAL ;
    PORT
      LAYER M5 ;
        RECT  123.984 0 124.008 0.192 ;
    END
  END o1[88]
  PIN o1[89]
    DIRECTION OUTPUT ;
    USE SIGNAL ;
    PORT
      LAYER M5 ;
        RECT  124.176 0 124.2 0.192 ;
    END
  END o1[89]
  PIN o1[8]
    DIRECTION OUTPUT ;
    USE SIGNAL ;
    PORT
      LAYER M5 ;
        RECT  110.592 0 110.616 0.192 ;
    END
  END o1[8]
  PIN o1[90]
    DIRECTION OUTPUT ;
    USE SIGNAL ;
    PORT
      LAYER M5 ;
        RECT  124.32 0 124.344 0.192 ;
    END
  END o1[90]
  PIN o1[91]
    DIRECTION OUTPUT ;
    USE SIGNAL ;
    PORT
      LAYER M5 ;
        RECT  124.464 0 124.488 0.192 ;
    END
  END o1[91]
  PIN o1[92]
    DIRECTION OUTPUT ;
    USE SIGNAL ;
    PORT
      LAYER M5 ;
        RECT  124.656 0 124.68 0.192 ;
    END
  END o1[92]
  PIN o1[93]
    DIRECTION OUTPUT ;
    USE SIGNAL ;
    PORT
      LAYER M5 ;
        RECT  124.8 0 124.824 0.192 ;
    END
  END o1[93]
  PIN o1[94]
    DIRECTION OUTPUT ;
    USE SIGNAL ;
    PORT
      LAYER M5 ;
        RECT  124.992 0 125.016 0.192 ;
    END
  END o1[94]
  PIN o1[95]
    DIRECTION OUTPUT ;
    USE SIGNAL ;
    PORT
      LAYER M5 ;
        RECT  125.136 0 125.16 0.192 ;
    END
  END o1[95]
  PIN o1[96]
    DIRECTION OUTPUT ;
    USE SIGNAL ;
    PORT
      LAYER M5 ;
        RECT  125.328 0 125.352 0.192 ;
    END
  END o1[96]
  PIN o1[97]
    DIRECTION OUTPUT ;
    USE SIGNAL ;
    PORT
      LAYER M5 ;
        RECT  125.472 0 125.496 0.192 ;
    END
  END o1[97]
  PIN o1[98]
    DIRECTION OUTPUT ;
    USE SIGNAL ;
    PORT
      LAYER M5 ;
        RECT  125.664 0 125.688 0.192 ;
    END
  END o1[98]
  PIN o1[99]
    DIRECTION OUTPUT ;
    USE SIGNAL ;
    PORT
      LAYER M5 ;
        RECT  125.808 0 125.832 0.192 ;
    END
  END o1[99]
  PIN o1[9]
    DIRECTION OUTPUT ;
    USE SIGNAL ;
    PORT
      LAYER M5 ;
        RECT  110.784 0 110.808 0.192 ;
    END
  END o1[9]
  PIN rs
    DIRECTION INPUT ;
    USE SIGNAL ;
    PORT
      LAYER M4 ;
        RECT  0 12.96 0.192 12.984 ;
    END
  END rs
  PIN VDD
    DIRECTION INOUT ;
    USE POWER ;
    PORT
      LAYER M5 ;
        RECT  215.892 2.151 216.012 23.769 ;
        RECT  213.192 2.151 213.312 23.769 ;
        RECT  210.492 2.151 210.612 23.769 ;
        RECT  207.792 2.151 207.912 23.769 ;
        RECT  205.092 2.151 205.212 23.769 ;
        RECT  202.392 2.151 202.512 23.769 ;
        RECT  199.692 2.151 199.812 23.769 ;
        RECT  196.992 2.151 197.112 23.769 ;
        RECT  194.292 2.151 194.412 23.769 ;
        RECT  191.592 2.151 191.712 23.769 ;
        RECT  188.892 2.151 189.012 23.769 ;
        RECT  186.192 2.151 186.312 23.769 ;
        RECT  183.492 2.151 183.612 23.769 ;
        RECT  180.792 2.151 180.912 23.769 ;
        RECT  178.092 2.151 178.212 23.769 ;
        RECT  175.392 2.151 175.512 23.769 ;
        RECT  172.692 2.151 172.812 23.769 ;
        RECT  169.992 2.151 170.112 23.769 ;
        RECT  167.292 2.151 167.412 23.769 ;
        RECT  164.592 2.151 164.712 23.769 ;
        RECT  161.892 2.151 162.012 23.769 ;
        RECT  159.192 2.151 159.312 23.769 ;
        RECT  156.492 2.151 156.612 23.769 ;
        RECT  153.792 2.151 153.912 23.769 ;
        RECT  151.092 2.151 151.212 23.769 ;
        RECT  148.392 2.151 148.512 23.769 ;
        RECT  145.692 2.151 145.812 23.769 ;
        RECT  142.992 2.151 143.112 23.769 ;
        RECT  140.292 2.151 140.412 23.769 ;
        RECT  137.592 2.151 137.712 23.769 ;
        RECT  134.892 2.151 135.012 23.769 ;
        RECT  132.192 2.151 132.312 23.769 ;
        RECT  129.492 2.151 129.612 23.769 ;
        RECT  126.792 2.151 126.912 23.769 ;
        RECT  124.092 2.151 124.212 23.769 ;
        RECT  121.392 2.151 121.512 23.769 ;
        RECT  118.692 2.151 118.812 23.769 ;
        RECT  115.992 2.151 116.112 23.769 ;
        RECT  113.292 2.151 113.412 23.769 ;
        RECT  110.592 2.151 110.712 23.769 ;
        RECT  107.892 2.151 108.012 23.769 ;
        RECT  105.192 2.151 105.312 23.769 ;
        RECT  102.492 2.151 102.612 23.769 ;
        RECT  99.792 2.151 99.912 23.769 ;
        RECT  97.092 2.151 97.212 23.769 ;
        RECT  94.392 2.151 94.512 23.769 ;
        RECT  91.692 2.151 91.812 23.769 ;
        RECT  88.992 2.151 89.112 23.769 ;
        RECT  86.292 2.151 86.412 23.769 ;
        RECT  83.592 2.151 83.712 23.769 ;
        RECT  80.892 2.151 81.012 23.769 ;
        RECT  78.192 2.151 78.312 23.769 ;
        RECT  75.492 2.151 75.612 23.769 ;
        RECT  72.792 2.151 72.912 23.769 ;
        RECT  70.092 2.151 70.212 23.769 ;
        RECT  67.392 2.151 67.512 23.769 ;
        RECT  64.692 2.151 64.812 23.769 ;
        RECT  61.992 2.151 62.112 23.769 ;
        RECT  59.292 2.151 59.412 23.769 ;
        RECT  56.592 2.151 56.712 23.769 ;
        RECT  53.892 2.151 54.012 23.769 ;
        RECT  51.192 2.151 51.312 23.769 ;
        RECT  48.492 2.151 48.612 23.769 ;
        RECT  45.792 2.151 45.912 23.769 ;
        RECT  43.092 2.151 43.212 23.769 ;
        RECT  40.392 2.151 40.512 23.769 ;
        RECT  37.692 2.151 37.812 23.769 ;
        RECT  34.992 2.151 35.112 23.769 ;
        RECT  32.292 2.151 32.412 23.769 ;
        RECT  29.592 2.151 29.712 23.769 ;
        RECT  26.892 2.151 27.012 23.769 ;
        RECT  24.192 2.151 24.312 23.769 ;
        RECT  21.492 2.151 21.612 23.769 ;
        RECT  18.792 2.151 18.912 23.769 ;
        RECT  16.092 2.151 16.212 23.769 ;
        RECT  13.392 2.151 13.512 23.769 ;
        RECT  10.692 2.151 10.812 23.769 ;
        RECT  7.992 2.151 8.112 23.769 ;
        RECT  5.292 2.151 5.412 23.769 ;
        RECT  2.592 2.151 2.712 23.769 ;
    END
  END VDD
  PIN VSS
    DIRECTION INOUT ;
    USE GROUND ;
    PORT
      LAYER M5 ;
        RECT  215.7 2.137 215.82 23.783 ;
        RECT  213 2.137 213.12 23.783 ;
        RECT  210.3 2.137 210.42 23.783 ;
        RECT  207.6 2.137 207.72 23.783 ;
        RECT  204.9 2.137 205.02 23.783 ;
        RECT  202.2 2.137 202.32 23.783 ;
        RECT  199.5 2.137 199.62 23.783 ;
        RECT  196.8 2.137 196.92 23.783 ;
        RECT  194.1 2.137 194.22 23.783 ;
        RECT  191.4 2.137 191.52 23.783 ;
        RECT  188.7 2.137 188.82 23.783 ;
        RECT  186 2.137 186.12 23.783 ;
        RECT  183.3 2.137 183.42 23.783 ;
        RECT  180.6 2.137 180.72 23.783 ;
        RECT  177.9 2.137 178.02 23.783 ;
        RECT  175.2 2.137 175.32 23.783 ;
        RECT  172.5 2.137 172.62 23.783 ;
        RECT  169.8 2.137 169.92 23.783 ;
        RECT  167.1 2.137 167.22 23.783 ;
        RECT  164.4 2.137 164.52 23.783 ;
        RECT  161.7 2.137 161.82 23.783 ;
        RECT  159 2.137 159.12 23.783 ;
        RECT  156.3 2.137 156.42 23.783 ;
        RECT  153.6 2.137 153.72 23.783 ;
        RECT  150.9 2.137 151.02 23.783 ;
        RECT  148.2 2.137 148.32 23.783 ;
        RECT  145.5 2.137 145.62 23.783 ;
        RECT  142.8 2.137 142.92 23.783 ;
        RECT  140.1 2.137 140.22 23.783 ;
        RECT  137.4 2.137 137.52 23.783 ;
        RECT  134.7 2.137 134.82 23.783 ;
        RECT  132 2.137 132.12 23.783 ;
        RECT  129.3 2.137 129.42 23.783 ;
        RECT  126.6 2.137 126.72 23.783 ;
        RECT  123.9 2.137 124.02 23.783 ;
        RECT  121.2 2.137 121.32 23.783 ;
        RECT  118.5 2.137 118.62 23.783 ;
        RECT  115.8 2.137 115.92 23.783 ;
        RECT  113.1 2.137 113.22 23.783 ;
        RECT  110.4 2.137 110.52 23.783 ;
        RECT  107.7 2.137 107.82 23.783 ;
        RECT  105 2.137 105.12 23.783 ;
        RECT  102.3 2.137 102.42 23.783 ;
        RECT  99.6 2.137 99.72 23.783 ;
        RECT  96.9 2.137 97.02 23.783 ;
        RECT  94.2 2.137 94.32 23.783 ;
        RECT  91.5 2.137 91.62 23.783 ;
        RECT  88.8 2.137 88.92 23.783 ;
        RECT  86.1 2.137 86.22 23.783 ;
        RECT  83.4 2.137 83.52 23.783 ;
        RECT  80.7 2.137 80.82 23.783 ;
        RECT  78 2.137 78.12 23.783 ;
        RECT  75.3 2.137 75.42 23.783 ;
        RECT  72.6 2.137 72.72 23.783 ;
        RECT  69.9 2.137 70.02 23.783 ;
        RECT  67.2 2.137 67.32 23.783 ;
        RECT  64.5 2.137 64.62 23.783 ;
        RECT  61.8 2.137 61.92 23.783 ;
        RECT  59.1 2.137 59.22 23.783 ;
        RECT  56.4 2.137 56.52 23.783 ;
        RECT  53.7 2.137 53.82 23.783 ;
        RECT  51 2.137 51.12 23.783 ;
        RECT  48.3 2.137 48.42 23.783 ;
        RECT  45.6 2.137 45.72 23.783 ;
        RECT  42.9 2.137 43.02 23.783 ;
        RECT  40.2 2.137 40.32 23.783 ;
        RECT  37.5 2.137 37.62 23.783 ;
        RECT  34.8 2.137 34.92 23.783 ;
        RECT  32.1 2.137 32.22 23.783 ;
        RECT  29.4 2.137 29.52 23.783 ;
        RECT  26.7 2.137 26.82 23.783 ;
        RECT  24 2.137 24.12 23.783 ;
        RECT  21.3 2.137 21.42 23.783 ;
        RECT  18.6 2.137 18.72 23.783 ;
        RECT  15.9 2.137 16.02 23.783 ;
        RECT  13.2 2.137 13.32 23.783 ;
        RECT  10.5 2.137 10.62 23.783 ;
        RECT  7.8 2.137 7.92 23.783 ;
        RECT  5.1 2.137 5.22 23.783 ;
        RECT  2.4 2.137 2.52 23.783 ;
    END
  END VSS
  OBS
    LAYER RVTN ;
     RECT  2.16 2.16 216 2.295 ;
     RECT  2.16 2.565 216 2.835 ;
     RECT  2.16 3.105 216 3.375 ;
     RECT  2.16 3.645 216 3.915 ;
     RECT  2.16 4.185 216 4.455 ;
     RECT  2.16 4.725 216 4.995 ;
     RECT  2.16 5.265 216 5.535 ;
     RECT  2.16 5.805 216 6.075 ;
     RECT  2.16 6.345 216 6.615 ;
     RECT  2.16 6.885 216 7.155 ;
     RECT  2.16 7.425 216 7.695 ;
     RECT  2.16 7.965 216 8.235 ;
     RECT  2.16 8.505 216 8.775 ;
     RECT  2.16 9.045 216 9.315 ;
     RECT  2.16 9.585 216 9.855 ;
     RECT  2.16 10.125 216 10.395 ;
     RECT  2.16 10.665 216 10.935 ;
     RECT  2.16 11.205 216 11.475 ;
     RECT  2.16 11.745 216 12.015 ;
     RECT  2.16 12.285 216 12.555 ;
     RECT  2.16 12.825 216 13.095 ;
     RECT  2.16 13.365 216 13.635 ;
     RECT  2.16 13.905 216 14.175 ;
     RECT  2.16 14.445 216 14.715 ;
     RECT  2.16 14.985 216 15.255 ;
     RECT  2.16 15.525 216 15.795 ;
     RECT  2.16 16.065 216 16.335 ;
     RECT  2.16 16.605 216 16.875 ;
     RECT  2.16 17.145 216 17.415 ;
     RECT  2.16 17.685 216 17.955 ;
     RECT  2.16 18.225 216 18.495 ;
     RECT  2.16 18.765 216 19.035 ;
     RECT  2.16 19.305 216 19.575 ;
     RECT  2.16 19.845 216 20.115 ;
     RECT  2.16 20.385 216 20.655 ;
     RECT  2.16 20.925 216 21.195 ;
     RECT  2.16 21.465 216 21.735 ;
     RECT  2.16 22.005 216 22.275 ;
     RECT  2.16 22.545 216 22.815 ;
     RECT  2.16 23.085 216 23.355 ;
     RECT  2.16 23.625 216 23.76 ;
    LAYER RVTP ;
     RECT  2.16 2.295 216 2.565 ;
     RECT  2.16 2.835 216 3.105 ;
     RECT  2.16 3.375 216 3.645 ;
     RECT  2.16 3.915 216 4.185 ;
     RECT  2.16 4.455 216 4.725 ;
     RECT  2.16 4.995 216 5.265 ;
     RECT  2.16 5.535 216 5.805 ;
     RECT  2.16 6.075 216 6.345 ;
     RECT  2.16 6.615 216 6.885 ;
     RECT  2.16 7.155 216 7.425 ;
     RECT  2.16 7.695 216 7.965 ;
     RECT  2.16 8.235 216 8.505 ;
     RECT  2.16 8.775 216 9.045 ;
     RECT  2.16 9.315 216 9.585 ;
     RECT  2.16 9.855 216 10.125 ;
     RECT  2.16 10.395 216 10.665 ;
     RECT  2.16 10.935 216 11.205 ;
     RECT  2.16 11.475 216 11.745 ;
     RECT  2.16 12.015 216 12.285 ;
     RECT  2.16 12.555 216 12.825 ;
     RECT  2.16 13.095 216 13.365 ;
     RECT  2.16 13.635 216 13.905 ;
     RECT  2.16 14.175 216 14.445 ;
     RECT  2.16 14.715 216 14.985 ;
     RECT  2.16 15.255 216 15.525 ;
     RECT  2.16 15.795 216 16.065 ;
     RECT  2.16 16.335 216 16.605 ;
     RECT  2.16 16.875 216 17.145 ;
     RECT  2.16 17.415 216 17.685 ;
     RECT  2.16 17.955 216 18.225 ;
     RECT  2.16 18.495 216 18.765 ;
     RECT  2.16 19.035 216 19.305 ;
     RECT  2.16 19.575 216 19.845 ;
     RECT  2.16 20.115 216 20.385 ;
     RECT  2.16 20.655 216 20.925 ;
     RECT  2.16 21.195 216 21.465 ;
     RECT  2.16 21.735 216 22.005 ;
     RECT  2.16 22.275 216 22.545 ;
     RECT  2.16 22.815 216 23.085 ;
     RECT  2.16 23.355 216 23.625 ;
    LAYER M1 ;
     RECT  2.16 2.151 216 23.769 ;
    LAYER M2 ;
     RECT  0.031 16.542 2.16 16.56 ;
     RECT  2.16 2.151 5.863 23.769 ;
     RECT  5.863 2.034 6.611 23.769 ;
     RECT  6.611 2.106 7.375 23.769 ;
     RECT  7.375 2.034 9.167 23.769 ;
     RECT  9.167 2.151 10.831 23.769 ;
     RECT  10.831 2.106 11.723 23.769 ;
     RECT  11.723 2.151 12.487 23.769 ;
     RECT  12.487 2.106 13.099 23.769 ;
     RECT  13.099 1.998 15.143 23.769 ;
     RECT  15.143 2.034 16.555 23.769 ;
     RECT  16.555 1.998 18.823 23.769 ;
     RECT  18.823 1.962 21.955 23.769 ;
     RECT  21.955 1.836 27.095 23.769 ;
     RECT  27.095 1.881 27.239 23.769 ;
     RECT  27.239 1.962 29.083 23.769 ;
     RECT  29.083 1.692 29.399 23.769 ;
     RECT  29.399 1.962 34.259 23.769 ;
     RECT  12.307 0.531 34.735 0.549 ;
     RECT  34.735 0.036 35.851 0.549 ;
     RECT  35.851 0.036 37.039 1.17 ;
     RECT  34.259 2.034 37.039 23.769 ;
     RECT  37.039 0.036 43.367 23.769 ;
     RECT  43.367 0.108 46.111 23.769 ;
     RECT  46.111 0.072 50.143 23.769 ;
     RECT  50.143 0.036 94.091 23.769 ;
     RECT  94.091 0.072 96.295 23.769 ;
     RECT  96.295 0.036 185.891 23.769 ;
     RECT  185.891 0.036 186.467 0.864 ;
     RECT  186.467 0.036 186.899 0.549 ;
     RECT  185.891 1.764 188.231 23.769 ;
     RECT  188.231 1.8 191.587 23.769 ;
     RECT  191.587 1.728 197.051 23.769 ;
     RECT  197.051 1.836 204.827 23.769 ;
     RECT  204.827 1.881 205.259 23.769 ;
     RECT  186.899 0.531 211.019 0.549 ;
     RECT  205.259 2.151 211.963 23.769 ;
     RECT  211.963 2.034 212.783 23.769 ;
     RECT  212.783 2.106 212.819 23.769 ;
     RECT  212.819 2.151 216 23.769 ;
     RECT  216 2.421 216.012 23.499 ;
    LAYER M3 ;
     RECT  94.068 0.031 94.086 0.067 ;
     RECT  105.12 0.043 105.138 0.091 ;
     RECT  162.036 0.043 162.054 0.091 ;
     RECT  182.988 0.067 183.006 0.091 ;
     RECT  43.344 0.031 43.362 0.103 ;
     RECT  182.988 0.091 183.474 0.103 ;
     RECT  98.028 0.103 98.046 0.139 ;
     RECT  99.18 0.043 99.198 0.139 ;
     RECT  158.472 0.043 158.49 0.139 ;
     RECT  174.42 0.043 174.438 0.139 ;
     RECT  36.9 0.091 36.918 0.187 ;
     RECT  97.344 0.139 98.046 0.187 ;
     RECT  99.144 0.139 99.198 0.187 ;
     RECT  102.636 0.043 102.654 0.187 ;
     RECT  103.536 0.139 104.166 0.187 ;
     RECT  105.12 0.091 105.822 0.187 ;
     RECT  106.668 0.139 106.794 0.187 ;
     RECT  133.056 0.139 133.074 0.187 ;
     RECT  139.248 0.091 139.41 0.187 ;
     RECT  142.38 0.175 142.398 0.187 ;
     RECT  146.196 0.139 146.214 0.187 ;
     RECT  154.08 0.091 154.602 0.187 ;
     RECT  158.472 0.139 158.598 0.187 ;
     RECT  161.712 0.091 162.054 0.187 ;
     RECT  176.436 0.139 176.454 0.187 ;
     RECT  179.64 0.043 179.658 0.187 ;
     RECT  186.876 0.031 186.894 0.187 ;
     RECT  46.116 0.067 46.134 0.211 ;
     RECT  50.148 0.031 50.166 0.211 ;
     RECT  70.956 0.187 70.974 0.211 ;
     RECT  88.272 0.067 88.29 0.211 ;
     RECT  157.428 0.043 157.446 0.211 ;
     RECT  18.828 0.043 18.846 0.221 ;
     RECT  179.352 0.187 179.658 0.221 ;
     RECT  182.304 0.103 183.474 0.221 ;
     RECT  5.256 0.187 5.274 0.235 ;
     RECT  83.376 0.103 83.394 0.235 ;
     RECT  87.3 0.139 87.318 0.235 ;
     RECT  88.164 0.211 88.29 0.235 ;
     RECT  89.46 0.067 89.478 0.235 ;
     RECT  138.852 0.187 140.454 0.235 ;
     RECT  141.228 0.187 142.398 0.235 ;
     RECT  151.74 0.187 151.758 0.235 ;
     RECT  153.936 0.187 154.602 0.235 ;
     RECT  158.4 0.187 158.994 0.235 ;
     RECT  168.984 0.187 169.002 0.235 ;
     RECT  174.42 0.139 174.582 0.235 ;
     RECT  34.74 0.031 34.758 0.256 ;
     RECT  49.5 0.211 50.166 0.256 ;
     RECT  46.008 0.211 46.278 0.269 ;
     RECT  67.608 0.187 69.354 0.283 ;
     RECT  81.288 0.139 81.306 0.283 ;
     RECT  101.016 0.187 101.898 0.283 ;
     RECT  102.636 0.187 107.73 0.283 ;
     RECT  124.992 0.175 125.01 0.283 ;
     RECT  136.548 0.187 137.574 0.283 ;
     RECT  138.852 0.235 142.398 0.283 ;
     RECT  144.396 0.187 145.458 0.283 ;
     RECT  146.196 0.187 146.79 0.283 ;
     RECT  165.636 0.175 165.654 0.283 ;
     RECT  166.572 0.235 166.59 0.283 ;
     RECT  174.42 0.235 174.618 0.283 ;
     RECT  101.016 0.283 107.73 0.301 ;
     RECT  157.32 0.211 157.446 0.301 ;
     RECT  56.592 0.283 56.898 0.329 ;
     RECT  110.952 0.283 111.798 0.329 ;
     RECT  49.5 0.256 50.67 0.331 ;
     RECT  51.444 0.235 51.462 0.331 ;
     RECT  94.896 0.283 95.562 0.331 ;
     RECT  96.3 0.031 96.318 0.331 ;
     RECT  130.68 0.187 133.362 0.331 ;
     RECT  172.476 0.091 172.494 0.331 ;
     RECT  179.352 0.221 179.55 0.331 ;
     RECT  92.196 0.139 92.214 0.337 ;
     RECT  92.952 0.067 92.97 0.337 ;
     RECT  97.344 0.187 100.206 0.337 ;
     RECT  101.016 0.301 107.802 0.337 ;
     RECT  47.844 0.139 47.862 0.365 ;
     RECT  168.984 0.235 169.29 0.365 ;
     RECT  36.9 0.187 37.026 0.379 ;
     RECT  64.08 0.283 64.098 0.379 ;
     RECT  65.484 0.283 65.502 0.379 ;
     RECT  73.476 0.187 73.602 0.379 ;
     RECT  75.24 0.139 75.258 0.379 ;
     RECT  77.796 0.283 77.814 0.379 ;
     RECT  79.488 0.283 81.306 0.379 ;
     RECT  83.376 0.235 90.99 0.379 ;
     RECT  92.196 0.337 92.97 0.379 ;
     RECT  94.032 0.067 94.086 0.379 ;
     RECT  115.668 0.283 115.686 0.379 ;
     RECT  126.36 0.283 126.378 0.379 ;
     RECT  170.532 0.187 170.55 0.379 ;
     RECT  97.344 0.337 107.802 0.401 ;
     RECT  174.24 0.283 174.618 0.401 ;
     RECT  170.352 0.379 170.55 0.409 ;
     RECT  148.896 0.091 148.914 0.413 ;
     RECT  58.968 0.091 58.986 0.427 ;
     RECT  77.796 0.379 78.354 0.427 ;
     RECT  83.376 0.379 94.086 0.427 ;
     RECT  94.896 0.331 96.318 0.427 ;
     RECT  110.952 0.329 111.654 0.427 ;
     RECT  114.66 0.283 114.678 0.427 ;
     RECT  115.56 0.379 115.686 0.427 ;
     RECT  119.484 0.283 120.186 0.427 ;
     RECT  121.86 0.283 121.878 0.427 ;
     RECT  157.32 0.301 157.626 0.427 ;
     RECT  174.24 0.401 174.582 0.427 ;
     RECT  116.82 0.283 118.134 0.445 ;
     RECT  161.712 0.187 162.81 0.445 ;
     RECT  163.728 0.187 163.746 0.445 ;
     RECT  170.28 0.409 170.55 0.461 ;
     RECT  121.86 0.427 122.526 0.473 ;
     RECT  43.344 0.103 43.506 0.475 ;
     RECT  73.332 0.379 75.258 0.475 ;
     RECT  83.16 0.427 96.318 0.475 ;
     RECT  97.344 0.401 107.298 0.475 ;
     RECT  113.796 0.283 113.814 0.475 ;
     RECT  128.52 0.187 128.538 0.475 ;
     RECT  197.136 0.187 197.154 0.475 ;
     RECT  109.404 0.283 109.422 0.481 ;
     RECT  110.592 0.427 111.654 0.481 ;
     RECT  165.564 0.283 165.654 0.481 ;
     RECT  166.5 0.283 166.59 0.481 ;
     RECT  34.74 0.256 34.83 0.509 ;
     RECT  36.324 0.379 37.638 0.509 ;
     RECT  49.5 0.331 51.534 0.509 ;
     RECT  161.712 0.445 163.746 0.509 ;
     RECT  58.536 0.427 58.986 0.523 ;
     RECT  65.412 0.379 65.502 0.523 ;
     RECT  70.344 0.211 70.974 0.523 ;
     RECT  71.784 0.187 72.27 0.523 ;
     RECT  73.08 0.475 75.258 0.523 ;
     RECT  112.572 0.475 113.814 0.523 ;
     RECT  114.66 0.427 115.686 0.523 ;
     RECT  116.496 0.445 118.134 0.523 ;
     RECT  119.484 0.427 120.546 0.523 ;
     RECT  130.248 0.331 133.362 0.523 ;
     RECT  135 0.187 135.774 0.523 ;
     RECT  136.548 0.283 142.398 0.523 ;
     RECT  143.604 0.187 143.622 0.523 ;
     RECT  144.396 0.283 146.79 0.523 ;
     RECT  147.564 0.187 148.122 0.523 ;
     RECT  149.652 0.427 149.67 0.523 ;
     RECT  151.128 0.235 151.758 0.523 ;
     RECT  153.036 0.475 153.054 0.523 ;
     RECT  161.712 0.509 162.81 0.523 ;
     RECT  165.564 0.481 166.59 0.523 ;
     RECT  174.096 0.427 174.582 0.523 ;
     RECT  176.436 0.187 177.21 0.523 ;
     RECT  185.184 0.187 185.526 0.523 ;
     RECT  186.408 0.187 187.146 0.523 ;
     RECT  196.956 0.475 197.154 0.523 ;
     RECT  204.552 0.187 204.57 0.523 ;
     RECT  209.16 0.187 209.646 0.523 ;
     RECT  212.976 0.187 213.57 0.523 ;
     RECT  121.86 0.473 122.418 0.557 ;
     RECT  13.86 0.187 13.878 0.571 ;
     RECT  48.708 0.175 48.726 0.571 ;
     RECT  76.644 0.427 78.354 0.571 ;
     RECT  108.576 0.481 108.594 0.571 ;
     RECT  109.404 0.481 111.654 0.571 ;
     RECT  188.532 0.523 188.55 0.571 ;
     RECT  204.156 0.523 204.57 0.571 ;
     RECT  209.16 0.523 209.862 0.571 ;
     RECT  212.94 0.523 213.57 0.571 ;
     RECT  48.708 0.571 48.762 0.679 ;
     RECT  112.572 0.523 118.134 0.715 ;
     RECT  170.424 0.461 170.55 0.715 ;
     RECT  171.288 0.523 171.306 0.715 ;
     RECT  170.424 0.715 171.306 0.763 ;
     RECT  26.136 0.571 26.154 0.811 ;
     RECT  46.872 0.331 46.89 0.811 ;
     RECT  202.536 0.187 202.554 0.811 ;
     RECT  83.16 0.475 107.298 0.824 ;
     RECT  64.08 0.379 64.422 0.859 ;
     RECT  167.832 0.187 167.85 0.859 ;
     RECT  173.268 0.187 173.286 0.859 ;
     RECT  184.644 0.523 185.526 0.859 ;
     RECT  186.408 0.523 187.434 0.859 ;
     RECT  193.284 0.187 193.302 0.859 ;
     RECT  50.364 0.509 51.534 0.877 ;
     RECT  176.436 0.523 177.858 0.877 ;
     RECT  36.324 0.509 36.342 0.905 ;
     RECT  83.16 0.824 99.558 0.905 ;
     RECT  58.428 0.523 58.986 0.907 ;
     RECT  170.424 0.763 171.378 0.907 ;
     RECT  172.44 0.331 172.494 0.907 ;
     RECT  190.908 0.187 190.926 0.907 ;
     RECT  174.06 0.523 174.582 0.913 ;
     RECT  153.936 0.235 154.818 0.955 ;
     RECT  165.564 0.523 166.734 0.955 ;
     RECT  167.58 0.859 167.85 0.955 ;
     RECT  180.936 0.043 180.954 0.955 ;
     RECT  37.62 0.509 37.638 1.003 ;
     RECT  38.448 0.379 38.466 1.003 ;
     RECT  153.036 0.523 153.126 1.003 ;
     RECT  153.936 0.955 154.926 1.003 ;
     RECT  170.424 0.907 172.494 1.003 ;
     RECT  173.232 0.859 173.286 1.003 ;
     RECT  192.996 0.859 193.302 1.003 ;
     RECT  194.256 0.091 194.274 1.003 ;
     RECT  54.144 0.955 54.162 1.051 ;
     RECT  54.972 1.021 54.99 1.051 ;
     RECT  143.604 0.523 148.122 1.051 ;
     RECT  165.564 0.955 167.85 1.051 ;
     RECT  168.984 0.365 169.002 1.051 ;
     RECT  180.396 0.955 180.954 1.051 ;
     RECT  196.488 0.523 197.154 1.051 ;
     RECT  200.664 0.571 200.682 1.051 ;
     RECT  158.4 0.235 159.066 1.066 ;
     RECT  160.272 0.523 162.81 1.066 ;
     RECT  163.728 0.509 163.746 1.099 ;
     RECT  179.244 0.331 179.55 1.099 ;
     RECT  180.396 1.051 181.566 1.099 ;
     RECT  182.304 0.221 183.006 1.099 ;
     RECT  190.908 0.907 190.962 1.099 ;
     RECT  196.488 1.051 197.19 1.099 ;
     RECT  198.252 0.187 198.27 1.099 ;
     RECT  200.664 1.051 201.042 1.099 ;
     RECT  201.816 0.811 202.554 1.099 ;
     RECT  207.756 0.187 207.774 1.099 ;
     RECT  208.62 0.571 209.862 1.099 ;
     RECT  212.76 0.571 213.57 1.099 ;
     RECT  67.068 0.283 69.354 1.111 ;
     RECT  70.344 0.523 75.258 1.111 ;
     RECT  170.424 1.003 173.286 1.133 ;
     RECT  14.652 0.187 14.67 1.147 ;
     RECT  17.928 0.811 17.946 1.147 ;
     RECT  20.88 0.571 20.898 1.147 ;
     RECT  43.344 0.475 43.722 1.147 ;
     RECT  48.132 0.679 48.762 1.147 ;
     RECT  76.104 0.571 78.354 1.147 ;
     RECT  188.208 0.571 189.09 1.147 ;
     RECT  189.9 1.051 189.918 1.147 ;
     RECT  191.772 0.571 191.79 1.147 ;
     RECT  200.664 1.099 202.77 1.147 ;
     RECT  207.396 1.099 209.862 1.147 ;
     RECT  210.78 0.187 211.05 1.147 ;
     RECT  43.344 1.147 43.794 1.195 ;
     RECT  119.484 0.523 120.618 1.291 ;
     RECT  48.132 1.147 49.302 1.339 ;
     RECT  108.072 0.571 111.654 1.339 ;
     RECT  170.424 1.133 172.494 1.339 ;
     RECT  45.756 0.811 45.774 1.387 ;
     RECT  179.244 1.099 183.006 1.387 ;
     RECT  45.216 1.387 45.774 1.417 ;
     RECT  191.772 1.147 191.826 1.435 ;
     RECT  192.996 1.003 194.274 1.435 ;
     RECT  63.504 0.859 64.422 1.483 ;
     RECT  65.196 0.523 65.502 1.483 ;
     RECT  20.628 1.147 20.898 1.531 ;
     RECT  156.636 0.427 157.626 1.531 ;
     RECT  158.4 1.066 162.81 1.531 ;
     RECT  174.024 0.913 174.582 1.531 ;
     RECT  179.244 1.387 183.51 1.531 ;
     RECT  10.404 1.147 10.422 1.579 ;
     RECT  67.068 1.111 75.258 1.579 ;
     RECT  76.104 1.147 78.606 1.579 ;
     RECT  46.872 0.811 47.178 1.627 ;
     RECT  47.916 1.339 49.302 1.627 ;
     RECT  135 0.523 142.398 1.627 ;
     RECT  190.872 1.099 190.962 1.627 ;
     RECT  43.344 1.195 44.154 1.651 ;
     RECT  173.268 1.133 173.286 1.651 ;
     RECT  174.024 1.531 175.122 1.651 ;
     RECT  6.876 1.579 6.894 1.675 ;
     RECT  29.664 0.091 29.682 1.675 ;
     RECT  149.544 0.523 149.67 1.675 ;
     RECT  184.644 0.859 187.434 1.675 ;
     RECT  190.764 1.627 190.962 1.675 ;
     RECT  206.46 1.099 206.478 1.675 ;
     RECT  207.396 1.147 211.05 1.675 ;
     RECT  212.328 1.099 213.57 1.675 ;
     RECT  91.944 0.905 99.558 1.679 ;
     RECT  50.364 0.877 52.146 1.687 ;
     RECT  5.256 0.235 5.634 1.723 ;
     RECT  6.516 1.675 6.894 1.723 ;
     RECT  8.208 1.675 8.226 1.723 ;
     RECT  9.108 0.187 9.126 1.723 ;
     RECT  10.404 1.579 10.818 1.723 ;
     RECT  12.312 0.526 12.33 1.723 ;
     RECT  13.572 0.571 13.878 1.723 ;
     RECT  14.616 1.147 14.67 1.723 ;
     RECT  15.876 0.571 15.894 1.723 ;
     RECT  17.424 1.147 17.946 1.723 ;
     RECT  20.268 1.531 20.898 1.723 ;
     RECT  27.432 0.187 27.45 1.723 ;
     RECT  45.216 1.417 46.134 1.723 ;
     RECT  46.872 1.627 49.302 1.723 ;
     RECT  184.392 1.675 187.434 1.723 ;
     RECT  188.208 1.147 189.918 1.723 ;
     RECT  190.764 1.675 190.998 1.723 ;
     RECT  191.772 1.435 194.274 1.723 ;
     RECT  203.904 0.571 204.93 1.723 ;
     RECT  205.74 1.675 211.122 1.723 ;
     RECT  212.112 1.675 213.57 1.723 ;
     RECT  176.436 0.877 178.146 1.759 ;
     RECT  4.536 1.723 6.894 1.771 ;
     RECT  8.208 1.723 10.962 1.771 ;
     RECT  16.668 1.723 16.686 1.771 ;
     RECT  17.424 1.723 18.774 1.771 ;
     RECT  20.268 1.723 21.114 1.771 ;
     RECT  21.852 0.571 21.87 1.771 ;
     RECT  22.68 1.723 23.022 1.771 ;
     RECT  23.904 1.723 23.922 1.771 ;
     RECT  37.62 1.003 38.466 1.771 ;
     RECT  54.144 1.051 54.99 1.771 ;
     RECT  62.136 0.283 62.586 1.771 ;
     RECT  67.068 1.579 78.606 1.771 ;
     RECT  37.584 1.771 38.466 1.795 ;
     RECT  50.364 1.687 52.398 1.795 ;
     RECT  16.668 1.771 18.774 1.819 ;
     RECT  25.632 0.811 26.154 1.819 ;
     RECT  34.2 1.099 34.218 1.819 ;
     RECT  179.244 1.531 183.546 1.819 ;
     RECT  27.108 1.723 27.81 1.831 ;
     RECT  54.036 1.771 54.99 1.831 ;
     RECT  149.364 1.675 149.67 1.859 ;
     RECT  20.268 1.771 23.922 1.867 ;
     RECT  29.088 1.675 29.682 1.867 ;
     RECT  25.596 1.819 26.154 1.876 ;
     RECT  184.392 1.723 189.918 1.876 ;
     RECT  62.136 1.771 62.73 1.915 ;
     RECT  63.504 1.483 65.502 1.915 ;
     RECT  179.244 1.819 183.582 1.915 ;
     RECT  184.392 1.876 189.99 1.915 ;
     RECT  190.764 1.723 194.274 1.915 ;
     RECT  54.036 1.831 55.278 1.921 ;
     RECT  119.376 1.291 120.618 1.921 ;
     RECT  170.208 1.339 172.494 1.921 ;
     RECT  173.268 1.651 175.122 1.921 ;
     RECT  112.536 0.715 118.134 1.949 ;
     RECT  25.488 1.876 26.154 1.957 ;
     RECT  33.48 1.819 34.218 1.957 ;
     RECT  114.804 1.949 118.134 1.957 ;
     RECT  165.564 1.051 169.002 1.957 ;
     RECT  179.244 1.915 183.618 1.957 ;
     RECT  184.392 1.915 194.274 1.957 ;
     RECT  12.312 1.723 15.894 1.963 ;
     RECT  25.488 1.957 26.298 1.963 ;
     RECT  165.564 1.957 169.254 1.963 ;
     RECT  179.244 1.957 194.274 1.963 ;
     RECT  195.12 1.957 195.138 1.963 ;
     RECT  12.204 1.963 15.894 1.993 ;
     RECT  16.668 1.819 19.17 1.993 ;
     RECT  25.452 1.963 26.298 1.993 ;
     RECT  27.072 1.831 27.81 1.993 ;
     RECT  29.088 1.867 30.33 1.993 ;
     RECT  45.216 1.723 49.302 1.993 ;
     RECT  83.16 0.905 90.99 1.993 ;
     RECT  91.944 1.679 92.322 1.993 ;
     RECT  170.208 1.921 175.122 1.993 ;
     RECT  176.436 1.759 178.434 1.993 ;
     RECT  200.628 1.147 202.77 1.993 ;
     RECT  8.208 1.771 11.394 2.011 ;
     RECT  35.856 1.147 35.874 2.011 ;
     RECT  100.62 0.824 107.298 2.011 ;
     RECT  108.036 1.339 111.654 2.011 ;
     RECT  135 1.627 142.434 2.011 ;
     RECT  179.244 1.963 195.138 2.011 ;
     RECT  196.488 1.099 198.27 2.011 ;
     RECT  149.544 1.859 149.67 2.021 ;
     RECT  4.536 1.771 7.362 2.029 ;
     RECT  40.068 1.819 40.086 2.029 ;
     RECT  53.568 1.921 55.278 2.029 ;
     RECT  134.676 2.011 142.434 2.029 ;
     RECT  150.876 0.523 151.758 2.029 ;
     RECT  31.356 0.043 31.374 2.059 ;
     RECT  62.064 1.915 65.502 2.059 ;
     RECT  67.068 1.771 78.678 2.059 ;
     RECT  79.488 0.379 82.314 2.059 ;
     RECT  41.256 1.876 41.274 2.065 ;
     RECT  42.192 1.387 42.21 2.065 ;
     RECT  50.256 1.795 52.398 2.065 ;
     RECT  179.244 2.011 198.27 2.065 ;
     RECT  199.584 0.571 199.602 2.065 ;
     RECT  4.536 2.029 7.398 2.101 ;
     RECT  8.136 2.011 11.394 2.101 ;
     RECT  12.204 1.993 19.17 2.101 ;
     RECT  19.944 1.867 23.922 2.101 ;
     RECT  35.208 2.011 35.874 2.101 ;
     RECT  42.192 2.065 42.246 2.101 ;
     RECT  43.344 1.651 44.442 2.101 ;
     RECT  53.568 2.029 55.782 2.101 ;
     RECT  163.728 1.099 164.07 2.101 ;
     RECT  200.484 1.993 202.77 2.101 ;
     RECT  19.944 2.101 23.994 2.143 ;
     RECT  31.356 2.059 32.094 2.143 ;
     RECT  33.48 1.957 34.254 2.143 ;
     RECT  35.208 2.101 36.198 2.143 ;
     RECT  53.316 2.101 55.782 2.143 ;
     RECT  57.816 0.907 58.986 2.143 ;
     RECT  61.128 0.715 61.146 2.143 ;
     RECT  61.992 2.059 65.502 2.143 ;
     RECT  93.204 1.679 99.558 2.143 ;
     RECT  114.804 1.957 118.386 2.143 ;
     RECT  119.376 1.921 120.978 2.143 ;
     RECT  121.86 0.557 122.31 2.143 ;
     RECT  126.252 0.379 126.378 2.143 ;
     RECT  128.52 0.475 128.718 2.143 ;
     RECT  134.676 2.029 142.578 2.143 ;
     RECT  143.604 1.051 148.158 2.143 ;
     RECT  152.784 1.003 153.126 2.143 ;
     RECT  153.864 1.003 154.926 2.143 ;
     RECT  155.88 0.523 155.898 2.143 ;
     RECT  156.636 1.531 162.81 2.143 ;
     RECT  163.692 2.101 164.07 2.143 ;
     RECT  164.988 1.963 169.254 2.143 ;
     RECT  170.208 1.993 175.158 2.143 ;
     RECT  179.244 2.065 199.602 2.143 ;
     RECT  19.944 2.143 24.105 2.191 ;
     RECT  31.356 2.143 32.205 2.191 ;
     RECT  33.48 2.143 36.198 2.191 ;
     RECT  40.068 2.029 40.482 2.191 ;
     RECT  41.256 2.065 41.454 2.191 ;
     RECT  42.192 2.101 44.442 2.191 ;
     RECT  45.216 1.993 49.518 2.191 ;
     RECT  50.256 2.065 52.578 2.191 ;
     RECT  128.52 2.143 129.405 2.191 ;
     RECT  134.676 2.143 148.305 2.191 ;
     RECT  152.784 2.143 154.926 2.191 ;
     RECT  4.536 2.101 19.17 2.219 ;
     RECT  45.216 2.191 52.578 2.219 ;
     RECT  61.128 2.143 65.502 2.219 ;
     RECT  28.548 1.993 30.582 2.227 ;
     RECT  31.356 2.191 36.198 2.227 ;
     RECT  37.044 1.795 38.466 2.227 ;
     RECT  39.312 2.191 39.33 2.227 ;
     RECT  130.248 0.523 133.686 2.227 ;
     RECT  163.692 2.143 175.305 2.227 ;
     RECT  176.436 1.993 178.506 2.227 ;
     RECT  53.316 2.143 56.505 2.255 ;
     RECT  200.484 2.101 203.13 2.255 ;
     RECT  19.944 2.191 24.174 2.263 ;
     RECT  55.944 2.255 56.505 2.263 ;
     RECT  200.628 2.255 203.13 2.263 ;
     RECT  203.904 1.723 213.642 2.263 ;
     RECT  200.628 2.263 213.642 2.291 ;
     RECT  37.044 2.227 39.33 2.299 ;
     RECT  40.068 2.191 44.442 2.299 ;
     RECT  57.816 2.143 59.205 2.299 ;
     RECT  163.692 2.227 178.506 2.299 ;
     RECT  179.244 2.143 199.605 2.299 ;
     RECT  4.86 2.219 19.17 2.335 ;
     RECT  19.944 2.263 24.498 2.335 ;
     RECT  25.452 1.993 27.81 2.335 ;
     RECT  28.548 2.227 36.198 2.335 ;
     RECT  150.552 2.029 151.758 2.335 ;
     RECT  152.604 2.191 154.926 2.335 ;
     RECT  155.88 2.143 162.81 2.335 ;
     RECT  130.248 2.227 133.938 2.371 ;
     RECT  134.676 2.191 148.554 2.371 ;
     RECT  149.652 2.021 149.67 2.371 ;
     RECT  150.552 2.335 162.81 2.371 ;
     RECT  2.415 2.143 2.505 2.413 ;
     RECT  93.204 2.143 99.705 2.413 ;
     RECT  114.804 2.143 118.605 2.413 ;
     RECT  119.376 2.143 122.31 2.413 ;
     RECT  126.252 2.143 126.705 2.413 ;
     RECT  127.908 2.191 129.405 2.413 ;
     RECT  130.248 2.371 148.554 2.413 ;
     RECT  163.692 2.299 199.605 2.413 ;
     RECT  215.715 2.143 215.805 2.413 ;
     RECT  83.16 1.993 92.322 2.461 ;
     RECT  93.204 2.413 99.897 2.461 ;
     RECT  149.652 2.371 162.81 2.461 ;
     RECT  163.692 2.413 199.89 2.461 ;
     RECT  60.948 2.227 61.038 2.489 ;
     RECT  4.86 2.335 19.206 2.497 ;
     RECT  19.944 2.335 36.198 2.497 ;
     RECT  37.044 2.299 44.442 2.497 ;
     RECT  57.816 2.299 59.454 2.497 ;
     RECT  149.652 2.461 199.89 2.561 ;
     RECT  57.816 2.497 59.994 2.633 ;
     RECT  53.316 2.255 55.062 2.641 ;
     RECT  4.86 2.497 44.442 2.669 ;
     RECT  200.628 2.291 208.17 2.669 ;
     RECT  127.908 2.413 148.554 2.759 ;
     RECT  52.92 2.641 55.062 2.795 ;
     RECT  67.068 2.059 82.314 2.803 ;
     RECT  83.16 2.461 99.897 2.803 ;
     RECT  149.652 2.561 187.434 2.831 ;
     RECT  57.816 2.633 59.397 2.839 ;
     RECT  147.564 2.759 148.554 2.839 ;
     RECT  5.076 2.669 44.442 2.875 ;
     RECT  45.216 2.219 52.146 2.875 ;
     RECT  55.944 2.263 57.006 2.911 ;
     RECT  57.744 2.839 59.397 2.911 ;
     RECT  63.9 2.219 65.502 2.911 ;
     RECT  67.068 2.803 99.897 2.911 ;
     RECT  100.62 2.011 111.654 2.911 ;
     RECT  114.804 2.413 122.31 2.923 ;
     RECT  67.068 2.911 111.654 2.957 ;
     RECT  67.068 2.957 99.897 3.001 ;
     RECT  126.252 2.413 126.897 3.001 ;
     RECT  209.16 2.291 213.642 3.029 ;
     RECT  114.804 2.923 122.742 3.037 ;
     RECT  123.48 0.283 125.514 3.037 ;
     RECT  126.252 3.001 127.134 3.037 ;
     RECT  127.908 2.759 146.79 3.037 ;
     RECT  100.62 2.957 111.654 3.053 ;
     RECT  5.076 2.875 52.146 3.065 ;
     RECT  63.9 2.911 65.61 3.101 ;
     RECT  63.9 3.101 65.574 3.109 ;
     RECT  126.252 3.037 146.79 3.137 ;
     RECT  169.815 2.831 173.322 3.137 ;
     RECT  61.815 2.219 63.126 3.145 ;
     RECT  63.864 3.109 65.574 3.145 ;
     RECT  188.316 2.561 199.89 3.145 ;
     RECT  53.424 2.795 55.062 3.181 ;
     RECT  112.536 1.949 114.03 3.181 ;
     RECT  114.804 3.037 125.514 3.181 ;
     RECT  112.5 3.181 125.514 3.209 ;
     RECT  147.564 2.839 148.698 3.271 ;
     RECT  149.652 2.831 169.002 3.271 ;
     RECT  53.424 3.181 55.134 3.299 ;
     RECT  5.076 3.065 49.302 3.335 ;
     RECT  50.112 3.065 52.146 3.371 ;
     RECT  50.184 3.371 52.146 3.379 ;
     RECT  66.708 3.001 99.897 3.407 ;
     RECT  112.5 3.209 122.814 3.407 ;
     RECT  126.252 3.137 133.686 3.407 ;
     RECT  147.564 3.271 169.002 3.407 ;
     RECT  60.948 2.489 60.966 3.451 ;
     RECT  55.944 2.911 59.397 3.499 ;
     RECT  60.192 2.803 60.21 3.499 ;
     RECT  55.944 3.499 60.21 3.541 ;
     RECT  60.948 3.451 61.038 3.541 ;
     RECT  134.424 3.137 146.79 3.541 ;
     RECT  147.564 3.407 151.758 3.541 ;
     RECT  5.076 3.335 38.826 3.569 ;
     RECT  152.604 3.407 169.002 3.641 ;
     RECT  50.184 3.379 52.434 3.691 ;
     RECT  50.184 3.691 52.578 3.721 ;
     RECT  53.424 3.299 55.098 3.721 ;
     RECT  155.628 3.641 169.002 3.721 ;
     RECT  169.815 3.137 173.142 3.721 ;
     RECT  174.06 2.831 187.434 3.721 ;
     RECT  188.316 3.145 200.07 3.721 ;
     RECT  201.024 2.669 208.17 3.721 ;
     RECT  66.708 3.407 87.174 3.811 ;
     RECT  39.78 3.335 49.302 3.839 ;
     RECT  5.115 3.569 11.394 3.947 ;
     RECT  174.06 3.721 200.07 3.947 ;
     RECT  61.815 3.145 65.574 3.955 ;
     RECT  66.42 3.811 87.174 3.955 ;
     RECT  127.764 3.407 133.686 3.955 ;
     RECT  134.424 3.541 151.758 3.955 ;
     RECT  184.392 3.947 200.07 3.979 ;
     RECT  200.988 3.721 208.17 3.979 ;
     RECT  100.62 3.053 108.126 3.991 ;
     RECT  108.864 3.053 111.654 3.991 ;
     RECT  184.392 3.979 208.422 4.019 ;
     RECT  114.804 3.407 122.814 4.075 ;
     RECT  174.06 3.947 183.654 4.075 ;
     RECT  5.115 3.947 11.286 4.109 ;
     RECT  174.024 4.075 183.654 4.181 ;
     RECT  12.312 3.569 38.826 4.225 ;
     RECT  39.78 3.839 44.154 4.225 ;
     RECT  55.944 3.541 61.038 4.225 ;
     RECT  112.5 3.407 113.994 4.225 ;
     RECT  114.804 4.075 122.85 4.225 ;
     RECT  184.68 4.019 208.422 4.225 ;
     RECT  209.16 3.029 213.498 4.225 ;
     RECT  127.764 3.955 151.758 4.261 ;
     RECT  152.604 3.641 154.818 4.261 ;
     RECT  184.68 4.225 213.498 4.261 ;
     RECT  12.312 4.225 44.154 4.289 ;
     RECT  126.252 3.407 126.954 4.363 ;
     RECT  127.764 4.261 154.818 4.363 ;
     RECT  12.456 4.289 44.154 4.379 ;
     RECT  61.815 3.955 87.174 4.379 ;
     RECT  44.964 3.839 49.302 4.387 ;
     RECT  50.184 3.721 55.098 4.387 ;
     RECT  123.66 3.209 125.514 4.387 ;
     RECT  126.252 4.363 154.818 4.387 ;
     RECT  123.66 4.387 154.818 4.415 ;
     RECT  44.964 4.387 55.098 4.423 ;
     RECT  55.944 4.225 61.074 4.423 ;
     RECT  123.66 4.415 126.897 4.423 ;
     RECT  61.815 4.379 65.682 4.451 ;
     RECT  112.5 4.225 122.85 4.495 ;
     RECT  123.588 4.423 126.897 4.495 ;
     RECT  44.964 4.423 61.074 4.523 ;
     RECT  66.672 4.379 87.174 4.523 ;
     RECT  127.908 4.415 154.818 4.523 ;
     RECT  155.628 3.721 173.142 4.555 ;
     RECT  174.024 4.181 183.597 4.555 ;
     RECT  67.032 4.523 87.174 4.621 ;
     RECT  88.02 3.407 99.897 4.621 ;
     RECT  112.5 4.495 126.897 4.757 ;
     RECT  6.228 4.109 11.286 4.765 ;
     RECT  15.768 4.379 44.154 4.765 ;
     RECT  100.62 3.991 111.654 4.843 ;
     RECT  112.5 4.757 122.67 4.843 ;
     RECT  67.032 4.621 99.897 4.877 ;
     RECT  87.948 4.877 99.897 4.891 ;
     RECT  100.62 4.843 122.67 4.891 ;
     RECT  55.836 4.523 61.074 4.963 ;
     RECT  61.815 4.451 65.538 4.963 ;
     RECT  155.628 4.555 183.597 4.987 ;
     RECT  6.228 4.765 11.43 5.035 ;
     RECT  87.948 4.891 122.67 5.069 ;
     RECT  15.768 4.765 44.226 5.071 ;
     RECT  44.964 4.523 55.062 5.071 ;
     RECT  15.768 5.071 55.062 5.099 ;
     RECT  87.948 5.069 111.654 5.117 ;
     RECT  127.908 4.523 151.758 5.161 ;
     RECT  12.456 4.379 14.814 5.179 ;
     RECT  152.604 4.523 154.818 5.197 ;
     RECT  155.592 4.987 183.597 5.197 ;
     RECT  5.115 4.109 5.397 5.275 ;
     RECT  6.228 5.035 11.466 5.275 ;
     RECT  12.456 5.179 14.85 5.275 ;
     RECT  12.456 5.275 14.922 5.305 ;
     RECT  15.915 5.099 55.062 5.305 ;
     RECT  55.836 4.963 65.538 5.305 ;
     RECT  127.692 5.161 151.758 5.341 ;
     RECT  152.604 5.197 183.597 5.341 ;
     RECT  184.68 4.261 213.966 5.341 ;
     RECT  5.115 5.275 11.466 5.467 ;
     RECT  12.276 5.305 14.922 5.467 ;
     RECT  67.032 4.877 87.174 5.467 ;
     RECT  66.78 5.467 87.174 5.503 ;
     RECT  112.536 5.069 122.67 5.503 ;
     RECT  123.588 4.757 126.897 5.503 ;
     RECT  15.915 5.305 65.538 5.575 ;
     RECT  66.276 5.503 87.174 5.575 ;
     RECT  5.115 5.467 14.922 5.701 ;
     RECT  5.115 5.701 14.994 5.737 ;
     RECT  5.115 5.737 15.03 5.809 ;
     RECT  5.115 5.809 15.102 5.845 ;
     RECT  15.915 5.575 87.174 5.971 ;
     RECT  87.948 5.117 108.378 6.007 ;
     RECT  109.44 5.117 111.654 6.007 ;
     RECT  184.32 5.341 213.966 6.043 ;
     RECT  5.115 5.845 15.138 6.115 ;
     RECT  15.876 5.971 87.21 6.115 ;
     RECT  87.948 6.007 111.654 6.115 ;
     RECT  127.692 5.341 183.597 6.115 ;
     RECT  184.32 6.043 214.182 6.115 ;
     RECT  112.536 5.503 126.897 6.241 ;
     RECT  127.692 6.115 214.182 6.241 ;
     RECT  5.115 6.115 111.654 6.539 ;
     RECT  63.972 6.539 111.654 6.619 ;
     RECT  112.536 6.241 214.182 6.619 ;
     RECT  63.972 6.619 214.182 6.809 ;
     RECT  152.208 6.809 214.182 6.881 ;
     RECT  123.48 6.809 151.362 7.079 ;
     RECT  12.276 6.539 63.162 7.321 ;
     RECT  12.096 7.321 63.162 7.349 ;
     RECT  37.404 7.349 63.162 7.663 ;
     RECT  63.972 6.809 122.67 7.663 ;
     RECT  12.096 7.349 36.666 7.691 ;
     RECT  127.8 7.079 151.362 7.771 ;
     RECT  152.244 6.881 214.182 7.771 ;
     RECT  12.168 7.691 36.666 7.799 ;
     RECT  123.696 7.079 127.062 7.861 ;
     RECT  37.404 7.663 122.814 7.867 ;
     RECT  123.588 7.861 127.062 7.867 ;
     RECT  127.8 7.771 214.182 7.925 ;
     RECT  127.8 7.925 151.362 7.949 ;
     RECT  12.24 7.799 36.666 8.239 ;
     RECT  37.404 7.867 127.062 8.239 ;
     RECT  127.908 7.949 151.362 8.779 ;
     RECT  152.136 7.925 214.182 8.779 ;
     RECT  12.24 8.239 127.062 8.813 ;
     RECT  23.436 8.813 127.062 8.957 ;
     RECT  127.908 8.779 214.182 8.969 ;
     RECT  12.24 8.813 22.554 9.085 ;
     RECT  5.115 6.539 11.286 9.391 ;
     RECT  12.06 9.085 22.554 9.391 ;
     RECT  100.62 8.957 127.062 9.779 ;
     RECT  23.436 8.957 99.897 9.895 ;
     RECT  100.62 9.779 114.642 9.895 ;
     RECT  115.416 9.779 127.062 9.931 ;
     RECT  127.908 8.969 131.166 9.931 ;
     RECT  115.416 9.931 127.098 10.049 ;
     RECT  127.908 9.931 131.202 10.049 ;
     RECT  23.436 9.895 114.642 10.157 ;
     RECT  100.62 10.157 102.654 10.637 ;
     RECT  103.428 10.157 114.642 10.831 ;
     RECT  115.416 10.049 127.062 10.831 ;
     RECT  103.428 10.831 127.062 10.843 ;
     RECT  127.908 10.049 131.166 10.843 ;
     RECT  103.428 10.843 131.166 10.967 ;
     RECT  132.015 8.969 214.182 11.245 ;
     RECT  131.904 11.245 214.182 11.408 ;
     RECT  23.436 10.157 99.897 11.507 ;
     RECT  52.74 11.507 99.897 11.551 ;
     RECT  100.62 10.637 102.597 11.551 ;
     RECT  103.428 10.967 123.03 11.713 ;
     RECT  123.768 10.967 131.166 11.713 ;
     RECT  103.428 11.713 131.166 11.813 ;
     RECT  52.74 11.551 102.597 11.947 ;
     RECT  103.428 11.813 122.886 11.947 ;
     RECT  123.624 11.813 131.166 12.595 ;
     RECT  52.74 11.947 122.886 12.859 ;
     RECT  123.624 12.595 131.274 12.859 ;
     RECT  52.74 12.859 131.274 12.901 ;
     RECT  132.015 11.408 214.182 12.901 ;
     RECT  0.216 12.955 0.234 13.051 ;
     RECT  0.036 13.051 0.234 13.085 ;
     RECT  52.74 12.901 214.182 14.783 ;
     RECT  123.624 14.783 214.182 14.909 ;
     RECT  52.74 14.783 122.886 15.871 ;
     RECT  123.66 14.909 214.182 15.871 ;
     RECT  23.436 11.507 51.93 16.331 ;
     RECT  52.74 15.871 214.182 16.529 ;
     RECT  0.036 13.085 0.054 16.565 ;
     RECT  126.54 16.529 214.182 16.565 ;
     RECT  126.54 16.565 132.534 18.523 ;
     RECT  133.272 16.565 214.182 18.523 ;
     RECT  126.54 18.523 214.182 18.749 ;
     RECT  126.54 18.749 132.534 18.797 ;
     RECT  5.115 9.391 22.554 18.805 ;
     RECT  23.436 16.331 39.222 18.805 ;
     RECT  52.74 16.529 125.802 18.805 ;
     RECT  52.668 18.805 125.802 20.695 ;
     RECT  126.576 18.797 132.534 20.695 ;
     RECT  5.115 18.805 39.222 20.857 ;
     RECT  39.96 16.331 51.93 20.857 ;
     RECT  133.272 18.749 214.182 20.857 ;
     RECT  5.115 20.857 51.93 20.923 ;
     RECT  52.668 20.695 132.534 20.923 ;
     RECT  133.272 20.857 214.686 21.001 ;
     RECT  5.115 20.923 132.534 21.091 ;
     RECT  133.272 21.001 214.794 21.091 ;
     RECT  5.115 21.091 214.794 21.299 ;
     RECT  5.115 21.299 214.686 22.027 ;
     RECT  4.932 22.027 214.686 22.199 ;
     RECT  4.932 22.199 214.362 22.469 ;
     RECT  4.932 22.469 214.182 22.549 ;
     RECT  4.608 22.549 214.182 22.651 ;
     RECT  4.572 22.651 214.182 22.775 ;
     RECT  4.608 22.775 214.182 22.781 ;
     RECT  2.415 2.413 2.697 23.507 ;
     RECT  215.715 2.413 215.997 23.507 ;
     RECT  4.644 22.781 214.182 23.549 ;
     RECT  4.68 23.549 213.786 23.585 ;
     RECT  4.68 23.585 12.258 23.621 ;
     RECT  14.94 23.585 21.906 23.621 ;
     RECT  42.915 23.585 54.126 23.621 ;
     RECT  54.9 23.585 162.738 23.621 ;
     RECT  163.656 23.585 166.086 23.621 ;
     RECT  42.915 23.621 51.498 23.657 ;
     RECT  201.924 23.585 213.642 23.657 ;
     RECT  22.86 23.585 27.306 23.693 ;
     RECT  41.688 23.585 42.102 23.693 ;
     RECT  177.156 23.585 181.746 23.693 ;
     RECT  182.628 23.585 187.506 23.693 ;
     RECT  193.572 23.585 200.538 23.693 ;
     RECT  4.968 23.621 12.258 23.729 ;
     RECT  14.94 23.621 17.586 23.729 ;
     RECT  23.04 23.693 27.306 23.729 ;
     RECT  169.164 23.585 176.13 23.729 ;
     RECT  182.808 23.693 187.506 23.729 ;
     RECT  201.924 23.657 213.39 23.729 ;
     RECT  5.115 23.729 12.258 23.741 ;
     RECT  12.996 23.585 13.59 23.741 ;
     RECT  14.94 23.729 17.262 23.741 ;
     RECT  18.324 23.621 21.906 23.741 ;
     RECT  23.04 23.729 24.678 23.741 ;
     RECT  25.632 23.729 27.306 23.741 ;
     RECT  28.044 23.585 28.386 23.741 ;
     RECT  29.196 23.585 40.77 23.741 ;
     RECT  41.76 23.693 42.102 23.741 ;
     RECT  42.915 23.657 44.802 23.741 ;
     RECT  45.615 23.657 51.498 23.741 ;
     RECT  52.416 23.621 54.126 23.741 ;
     RECT  54.9 23.621 73.206 23.741 ;
     RECT  74.052 23.621 162.738 23.741 ;
     RECT  164.088 23.621 166.086 23.741 ;
     RECT  166.824 23.585 168.138 23.741 ;
     RECT  169.164 23.729 171.162 23.741 ;
     RECT  172.332 23.729 176.13 23.741 ;
     RECT  177.156 23.693 179.478 23.741 ;
     RECT  180.468 23.693 181.746 23.741 ;
     RECT  182.808 23.729 184.482 23.741 ;
     RECT  185.22 23.729 187.506 23.741 ;
     RECT  188.28 23.585 192.51 23.741 ;
     RECT  193.572 23.693 197.838 23.741 ;
     RECT  198.9 23.693 200.538 23.741 ;
     RECT  201.924 23.729 202.878 23.741 ;
     RECT  203.652 23.729 205.686 23.741 ;
     RECT  206.676 23.729 213.39 23.741 ;
     RECT  2.415 23.507 2.505 23.777 ;
     RECT  5.115 23.741 5.454 23.777 ;
     RECT  7.815 23.741 7.974 23.777 ;
     RECT  10.515 23.741 10.674 23.777 ;
     RECT  13.215 23.741 13.59 23.777 ;
     RECT  21.315 23.741 21.654 23.777 ;
     RECT  32.115 23.741 32.67 23.777 ;
     RECT  34.164 23.741 35.046 23.777 ;
     RECT  40.215 23.741 40.446 23.777 ;
     RECT  42.915 23.741 43.146 23.777 ;
     RECT  45.615 23.741 45.846 23.777 ;
     RECT  48.276 23.741 48.405 23.777 ;
     RECT  51.015 23.741 51.174 23.777 ;
     RECT  53.715 23.741 53.874 23.777 ;
     RECT  56.415 23.741 56.574 23.777 ;
     RECT  59.115 23.741 59.562 23.777 ;
     RECT  61.815 23.741 62.262 23.777 ;
     RECT  64.515 23.741 64.89 23.777 ;
     RECT  86.115 23.741 86.346 23.777 ;
     RECT  88.815 23.741 89.046 23.777 ;
     RECT  90.972 23.741 91.746 23.777 ;
     RECT  94.215 23.741 94.374 23.777 ;
     RECT  96.3 23.741 97.686 23.777 ;
     RECT  102.315 23.741 102.474 23.777 ;
     RECT  126.615 23.741 126.705 23.777 ;
     RECT  129.315 23.741 129.546 23.777 ;
     RECT  132.015 23.741 132.894 23.777 ;
     RECT  137.415 23.741 137.646 23.777 ;
     RECT  140.115 23.741 140.346 23.777 ;
     RECT  142.815 23.741 142.974 23.777 ;
     RECT  145.515 23.741 145.674 23.777 ;
     RECT  148.215 23.741 148.374 23.777 ;
     RECT  150.876 23.741 151.005 23.777 ;
     RECT  153.615 23.741 153.774 23.777 ;
     RECT  156.315 23.741 156.69 23.777 ;
     RECT  159.015 23.741 159.498 23.777 ;
     RECT  161.64 23.741 161.805 23.777 ;
     RECT  167.115 23.741 167.526 23.777 ;
     RECT  177.915 23.741 178.182 23.777 ;
     RECT  183.315 23.741 183.546 23.777 ;
     RECT  186.015 23.741 186.246 23.777 ;
     RECT  188.715 23.741 189.09 23.777 ;
     RECT  191.415 23.741 191.574 23.777 ;
     RECT  194.115 23.741 194.274 23.777 ;
     RECT  199.224 23.741 199.998 23.777 ;
     RECT  207.615 23.741 208.026 23.777 ;
     RECT  212.616 23.741 213.39 23.777 ;
     RECT  215.715 23.507 215.805 23.777 ;
     RECT  13.356 23.777 13.59 23.885 ;
     RECT  15.3 23.741 16.362 23.885 ;
     RECT  18.576 23.741 18.99 23.885 ;
     RECT  21.456 23.777 21.654 23.885 ;
     RECT  32.328 23.777 32.67 23.885 ;
     RECT  35.028 23.777 35.046 23.885 ;
     RECT  37.44 23.741 37.782 23.885 ;
     RECT  40.428 23.777 40.446 23.885 ;
     RECT  59.256 23.777 59.562 23.885 ;
     RECT  61.956 23.777 62.262 23.885 ;
     RECT  64.656 23.777 64.89 23.885 ;
     RECT  67.176 23.741 67.59 23.885 ;
     RECT  69.876 23.741 70.254 23.885 ;
     RECT  72.576 23.741 72.954 23.885 ;
     RECT  75.204 23.741 75.582 23.885 ;
     RECT  77.94 23.741 78.282 23.885 ;
     RECT  80.64 23.741 80.982 23.885 ;
     RECT  83.34 23.741 83.682 23.885 ;
     RECT  104.976 23.741 105.39 23.885 ;
     RECT  110.376 23.741 110.79 23.885 ;
     RECT  113.076 23.741 113.49 23.885 ;
     RECT  115.776 23.741 116.19 23.885 ;
     RECT  118.476 23.741 118.854 23.885 ;
     RECT  121.176 23.741 121.554 23.885 ;
     RECT  123.84 23.741 124.182 23.885 ;
     RECT  129.528 23.777 129.546 23.885 ;
     RECT  132.228 23.777 132.894 23.885 ;
     RECT  134.64 23.741 134.946 23.885 ;
     RECT  137.628 23.777 137.646 23.885 ;
     RECT  156.456 23.777 156.69 23.885 ;
     RECT  164.376 23.741 164.574 23.885 ;
     RECT  167.256 23.777 167.526 23.885 ;
     RECT  169.776 23.741 170.154 23.885 ;
     RECT  172.332 23.741 173.07 23.885 ;
     RECT  175.104 23.741 175.554 23.885 ;
     RECT  178.164 23.777 178.182 23.885 ;
     RECT  180.468 23.741 180.846 23.885 ;
     RECT  199.98 23.777 199.998 23.885 ;
     RECT  204.876 23.741 205.578 23.885 ;
     RECT  207.756 23.777 208.026 23.885 ;
     RECT  210.276 23.741 210.906 23.885 ;
     RECT  213.372 23.777 213.39 23.885 ;
     RECT  5.436 23.777 5.454 23.933 ;
     RECT  7.956 23.777 7.974 23.933 ;
     RECT  10.656 23.777 10.674 23.933 ;
     RECT  13.356 23.885 13.374 23.933 ;
     RECT  15.3 23.885 15.858 23.933 ;
     RECT  18.576 23.885 18.594 23.933 ;
     RECT  21.456 23.885 21.474 23.933 ;
     RECT  23.976 23.741 24.678 23.933 ;
     RECT  26.064 23.741 27.306 23.933 ;
     RECT  29.196 23.741 29.646 23.933 ;
     RECT  32.652 23.885 32.67 23.933 ;
     RECT  43.128 23.777 43.146 23.933 ;
     RECT  45.828 23.777 45.846 23.933 ;
     RECT  48.276 23.777 48.294 23.933 ;
     RECT  51.156 23.777 51.174 23.933 ;
     RECT  53.856 23.777 53.874 23.933 ;
     RECT  56.556 23.777 56.574 23.933 ;
     RECT  59.256 23.885 59.274 23.933 ;
     RECT  61.956 23.885 61.974 23.933 ;
     RECT  64.656 23.885 64.674 23.933 ;
     RECT  67.176 23.885 67.194 23.933 ;
     RECT  69.876 23.885 69.894 23.933 ;
     RECT  86.328 23.777 86.346 23.933 ;
     RECT  89.028 23.777 89.046 23.933 ;
     RECT  90.972 23.777 90.99 23.933 ;
     RECT  91.728 23.777 91.746 23.933 ;
     RECT  94.356 23.777 94.374 23.933 ;
     RECT  97.056 23.777 97.686 23.933 ;
     RECT  99.576 23.741 100.062 23.933 ;
     RECT  102.456 23.777 102.474 23.933 ;
     RECT  104.976 23.885 104.994 23.933 ;
     RECT  107.676 23.741 108.054 23.933 ;
     RECT  110.376 23.885 110.394 23.933 ;
     RECT  113.076 23.885 113.094 23.933 ;
     RECT  115.776 23.885 115.794 23.933 ;
     RECT  118.476 23.885 118.494 23.933 ;
     RECT  121.176 23.885 121.194 23.933 ;
     RECT  132.876 23.885 132.894 23.933 ;
     RECT  140.328 23.777 140.346 23.933 ;
     RECT  142.956 23.777 142.974 23.933 ;
     RECT  145.656 23.777 145.674 23.933 ;
     RECT  148.356 23.777 148.374 23.933 ;
     RECT  150.876 23.777 150.894 23.933 ;
     RECT  153.756 23.777 153.774 23.933 ;
     RECT  156.456 23.885 156.474 23.933 ;
     RECT  159.156 23.777 159.498 23.933 ;
     RECT  161.64 23.777 161.658 23.933 ;
     RECT  164.376 23.885 164.394 23.933 ;
     RECT  167.256 23.885 167.274 23.933 ;
     RECT  172.404 23.885 173.07 23.933 ;
     RECT  174.024 23.741 174.042 23.933 ;
     RECT  175.104 23.885 175.122 23.933 ;
     RECT  179.172 23.741 179.478 23.933 ;
     RECT  180.468 23.885 180.486 23.933 ;
     RECT  183.528 23.777 183.546 23.933 ;
     RECT  186.228 23.777 186.246 23.933 ;
     RECT  189.072 23.777 189.09 23.933 ;
     RECT  191.556 23.777 191.574 23.933 ;
     RECT  194.256 23.777 194.274 23.933 ;
     RECT  196.776 23.741 197.226 23.933 ;
     RECT  202.176 23.741 202.878 23.933 ;
     RECT  204.876 23.885 204.894 23.933 ;
     RECT  207.756 23.885 207.774 23.933 ;
     RECT  210.276 23.885 210.294 23.933 ;
     RECT  212.616 23.777 212.634 23.933 ;
     RECT  172.404 23.933 172.422 23.981 ;
     RECT  15.3 23.933 15.318 24.557 ;
     RECT  27.288 23.933 27.306 24.557 ;
     RECT  34.164 23.777 34.182 24.557 ;
     RECT  184.464 23.741 184.482 24.557 ;
     RECT  190.224 23.741 190.242 24.557 ;
     RECT  199.224 23.777 199.242 24.557 ;
     RECT  26.064 23.933 26.082 25.085 ;
     RECT  80.892 23.885 80.91 25.085 ;
     RECT  159.48 23.933 159.498 25.085 ;
     RECT  29.628 23.933 29.646 25.133 ;
     RECT  35.892 23.741 35.91 25.133 ;
     RECT  96.3 23.777 96.318 25.133 ;
     RECT  179.46 23.933 179.478 25.133 ;
     RECT  197.208 23.933 197.226 25.133 ;
    LAYER M4 ;
     RECT  0.025 13.056 0.156 13.08 ;
     RECT  0.156 12.96 0.245 13.08 ;
     RECT  2.408 2.148 2.512 23.772 ;
     RECT  2.512 2.418 2.704 23.502 ;
     RECT  4.501 22.656 4.597 22.68 ;
     RECT  4.481 1.728 4.645 1.752 ;
     RECT  4.597 22.656 4.837 22.776 ;
     RECT  4.837 22.656 4.921 23.4 ;
     RECT  4.645 1.728 5.108 2.568 ;
     RECT  4.921 22.032 5.108 23.4 ;
     RECT  5.108 1.728 5.173 23.772 ;
     RECT  5.173 0.192 5.284 0.216 ;
     RECT  5.284 0.192 5.285 0.264 ;
     RECT  5.173 1.728 5.404 23.928 ;
     RECT  5.404 21.168 5.465 23.928 ;
     RECT  5.285 0.24 5.645 0.264 ;
     RECT  5.404 8.544 6.329 8.568 ;
     RECT  5.404 1.728 6.505 2.568 ;
     RECT  6.505 1.68 6.865 2.568 ;
     RECT  6.865 1.584 7.117 2.568 ;
     RECT  6.793 7.632 7.333 7.656 ;
     RECT  7.117 1.584 7.405 3.336 ;
     RECT  5.404 5.28 7.669 5.496 ;
     RECT  7.405 1.584 7.808 4.2 ;
     RECT  7.669 5.184 7.808 5.496 ;
     RECT  7.333 7.632 7.808 8.184 ;
     RECT  5.465 21.168 7.808 23.736 ;
     RECT  7.808 1.584 7.861 23.772 ;
     RECT  7.621 0.288 7.907 0.312 ;
     RECT  7.861 1.584 7.985 23.928 ;
     RECT  7.985 1.584 8.104 23.736 ;
     RECT  8.104 1.584 8.165 5.496 ;
     RECT  8.869 0.192 9.137 0.216 ;
     RECT  8.165 1.584 10.309 5.304 ;
     RECT  10.309 0.288 10.349 0.312 ;
     RECT  10.309 1.584 10.349 5.496 ;
     RECT  10.349 0.288 10.433 5.496 ;
     RECT  10.433 1.584 10.508 5.496 ;
     RECT  8.104 7.632 10.508 7.656 ;
     RECT  8.104 20.64 10.508 23.736 ;
     RECT  10.433 0.288 10.547 0.312 ;
     RECT  10.508 1.584 10.549 23.772 ;
     RECT  10.549 1.584 10.685 23.928 ;
     RECT  10.685 1.584 10.804 23.736 ;
     RECT  10.804 1.584 10.829 4.2 ;
     RECT  10.804 5.184 10.973 5.736 ;
     RECT  10.973 5.28 11.945 5.736 ;
     RECT  11.945 5.28 12.373 5.544 ;
     RECT  10.829 1.68 13.045 4.2 ;
     RECT  10.804 20.64 13.189 23.736 ;
     RECT  13.045 1.392 13.208 4.2 ;
     RECT  12.373 5.184 13.208 5.544 ;
     RECT  10.804 7.632 13.208 7.656 ;
     RECT  13.189 20.64 13.208 23.928 ;
     RECT  13.208 1.392 13.385 23.928 ;
     RECT  13.385 1.392 13.504 23.88 ;
     RECT  13.504 1.392 13.517 1.8 ;
     RECT  13.517 0.576 13.565 1.8 ;
     RECT  13.504 20.64 13.612 23.88 ;
     RECT  13.565 0.576 13.849 1.752 ;
     RECT  13.849 0.192 14.681 1.752 ;
     RECT  13.612 20.64 14.869 23.448 ;
     RECT  13.504 7.632 14.893 7.656 ;
     RECT  14.869 20.64 15.289 23.736 ;
     RECT  15.289 20.64 15.587 24.552 ;
     RECT  14.681 0.576 15.877 1.752 ;
     RECT  15.877 0.576 15.908 1.8 ;
     RECT  13.504 2.832 15.908 4.2 ;
     RECT  13.504 5.184 15.908 6.168 ;
     RECT  14.893 7.344 15.908 7.656 ;
     RECT  15.587 20.64 15.908 23.928 ;
     RECT  15.908 0.576 15.923 23.928 ;
     RECT  15.923 0.576 16.021 23.88 ;
     RECT  16.021 0.288 16.204 23.88 ;
     RECT  16.204 20.64 16.373 23.88 ;
     RECT  16.204 0.288 16.451 7.656 ;
     RECT  16.451 0.816 17.273 7.656 ;
     RECT  17.273 0.816 17.957 4.2 ;
     RECT  16.373 20.64 18.524 23.736 ;
     RECT  17.957 1.392 18.608 4.2 ;
     RECT  17.273 5.184 18.608 7.656 ;
     RECT  18.524 20.64 18.608 23.928 ;
     RECT  18.608 1.392 18.611 23.928 ;
     RECT  18.709 0.192 18.817 0.312 ;
     RECT  18.611 1.392 18.904 23.88 ;
     RECT  18.904 20.64 19.001 23.88 ;
     RECT  18.817 0.048 19.381 0.312 ;
     RECT  18.904 1.392 19.381 7.656 ;
     RECT  19.381 0.048 19.577 7.656 ;
     RECT  19.001 20.64 19.955 23.736 ;
     RECT  19.955 20.64 20.917 22.488 ;
     RECT  19.955 23.712 20.917 23.736 ;
     RECT  20.917 20.64 21.253 23.736 ;
     RECT  19.577 0.048 21.308 4.2 ;
     RECT  19.577 5.184 21.308 7.656 ;
     RECT  18.904 8.784 21.308 8.808 ;
     RECT  21.253 20.64 21.308 23.928 ;
     RECT  21.308 0.048 21.485 23.928 ;
     RECT  21.485 0.048 21.604 23.88 ;
     RECT  21.604 20.64 21.676 23.88 ;
     RECT  21.676 20.64 21.971 23.736 ;
     RECT  21.604 8.784 22.777 8.808 ;
     RECT  22.777 8.688 22.817 8.808 ;
     RECT  21.971 20.64 22.933 23.4 ;
     RECT  22.817 8.688 23.893 8.712 ;
     RECT  22.933 20.64 23.941 23.736 ;
     RECT  21.604 0.048 24.008 7.656 ;
     RECT  23.893 8.688 24.008 8.808 ;
     RECT  23.941 20.64 24.008 23.928 ;
     RECT  24.008 0.048 24.304 23.928 ;
     RECT  24.304 20.64 24.995 23.928 ;
     RECT  24.995 20.64 25.373 23.736 ;
     RECT  25.373 23.712 25.667 23.736 ;
     RECT  26.053 25.056 26.339 25.08 ;
     RECT  24.304 0.048 26.708 7.656 ;
     RECT  24.304 8.784 26.708 8.808 ;
     RECT  25.373 20.64 26.708 22.728 ;
     RECT  25.957 23.904 26.708 23.928 ;
     RECT  26.708 0.048 27.004 23.928 ;
     RECT  27.004 20.64 27.277 23.928 ;
     RECT  27.277 20.64 27.388 24.552 ;
     RECT  27.388 23.712 27.683 24.552 ;
     RECT  27.388 20.64 28.645 22.488 ;
     RECT  27.683 23.712 28.645 23.736 ;
     RECT  28.645 20.64 29.185 23.736 ;
     RECT  29.077 11.952 29.293 11.976 ;
     RECT  29.185 20.64 29.363 23.928 ;
     RECT  27.004 0.048 29.408 8.808 ;
     RECT  27.004 10.944 29.408 10.968 ;
     RECT  29.293 11.952 29.408 12.552 ;
     RECT  29.363 20.64 29.408 23.772 ;
     RECT  29.408 0.048 29.512 23.772 ;
     RECT  29.612 25.104 29.699 25.128 ;
     RECT  29.512 0.048 29.704 23.736 ;
     RECT  29.704 20.64 30.275 23.736 ;
     RECT  29.704 0.048 30.769 8.712 ;
     RECT  29.704 10.848 30.769 10.872 ;
     RECT  30.769 10.848 30.809 10.968 ;
     RECT  30.769 0.048 31.385 8.808 ;
     RECT  31.385 0.24 32.108 8.808 ;
     RECT  30.809 10.944 32.108 10.968 ;
     RECT  29.704 11.952 32.108 12.552 ;
     RECT  31.345 13.68 32.108 13.704 ;
     RECT  30.275 20.88 32.108 23.736 ;
     RECT  32.108 0.24 32.293 23.772 ;
     RECT  32.293 0.24 32.404 23.88 ;
     RECT  32.404 20.88 32.597 23.88 ;
     RECT  32.597 20.88 32.681 23.928 ;
     RECT  32.404 0.24 33.589 8.808 ;
     RECT  32.681 20.88 34.153 23.736 ;
     RECT  34.153 20.88 34.355 24.552 ;
     RECT  33.589 0.192 34.597 8.808 ;
     RECT  34.597 0.192 34.808 9.336 ;
     RECT  32.404 10.944 34.808 10.968 ;
     RECT  32.404 11.952 34.808 12.552 ;
     RECT  32.404 13.68 34.808 13.704 ;
     RECT  34.355 20.88 34.808 23.88 ;
     RECT  34.808 0.192 35.068 23.88 ;
     RECT  35.068 0.192 35.104 23.736 ;
     RECT  35.881 25.104 36.035 25.128 ;
     RECT  35.104 0.192 36.085 9.576 ;
     RECT  36.085 0.192 36.889 9.624 ;
     RECT  35.104 20.88 37.333 23.736 ;
     RECT  36.889 0.096 37.508 9.624 ;
     RECT  35.104 10.944 37.508 10.968 ;
     RECT  35.104 11.952 37.508 12.552 ;
     RECT  35.104 13.68 37.508 13.704 ;
     RECT  37.333 20.88 37.508 23.88 ;
     RECT  37.508 0.096 37.793 23.88 ;
     RECT  37.793 0.096 37.804 23.736 ;
     RECT  37.804 20.832 38.801 23.736 ;
     RECT  37.804 11.952 39.445 12.552 ;
     RECT  37.804 13.68 39.445 13.704 ;
     RECT  37.804 0.096 40.208 10.968 ;
     RECT  39.445 11.952 40.208 13.704 ;
     RECT  38.801 20.88 40.208 23.736 ;
     RECT  40.208 0.096 40.357 23.772 ;
     RECT  40.357 0.096 40.457 23.88 ;
     RECT  40.457 0.096 40.504 23.736 ;
     RECT  40.504 0.096 42.908 13.704 ;
     RECT  42.277 15.552 42.908 15.576 ;
     RECT  42.469 16.848 42.908 16.872 ;
     RECT  40.504 20.88 42.908 23.736 ;
     RECT  42.908 0.096 43.045 23.772 ;
     RECT  43.045 0.096 43.157 23.928 ;
     RECT  43.157 0.096 43.204 23.736 ;
     RECT  43.204 20.88 43.913 23.736 ;
     RECT  43.204 0.096 44.629 13.704 ;
     RECT  43.913 20.88 45.061 22.536 ;
     RECT  43.913 23.712 45.061 23.736 ;
     RECT  44.629 0.096 45.157 14.52 ;
     RECT  43.204 15.552 45.157 15.576 ;
     RECT  45.157 0.096 45.608 15.576 ;
     RECT  43.204 16.848 45.608 17.208 ;
     RECT  45.061 20.88 45.608 23.736 ;
     RECT  45.608 0.096 45.733 23.772 ;
     RECT  45.733 0.096 45.857 23.928 ;
     RECT  45.857 0.096 45.904 23.736 ;
     RECT  45.904 20.832 46.793 23.736 ;
     RECT  46.793 20.88 48.265 23.736 ;
     RECT  45.904 0.096 48.308 15.816 ;
     RECT  45.904 16.848 48.308 17.448 ;
     RECT  48.265 20.88 48.308 23.928 ;
     RECT  48.308 0.096 48.467 23.928 ;
     RECT  48.467 0.096 48.604 23.736 ;
     RECT  48.604 20.832 49.043 23.736 ;
     RECT  49.043 20.832 50.053 21.192 ;
     RECT  49.043 22.272 50.053 23.736 ;
     RECT  50.053 20.832 50.533 23.736 ;
     RECT  48.604 0.096 51.008 17.448 ;
     RECT  50.485 19.008 51.008 19.032 ;
     RECT  50.533 20.592 51.008 23.736 ;
     RECT  51.008 0.096 51.061 23.772 ;
     RECT  51.061 0.096 51.185 23.928 ;
     RECT  51.185 0.096 51.304 23.736 ;
     RECT  51.304 20.88 52.157 23.736 ;
     RECT  51.304 19.008 52.645 19.272 ;
     RECT  51.304 0.096 53.708 17.448 ;
     RECT  52.645 18.528 53.708 19.272 ;
     RECT  52.157 20.88 53.708 22.536 ;
     RECT  52.157 23.712 53.708 23.736 ;
     RECT  53.708 0.096 53.749 23.772 ;
     RECT  53.749 0.096 53.885 23.928 ;
     RECT  53.885 0.096 54.004 23.736 ;
     RECT  54.004 18.528 54.131 19.272 ;
     RECT  54.131 18.672 54.749 19.272 ;
     RECT  54.004 0.096 55.525 17.448 ;
     RECT  54.749 18.768 56.005 19.272 ;
     RECT  56.005 18.72 56.197 19.272 ;
     RECT  55.525 0.096 56.408 17.64 ;
     RECT  56.197 18.72 56.408 19.896 ;
     RECT  54.004 20.88 56.408 23.736 ;
     RECT  56.408 0.096 56.437 23.772 ;
     RECT  56.437 0.096 56.585 23.928 ;
     RECT  56.585 0.096 56.704 23.736 ;
     RECT  56.704 0.096 58.165 17.64 ;
     RECT  56.704 18.72 58.165 19.896 ;
     RECT  58.165 0.096 58.933 19.896 ;
     RECT  58.933 0.048 59.108 19.896 ;
     RECT  56.704 20.88 59.108 23.736 ;
     RECT  59.108 0.048 59.125 23.772 ;
     RECT  59.125 0.048 59.285 23.928 ;
     RECT  59.285 0.048 59.573 23.88 ;
     RECT  59.573 0.048 59.717 23.736 ;
     RECT  59.717 0.048 60.805 22.536 ;
     RECT  59.717 23.712 60.805 23.736 ;
     RECT  60.805 0.048 61.808 23.736 ;
     RECT  61.808 0.048 61.813 23.772 ;
     RECT  61.813 0.048 61.985 23.928 ;
     RECT  61.985 0.048 62.273 23.88 ;
     RECT  62.273 0.048 62.317 23.736 ;
     RECT  62.317 0.048 63.541 22.488 ;
     RECT  62.317 23.712 63.541 23.736 ;
     RECT  63.541 0.048 64.501 23.736 ;
     RECT  64.501 0.048 64.685 23.928 ;
     RECT  64.685 0.048 64.924 23.88 ;
     RECT  64.924 0.048 67.148 23.736 ;
     RECT  67.148 0.048 67.235 23.928 ;
     RECT  67.235 0.048 67.612 23.88 ;
     RECT  67.612 0.048 69.829 23.736 ;
     RECT  69.829 0.048 69.916 23.928 ;
     RECT  69.916 0.048 70.265 23.88 ;
     RECT  70.265 0.048 72.517 23.736 ;
     RECT  72.517 0.048 72.965 23.88 ;
     RECT  72.965 0.048 75.164 23.736 ;
     RECT  75.164 0.048 75.628 23.88 ;
     RECT  75.628 0.048 77.893 23.736 ;
     RECT  77.893 0.048 78.316 23.88 ;
     RECT  78.316 0.048 80.581 23.736 ;
     RECT  80.876 25.056 80.985 25.08 ;
     RECT  80.581 0.048 80.993 23.88 ;
     RECT  80.993 0.048 83.269 23.736 ;
     RECT  83.269 0.048 83.693 23.88 ;
     RECT  83.693 0.048 86.108 23.736 ;
     RECT  86.108 0.048 86.245 23.772 ;
     RECT  86.245 0.048 86.357 23.928 ;
     RECT  86.357 0.048 88.808 23.736 ;
     RECT  88.808 0.048 88.933 23.772 ;
     RECT  88.933 0.048 89.057 23.928 ;
     RECT  89.057 0.048 90.917 23.736 ;
     RECT  90.917 0.048 91.757 23.928 ;
     RECT  91.757 0.048 94.208 23.736 ;
     RECT  94.208 0.048 94.309 23.772 ;
     RECT  94.309 0.048 94.396 23.928 ;
     RECT  96.284 25.104 96.371 25.128 ;
     RECT  94.396 0.048 96.908 23.736 ;
     RECT  96.908 0.048 96.997 23.772 ;
     RECT  96.997 0.048 97.741 23.928 ;
     RECT  97.741 0.048 99.209 23.736 ;
     RECT  99.209 0.096 99.565 23.736 ;
     RECT  99.565 0.096 100.073 23.928 ;
     RECT  100.073 0.096 102.308 23.736 ;
     RECT  102.308 0.096 102.373 23.772 ;
     RECT  102.373 0.096 102.485 23.928 ;
     RECT  102.485 0.096 102.625 23.736 ;
     RECT  102.625 0.048 104.965 23.736 ;
     RECT  104.965 0.048 105.059 23.928 ;
     RECT  105.059 0.048 105.436 23.88 ;
     RECT  105.436 0.048 107.66 23.736 ;
     RECT  107.66 0.048 108.109 23.928 ;
     RECT  108.109 0.048 110.348 23.736 ;
     RECT  110.348 0.048 110.435 23.928 ;
     RECT  110.435 0.048 110.812 23.88 ;
     RECT  110.812 0.048 113.036 23.736 ;
     RECT  113.036 0.048 113.123 23.928 ;
     RECT  113.123 0.048 113.501 23.88 ;
     RECT  113.501 0.048 115.724 23.736 ;
     RECT  115.724 0.048 115.811 23.928 ;
     RECT  115.811 0.048 116.201 23.88 ;
     RECT  116.201 0.048 118.453 23.736 ;
     RECT  118.453 0.048 118.54 23.928 ;
     RECT  118.54 0.048 118.876 23.88 ;
     RECT  118.876 0.048 121.141 23.736 ;
     RECT  121.141 0.048 121.228 23.928 ;
     RECT  121.228 0.048 121.565 23.88 ;
     RECT  121.565 0.048 123.781 23.736 ;
     RECT  123.781 0.048 124.204 23.88 ;
     RECT  124.204 0.048 126.608 23.736 ;
     RECT  126.608 0.048 126.805 23.772 ;
     RECT  126.805 0.048 127.043 23.88 ;
     RECT  127.043 0.048 129.308 23.736 ;
     RECT  129.308 0.048 129.493 23.772 ;
     RECT  129.493 0.048 129.58 23.88 ;
     RECT  129.58 0.048 132.008 23.736 ;
     RECT  132.008 0.048 132.181 23.772 ;
     RECT  132.181 0.048 132.821 23.88 ;
     RECT  132.821 0.048 132.905 23.928 ;
     RECT  132.905 0.048 134.533 23.736 ;
     RECT  134.533 0.048 134.957 23.88 ;
     RECT  134.957 0.048 137.408 23.736 ;
     RECT  137.408 0.048 137.557 23.772 ;
     RECT  137.557 0.048 137.657 23.88 ;
     RECT  137.657 0.048 140.108 23.736 ;
     RECT  140.108 0.048 140.245 23.772 ;
     RECT  140.245 0.048 140.357 23.928 ;
     RECT  140.357 0.048 142.808 23.736 ;
     RECT  142.808 0.048 142.885 23.772 ;
     RECT  142.885 0.048 142.985 23.928 ;
     RECT  142.985 0.048 145.508 23.736 ;
     RECT  145.508 0.048 145.573 23.772 ;
     RECT  145.573 0.048 145.685 23.928 ;
     RECT  145.685 0.048 148.208 23.736 ;
     RECT  148.208 0.048 148.261 23.772 ;
     RECT  148.261 0.048 148.385 23.928 ;
     RECT  148.385 0.048 150.865 23.736 ;
     RECT  150.865 0.048 150.995 23.928 ;
     RECT  150.995 0.048 151.012 23.772 ;
     RECT  151.012 0.048 151.619 23.736 ;
     RECT  151.619 0.048 152.099 18.024 ;
     RECT  152.099 0.048 153.608 17.736 ;
     RECT  151.619 19.056 153.608 23.736 ;
     RECT  153.608 0.048 153.637 23.772 ;
     RECT  153.637 0.048 153.785 23.928 ;
     RECT  153.785 0.048 153.904 23.736 ;
     RECT  153.904 0.048 154.505 17.784 ;
     RECT  153.904 19.056 154.979 23.736 ;
     RECT  154.505 0.048 156.308 17.736 ;
     RECT  154.979 19.344 156.308 23.736 ;
     RECT  156.308 0.048 156.325 23.772 ;
     RECT  156.325 0.048 156.485 23.928 ;
     RECT  156.485 0.048 156.604 23.88 ;
     RECT  156.604 20.112 156.707 23.88 ;
     RECT  156.707 20.112 156.755 23.736 ;
     RECT  156.604 0.048 157.457 17.736 ;
     RECT  157.457 0.096 158.461 17.736 ;
     RECT  158.461 0.048 159.008 17.736 ;
     RECT  156.755 20.352 159.008 23.736 ;
     RECT  159.008 0.048 159.013 23.772 ;
     RECT  159.013 0.048 159.185 23.928 ;
     RECT  159.185 0.048 159.304 23.88 ;
     RECT  159.304 20.928 159.473 23.88 ;
     RECT  159.304 0.048 159.635 17.688 ;
     RECT  159.469 25.056 159.731 25.08 ;
     RECT  159.473 20.928 161.612 23.736 ;
     RECT  161.612 20.928 161.699 23.928 ;
     RECT  159.635 0.048 161.708 17.448 ;
     RECT  161.699 20.928 161.708 23.88 ;
     RECT  161.708 0.048 162.004 23.88 ;
     RECT  162.004 0.048 162.065 17.448 ;
     RECT  162.004 20.832 162.131 23.88 ;
     RECT  162.131 20.832 162.497 23.736 ;
     RECT  162.065 0.096 162.533 17.448 ;
     RECT  162.497 20.928 162.749 23.736 ;
     RECT  162.749 20.928 164.005 23.448 ;
     RECT  164.005 20.928 164.341 23.736 ;
     RECT  162.533 0.096 164.408 15.768 ;
     RECT  162.533 16.8 164.408 17.448 ;
     RECT  164.341 20.928 164.408 23.928 ;
     RECT  164.408 0.096 164.428 23.928 ;
     RECT  164.428 0.096 164.704 23.88 ;
     RECT  164.704 20.928 164.723 23.88 ;
     RECT  164.704 0.096 165.491 15.576 ;
     RECT  164.704 16.8 165.827 17.448 ;
     RECT  164.723 20.928 167.029 23.736 ;
     RECT  165.491 0.096 167.108 14.952 ;
     RECT  165.827 16.848 167.108 17.448 ;
     RECT  167.029 20.928 167.108 23.928 ;
     RECT  167.108 0.096 167.285 23.928 ;
     RECT  167.285 0.096 167.404 23.88 ;
     RECT  167.404 20.928 167.537 23.88 ;
     RECT  167.404 0.096 168.755 14.76 ;
     RECT  167.537 20.928 169.717 23.736 ;
     RECT  168.755 0.144 169.808 14.76 ;
     RECT  167.404 16.848 169.808 17.4 ;
     RECT  169.717 20.928 169.808 23.88 ;
     RECT  169.808 0.144 170.104 23.88 ;
     RECT  170.104 20.832 170.165 23.88 ;
     RECT  170.165 20.832 171.173 23.736 ;
     RECT  170.104 17.184 171.203 17.4 ;
     RECT  171.173 20.832 172.321 23.496 ;
     RECT  172.321 20.832 172.393 23.88 ;
     RECT  170.104 0.144 172.465 14.76 ;
     RECT  172.465 0.096 172.508 14.76 ;
     RECT  171.203 17.376 172.508 17.4 ;
     RECT  172.393 20.832 172.508 23.976 ;
     RECT  172.508 0.096 172.787 23.976 ;
     RECT  172.787 0.096 172.804 23.928 ;
     RECT  172.804 20.832 174.131 23.928 ;
     RECT  172.804 0.096 174.409 14.76 ;
     RECT  174.131 20.832 175.093 23.736 ;
     RECT  175.093 20.832 175.177 23.928 ;
     RECT  174.409 0.048 175.208 14.76 ;
     RECT  172.804 17.376 175.208 17.4 ;
     RECT  175.177 20.832 175.208 23.88 ;
     RECT  175.208 0.048 175.504 23.88 ;
     RECT  175.504 20.928 175.565 23.88 ;
     RECT  175.504 0.048 175.925 14.76 ;
     RECT  175.565 20.928 176.147 23.736 ;
     RECT  176.147 20.928 177.109 23.4 ;
     RECT  177.109 20.928 177.577 23.736 ;
     RECT  175.925 0.048 177.908 12.552 ;
     RECT  175.925 13.584 177.908 14.76 ;
     RECT  175.504 17.376 177.908 17.4 ;
     RECT  177.577 20.688 177.908 23.736 ;
     RECT  177.908 0.048 178.117 23.772 ;
     RECT  178.117 0.048 178.204 23.88 ;
     RECT  178.204 0.048 178.355 12.36 ;
     RECT  178.204 20.592 179.077 23.88 ;
     RECT  179.077 20.592 179.201 23.928 ;
     RECT  178.355 0.048 179.669 10.968 ;
     RECT  179.449 25.104 179.795 25.128 ;
     RECT  179.201 20.592 180.413 23.4 ;
     RECT  180.413 20.592 180.497 23.928 ;
     RECT  179.669 0.096 180.608 10.968 ;
     RECT  178.355 12.048 180.608 12.36 ;
     RECT  178.204 13.584 180.608 14.76 ;
     RECT  178.204 17.376 180.608 17.4 ;
     RECT  180.497 20.592 180.608 23.88 ;
     RECT  180.608 0.096 180.857 23.88 ;
     RECT  180.857 0.096 180.904 23.736 ;
     RECT  180.904 0.096 180.925 10.968 ;
     RECT  180.904 13.584 181.397 14.76 ;
     RECT  180.904 20.592 181.811 23.736 ;
     RECT  181.811 20.592 182.773 23.4 ;
     RECT  180.925 0.048 183.308 10.968 ;
     RECT  180.904 12.048 183.308 12.36 ;
     RECT  181.397 13.584 183.308 14.52 ;
     RECT  180.904 17.376 183.308 17.4 ;
     RECT  182.773 20.592 183.308 23.736 ;
     RECT  183.308 0.048 183.445 23.772 ;
     RECT  183.445 0.048 183.604 23.928 ;
     RECT  183.604 20.592 183.827 23.928 ;
     RECT  183.827 23.712 184.453 23.928 ;
     RECT  184.453 23.712 184.835 24.552 ;
     RECT  183.827 20.592 185.797 22.536 ;
     RECT  184.835 23.712 185.797 23.736 ;
     RECT  183.604 0.048 186.008 10.968 ;
     RECT  183.604 12.048 186.008 12.36 ;
     RECT  183.604 13.584 186.008 14.52 ;
     RECT  183.604 17.376 186.008 17.4 ;
     RECT  185.797 20.592 186.008 23.736 ;
     RECT  186.008 0.048 186.133 23.772 ;
     RECT  186.133 0.048 186.257 23.928 ;
     RECT  186.257 0.048 186.304 23.736 ;
     RECT  186.304 10.32 186.905 10.968 ;
     RECT  186.304 20.592 187.013 23.736 ;
     RECT  186.304 0.048 188.708 9.144 ;
     RECT  186.905 10.32 188.708 10.344 ;
     RECT  186.304 12.048 188.708 12.36 ;
     RECT  186.304 13.584 188.708 14.52 ;
     RECT  186.304 17.376 188.708 17.4 ;
     RECT  187.013 20.88 188.708 23.736 ;
     RECT  188.708 0.048 188.821 23.772 ;
     RECT  188.821 0.048 189.004 23.928 ;
     RECT  189.004 20.832 189.101 23.928 ;
     RECT  189.004 0.048 189.587 9.144 ;
     RECT  189.101 20.832 189.605 23.736 ;
     RECT  189.004 13.584 189.821 14.52 ;
     RECT  189.587 7.152 190.393 9.144 ;
     RECT  189.587 0.048 190.433 6.168 ;
     RECT  189.821 14.352 190.433 14.52 ;
     RECT  190.213 24.528 190.547 24.552 ;
     RECT  189.605 20.832 190.837 23.4 ;
     RECT  190.433 0.048 191.408 6.072 ;
     RECT  190.393 7.152 191.408 9.288 ;
     RECT  189.004 10.32 191.408 10.344 ;
     RECT  189.004 12.048 191.408 12.072 ;
     RECT  190.433 14.448 191.408 14.52 ;
     RECT  189.004 17.376 191.408 17.4 ;
     RECT  190.837 20.832 191.408 23.772 ;
     RECT  191.408 0.048 191.509 23.772 ;
     RECT  191.509 0.048 191.596 23.928 ;
     RECT  191.596 0.048 191.704 23.736 ;
     RECT  191.704 7.344 192.125 9.288 ;
     RECT  191.704 20.928 192.563 23.736 ;
     RECT  192.563 20.928 192.737 23.448 ;
     RECT  192.737 21.024 192.755 23.448 ;
     RECT  192.755 21.12 193.525 23.448 ;
     RECT  191.704 0.048 194.108 6.072 ;
     RECT  192.125 7.632 194.108 9.288 ;
     RECT  191.704 10.32 194.108 10.344 ;
     RECT  191.704 12.048 194.108 12.072 ;
     RECT  191.704 14.448 194.108 14.52 ;
     RECT  191.704 17.376 194.108 17.4 ;
     RECT  193.525 21.12 194.108 23.736 ;
     RECT  194.108 0.048 194.197 23.772 ;
     RECT  194.197 0.048 194.285 23.928 ;
     RECT  194.285 0.048 194.404 23.736 ;
     RECT  194.404 7.152 194.609 9.144 ;
     RECT  194.404 0.048 195.011 6.072 ;
     RECT  194.404 21.12 196.765 23.736 ;
     RECT  195.011 0.096 196.808 6.072 ;
     RECT  194.609 7.632 196.808 9.144 ;
     RECT  194.404 10.32 196.808 10.344 ;
     RECT  194.404 12.048 196.808 12.072 ;
     RECT  194.404 14.448 196.808 14.52 ;
     RECT  196.765 21.12 196.808 23.928 ;
     RECT  196.808 0.096 196.883 23.928 ;
     RECT  196.883 0.096 196.912 23.772 ;
     RECT  196.912 0.096 197.104 23.736 ;
     RECT  197.197 25.104 197.555 25.128 ;
     RECT  197.104 21.12 197.597 23.736 ;
     RECT  197.597 21.264 197.891 23.736 ;
     RECT  197.104 0.096 198.133 6.168 ;
     RECT  197.104 12.048 198.353 12.072 ;
     RECT  197.104 14.352 198.389 14.52 ;
     RECT  197.891 21.264 198.853 23.4 ;
     RECT  198.853 21.264 199.213 23.736 ;
     RECT  199.213 21.264 199.321 24.552 ;
     RECT  198.133 0.096 199.508 6.312 ;
     RECT  197.104 7.632 199.508 7.944 ;
     RECT  197.104 9.024 199.508 9.144 ;
     RECT  198.389 14.448 199.508 14.52 ;
     RECT  199.321 21.168 199.508 24.552 ;
     RECT  199.508 0.096 199.523 24.552 ;
     RECT  199.523 0.192 199.571 24.552 ;
     RECT  199.571 0.192 199.804 23.88 ;
     RECT  199.804 0.192 199.955 6.072 ;
     RECT  199.804 23.712 200.009 23.88 ;
     RECT  200.009 23.712 200.579 23.736 ;
     RECT  199.955 0.576 200.765 6.072 ;
     RECT  199.804 21.168 200.869 22.488 ;
     RECT  200.765 0.576 200.963 5.496 ;
     RECT  200.869 21.168 201.877 23.4 ;
     RECT  201.877 21.168 201.884 23.736 ;
     RECT  200.963 0.816 202.115 5.496 ;
     RECT  201.884 20.976 202.165 23.736 ;
     RECT  202.115 2.148 202.208 5.496 ;
     RECT  199.804 7.632 202.208 7.944 ;
     RECT  199.804 9.024 202.208 9.144 ;
     RECT  199.804 14.448 202.208 14.52 ;
     RECT  202.165 20.976 202.208 23.928 ;
     RECT  202.208 2.148 202.312 23.928 ;
     RECT  202.115 0.816 202.405 1.128 ;
     RECT  202.312 2.208 202.504 23.928 ;
     RECT  202.405 0.192 202.565 1.128 ;
     RECT  202.565 0.816 202.787 1.128 ;
     RECT  202.504 21.12 202.933 23.928 ;
     RECT  202.504 2.208 203.123 5.496 ;
     RECT  202.504 14.448 203.321 14.52 ;
     RECT  202.504 6.816 203.651 7.752 ;
     RECT  202.787 0.816 203.795 0.84 ;
     RECT  203.893 0.576 204.145 0.648 ;
     RECT  202.933 21.12 204.421 23.736 ;
     RECT  204.145 0.528 204.541 0.648 ;
     RECT  204.541 0.192 204.625 0.648 ;
     RECT  204.044 1.68 204.757 1.704 ;
     RECT  203.123 2.832 204.757 5.496 ;
     RECT  204.421 20.976 204.86 23.736 ;
     RECT  204.625 0.528 204.865 0.648 ;
     RECT  204.757 1.68 204.865 5.496 ;
     RECT  204.865 0.528 204.908 5.496 ;
     RECT  203.651 7.632 204.908 7.752 ;
     RECT  202.504 9.024 204.908 9.144 ;
     RECT  203.321 14.448 204.908 14.472 ;
     RECT  204.86 20.976 204.908 23.928 ;
     RECT  204.908 0.528 204.947 23.928 ;
     RECT  204.947 0.528 205.204 23.88 ;
     RECT  205.204 7.728 205.301 7.896 ;
     RECT  205.204 14.352 205.301 14.472 ;
     RECT  205.204 0.528 205.481 1.752 ;
     RECT  205.204 20.976 205.589 23.88 ;
     RECT  205.481 0.528 205.619 1.704 ;
     RECT  205.301 7.872 206.341 7.896 ;
     RECT  205.301 14.352 206.341 14.376 ;
     RECT  205.589 20.976 206.345 23.736 ;
     RECT  205.204 2.736 206.381 5.496 ;
     RECT  206.341 7.728 206.381 7.896 ;
     RECT  206.341 14.352 206.381 14.472 ;
     RECT  206.345 20.976 207.445 22.536 ;
     RECT  206.345 23.712 207.445 23.736 ;
     RECT  205.619 1.056 207.589 1.704 ;
     RECT  207.445 20.976 207.589 23.736 ;
     RECT  207.589 0.192 207.608 1.704 ;
     RECT  206.381 2.832 207.608 5.496 ;
     RECT  206.381 7.728 207.608 7.752 ;
     RECT  205.204 9.024 207.608 9.144 ;
     RECT  206.381 14.448 207.608 14.472 ;
     RECT  207.589 20.976 207.608 23.928 ;
     RECT  207.608 0.192 207.785 23.928 ;
     RECT  207.785 0.576 207.827 23.88 ;
     RECT  207.827 2.256 207.904 23.88 ;
     RECT  207.904 21.216 208.037 23.88 ;
     RECT  207.827 0.576 208.163 1.128 ;
     RECT  207.904 2.256 208.307 5.496 ;
     RECT  208.163 0.576 209.105 0.6 ;
     RECT  209.105 0.192 209.185 0.6 ;
     RECT  208.307 2.832 209.545 5.496 ;
     RECT  208.037 21.216 209.869 23.736 ;
     RECT  209.185 0.192 210.085 1.128 ;
     RECT  209.869 20.976 210.236 23.736 ;
     RECT  209.545 2.256 210.308 5.496 ;
     RECT  207.904 7.728 210.308 7.752 ;
     RECT  207.904 9.024 210.308 9.048 ;
     RECT  207.904 14.448 210.308 14.472 ;
     RECT  210.236 20.976 210.308 23.928 ;
     RECT  210.308 2.148 210.323 23.928 ;
     RECT  210.085 0.192 210.445 1.176 ;
     RECT  210.323 2.148 210.445 23.88 ;
     RECT  210.445 0.192 210.467 23.88 ;
     RECT  210.467 1.68 210.604 23.88 ;
     RECT  210.604 20.976 210.701 23.88 ;
     RECT  210.701 22.224 210.917 23.88 ;
     RECT  210.604 14.448 211.025 14.472 ;
     RECT  210.467 0.192 211.331 0.216 ;
     RECT  210.604 3.696 211.493 5.496 ;
     RECT  211.493 4.224 211.529 5.496 ;
     RECT  210.604 9.024 211.601 9.048 ;
     RECT  210.604 1.68 211.765 2.28 ;
     RECT  211.529 5.472 211.781 5.496 ;
     RECT  211.765 1.68 211.961 2.328 ;
     RECT  211.961 1.68 212.317 1.752 ;
     RECT  210.917 22.224 212.605 23.736 ;
     RECT  212.317 1.104 212.675 1.752 ;
     RECT  212.749 0.576 212.833 0.6 ;
     RECT  212.929 0.528 212.965 0.552 ;
     RECT  212.675 1.728 213.008 1.752 ;
     RECT  211.529 4.224 213.008 4.248 ;
     RECT  210.604 7.728 213.008 7.752 ;
     RECT  210.701 20.976 213.008 21 ;
     RECT  212.605 22.224 213.008 23.928 ;
     RECT  213.008 1.728 213.011 23.928 ;
     RECT  213.011 1.728 213.304 23.88 ;
     RECT  212.965 0.192 213.347 0.552 ;
     RECT  213.304 7.728 213.365 7.752 ;
     RECT  213.304 22.224 213.401 22.248 ;
     RECT  213.304 23.376 213.401 23.88 ;
     RECT  213.304 4.224 213.437 4.248 ;
     RECT  213.347 0.192 213.581 0.216 ;
     RECT  213.304 1.728 213.697 1.752 ;
     RECT  213.401 23.376 213.761 23.4 ;
     RECT  213.304 20.976 213.833 21 ;
     RECT  215.708 2.148 215.812 23.772 ;
     RECT  215.812 2.418 216.004 23.502 ;
    LAYER M5 ;
     RECT  21.984 0.085 22.008 0.144 ;
     RECT  41.376 0.133 41.4 0.144 ;
     RECT  58.944 0.037 58.968 0.144 ;
     RECT  61.296 0.085 61.32 0.144 ;
     RECT  76.176 0.133 76.2 0.144 ;
     RECT  84.192 0.133 84.216 0.144 ;
     RECT  105.936 0.037 105.96 0.144 ;
     RECT  107.616 0.085 107.64 0.144 ;
     RECT  127.92 0.133 127.944 0.144 ;
     RECT  140.784 0.133 140.808 0.144 ;
     RECT  148.8 0.085 148.824 0.144 ;
     RECT  154.176 0.085 154.2 0.144 ;
     RECT  168.72 0.085 168.744 0.144 ;
     RECT  174.24 0.133 174.264 0.144 ;
     RECT  184.944 0.133 184.968 0.144 ;
     RECT  194.976 0.037 195 0.144 ;
     RECT  199.488 0.085 199.512 0.144 ;
     RECT  4.512 0.144 213.672 0.275 ;
     RECT  4.512 0.275 87.816 0.467 ;
     RECT  88.8 0.275 105.048 0.515 ;
     RECT  4.512 0.467 83.784 0.563 ;
     RECT  84.96 0.467 87.816 0.563 ;
     RECT  96.336 0.515 105.048 0.563 ;
     RECT  106.032 0.275 213.672 0.563 ;
     RECT  141.024 0.563 213.672 0.659 ;
     RECT  88.8 0.515 95.352 0.803 ;
     RECT  4.512 0.563 72.12 0.899 ;
     RECT  141.024 0.659 204.12 0.899 ;
     RECT  89.184 0.803 95.352 1.043 ;
     RECT  96.672 0.563 102.216 1.091 ;
     RECT  106.032 0.563 131.688 1.139 ;
     RECT  73.728 0.563 83.64 1.187 ;
     RECT  103.2 0.563 103.896 1.715 ;
     RECT  185.712 0.899 204.12 1.715 ;
     RECT  4.512 0.899 33.48 1.763 ;
     RECT  141.024 0.899 184.536 1.763 ;
     RECT  185.856 1.715 197.256 1.763 ;
     RECT  205.104 0.659 213.672 1.763 ;
     RECT  4.656 1.763 13.512 1.955 ;
     RECT  12.192 1.955 13.512 2.003 ;
     RECT  205.104 1.763 210.648 2.051 ;
     RECT  34.464 0.899 72.12 2.137 ;
     RECT  89.184 1.043 95.16 2.137 ;
     RECT  96.672 1.091 99.336 2.137 ;
     RECT  100.32 1.091 102.216 2.137 ;
     RECT  103.2 1.715 103.704 2.137 ;
     RECT  106.032 1.139 106.056 2.137 ;
     RECT  107.04 1.139 131.688 2.137 ;
     RECT  132.672 0.563 139.752 2.137 ;
     RECT  141.024 1.763 184.392 2.137 ;
     RECT  205.104 2.051 210.612 2.137 ;
     RECT  2.4 2.137 2.52 2.151 ;
     RECT  34.464 2.137 72.72 2.151 ;
     RECT  73.728 1.187 83.52 2.151 ;
     RECT  215.7 2.137 215.82 2.151 ;
     RECT  4.656 1.955 11.208 2.195 ;
     RECT  14.88 1.763 33.48 2.195 ;
     RECT  107.04 2.137 184.392 2.291 ;
     RECT  185.856 1.763 187.416 2.291 ;
     RECT  188.7 1.763 197.256 2.291 ;
     RECT  204.9 2.137 210.612 2.291 ;
     RECT  211.632 1.763 211.8 2.291 ;
     RECT  14.88 2.195 22.104 2.339 ;
     RECT  23.232 2.195 33.48 2.339 ;
     RECT  180.192 2.291 184.392 2.339 ;
     RECT  211.776 2.291 211.8 2.339 ;
     RECT  115.296 2.291 138.744 2.531 ;
     RECT  4.656 2.195 6.216 2.579 ;
     RECT  118.32 2.531 138.744 2.579 ;
     RECT  180.336 2.339 184.392 2.579 ;
     RECT  21.12 2.339 22.104 2.627 ;
     RECT  180.6 2.579 184.392 2.627 ;
     RECT  118.32 2.579 135.012 2.819 ;
     RECT  182.544 2.627 184.392 2.819 ;
     RECT  136.368 2.579 138.744 2.867 ;
     RECT  14.88 2.339 20.088 2.915 ;
     RECT  190.56 2.291 197.256 2.915 ;
     RECT  23.904 2.339 33.48 3.011 ;
     RECT  23.904 3.011 33.288 3.107 ;
     RECT  17.904 2.915 20.088 3.155 ;
     RECT  96.672 2.137 103.704 3.155 ;
     RECT  107.04 2.291 114.312 3.251 ;
     RECT  23.904 3.107 24.456 3.347 ;
     RECT  99.312 3.155 103.704 3.395 ;
     RECT  204.9 2.291 208.824 3.395 ;
     RECT  7.344 2.195 11.208 3.443 ;
     RECT  21.168 2.627 22.104 3.443 ;
     RECT  25.728 3.107 33.288 3.443 ;
     RECT  190.704 2.915 191.928 3.443 ;
     RECT  192.912 2.915 197.256 3.443 ;
     RECT  204.9 3.395 205.8 3.443 ;
     RECT  207.264 3.395 208.824 3.443 ;
     RECT  107.04 3.251 108.984 3.635 ;
     RECT  186 2.291 187.416 3.635 ;
     RECT  180.6 2.627 181.56 3.683 ;
     RECT  193.392 3.443 195.768 3.683 ;
     RECT  118.32 2.819 129.864 3.875 ;
     RECT  26.064 3.443 33.288 3.923 ;
     RECT  88.8 2.137 95.16 3.923 ;
     RECT  191.232 3.443 191.928 3.923 ;
     RECT  22.8 3.829 22.824 3.971 ;
     RECT  191.232 3.923 191.712 4.019 ;
     RECT  198.576 1.715 203.64 4.019 ;
     RECT  207.6 3.443 208.824 4.019 ;
     RECT  21.168 3.443 21.612 4.163 ;
     RECT  99.6 3.395 103.704 4.163 ;
     RECT  183.168 2.819 184.392 4.163 ;
     RECT  29.088 3.923 33.288 4.211 ;
     RECT  107.04 3.635 108.216 4.259 ;
     RECT  118.5 3.875 129.864 4.451 ;
     RECT  139.728 2.291 179.208 4.451 ;
     RECT  193.392 3.683 194.412 4.451 ;
     RECT  183.168 4.163 183.72 4.499 ;
     RECT  26.064 3.923 27.96 4.547 ;
     RECT  136.368 2.867 138.552 4.547 ;
     RECT  139.728 4.451 179.016 4.547 ;
     RECT  196.8 3.443 197.256 4.547 ;
     RECT  198.576 4.019 200.424 4.547 ;
     RECT  202.2 4.019 203.64 4.547 ;
     RECT  207.6 4.019 208.488 4.547 ;
     RECT  210.096 2.291 210.612 4.595 ;
     RECT  26.064 4.547 27.768 4.739 ;
     RECT  187.392 3.635 187.416 4.739 ;
     RECT  115.296 2.531 117.144 4.883 ;
     RECT  118.5 4.451 129.612 4.979 ;
     RECT  110.4 3.251 114.312 5.075 ;
     RECT  139.728 4.547 176.856 5.123 ;
     RECT  7.344 3.443 8.376 5.171 ;
     RECT  23.904 3.347 24.408 5.171 ;
     RECT  12.384 2.003 13.512 5.173 ;
     RECT  14.88 2.915 16.92 5.173 ;
     RECT  18.6 3.155 20.088 5.173 ;
     RECT  12.384 5.173 16.92 5.219 ;
     RECT  23.904 5.171 24.312 5.219 ;
     RECT  130.848 2.819 135.012 5.219 ;
     RECT  183.168 4.499 183.612 5.221 ;
     RECT  12.72 5.219 16.344 5.267 ;
     RECT  137.04 4.547 138.552 5.267 ;
     RECT  13.2 5.267 16.344 5.315 ;
     RECT  103.68 4.163 103.704 5.315 ;
     RECT  182.4 5.221 183.612 5.363 ;
     RECT  10.32 3.443 11.208 5.507 ;
     RECT  18.384 5.173 20.088 5.507 ;
     RECT  118.5 4.979 122.664 5.507 ;
     RECT  172.368 5.123 176.856 5.507 ;
     RECT  13.2 5.315 14.472 5.555 ;
     RECT  96.672 3.155 97.704 5.555 ;
     RECT  195.744 3.683 195.768 5.555 ;
     RECT  26.4 4.739 27.768 5.603 ;
     RECT  172.368 5.507 174.024 5.699 ;
     RECT  10.5 5.507 11.208 5.747 ;
     RECT  26.4 5.603 27.012 5.795 ;
     RECT  117.12 4.883 117.144 5.795 ;
     RECT  29.184 4.211 33.288 5.843 ;
     RECT  134.016 5.219 135.012 5.891 ;
     RECT  29.232 5.843 33.288 6.035 ;
     RECT  137.04 5.267 138.216 6.035 ;
     RECT  175.104 5.507 176.856 6.035 ;
     RECT  118.5 5.507 121.656 6.083 ;
     RECT  172.368 5.699 173.496 6.275 ;
     RECT  175.104 6.035 176.712 6.275 ;
     RECT  18.6 5.507 20.088 6.323 ;
     RECT  29.232 6.035 33.144 6.323 ;
     RECT  199.248 4.547 199.812 6.323 ;
     RECT  34.464 2.151 83.712 6.371 ;
     RECT  29.232 6.323 32.412 6.419 ;
     RECT  130.848 5.219 132.888 6.419 ;
     RECT  120.816 6.083 121.656 6.467 ;
     RECT  91.5 3.923 95.16 6.611 ;
     RECT  99.6 4.163 102.612 6.611 ;
     RECT  107.04 4.259 108.012 6.659 ;
     RECT  134.208 5.891 135.012 6.707 ;
     RECT  123.792 4.979 129.612 6.851 ;
     RECT  172.5 6.275 173.496 6.851 ;
     RECT  188.7 2.291 189.576 6.851 ;
     RECT  203.616 4.547 203.64 6.851 ;
     RECT  123.9 6.851 129.612 6.853 ;
     RECT  130.848 6.419 130.872 6.853 ;
     RECT  137.4 6.035 138.216 6.853 ;
     RECT  18.6 6.323 19.272 6.899 ;
     RECT  123.9 6.853 130.872 7.043 ;
     RECT  120.96 6.467 121.656 7.091 ;
     RECT  29.232 6.419 29.712 7.187 ;
     RECT  121.2 7.091 121.656 7.285 ;
     RECT  122.64 5.507 122.664 7.285 ;
     RECT  121.2 7.285 122.664 7.331 ;
     RECT  139.728 5.123 171.192 7.475 ;
     RECT  123.9 7.043 129.612 7.523 ;
     RECT  105 2.137 106.056 7.669 ;
     RECT  139.728 7.475 159.96 7.715 ;
     RECT  125.328 7.523 129.612 7.763 ;
     RECT  137.4 6.853 138.648 7.763 ;
     RECT  105 7.669 106.632 7.811 ;
     RECT  112.128 5.075 114.312 7.955 ;
     RECT  121.2 7.331 122.568 7.955 ;
     RECT  96.672 5.555 97.416 8.051 ;
     RECT  7.344 5.171 8.112 8.195 ;
     RECT  92.832 6.611 95.16 8.195 ;
     RECT  102.192 6.611 102.612 8.195 ;
     RECT  134.352 6.707 135.012 8.195 ;
     RECT  31.248 6.419 32.412 8.243 ;
     RECT  118.5 6.083 119.64 8.341 ;
     RECT  93.504 8.195 95.16 8.483 ;
     RECT  132 6.419 132.888 8.483 ;
     RECT  137.4 7.763 138.552 8.483 ;
     RECT  118.5 8.341 119.736 8.531 ;
     RECT  121.2 7.955 121.896 8.531 ;
     RECT  128.16 7.763 129.612 8.533 ;
     RECT  5.1 2.579 6.216 8.579 ;
     RECT  34.608 6.371 83.712 8.579 ;
     RECT  99.6 6.611 101.208 8.579 ;
     RECT  112.272 7.955 114.312 8.627 ;
     RECT  125.328 7.763 126.912 8.627 ;
     RECT  112.464 8.627 114.312 8.675 ;
     RECT  137.4 8.483 138.216 8.675 ;
     RECT  160.944 7.475 171.192 8.675 ;
     RECT  24 5.219 24.312 8.677 ;
     RECT  99.6 8.579 100.344 8.771 ;
     RECT  23.904 8.677 24.312 8.819 ;
     RECT  88.8 3.923 90.504 8.819 ;
     RECT  112.464 8.675 114.12 8.867 ;
     RECT  160.944 8.675 162.504 8.867 ;
     RECT  107.7 6.659 108.012 9.013 ;
     RECT  115.296 4.883 116.112 9.109 ;
     RECT  107.376 9.013 108.012 9.155 ;
     RECT  128.16 8.533 129.768 9.157 ;
     RECT  130.848 7.043 130.872 9.157 ;
     RECT  128.16 9.157 130.872 9.203 ;
     RECT  105 7.811 106.056 9.301 ;
     RECT  34.608 8.579 46.008 9.347 ;
     RECT  128.16 9.203 130.584 9.347 ;
     RECT  46.992 8.579 83.712 9.395 ;
     RECT  50.16 9.395 83.712 9.491 ;
     RECT  115.296 9.109 116.232 9.493 ;
     RECT  34.8 9.347 46.008 9.539 ;
     RECT  34.8 9.539 36.12 9.587 ;
     RECT  160.944 8.867 162.312 9.587 ;
     RECT  122.688 9.493 122.712 9.589 ;
     RECT  36.096 9.587 36.12 9.635 ;
     RECT  52.656 9.491 81.012 9.635 ;
     RECT  115.296 9.493 116.328 9.635 ;
     RECT  134.592 8.195 135.012 9.635 ;
     RECT  122.592 9.589 122.712 9.731 ;
     RECT  37.5 9.539 46.008 9.781 ;
     RECT  46.992 9.395 49.128 9.781 ;
     RECT  37.5 9.781 49.128 9.923 ;
     RECT  96.9 8.051 97.416 10.067 ;
     RECT  37.5 9.923 46.008 10.115 ;
     RECT  128.16 9.347 129.72 10.163 ;
     RECT  96.9 10.067 97.368 10.211 ;
     RECT  163.776 8.675 171.192 10.211 ;
     RECT  82.128 9.491 83.712 10.547 ;
     RECT  104.88 9.301 106.056 10.547 ;
     RECT  112.608 8.867 114.12 10.643 ;
     RECT  177.9 4.547 179.016 10.643 ;
     RECT  52.656 9.635 79.608 10.739 ;
     RECT  115.296 9.635 116.112 10.883 ;
     RECT  128.16 10.163 129.612 10.931 ;
     RECT  84.96 0.563 87.672 10.979 ;
     RECT  175.2 6.275 176.712 11.027 ;
     RECT  80.592 9.635 81.012 11.171 ;
     RECT  177.9 10.643 178.344 11.171 ;
     RECT  163.776 10.211 167.412 11.219 ;
     RECT  39.456 10.115 46.008 11.459 ;
     RECT  128.352 10.931 129.612 11.507 ;
     RECT  52.656 10.739 76.44 11.699 ;
     RECT  50.16 9.491 51.672 11.747 ;
     RECT  115.44 10.883 116.112 11.843 ;
     RECT  52.656 11.699 76.296 11.987 ;
     RECT  105 10.547 106.056 12.181 ;
     RECT  37.5 10.115 38.472 12.275 ;
     RECT  104.88 12.181 106.056 12.515 ;
     RECT  129.3 11.507 129.612 12.517 ;
     RECT  85.632 10.979 87.672 12.563 ;
     RECT  113.1 10.643 114.12 12.755 ;
     RECT  39.456 11.459 45.912 12.803 ;
     RECT  53.7 11.987 76.296 12.803 ;
     RECT  129.3 12.517 130.584 12.853 ;
     RECT  47.136 9.923 49.128 13.043 ;
     RECT  47.136 13.043 49.032 13.139 ;
     RECT  47.136 13.139 48.84 13.187 ;
     RECT  87.648 12.563 87.672 13.187 ;
     RECT  88.8 8.819 89.832 13.235 ;
     RECT  75.3 12.803 76.296 13.283 ;
     RECT  48.3 13.187 48.84 13.331 ;
     RECT  88.8 13.235 89.208 13.331 ;
     RECT  175.2 11.027 175.848 13.379 ;
     RECT  40.2 12.803 45.912 13.427 ;
     RECT  50.16 11.747 51.312 13.427 ;
     RECT  94.2 8.483 95.16 13.427 ;
     RECT  163.776 11.219 166.008 13.427 ;
     RECT  125.328 8.627 125.352 13.475 ;
     RECT  41.616 13.427 45.912 13.619 ;
     RECT  85.632 12.563 86.664 13.669 ;
     RECT  129.3 12.853 130.632 13.669 ;
     RECT  137.4 8.675 138.072 13.669 ;
     RECT  160.944 9.587 162.012 13.715 ;
     RECT  85.632 13.669 86.712 13.811 ;
     RECT  53.7 12.803 74.088 13.907 ;
     RECT  129.3 13.669 130.68 13.907 ;
     RECT  137.4 13.669 138.648 13.907 ;
     RECT  77.424 10.739 79.608 13.955 ;
     RECT  168.816 10.211 171.192 13.955 ;
     RECT  53.7 13.907 73.752 14.147 ;
     RECT  53.7 14.147 72.912 14.435 ;
     RECT  91.5 6.611 91.812 14.437 ;
     RECT  118.5 8.531 118.812 14.437 ;
     RECT  42.288 13.619 45.912 14.531 ;
     RECT  113.1 12.755 113.976 14.533 ;
     RECT  90.624 14.437 91.812 14.579 ;
     RECT  99.6 8.771 99.912 14.581 ;
     RECT  113.1 14.533 114.6 14.581 ;
     RECT  110.4 5.075 111.144 14.627 ;
     RECT  122.544 14.581 122.568 14.629 ;
     RECT  47.136 13.187 47.16 14.675 ;
     RECT  113.1 14.581 114.696 14.675 ;
     RECT  118.176 14.437 118.812 14.675 ;
     RECT  114.672 14.675 114.696 14.677 ;
     RECT  68.544 14.435 72.912 14.723 ;
     RECT  98.64 14.581 99.912 14.723 ;
     RECT  129.3 13.907 130.584 14.723 ;
     RECT  123.9 7.523 124.212 14.725 ;
     RECT  113.1 14.675 113.688 14.771 ;
     RECT  114.672 14.677 114.792 14.771 ;
     RECT  118.272 14.675 118.812 14.771 ;
     RECT  122.544 14.629 122.664 14.771 ;
     RECT  129.3 14.723 130.008 14.771 ;
     RECT  114.768 14.771 114.792 14.819 ;
     RECT  123.696 14.725 124.212 14.867 ;
     RECT  85.632 13.811 86.664 14.963 ;
     RECT  77.424 13.955 79.128 15.011 ;
     RECT  45.168 14.531 45.912 15.059 ;
     RECT  72.096 14.723 72.912 15.059 ;
     RECT  113.1 14.771 113.412 15.157 ;
     RECT  53.7 14.435 67.512 15.299 ;
     RECT  112.848 15.157 113.412 15.299 ;
     RECT  139.728 7.715 159.624 15.299 ;
     RECT  137.4 13.907 138.072 15.541 ;
     RECT  42.288 14.531 44.184 15.587 ;
     RECT  163.776 13.427 165.816 15.587 ;
     RECT  163.776 15.587 164.712 15.779 ;
     RECT  137.4 15.541 138.552 15.827 ;
     RECT  75.3 13.283 75.96 16.019 ;
     RECT  82.608 10.547 83.712 16.019 ;
     RECT  77.76 15.011 79.128 16.115 ;
     RECT  114.672 15.973 114.696 16.261 ;
     RECT  114.576 16.261 114.696 16.307 ;
     RECT  114.576 16.307 114.6 16.451 ;
     RECT  122.544 14.771 122.568 16.451 ;
     RECT  77.76 16.115 78.312 16.595 ;
     RECT  161.568 13.715 162.012 16.643 ;
     RECT  165.792 15.587 165.816 16.835 ;
     RECT  42.48 15.587 44.184 16.883 ;
     RECT  139.728 15.299 153.912 16.883 ;
     RECT  168.816 13.955 170.112 16.883 ;
     RECT  96.9 10.211 97.212 16.885 ;
     RECT  86.1 14.963 86.664 16.931 ;
     RECT  53.7 15.299 54.312 17.027 ;
     RECT  96.768 16.885 97.212 17.123 ;
     RECT  68.544 14.723 71.112 17.171 ;
     RECT  129.3 14.771 129.612 17.173 ;
     RECT  42.9 16.883 44.184 17.219 ;
     RECT  92.784 17.077 92.808 17.219 ;
     RECT  171.168 13.955 171.192 17.219 ;
     RECT  55.536 15.299 67.512 17.411 ;
     RECT  129.3 17.173 130.584 17.459 ;
     RECT  139.728 16.883 152.28 17.459 ;
     RECT  63.36 17.411 67.512 17.507 ;
     RECT  107.7 9.155 108.012 17.509 ;
     RECT  109.152 12.277 109.176 17.509 ;
     RECT  55.536 17.411 62.376 17.651 ;
     RECT  107.7 17.509 109.176 17.651 ;
     RECT  154.944 15.299 159.624 17.651 ;
     RECT  158.256 17.651 159.624 17.699 ;
     RECT  63.36 17.507 66.072 17.747 ;
     RECT  158.256 17.699 159.312 17.747 ;
     RECT  139.728 17.459 152.088 18.035 ;
     RECT  56.016 17.651 62.376 18.179 ;
     RECT  63.36 17.747 65.928 18.227 ;
     RECT  105 12.515 106.056 18.373 ;
     RECT  113.1 15.299 113.412 18.421 ;
     RECT  121.2 8.531 121.512 18.421 ;
     RECT  121.2 18.421 121.8 18.469 ;
     RECT  69.408 17.171 71.112 18.515 ;
     RECT  121.2 18.469 122.52 18.517 ;
     RECT  129.3 17.459 129.612 18.517 ;
     RECT  52.656 11.987 52.68 18.563 ;
     RECT  63.36 18.227 63.384 18.563 ;
     RECT  105 18.373 106.632 18.563 ;
     RECT  112.992 18.421 113.412 18.563 ;
     RECT  121.2 18.517 122.664 18.563 ;
     RECT  132 8.483 132.696 18.563 ;
     RECT  139.728 18.035 151.608 18.563 ;
     RECT  107.7 17.651 108.012 18.661 ;
     RECT  56.016 18.179 57.528 18.755 ;
     RECT  114.576 18.517 114.696 18.755 ;
     RECT  122.496 18.563 122.664 18.755 ;
     RECT  129.3 18.517 129.912 18.755 ;
     RECT  107.04 18.661 108.012 18.803 ;
     RECT  114.672 18.755 114.696 18.803 ;
     RECT  129.3 18.755 129.816 18.803 ;
     RECT  64.5 18.227 65.928 18.851 ;
     RECT  50.496 13.427 51.312 19.043 ;
     RECT  139.728 18.563 151.32 19.043 ;
     RECT  53.7 17.027 54.216 19.091 ;
     RECT  154.944 17.651 156.744 19.091 ;
     RECT  53.7 19.091 54.12 19.139 ;
     RECT  95.856 18.949 95.88 19.139 ;
     RECT  139.728 19.043 149.928 19.283 ;
     RECT  59.1 18.179 62.376 19.379 ;
     RECT  60.72 19.379 62.376 19.523 ;
     RECT  56.208 18.755 57.528 19.859 ;
     RECT  155.28 19.091 156.744 19.859 ;
     RECT  56.208 19.859 56.712 19.907 ;
     RECT  142.56 19.283 149.928 19.907 ;
     RECT  142.56 19.907 149.448 20.051 ;
     RECT  78 16.595 78.312 20.053 ;
     RECT  86.1 16.931 86.412 20.053 ;
     RECT  60.72 19.523 62.232 20.099 ;
     RECT  60.72 20.099 62.112 20.147 ;
     RECT  155.424 19.859 156.744 20.147 ;
     RECT  86.1 20.053 86.568 20.149 ;
     RECT  96.9 17.123 97.212 20.149 ;
     RECT  118.5 14.771 118.812 20.149 ;
     RECT  142.56 20.051 144.264 20.195 ;
     RECT  145.248 20.051 149.448 20.195 ;
     RECT  91.5 14.579 91.812 20.197 ;
     RECT  78 20.053 78.792 20.339 ;
     RECT  86.1 20.149 86.664 20.339 ;
     RECT  91.5 20.197 92.712 20.339 ;
     RECT  96.768 20.149 97.212 20.339 ;
     RECT  155.424 20.147 156.612 20.339 ;
     RECT  59.1 19.379 59.544 20.387 ;
     RECT  117.744 20.149 118.812 20.387 ;
     RECT  158.88 17.747 159.312 20.387 ;
     RECT  115.8 11.843 116.112 20.389 ;
     RECT  142.56 20.195 143.736 20.435 ;
     RECT  50.544 19.043 51.312 20.627 ;
     RECT  146.88 20.195 149.448 20.627 ;
     RECT  29.4 7.187 29.712 20.629 ;
     RECT  64.5 18.851 65.4 20.723 ;
     RECT  139.728 19.283 141.048 20.773 ;
     RECT  48.3 13.331 48.612 20.821 ;
     RECT  183.3 5.363 183.612 20.821 ;
     RECT  13.2 5.555 13.512 20.869 ;
     RECT  105 18.563 106.056 20.869 ;
     RECT  110.4 14.627 110.712 20.869 ;
     RECT  29.4 20.629 30.264 20.915 ;
     RECT  24 8.819 24.312 20.917 ;
     RECT  180.6 3.683 180.912 20.917 ;
     RECT  182.352 20.821 183.612 20.917 ;
     RECT  84.768 20.677 84.792 20.963 ;
     RECT  180.6 20.917 183.612 20.963 ;
     RECT  7.8 8.195 8.112 20.965 ;
     RECT  15.9 5.315 16.212 20.965 ;
     RECT  18.6 6.899 18.912 20.965 ;
     RECT  29.4 20.915 29.712 20.965 ;
     RECT  45.6 15.059 45.912 20.965 ;
     RECT  48.3 20.821 49.032 20.965 ;
     RECT  55.344 20.917 55.368 20.965 ;
     RECT  56.4 19.907 56.712 20.965 ;
     RECT  123.9 14.867 124.212 20.965 ;
     RECT  134.7 9.635 135.012 20.965 ;
     RECT  137.4 15.827 137.712 20.965 ;
     RECT  138.912 20.773 141.048 20.965 ;
     RECT  202.2 4.547 202.512 20.965 ;
     RECT  204.9 3.443 205.212 20.965 ;
     RECT  207.6 4.547 207.912 20.965 ;
     RECT  104.88 20.869 106.056 21.011 ;
     RECT  32.1 8.243 32.412 21.013 ;
     RECT  51 20.627 51.312 21.013 ;
     RECT  78 20.339 78.312 21.013 ;
     RECT  123.9 20.965 124.536 21.013 ;
     RECT  129.3 18.803 129.612 21.013 ;
     RECT  177.9 11.171 178.212 21.013 ;
     RECT  26.7 5.795 27.012 21.061 ;
     RECT  37.5 12.275 37.812 21.061 ;
     RECT  59.1 20.387 59.412 21.061 ;
     RECT  88.8 13.331 89.112 21.061 ;
     RECT  90.192 20.869 90.216 21.061 ;
     RECT  132 18.563 132.312 21.109 ;
     RECT  145.248 20.195 145.812 21.109 ;
     RECT  153.264 16.883 153.912 21.109 ;
     RECT  155.616 20.339 156.612 21.155 ;
     RECT  75.3 16.019 75.612 21.157 ;
     RECT  96.9 20.339 97.212 21.205 ;
     RECT  147.072 20.627 149.448 21.205 ;
     RECT  150.9 19.043 151.32 21.205 ;
     RECT  152.544 21.109 153.912 21.205 ;
     RECT  169.8 16.883 170.112 21.205 ;
     RECT  129.3 21.013 130.68 21.251 ;
     RECT  42.9 17.219 43.212 21.253 ;
     RECT  58.896 21.061 59.412 21.253 ;
     RECT  67.2 17.507 67.512 21.253 ;
     RECT  110.4 20.869 111.144 21.253 ;
     RECT  137.4 20.965 141.048 21.253 ;
     RECT  88.8 21.061 90.216 21.299 ;
     RECT  147.072 21.205 153.912 21.299 ;
     RECT  91.5 20.339 91.812 21.301 ;
     RECT  91.152 21.301 91.812 21.349 ;
     RECT  132 21.109 132.504 21.349 ;
     RECT  136.8 21.253 141.048 21.395 ;
     RECT  142.56 20.435 143.256 21.397 ;
     RECT  144.768 21.109 145.812 21.397 ;
     RECT  15.9 20.965 16.584 21.443 ;
     RECT  28.704 20.965 29.712 21.443 ;
     RECT  110.4 21.253 111.24 21.443 ;
     RECT  169.8 21.205 170.904 21.443 ;
     RECT  201.936 20.965 202.512 21.443 ;
     RECT  5.1 8.579 5.412 21.445 ;
     RECT  115.152 20.389 116.112 21.445 ;
     RECT  123.9 21.013 124.632 21.445 ;
     RECT  110.4 21.443 111.144 21.491 ;
     RECT  153.264 21.299 153.912 21.493 ;
     RECT  51 21.013 52.248 21.539 ;
     RECT  142.56 21.397 145.812 21.539 ;
     RECT  10.5 5.747 10.812 21.541 ;
     RECT  69.744 18.515 71.112 21.541 ;
     RECT  77.28 21.013 78.312 21.541 ;
     RECT  80.7 11.171 81.012 21.541 ;
     RECT  88.8 21.299 89.544 21.541 ;
     RECT  123.072 21.445 124.632 21.541 ;
     RECT  126.6 8.627 126.912 21.541 ;
     RECT  159 20.387 159.312 21.541 ;
     RECT  42.096 21.253 43.212 21.589 ;
     RECT  44.832 20.965 45.912 21.589 ;
     RECT  72.6 15.059 72.912 21.589 ;
     RECT  31.872 21.013 32.412 21.637 ;
     RECT  48.3 20.965 49.944 21.637 ;
     RECT  51 21.539 51.312 21.637 ;
     RECT  64.5 20.723 64.812 21.637 ;
     RECT  66.24 21.253 67.512 21.637 ;
     RECT  102.3 8.195 102.612 21.637 ;
     RECT  132 21.349 132.84 21.637 ;
     RECT  161.7 16.643 162.012 21.637 ;
     RECT  163.392 21.061 163.416 21.637 ;
     RECT  164.4 15.779 164.712 21.637 ;
     RECT  69.216 21.541 71.352 21.733 ;
     RECT  72.336 21.589 72.912 21.733 ;
     RECT  137.4 21.395 141.048 21.779 ;
     RECT  160.32 21.157 160.344 21.779 ;
     RECT  55.344 20.965 56.712 21.781 ;
     RECT  75.3 21.157 76.104 21.781 ;
     RECT  77.28 21.541 78.6 21.781 ;
     RECT  101.856 21.637 102.612 21.781 ;
     RECT  107.7 18.803 108.012 21.781 ;
     RECT  101.712 21.781 102.612 21.829 ;
     RECT  69.216 21.733 72.912 21.875 ;
     RECT  91.152 21.349 91.944 21.925 ;
     RECT  94.2 13.427 94.512 21.925 ;
     RECT  96.9 21.205 97.32 21.925 ;
     RECT  99.6 14.723 99.912 21.925 ;
     RECT  101.712 21.829 102.744 21.925 ;
     RECT  131.568 21.637 132.84 21.971 ;
     RECT  147.072 21.299 152.04 21.971 ;
     RECT  177.9 21.013 179.16 21.971 ;
     RECT  107.136 21.781 108.012 22.021 ;
     RECT  109.152 17.651 109.176 22.021 ;
     RECT  99.6 21.925 100.152 22.069 ;
     RECT  129.3 21.251 129.612 22.117 ;
     RECT  42.096 21.589 45.912 22.165 ;
     RECT  123.072 21.541 124.824 22.213 ;
     RECT  101.52 21.925 102.936 22.259 ;
     RECT  96.24 21.925 97.752 22.261 ;
     RECT  134.592 20.965 135.012 22.261 ;
     RECT  31.872 21.637 33.048 22.307 ;
     RECT  94.2 21.925 94.872 22.307 ;
     RECT  96.24 22.261 97.896 22.307 ;
     RECT  99.072 22.069 100.152 22.307 ;
     RECT  128.784 22.117 129.612 22.307 ;
     RECT  147.072 21.971 149.448 22.307 ;
     RECT  60.816 20.147 62.112 22.357 ;
     RECT  91.152 21.925 92.088 22.357 ;
     RECT  93.072 21.541 93.096 22.357 ;
     RECT  21.3 4.163 21.612 22.453 ;
     RECT  26.7 21.061 27.432 22.499 ;
     RECT  55.344 21.781 57.48 22.499 ;
     RECT  137.4 21.779 140.412 22.499 ;
     RECT  47.472 21.637 51.312 22.501 ;
     RECT  42.096 22.165 46.104 22.547 ;
     RECT  96.384 22.307 97.896 22.547 ;
     RECT  137.4 22.499 139.032 22.549 ;
     RECT  96.9 22.547 97.896 22.595 ;
     RECT  107.136 22.021 109.176 22.597 ;
     RECT  5.1 21.445 5.928 22.645 ;
     RECT  71.328 21.875 72.912 22.693 ;
     RECT  101.52 22.259 102.612 22.693 ;
     RECT  91.152 22.357 93.096 22.739 ;
     RECT  107.04 22.597 109.176 22.739 ;
     RECT  111.984 22.501 112.008 22.739 ;
     RECT  110.4 21.491 110.808 23.029 ;
     RECT  71.328 22.693 73.368 23.125 ;
     RECT  7.8 20.965 8.376 23.365 ;
     RECT  10.224 21.541 10.812 23.365 ;
     RECT  13.2 20.869 13.992 23.365 ;
     RECT  15.9 21.443 16.212 23.365 ;
     RECT  18.6 20.965 19.368 23.365 ;
     RECT  21.3 22.453 22.2 23.365 ;
     RECT  24 20.917 25.032 23.365 ;
     RECT  29.4 21.443 29.712 23.365 ;
     RECT  31.872 22.307 32.412 23.365 ;
     RECT  34.8 9.587 35.112 23.365 ;
     RECT  37.5 21.061 38.184 23.365 ;
     RECT  40.2 13.427 40.512 23.365 ;
     RECT  42.096 22.547 43.896 23.365 ;
     RECT  45.072 22.547 46.104 23.365 ;
     RECT  47.472 22.501 51.672 23.365 ;
     RECT  53.7 19.139 54.012 23.365 ;
     RECT  55.344 22.499 55.416 23.365 ;
     RECT  75.3 21.781 78.6 23.365 ;
     RECT  86.1 20.339 86.412 23.365 ;
     RECT  104.88 21.011 105.312 23.365 ;
     RECT  110.4 23.029 110.904 23.365 ;
     RECT  134.544 22.261 135.012 23.365 ;
     RECT  147.792 22.307 149.448 23.365 ;
     RECT  150.432 21.971 151.212 23.365 ;
     RECT  158.736 21.541 159.312 23.365 ;
     RECT  161.7 21.637 162.12 23.365 ;
     RECT  163.392 21.637 164.712 23.365 ;
     RECT  167.1 11.219 167.412 23.365 ;
     RECT  172.5 6.851 172.812 23.365 ;
     RECT  175.2 13.379 175.512 23.365 ;
     RECT  177.9 21.971 178.212 23.365 ;
     RECT  180.6 20.963 181.848 23.365 ;
     RECT  183.3 20.963 183.612 23.365 ;
     RECT  186 3.635 186.312 23.365 ;
     RECT  188.7 6.851 189.012 23.365 ;
     RECT  190.32 20.869 190.344 23.365 ;
     RECT  191.4 4.019 191.712 23.365 ;
     RECT  192.72 21.013 192.744 23.365 ;
     RECT  196.8 4.547 197.112 23.365 ;
     RECT  198.336 21.253 198.36 23.365 ;
     RECT  199.5 6.323 199.812 23.365 ;
     RECT  202.2 21.443 202.512 23.365 ;
     RECT  204.432 20.965 205.212 23.365 ;
     RECT  207.456 20.965 207.912 23.365 ;
     RECT  210.3 4.595 210.612 23.365 ;
     RECT  213 1.763 213.312 23.365 ;
     RECT  4.512 22.645 5.928 23.413 ;
     RECT  7.536 23.365 14.232 23.413 ;
     RECT  15.216 23.365 16.584 23.413 ;
     RECT  192.72 23.365 192.888 23.413 ;
     RECT  194.1 4.451 194.412 23.413 ;
     RECT  4.512 23.413 6.552 23.701 ;
     RECT  7.536 23.413 16.584 23.701 ;
     RECT  17.568 23.365 19.944 23.701 ;
     RECT  20.928 23.365 25.32 23.701 ;
     RECT  26.7 22.499 27.336 23.701 ;
     RECT  28.656 23.365 32.412 23.701 ;
     RECT  34.656 23.365 35.352 23.701 ;
     RECT  36.672 23.365 38.184 23.701 ;
     RECT  40.2 23.365 43.896 23.701 ;
     RECT  45.072 23.365 46.44 23.701 ;
     RECT  47.472 23.365 52.104 23.701 ;
     RECT  53.7 23.365 55.416 23.701 ;
     RECT  56.4 22.499 57.48 23.701 ;
     RECT  58.512 21.253 59.412 23.701 ;
     RECT  60.816 22.357 62.28 23.701 ;
     RECT  63.552 21.637 64.812 23.701 ;
     RECT  66.24 21.637 67.8 23.701 ;
     RECT  69.216 21.875 70.212 23.701 ;
     RECT  71.328 23.125 73.56 23.701 ;
     RECT  75.3 23.365 79.272 23.701 ;
     RECT  80.352 21.541 81.012 23.701 ;
     RECT  83.4 16.019 83.712 23.701 ;
     RECT  86.1 23.365 86.952 23.701 ;
     RECT  88.032 21.541 89.544 23.701 ;
     RECT  91.152 22.739 91.812 23.701 ;
     RECT  93.072 22.739 93.096 23.701 ;
     RECT  94.2 22.307 94.512 23.701 ;
     RECT  96.9 22.595 97.32 23.701 ;
     RECT  99.072 22.307 100.008 23.701 ;
     RECT  101.376 22.693 102.612 23.701 ;
     RECT  104.688 23.365 105.312 23.701 ;
     RECT  107.136 22.739 109.176 23.701 ;
     RECT  110.4 23.365 111.096 23.701 ;
     RECT  113.1 18.563 113.412 23.701 ;
     RECT  115.008 21.445 116.112 23.701 ;
     RECT  118.5 20.387 118.812 23.701 ;
     RECT  121.2 18.563 121.512 23.701 ;
     RECT  122.832 22.213 124.824 23.701 ;
     RECT  126.6 21.541 127.8 23.701 ;
     RECT  129.168 22.307 129.612 23.701 ;
     RECT  131.568 21.971 132.792 23.701 ;
     RECT  134.544 23.365 135.24 23.701 ;
     RECT  136.848 22.549 139.032 23.701 ;
     RECT  140.1 22.499 140.412 23.701 ;
     RECT  142.56 21.539 143.976 23.701 ;
     RECT  145.5 21.539 145.812 23.701 ;
     RECT  147.792 23.365 151.212 23.701 ;
     RECT  153.264 21.493 154.68 23.701 ;
     RECT  156.048 21.155 156.612 23.701 ;
     RECT  157.68 23.365 159.312 23.701 ;
     RECT  160.992 23.365 164.712 23.701 ;
     RECT  165.696 23.365 167.412 23.701 ;
     RECT  168.384 23.365 168.744 23.701 ;
     RECT  169.8 21.443 170.112 23.701 ;
     RECT  171.408 23.365 172.812 23.701 ;
     RECT  175.2 23.365 176.808 23.701 ;
     RECT  177.792 23.365 178.212 23.701 ;
     RECT  179.424 23.365 183.816 23.701 ;
     RECT  185.808 23.365 191.712 23.701 ;
     RECT  192.72 23.413 194.412 23.701 ;
     RECT  195.552 23.365 195.576 23.701 ;
     RECT  196.56 23.365 197.208 23.701 ;
     RECT  198.192 23.365 199.812 23.701 ;
     RECT  200.88 23.365 206.28 23.701 ;
     RECT  207.456 23.365 208.632 23.701 ;
     RECT  209.952 23.365 213.672 23.701 ;
     RECT  2.4 2.151 2.712 23.769 ;
     RECT  215.7 2.151 216.012 23.769 ;
     RECT  2.4 23.769 2.52 23.783 ;
     RECT  215.7 23.769 215.82 23.783 ;
     RECT  4.512 23.701 25.656 23.893 ;
     RECT  26.7 23.701 213.672 23.893 ;
     RECT  4.512 23.893 213.672 25.744 ;
  END
END hbfd_rly_624_NS_fc_f2
END LIBRARY
